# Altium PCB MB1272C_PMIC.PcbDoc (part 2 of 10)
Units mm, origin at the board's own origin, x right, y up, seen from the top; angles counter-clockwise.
Board outline 101 x 71 mm, 6 copper layers (Top Layer, Signal Layer 1, Signal Layer 2, Signal Layer 3, Signal Layer 4, Bottom Layer), stack 1.552 mm thick; 518 components, 478 nets, 2152 pads, 1871 vias.
Unrouted connection lines stored in the file: 3.

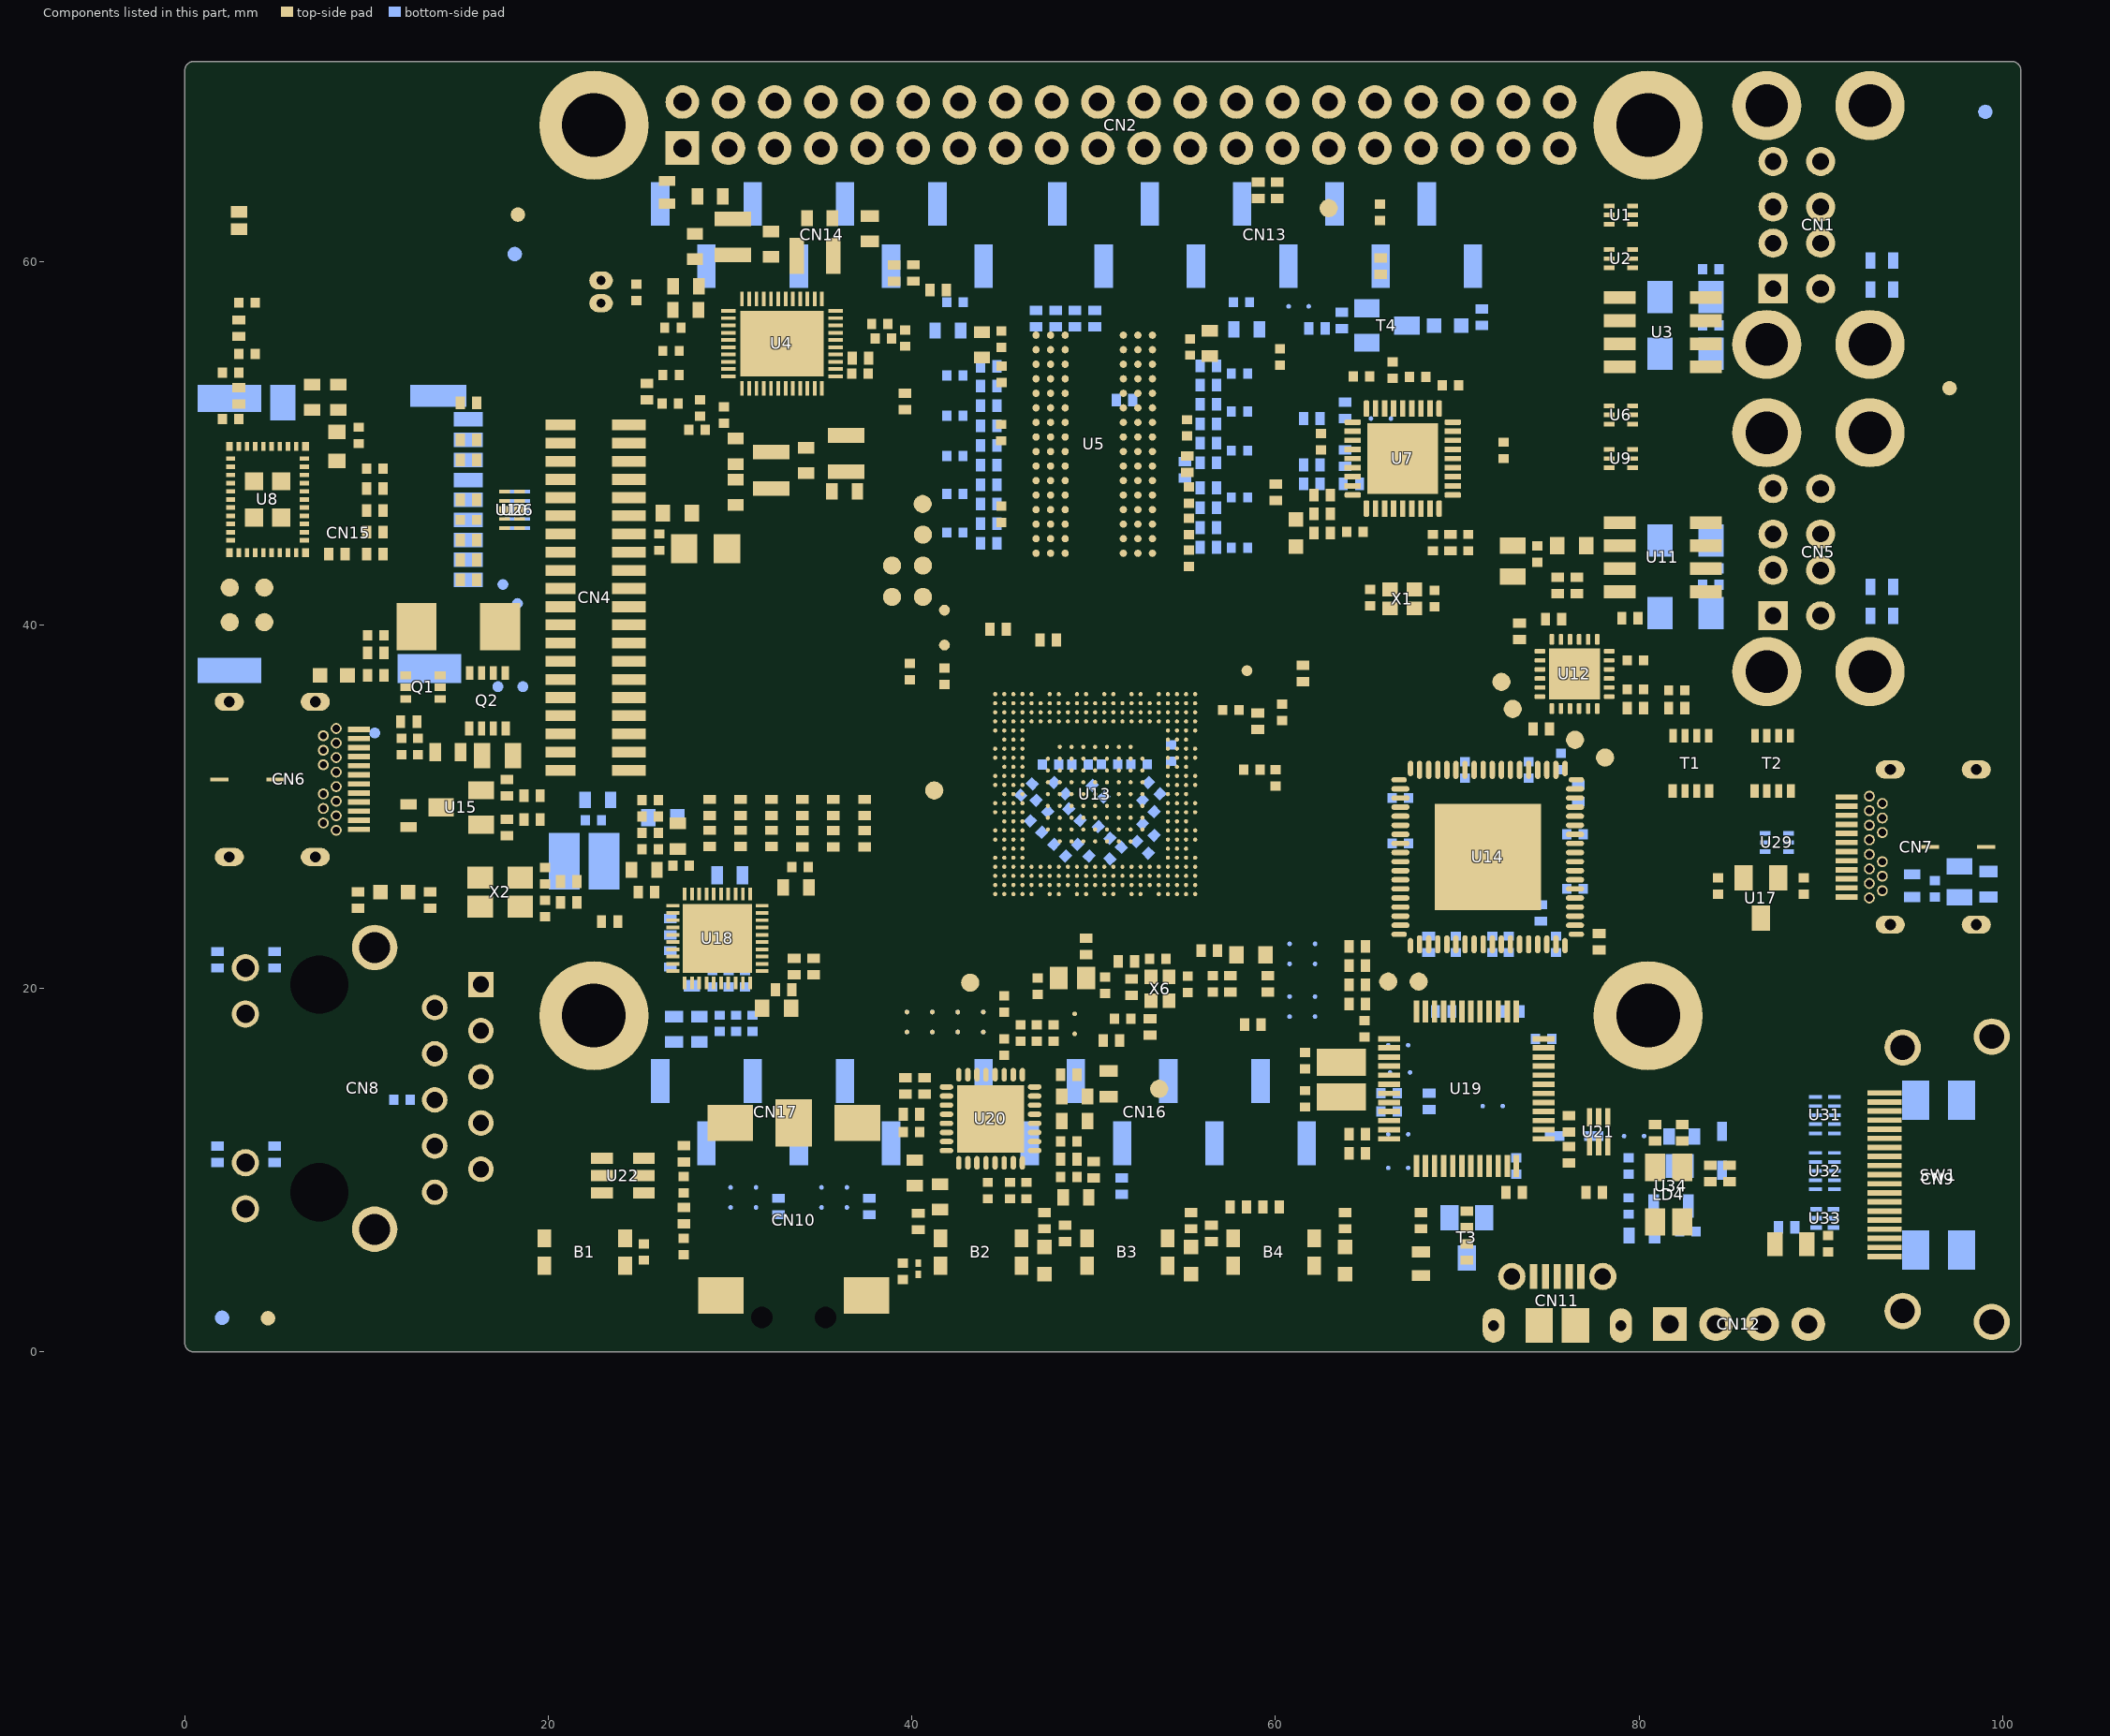
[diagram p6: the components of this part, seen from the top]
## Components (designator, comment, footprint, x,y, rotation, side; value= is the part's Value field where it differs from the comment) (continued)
U1 "​" ESD_QFN-6L_1P7X1P5_P050 79,62.55 r270 top value=ECMF02-2AMX6
U2 "​" ESD_QFN-6L_1P7X1P5_P050 79,60.15 r270 top value=ECMF02-2AMX6
U3 "STMPS2252MTR" ICC_SO8_5X4_P127 81.3,56.1 r270 top
U4 "STPMU1A" ICC_WFQFN44-EPAD_5X6_P040 32.85,55.475 r270 top
U5 "MT41K256M16TW-107:P - V00H" ICC_FBGA96_8X14_P080 50.03,49.94 r0 top locked value=MT41K256M16TW-107-P-V00H
U6 "​" ESD_QFN-6L_1P7X1P5_P050 79,51.55 r270 top value=ECMF02-2AMX6
U7 "USB2514B-AEZC" ICC_QFN36-EPAD_6X6_P050 67,49.15 r90 top
U8 "LBEE5KL1DX-883" MOD_WLAN-BT_MURATA_LBEE5KL1DX-883 4.55,46.9 r270 top locked
U9 "​" ESD_QFN-6L_1P7X1P5_P050 79,49.15 r270 top value=ECMF02-2AMX6
U10 "HSP051-4M10" ESD_UQFN-10L_2P5X1_P050 18,46.325 r90 top
U11 "STMPS2252MTR" ICC_SO8_5X4_P127 81.3,43.725 r270 top
U12 "​Symbol correction needed ?" ICC_QFN24-EPAD_4X4_P050 76.45,37.3 r270 top value=STUSB1600
U13 "STM32MP157CAC3" ICC_TFBGA361_12X12_STM32MP157CAC3_P050-065 50.08,30.69 r90 top locked
U14 "" ICC_QFN72-EPAD_10X10_P050 71.675,27.225 r270 top locked value=SiI9022ACNU
U15 "New schematic symbol : correction 2 diodes instead of one" ESD_SOT23 15.2,29.95 r90 top value=ESDA25L
U16 "​Footprint needed DFN105P160X60-2N" ESD_QFN1610_2N_1K_2A 12.3,29.5 r270 top value=ESDA7P120-1U1M
U17 "New schematic symbol : correction 2 diodes instead of one" ESD_SOT23 86.7,24.975 r180 top value=ESDA25L
U18 "RTL8211F-CG" ICC_QFN40-EPAD_5X5_P040 29.3,22.75 r90 top locked
U19 "" ICC_LQFP48_7X7_P050 70.5,14.475 r270 top locked value=STM32F103CBT6
U20 "" ICC_QFN32-EPAD_5X5_P050 44.325,12.825 r270 top value=CS42L51-CNZ
U21 "" ESD_SOT666 77.775,12.1 r0 top value=USBLC6-2P6
U22 "" ESD_SOT23-6L 24.1,9.7 r90 top value=ESDA6V1BC6
U23 "​Footprint needed DFN105P160X60-2N" ESD_QFN1610_2N_1K_2A 26.525,63.8 r270 top value=ESDA7P120-1U1M
U24 "​Footprint needed DFN105P160X60-2N" ESD_QFN1610_2N_1K_2A 93.35,60.05 r0 bottom value=ESDA7P120-1U1M
U25 "​Footprint needed DFN105P160X60-2N" ESD_QFN1610_2N_1K_2A 93.35,58.45 r0 bottom value=ESDA7P120-1U1M
U26 "HSP051-4M10" ESD_UQFN-10L_2P5X1_P050 18.3,46.325 r90 bottom
U27 "​Footprint needed DFN105P160X60-2N" ESD_QFN1610_2N_1K_2A 93.35,42.1 r0 bottom value=ESDA7P120-1U1M
U28 "​Footprint needed DFN105P160X60-2N" ESD_QFN1610_2N_1K_2A 93.35,40.5 r0 bottom value=ESDA7P120-1U1M
U29 "​" ESD_QFN-6L_1P7X1P5_P050 87.575,28.025 r90 bottom value=ECMF02-2AMX6
U30 "​Footprint needed DFN105P160X60-2N" ESD_QFN1610_2N_1K_2A 95.025,25.65 r90 bottom value=ESDA7P120-1U1M
U31 "" ESD_UQFN-10L_2P60X1P35_P050 90.225,13.025 r270 bottom value=ECMF04-4HSWM10
U32 "" ESD_UQFN-10L_2P60X1P35_P050 90.225,9.95 r270 bottom value=ECMF04-4HSWM10
U33 "ESDALC6V1-5M6" ESD_UQFN-6L_1P45X1_P050 90.225,7.35 r270 bottom
U34 "" REG_SOT23-5L 81.75,9.125 r0 bottom value=LD3985M33R
U35 "ESD-TRANSIL" ESD_ST0201 40.35,4.575 r270 top value=ESDALC6V1-1U2
X1 "XTAL_4_PINS" CRY_NX2016SA_4P 66.975,41.425 r180 top value="NX2016SA 24MHz"
X2 "XTAL_4_PINS" CRY_NX3225HA_4P 17.35,25.3 r180 top value="NX3225GA 25MHz"
X4 "XTAL_2_PINS" CRY_NX2012SA_2P 48.825,20.575 r0 top value="NX2012SA 32.768KHz"
X5 "" CRY_NX3225GD_2P 63.625,14.975 r90 top value="NX3225GD 8MHz"
X6 "OSCILLATOR_4_PINS" CRY_NZ2016SH_4P 53.65,19.975 r90 top value="NZ2016SH 24MHz"

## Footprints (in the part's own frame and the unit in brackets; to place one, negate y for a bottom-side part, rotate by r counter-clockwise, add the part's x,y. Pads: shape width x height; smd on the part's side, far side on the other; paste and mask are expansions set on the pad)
C0402 [mm]
  rect 0.51x0.56 smd mask+0.05: 1(-0.45,0) 2(0.45,0)
  silkscreen extent -0.72,-0.35 0.72,0.35, body extent -0.5,-0.3 0.5,0.3, height 0.4
C0603 [mm]
  rect 0.64x0.89 smd mask+0.05: 1(-0.7,0) 2(0.7,0)
  silkscreen extent -1.05,-0.55 1.02,0.55, body extent -0.9,-0.5 0.9,0.5, height 1.4
C0805 [mm]
  rect 0.9x1.4 smd mask+0.05: 1(-0.85,0) 2(0.85,0)
  silkscreen extent -1.3,-0.77 1.3,0.77, body extent -1.1,-0.7 1.1,0.7, height 1.35
C1206_H1P6 [mm]
  rect 1.4x1.78 smd mask+0.05: 1(-1.4,0) 2(1.4,0)
  silkscreen extent -2.12,-0.97 2.15,0.97, body extent -1.7,-0.9 1.7,0.9, height 1.8
CON_DUAL-USB-TYPE-A_CONEXCON_5600-3081 [mm]
  round 1.6 hole 0.92: B1(-3.5,13.01) B2(-1,13.01) B3(1,13.01) B4(3.5,13.01) T2(-1,15.63) T3(1,15.63) T4(3.5,15.63)
  round 3.8 hole 2.33: CH1(6.57,10.3) CH2(-6.57,10.3) CH3(-6.57,15.98) CH4(6.57,15.98)
  rect 1.6x1.6 hole 0.92: T1(-3.5,15.63)
  silkscreen extent -7.3,-0.4 7.3,17.85, body extent -7.83,-0.6 7.87,17.85, height 16.2
CON_HDMI_FCI-AMPHENOL_10029449-001RLF [mm]
  rect 0.3x1.9 smd mask+0.05: 1(4.75,8.5) 2(4.25,8.5) 3(3.75,8.5) 4(3.25,8.5) 5(2.75,8.5) 6(2.25,8.5) 7(1.75,8.5) 8(1.25,8.5) 9(0.75,8.5) 10(0.25,8.5) 11(-0.25,8.5) 12(-0.75,8.5) 13(-1.25,8.5) 14(-1.75,8.5) 15(-2.25,8.5) 16(-2.75,8.5) 17(-3.25,8.5) 18(-3.75,8.5) 19(-4.25,8.5)
  round 2 hole 1.35 mask+0.1: 20(7.25,7.5) 21(-7.25,7.5) 22(7.85,2.6) 23(-7.85,2.6)
  silkscreen extent -7.5,-1 7.5,8, body extent -8.1,-1 8.1,8.9, height 6.3
CON_JACK-3P5-SMT_LUMBERG_1503-13-VP3 [mm]
  rect 2.6x2 smd mask+0.05: 1(15.2,0)
  rect 2x2.5 smd mask+0.05: 2(15.2,3.5) 3(15.2,-3.5) 4(5.7,-4) 4(5.7,4)
  round 0.5 hole 1.2 unplated mask+0.1: NPTH1(4.5,-1.75) NPTH2(4.5,1.75)
  silkscreen extent 0,-3.55 14.6,3.55, body extent 0,-4.55 15.8,4.55, height 6.1
CON_MICROSD_YAMAICHI_PJS008-2003-0 [mm] "WITHOUT POSITIONNING PINS"
  rect 1.6x0.8 smd paste+0 mask+0.05: 1(-15.6,-2.525) 2(-15.6,-1.425) 3(-15.6,-0.325) 4(-15.6,0.775) 5(-15.6,1.875) 6(-15.6,2.975) 7(-15.6,4.075) 8(-15.6,5.175) 9(-15.6,6.325)
  rect 1.4x1.95 smd paste+0 mask+0.05: 10(-5.4,7.225)
  rect 3.5x1.5 smd paste+0 mask+0.05: 11(-2.45,7.45)
  rect 3.5x1.4 smd paste+0 mask+0.05: 12(-2.45,-7.5)
  rect 3.5x1.6 smd paste+0 mask+0.05: 13(-13.45,-7.4)
  rect 3.1x1.2 smd paste+0 mask+0.05: 14(-13.95,7.6)
  silkscreen extent -15.32,-7.25 5.65,7.25, body extent -15.25,-7.25 -0.45,7.42, height 2
CON_MOLEX_53047-0210 [mm]
  oval 1x1.3 hole 0.5 mask+0.05: 1(-0.625,0) 2(0.625,0)
  silkscreen extent -2.12,-1.15 2.13,2.05, body extent -2.13,-1.15 2.13,2.05, height 4.2
CON_RJ45_YD_48F-01GYDXNL_LED-P [mm]
  rect 1.4x1.4 hole 0.9 mask+0.05: 1(-5.715,16.29)
  round 1.4 hole 0.9 mask+0.05: 2(-4.445,13.75) 3(-3.175,16.29) 4(-1.905,13.75) 5(-0.635,16.29) 6(0.635,13.75) 7(1.905,16.29) 8(3.175,13.75) 9(4.445,16.29) 10(5.715,13.75)
  round 1.5 hole 1 mask+0.05: 11(-6.63,3.34) 12(-4.09,3.34) 13(4.09,3.34) 14(6.63,3.34)
  round 2.5 hole 1.7 mask+0.05: 15(7.75,10.45) 16(-7.75,10.45)
  round 1 hole 3.2 unplated mask+0.1: 17(-5.715,7.4) 18(5.715,7.4)
  Multi-Layer keep-out circle w0.01: c5.715,7.4 r1.9
  Multi-Layer keep-out circle w0.01: c-5.715,7.4 r1.9
  silkscreen extent -11.26,-3.5 11.26,18.34, body extent -11.4,-3.5 11.39,18.34, height 17
CON_SAMTEC_SSW-106-22-X-S-VS [mil]
  rect 40x95 smd mask+1.97: 1(250,67.5) 2(150,-67.5) 3(50,67.5) 4(-50,-67.5) 5(-150,67.5) 6(-250,-67.5)
  silkscreen extent -310,-48 310,48, body extent -310,-101 310,102, height 385
CON_SAMTEC_SSW-108-22-X-S-VS [mil]
  rect 40x95 smd mask+1.97: 1(350,67.5) 2(250,-67.5) 3(150,67.5) 4(50,-67.5) 5(-50,67.5) 6(-150,-67.5) 7(-250,67.48) 8(-350,-67.48)
  silkscreen extent -410,-48 410,48, body extent -410,-101 410,102, height 385
CON_SAMTEC_SSW-110-22-X-S-VS [mil]
  rect 40x95 smd mask+1.97: 1(450,67.5) 2(350,-67.5) 3(250,67.5) 4(150,-67.5) 5(50,67.5) 6(-50,-67.5) 7(-150,67.48) 8(-250,-67.48) 9(-350,67.48) 10(-450,-67.48)
  silkscreen extent -510,-48 510,48, body extent -510,-101 510,102, height 385
CON_SAMTEC_TSW-104-07-G-S [mm]
  rect 1.85x1.85 / inner round 1.85 / far side rect 1.85x1.85 hole 1 mask+0.05: 1(-3.81,0)
  round 1.85 hole 1 mask+0.05: 2(-1.27,0) 3(1.27,0) 4(3.81,0)
  silkscreen extent -5.12,-1.3 5.12,1.3, body extent -5.21,-1.37 5.18,1.37, height 8.38
CON_SAMTEC_TSW-120-07-G-D [mm]
  rect 1.85x1.85 / inner round 1.85 / far side rect 1.85x1.85 hole 1 mask+0.05: 1(-24.13,-1.27)
  round 1.85 hole 1 mask+0.05: 2(-24.13,1.27) 3(-21.59,-1.27) 4(-21.59,1.27) 5(-19.05,-1.27) 6(-19.05,1.27) 7(-16.51,-1.27) 8(-16.51,1.27) 9(-13.97,-1.27) 10(-13.97,1.27) 11(-11.43,-1.27) 12(-11.43,1.27) 13(-8.89,-1.27) 14(-8.89,1.27) 15(-6.35,-1.27) 16(-6.35,1.27) 17(-3.81,-1.27) 18(-3.81,1.27) 19(-1.27,-1.27) 20(-1.27,1.27) 21(1.27,-1.27) 22(1.27,1.27) 23(3.81,-1.27) 24(3.81,1.27) 25(6.35,-1.27) 26(6.35,1.27) 27(8.89,-1.27) 28(8.89,1.27) 29(11.43,-1.27) 30(11.43,1.27) 31(13.97,-1.27) 32(13.97,1.27) 33(16.51,-1.27) 34(16.51,1.27) 35(19.05,-1.27) 36(19.05,1.27) 37(21.59,-1.27) 38(21.59,1.27) 39(24.13,-1.27) 40(24.13,1.27)
  silkscreen extent -25.4,-2.54 25.4,2.54, body extent -25.4,-2.55 25.4,2.54, height 8.38
CON_TE-CONNECTIVITY_2-1734248-0 [mm]
  rect 0.6x1.65 smd mask+0.05: 1(9.5,-1.825) 2(8.5,-1.825) 3(7.5,-1.825) 4(6.5,-1.825) 5(5.5,-1.825) 6(4.5,-1.825) 7(3.5,-1.825) 8(2.5,-1.825) 9(1.5,-1.825) 10(0.5,-1.825) 11(-0.5,-1.825) 12(-1.5,-1.825) 13(-2.5,-1.825) 14(-3.5,-1.825) 15(-4.5,-1.825) 16(-5.5,-1.825) 17(-6.5,-1.825) 18(-7.5,-1.825) 19(-8.5,-1.825) 20(-9.5,-1.825)
  rect 0.6x1.85 smd mask+0.05: 1(9.5,1.925) 2(8.5,1.925) 3(7.5,1.925) 4(6.5,1.925) 5(5.5,1.925) 6(4.5,1.925) 7(3.5,1.925) 8(2.5,1.925) 9(1.5,1.925) 10(0.5,1.925) 11(-0.5,1.925) 12(-1.5,1.925) 13(-2.5,1.925) 14(-3.5,1.925) 15(-4.5,1.925) 16(-5.5,1.925) 17(-6.5,1.925) 18(-7.5,1.925) 19(-8.5,1.925) 20(-9.5,1.925)
  silkscreen extent -13.7,-2.8 13.7,1.9, body extent -13.7,-2.65 13.7,2.4, height 7.7
CON_USB-TYPEC_COXOC_317JD24BZTF3K3C3 [mm]
  rect 0.2x1 smd paste-10 mask+0: 0(0,6) 0(0,2.9)
  rect 0.3x1.2 smd mask+0.05: A1(-2.75,10.58) A2(-2.25,10.58) A3(-1.75,10.58) A4(-1.25,10.58) A5(-0.75,10.58) A6(-0.25,10.58) A7(0.25,10.58) A8(0.75,10.58) A9(1.25,10.58) A10(1.75,10.58) A11(2.25,10.58) A12(2.75,10.58)
  round 0.6 hole 0.4 mask+0.05: B1(2,9.33) B1(2.8,9.33) B2(2.4,8.62) B3(1.6,8.62) B4(1.2,9.33) B5(0.8,8.62) B6(0.4,9.33) B7(-0.4,9.33) B8(-0.8,8.62) B9(-1.2,9.33) B10(-1.6,8.62) B11(-2.4,8.62) B12(-2.8,9.33) B12(-2,9.33)
  oval 1x1.6 hole 0.6 slot 1.2 at 90 deg mask+0.05: SH1(-4.27,8.18) SH2(-4.27,3.45) SH3(4.27,8.18) SH4(4.27,3.45)
  silkscreen extent -4.38,-0.95 4.38,10.38, body extent -4.38,-0.95 4.38,10.84, height 3.03
CON_USBMICROB_MOLEX_105017-0001_H2P90 [mm]
  rect 0.4x1.35 smd mask+0.05: 1(-1.3,4.15) 2(-0.65,4.15) 3(0,4.15) 4(0.65,4.15) 5(1.3,4.15)
  round 1.5 hole 0.9 mask+0.05: 6(-2.5,4.15) 7(2.5,4.15)
  oval 1.2x1.9 hole 0.6 slot 1.3 at 90 deg mask+0.05: 8(3.5,1.45) 9(-3.5,1.45)
  rect 1.5x1.9 smd mask+0.05: 10(-1,1.45) 11(1,1.45)
  Top Layer region: 2.3,2.4 3.5,2.4 3.5,0.5 2.3,0.5 2.3,2.4
  Top Layer region: -3.5,2.4 -2.3,2.4 -2.3,0.5 -3.5,0.5 -3.5,2.4
  silkscreen extent -4,-0.7 4,4.6, body extent -4.1,-1.15 4.1,4.66, height 2.9
CPOL_TAJ-A_1206_H180 [mm]
  rect 1.45x1.6 smd mask+0.05: 1(-1.175,0) 2(1.175,0)
  silkscreen extent -2.15,-1.05 1.7,1.05, body extent -1.7,-0.9 1.7,0.9, height 1.8
CPOL_TAJ-C_2312_H2P6 [mm]
  rect 2.2x2.6 smd mask+0.05: 1(-2.3,0) 2(2.3,0)
  silkscreen extent -3.6,-1.85 3.1,1.85, body extent -3.1,-1.7 3.1,1.7, height 2.8
CRY_NX2012SA_2P [mm]
  rect 1x1.25 smd mask+0.05: 1(-0.75,0) 2(0.75,0)
  silkscreen extent -1.05,-0.75 1.05,0.75, body extent -1.05,-0.63 1.05,0.63, height 0.6
CRY_NX2016SA_4P [mm]
  rect 0.85x0.75 smd mask+0.05: 1(-0.675,-0.525) 2(0.675,-0.525) 3(0.675,0.525) 4(-0.675,0.525)
  silkscreen extent -1.22,-1.02 1.05,0.85, body extent -1.05,-0.85 1.05,0.85, height 0.7
CRY_NX3225GD_2P [mm]
  rect 1.5x2.7 smd mask+0.05: 1(-0.95,0) 2(0.95,0)
  silkscreen extent -0.1,-1.3 0.1,1.3, body extent -1.65,-1.3 1.65,1.3, height 1
CRY_NX3225HA_4P [mm]
  rect 1.4x1.2 smd mask+0.05: 1(-1.1,-0.8) 2(1.1,-0.8) 3(1.1,0.8) 4(-1.1,0.8)
  silkscreen extent -1.9,-1.5 1.65,1.3, body extent -1.66,-1.31 1.66,1.31, height 0.91
CRY_NZ2016SH_4P [mm] "MCD-01627"
  rect 0.8x0.7 smd mask+0.05: 1(-0.65,-0.5) 2(0.65,-0.5) 3(0.65,0.5) 4(-0.65,0.5)
  silkscreen extent -1.17,-0.97 1.05,0.85, body extent -1.05,-0.85 1.05,0.85, height 0.71
DIO_SOD323 [mm]
  rect 1.06x0.54 smd mask+0.05: 1(-1.07,0) 2(1.07,0)
  silkscreen extent -0.9,-0.72 0.9,0.72, body extent -1.3,-0.78 1.3,0.78, height 1.17
DIO_SOT363 [mm]
  rect 0.42x0.6 smd mask+0.05: 1(-0.65,-0.95) 2(0,-0.95) 3(0.65,-0.95) 4(0.65,0.95) 5(0,0.95) 6(-0.65,0.95)
  silkscreen extent -1.1,-0.67 1.1,0.67, body extent -1.1,-1.2 1.1,1.2, height 1.1
ESD_QFN1610_2N_1K_2A [mm] "DFN, 2-Leads, Body 1.60x1.00mm"
  rect 0.55x0.9 smd mask+0.05: 1(-0.625,0) 2(0.625,0)
  silkscreen extent -1.02,-0.58 0.85,0.58, body extent -0.85,-0.55 0.85,0.55, height 0.6
ESD_QFN-6L_1P7X1P5_P050 [mm]
  rect 0.25x0.6 smd mask+0.05: 1(-0.5,-0.65) 2(0,-0.65) 3(0.5,-0.65) 4(0.5,0.65) 5(0,0.65) 6(-0.5,0.65)
  silkscreen extent -0.9,-0.8 0.9,0.8, body extent -0.9,-0.8 0.9,0.8, height 0.56
ESD_SOT23 [mm]
  rect 1x1.4 smd mask+0.05: 1(-0.95,-1.1) 2(0.95,-1.1) 3(0,1.1)
  silkscreen extent -1.63,-0.82 1.63,0.82, body extent -1.56,-1.5 1.56,1.5, height 1.4
ESD_SOT23-6L [mm]
  rect 0.6x1.2 smd mask+0.05: 1(-0.95,-1.15) 2(0,-1.15) 3(0.95,-1.15) 4(0.95,1.15) 5(0,1.15) 6(-0.95,1.15)
  silkscreen extent -1.53,-0.87 1.53,0.87, body extent -1.52,-1.5 1.52,1.5, height 1.45
ESD_SOT666 [mm]
  rect 0.3x0.99 smd mask+0.05: 1(-0.5,-0.805) 2(0,-0.805) 3(0.5,-0.805) 4(0.5,0.805) 5(0,0.805) 6(-0.5,0.805)
  silkscreen extent -0.85,-0.65 0.85,0.65, body extent -0.85,-0.8 0.85,0.8, height 0.6
ESD_ST0201 [mm]
  rect 0.425x0.33 smd mask+0.05: 1(-0.312,0) 2(0.312,0)
  silkscreen extent -0.55,-0.3 0.33,0.3, body extent -0.34,-0.18 0.34,0.18, height 0.34
ESD_UQFN-6L_1P45X1_P050 [mm]
  rect 0.25x0.65 smd mask+0.05: 1(-0.5,-0.475) 2(0,-0.475) 3(0.5,-0.475) 4(0.5,0.475) 5(0,0.475) 6(-0.5,0.475)
  silkscreen extent -0.9,-0.87 0.77,0.55, body extent -0.77,-0.55 0.77,0.55, height 0.66
ESD_UQFN-10L_2P5X1_P050 [mm]
  rect 0.2x0.58 smd mask+0.05: 1(-1,-0.41) 2(-0.5,-0.41) 4(0.5,-0.41) 5(1,-0.41) 6(1,0.41) 7(0.5,0.41) 9(-0.5,0.41) 10(-1,0.41)
  rect 0.4x0.58 smd mask+0.05: 3(0,-0.41) 8(0,0.41)
  silkscreen extent -1.38,-0.63 1.38,0.63, body extent -1.3,-0.55 1.3,0.55, height 0.51
ESD_UQFN-10L_2P60X1P35_P050 [mm]
  rect 0.2x0.7 smd mask+0.05: 1(-1,-0.525) 2(-0.5,-0.525) 3(0,-0.525) 4(0.5,-0.525) 5(1,-0.525) 6(1,0.525) 7(0.5,0.525) 8(0,0.525) 9(-0.5,0.525) 10(-1,0.525)
  silkscreen extent -1.45,-0.95 1.33,0.7, body extent -1.33,-0.7 1.33,0.7, height 0.56
FIL_0603_H0P65 [mm]
  rect 0.8x0.95 smd mask+0.05: 1(-0.8,0) 2(0.8,0)
  silkscreen extent -1.33,-0.6 1.33,0.6, body extent -0.87,-0.47 0.87,0.47, height 0.65
ICC_FBGA96_8X14_P080 [mm]
  round 0.4 smd mask+0.05: A1(-3.2,6) A2(-2.4,6) A3(-1.6,6) A7(1.6,6) A8(2.4,6) A9(3.2,6) B1(-3.2,5.2) B2(-2.4,5.2) B3(-1.6,5.2) B7(1.6,5.2) B8(2.4,5.2) B9(3.2,5.2) C1(-3.2,4.4) C2(-2.4,4.4) C3(-1.6,4.4) C7(1.6,4.4) C8(2.4,4.4) C9(3.2,4.4) D1(-3.2,3.6) D2(-2.4,3.6) D3(-1.6,3.6) D7(1.6,3.6) D8(2.4,3.6) D9(3.2,3.6) E1(-3.2,2.8) E2(-2.4,2.8) E3(-1.6,2.8) E7(1.6,2.8) E8(2.4,2.8) E9(3.2,2.8) F1(-3.2,2) F2(-2.4,2) F3(-1.6,2) F7(1.6,2) F8(2.4,2) F9(3.2,2) G1(-3.2,1.2) G2(-2.4,1.2) G3(-1.6,1.2) G7(1.6,1.2) G8(2.4,1.2) G9(3.2,1.2) H1(-3.2,0.4) H2(-2.4,0.4) H3(-1.6,0.4) H7(1.6,0.4) H8(2.4,0.4) H9(3.2,0.4) J1(-3.2,-0.4) J2(-2.4,-0.4) J3(-1.6,-0.4) J7(1.6,-0.4) J8(2.4,-0.4) J9(3.2,-0.4) K1(-3.2,-1.2) K2(-2.4,-1.2) K3(-1.6,-1.2) K7(1.6,-1.2) K8(2.4,-1.2) K9(3.2,-1.2) L1(-3.2,-2) L2(-2.4,-2) L3(-1.6,-2) L7(1.6,-2) L8(2.4,-2) L9(3.2,-2) M1(-3.2,-2.8) M2(-2.4,-2.8) M3(-1.6,-2.8) M7(1.6,-2.8) M8(2.4,-2.8) M9(3.2,-2.8) N1(-3.2,-3.6) N2(-2.4,-3.6) N3(-1.6,-3.6) N7(1.6,-3.6) N8(2.4,-3.6) N9(3.2,-3.6) P1(-3.2,-4.4) P2(-2.4,-4.4) P3(-1.6,-4.4) P7(1.6,-4.4) P8(2.4,-4.4) P9(3.2,-4.4) R1(-3.2,-5.2) R2(-2.4,-5.2) R3(-1.6,-5.2) R7(1.6,-5.2) R8(2.4,-5.2) R9(3.2,-5.2) T1(-3.2,-6) T2(-2.4,-6) T3(-1.6,-6) T7(1.6,-6) T8(2.4,-6) T9(3.2,-6)
  silkscreen extent -4.2,-7.05 4.05,7.2, body extent -4.05,-7.05 4.05,7.05, height 1.2
ICC_LQFP48_7X7_P050 [mm]
  rect 0.3x1.2 smd mask+0.05: 1(-2.75,-4.25) 2(-2.25,-4.25) 3(-1.75,-4.25) 4(-1.25,-4.25) 5(-0.75,-4.25) 6(-0.25,-4.25) 7(0.25,-4.25) 8(0.75,-4.25) 9(1.25,-4.25) 10(1.75,-4.25) 11(2.25,-4.25) 12(2.75,-4.25) 25(2.75,4.25) 26(2.25,4.25) 27(1.75,4.25) 28(1.25,4.25) 29(0.75,4.25) 30(0.25,4.25) 31(-0.25,4.25) 32(-0.75,4.25) 33(-1.25,4.25) 34(-1.75,4.25) 35(-2.25,4.25) 36(-2.75,4.25)
  rect 1.2x0.3 smd mask+0.05: 13(4.25,-2.75) 14(4.25,-2.25) 15(4.25,-1.75) 16(4.25,-1.25) 17(4.25,-0.75) 18(4.25,-0.25) 19(4.25,0.25) 20(4.25,0.75) 21(4.25,1.25) 22(4.25,1.75) 23(4.25,2.25) 24(4.25,2.75) 37(-4.25,2.75) 38(-4.25,2.25) 39(-4.25,1.75) 40(-4.25,1.25) 41(-4.25,0.75) 42(-4.25,0.25) 43(-4.25,-0.25) 44(-4.25,-0.75) 45(-4.25,-1.25) 46(-4.25,-1.75) 47(-4.25,-2.25) 48(-4.25,-2.75)
  silkscreen extent -3.52,-3.52 3.52,3.52, body extent -4.5,-4.5 4.5,4.5, height 1.6
ICC_QFN24-EPAD_4X4_P050 [mm]
  rrect50% 0.6x0.25 smd mask+0.05: 1(-1.9,1.25) 2(-1.9,0.75) 3(-1.9,0.25) 4(-1.9,-0.25) 5(-1.9,-0.75) 6(-1.9,-1.25) 13(1.9,-1.25) 14(1.9,-0.75) 15(1.9,-0.25) 16(1.9,0.25) 17(1.9,0.75) 18(1.9,1.25)
  rrect50% 0.25x0.6 smd mask+0.05: 7(-1.25,-1.9) 8(-0.75,-1.9) 9(-0.25,-1.9) 10(0.25,-1.9) 11(0.75,-1.9) 12(1.25,-1.9) 19(1.25,1.9) 20(0.75,1.9) 21(0.25,1.9) 22(-0.25,1.9) 23(-0.75,1.9) 24(-1.25,1.9)
  rect 2.8x2.8 smd paste-10 mask+0.05: ep(0,0)
  silkscreen extent -2,-2 2,2, body extent -2.05,-2.05 2.05,2.05, height 1.1
ICC_QFN32-EPAD_5X5_P050 [mm]
  oval 0.3x0.75 smd mask+0.05: 1(-1.75,-2.425) 2(-1.25,-2.425) 3(-0.75,-2.425) 4(-0.25,-2.425) 5(0.25,-2.425) 6(0.75,-2.425) 7(1.25,-2.425) 8(1.75,-2.425) 17(1.75,2.425) 18(1.25,2.425) 19(0.75,2.425) 20(0.25,2.425) 21(-0.25,2.425) 22(-0.75,2.425) 23(-1.25,2.425) 24(-1.75,2.425)
  oval 0.75x0.3 smd mask+0.05: 9(2.425,-1.75) 10(2.425,-1.25) 11(2.425,-0.75) 12(2.425,-0.25) 13(2.425,0.25) 14(2.425,0.75) 15(2.425,1.25) 16(2.425,1.75) 25(-2.425,1.75) 26(-2.425,1.25) 27(-2.425,0.75) 28(-2.425,0.25) 29(-2.425,-0.25) 30(-2.425,-0.75) 31(-2.425,-1.25) 32(-2.425,-1.75)
  rect 3.7x3.7 smd mask+0.05: 33(0,0)
  silkscreen extent -2.63,-2.63 2.63,2.63, body extent -2.55,-2.55 2.55,2.55, height 1
ICC_QFN36-EPAD_6X6_P050 [mm]
  rrect50% 0.3x0.9 smd mask+0.05: 1(-2,-2.75) 9(2,-2.75) 19(2,2.75) 27(-2,2.75)
  rect 0.3x0.9 smd mask+0.05: 2(-1.5,-2.75) 3(-1,-2.75) 4(-0.5,-2.75) 5(0,-2.75) 6(0.5,-2.75) 7(1,-2.75) 8(1.5,-2.75) 20(1.5,2.75) 21(1,2.75) 22(0.5,2.75) 23(0,2.75) 24(-0.5,2.75) 25(-1,2.75) 26(-1.5,2.75)
  rrect50% 0.9x0.3 smd mask+0.05: 10(2.75,-2) 18(2.75,2) 28(-2.75,2) 36(-2.75,-2)
  rect 0.9x0.3 smd mask+0.05: 11(2.75,-1.5) 12(2.75,-1) 13(2.75,-0.5) 14(2.75,0) 15(2.75,0.5) 16(2.75,1) 17(2.75,1.5) 29(-2.75,1.5) 30(-2.75,1) 31(-2.75,0.5) 32(-2.75,0) 33(-2.75,-0.5) 34(-2.75,-1) 35(-2.75,-1.5)
  rect 3.9x3.9 smd mask+0.05: 37(0,0)
  silkscreen extent -3.15,-3.15 3.15,3.15, body extent -3.06,-3.06 3.06,3.06, height 1
ICC_QFN40-EPAD_5X5_P040 [mm]
  rect 0.7x0.2 smd mask+0.05: 1(-2.45,1.8) 2(-2.45,1.4) 3(-2.45,1) 4(-2.45,0.6) 5(-2.45,0.2) 6(-2.45,-0.2) 7(-2.45,-0.6) 8(-2.45,-1) 9(-2.45,-1.4) 10(-2.45,-1.8) 21(2.45,-1.8) 22(2.45,-1.4) 23(2.45,-1) 24(2.45,-0.6) 25(2.45,-0.2) 26(2.45,0.2) 27(2.45,0.6) 28(2.45,1) 29(2.45,1.4) 30(2.45,1.8)
  rect 0.2x0.7 smd mask+0.05: 11(-1.8,-2.45) 12(-1.4,-2.45) 13(-1,-2.45) 14(-0.6,-2.45) 15(-0.2,-2.45) 16(0.2,-2.45) 17(0.6,-2.45) 18(1,-2.45) 19(1.4,-2.45) 20(1.8,-2.45) 31(1.8,2.45) 32(1.4,2.45) 33(1,2.45) 34(0.6,2.45) 35(0.2,2.45) 36(-0.2,2.45) 37(-0.6,2.45) 38(-1,2.45) 39(-1.4,2.45) 40(-1.8,2.45)
  rect 3.8x3.8 smd mask+0.05: 41(0,0)
  silkscreen extent -2.5,-2.5 2.5,2.5, body extent -2.5,-2.5 2.5,2.5, height 0.91
ICC_QFN72-EPAD_10X10_P050 [mm]
  oval 0.85x0.3 smd mask+0.05: 1(-4.875,4.25) 18(-4.875,-4.25) 37(4.875,-4.25) 54(4.875,4.25)
  oval 1x0.3 smd mask+0.05: 2(-4.8,3.75) 3(-4.8,3.25) 4(-4.8,2.75) 5(-4.8,2.25) 6(-4.8,1.75) 7(-4.8,1.25) 8(-4.8,0.75) 9(-4.8,0.25) 10(-4.8,-0.25) 11(-4.8,-0.75) 12(-4.8,-1.25) 13(-4.8,-1.75) 14(-4.8,-2.25) 15(-4.8,-2.75) 16(-4.8,-3.25) 17(-4.8,-3.75) 38(4.8,-3.75) 39(4.8,-3.25) 40(4.8,-2.75) 41(4.8,-2.25) 42(4.8,-1.75) 43(4.8,-1.25) 44(4.8,-0.75) 45(4.8,-0.25) 46(4.8,0.25) 47(4.8,0.75) 48(4.8,1.25) 49(4.8,1.75) 50(4.8,2.25) 51(4.8,2.75) 52(4.8,3.25) 53(4.8,3.75)
  oval 0.3x0.85 smd mask+0.05: 19(-4.25,-4.875) 36(4.25,-4.875) 55(4.25,4.875) 72(-4.25,4.875)
  oval 0.3x1 smd mask+0.05: 20(-3.75,-4.8) 21(-3.25,-4.8) 22(-2.75,-4.8) 23(-2.25,-4.8) 24(-1.75,-4.8) 25(-1.25,-4.8) 26(-0.75,-4.8) 27(-0.25,-4.8) 28(0.25,-4.8) 29(0.75,-4.8) 30(1.25,-4.8) 31(1.75,-4.8) 32(2.25,-4.8) 33(2.75,-4.8) 34(3.25,-4.8) 35(3.75,-4.8) 56(3.75,4.8) 57(3.25,4.8) 58(2.75,4.8) 59(2.25,4.8) 60(1.75,4.8) 61(1.25,4.8) 62(0.75,4.8) 63(0.25,4.8) 64(-0.25,4.8) 65(-0.75,4.8) 66(-1.25,4.8) 67(-1.75,4.8) 68(-2.25,4.8) 69(-2.75,4.8) 70(-3.25,4.8) 71(-3.75,4.8)
  rect 5.85x5.85 smd mask+0.05: e-Pad(0,0)
  silkscreen extent -4.9,-4.9 4.9,4.9, body extent -5,-5 5,5, height 0.91
ICC_SO8_5X4_P127 [mm]
  rect 0.7x1.75 smd mask+0.05: 1(-1.905,-2.375) 2(-0.635,-2.375) 3(0.635,-2.375) 4(1.905,-2.375) 5(1.905,2.375) 6(0.635,2.375) 7(-0.635,2.375) 8(-1.905,2.375)
  silkscreen extent -2.58,-2 2.58,2, body extent -2.57,-3 2.57,3, height 1.75
ICC_TFBGA361_12X12_STM32MP157CAC3_P050-065 [mm] "IPC"
  round 0.23 smd mask+0.05: 1A2(-1.95,2.6) 1A3(-1.3,2.6) 1A4(-0.65,2.6) 1A5(0,2.6) 1A6(0.65,2.6) 1A7(1.3,2.6) 1A8(1.95,2.6) 1B1(-2.6,1.95) 1B2(-1.95,1.95) 1B3(-1.3,1.95) 1B4(-0.65,1.95) 1B5(0,1.95) 1B6(0.65,1.95) 1B7(1.3,1.95) 1B8(1.95,1.95) 1B9(2.6,1.95) 1C1(-2.6,1.3) 1C2(-1.95,1.3) 1C3(-1.3,1.3) 1C4(-0.65,1.3) 1C5(0,1.3) 1C6(0.65,1.3) 1C7(1.3,1.3) 1C8(1.95,1.3) 1C9(2.6,1.3) 1D1(-2.6,0.65) 1D2(-1.95,0.65) 1D3(-1.3,0.65) 1D4(-0.65,0.65) 1D5(0,0.65) 1D6(0.65,0.65) 1D7(1.3,0.65) 1D8(1.95,0.65) 1D9(2.6,0.65) 1E1(-2.6,0) 1E2(-1.95,0) 1E3(-1.3,0) 1E4(-0.65,0) 1E5(0,0) 1E6(0.65,0) 1E7(1.3,0) 1E8(1.95,0) 1E9(2.6,0) 1F1(-2.6,-0.65) 1F2(-1.95,-0.65) 1F3(-1.3,-0.65) 1F4(-0.65,-0.65) 1F5(0,-0.65) 1F6(0.65,-0.65) 1F7(1.3,-0.65) 1F8(1.95,-0.65) 1F9(2.6,-0.65) 1G1(-2.6,-1.3) 1G2(-1.95,-1.3) 1G3(-1.3,-1.3) 1G4(-0.65,-1.3) 1G5(0,-1.3) 1G6(0.65,-1.3) 1G7(1.3,-1.3) 1G8(1.95,-1.3) 1G9(2.6,-1.3) 1H1(-2.6,-1.95) 1H2(-1.95,-1.95) 1H3(-1.3,-1.95) 1H4(-0.65,-1.95) 1H5(0,-1.95) 1H6(0.65,-1.95) 1H7(1.3,-1.95) 1H8(1.95,-1.95) 1H9(2.6,-1.95) 1J2(-1.95,-2.6) 1J3(-1.3,-2.6) 1J4(-0.65,-2.6) 1J5(0,-2.6) 1J6(0.65,-2.6) 1J7(1.3,-2.6) 1J8(1.95,-2.6) A1(-5.5,5.5) A2(-5,5.5) A3(-4.5,5.5) A4(-4,5.5) A5(-3.5,5.5) A7(-2.5,5.5) A8(-2,5.5) A10(-1,5.5) A11(-0.5,5.5) A13(0.5,5.5) A14(1,5.5) A16(2,5.5) A17(2.5,5.5) A19(3.5,5.5) A20(4,5.5) A21(4.5,5.5) A22(5,5.5) A23(5.5,5.5) AA1(-5.5,-4.5) AA2(-5,-4.5) AA3(-4.5,-4.5) AA4(-4,-4.5) AA5(-3.5,-4.5) AA6(-3,-4.5) AA7(-2.5,-4.5) AA8(-2,-4.5) AA9(-1.5,-4.5) AA10(-1,-4.5) AA11(-0.5,-4.5) AA12(0,-4.5) AA13(0.5,-4.5) AA14(1,-4.5) AA15(1.5,-4.5) AA16(2,-4.5) AA17(2.5,-4.5) AA18(3,-4.5) AA19(3.5,-4.5) AA20(4,-4.5) AA21(4.5,-4.5) AA22(5,-4.5) AA23(5.5,-4.5) AB1(-5.5,-5) AB2(-5,-5) AB3(-4.5,-5) AB4(-4,-5) AB5(-3.5,-5) AB6(-3,-5) AB7(-2.5,-5) AB8(-2,-5) AB9(-1.5,-5) AB10(-1,-5) AB11(-0.5,-5) AB12(0,-5) AB13(0.5,-5) AB14(1,-5) AB15(1.5,-5) AB16(2,-5) AB17(2.5,-5) AB18(3,-5) AB19(3.5,-5) AB20(4,-5) AB21(4.5,-5) AB22(5,-5) AB23(5.5,-5) AC1(-5.5,-5.5) AC2(-5,-5.5) AC3(-4.5,-5.5) AC4(-4,-5.5) AC5(-3.5,-5.5) AC7(-2.5,-5.5) AC8(-2,-5.5) AC10(-1,-5.5) AC11(-0.5,-5.5) AC13(0.5,-5.5) AC14(1,-5.5) AC16(2,-5.5) AC17(2.5,-5.5) AC19(3.5,-5.5) AC20(4,-5.5) AC21(4.5,-5.5) AC22(5,-5.5) AC23(5.5,-5.5) B1(-5.5,5) B2(-5,5) B3(-4.5,5) B4(-4,5) B5(-3.5,5) B6(-3,5) B7(-2.5,5) B8(-2,5) B9(-1.5,5) B10(-1,5) B11(-0.5,5) B12(0,5) B13(0.5,5) B14(1,5) B15(1.5,5) B16(2,5) B17(2.5,5) B18(3,5) B19(3.5,5) B20(4,5) B21(4.5,5) B22(5,5) B23(5.5,5) C1(-5.5,4.5) C2(-5,4.5) C3(-4.5,4.5) C4(-4,4.5) C5(-3.5,4.5) C6(-3,4.5) C7(-2.5,4.5) C8(-2,4.5) C9(-1.5,4.5) C10(-1,4.5) C11(-0.5,4.5) C12(0,4.5) C13(0.5,4.5) C14(1,4.5) C15(1.5,4.5) C16(2,4.5) C17(2.5,4.5) C18(3,4.5) C19(3.5,4.5) C20(4,4.5) C21(4.5,4.5) C22(5,4.5) C23(5.5,4.5) D1(-5.5,4) D2(-5,4) D3(-4.5,4) D4(-4,4) D5(-3.5,4) D6(-3,4) D7(-2.5,4) D8(-2,4) D9(-1.5,4) D10(-1,4) D11(-0.5,4) D12(0,4) D13(0.5,4) D14(1,4) D15(1.5,4) D16(2,4) D17(2.5,4) D18(3,4) D19(3.5,4) D20(4,4) D21(4.5,4) D22(5,4) D23(5.5,4) E1(-5.5,3.5) E2(-5,3.5) E3(-4.5,3.5) E4(-4,3.5) E20(4,3.5) E21(4.5,3.5) E22(5,3.5) E23(5.5,3.5) F2(-5,3) F3(-4.5,3) F4(-4,3) F20(4,3) F21(4.5,3) F22(5,3) G1(-5.5,2.5) G2(-5,2.5) G3(-4.5,2.5) G4(-4,2.5) G20(4,2.5) G21(4.5,2.5) G22(5,2.5) G23(5.5,2.5) H1(-5.5,2) H2(-5,2) H3(-4.5,2) H4(-4,2) H20(4,2) H21(4.5,2) H22(5,2) H23(5.5,2) J2(-5,1.5) J3(-4.5,1.5) J4(-4,1.5) J20(4,1.5) J21(4.5,1.5) J22(5,1.5) K1(-5.5,1) K2(-5,1) K3(-4.5,1) K4(-4,1) K20(4,1) K21(4.5,1) K22(5,1) K23(5.5,1) L1(-5.5,0.5) L2(-5,0.5) L3(-4.5,0.5) L4(-4,0.5) L20(4,0.5) L21(4.5,0.5) L22(5,0.5) L23(5.5,0.5) M2(-5,0) M3(-4.5,0) M4(-4,0) M20(4,0) M21(4.5,0) M22(5,0) N1(-5.5,-0.5) N2(-5,-0.5) N3(-4.5,-0.5) N4(-4,-0.5) N20(4,-0.5) N21(4.5,-0.5) N22(5,-0.5) N23(5.5,-0.5) P1(-5.5,-1) P2(-5,-1) P3(-4.5,-1) P4(-4,-1) P20(4,-1) P21(4.5,-1) P22(5,-1) P23(5.5,-1) R2(-5,-1.5) R3(-4.5,-1.5) R4(-4,-1.5) R20(4,-1.5) R21(4.5,-1.5) R22(5,-1.5) T1(-5.5,-2) T2(-5,-2) T3(-4.5,-2) T4(-4,-2) T20(4,-2) T21(4.5,-2) T22(5,-2) T23(5.5,-2) U1(-5.5,-2.5) U2(-5,-2.5) U3(-4.5,-2.5) U4(-4,-2.5) U20(4,-2.5) U21(4.5,-2.5) U22(5,-2.5) U23(5.5,-2.5) V2(-5,-3) V3(-4.5,-3) V4(-4,-3) V20(4,-3) V21(4.5,-3) V22(5,-3) W1(-5.5,-3.5) W2(-5,-3.5) W3(-4.5,-3.5) W4(-4,-3.5) W20(4,-3.5) W21(4.5,-3.5) W22(5,-3.5) W23(5.5,-3.5) Y1(-5.5,-4) Y2(-5,-4) Y3(-4.5,-4) Y4(-4,-4) Y5(-3.5,-4) Y6(-3,-4) Y7(-2.5,-4) Y8(-2,-4) Y9(-1.5,-4) Y10(-1,-4) Y11(-0.5,-4) Y12(0,-4) Y13(0.5,-4) Y14(1,-4) Y15(1.5,-4) Y16(2,-4) Y17(2.5,-4) Y18(3,-4) Y19(3.5,-4) Y20(4,-4) Y21(4.5,-4) Y22(5,-4) Y23(5.5,-4)
  silkscreen extent -6.25,-6.07 6.07,6.25, body extent -6.07,-6.07 6.07,6.07, height 1.21
ICC_WFQFN44-EPAD_5X6_P040 [mm]
  rect 0.8x0.2 smd mask+0.05: 1(-2.45,2.2) 2(-2.45,1.8) 3(-2.45,1.4) 4(-2.45,1) 5(-2.45,0.6) 6(-2.45,0.2) 7(-2.45,-0.2) 8(-2.45,-0.6) 9(-2.45,-1) 10(-2.45,-1.4) 11(-2.45,-1.8) 12(-2.45,-2.2) 23(2.45,-2.2) 24(2.45,-1.8) 25(2.45,-1.4) 26(2.45,-1) 27(2.45,-0.6) 28(2.45,-0.2) 29(2.45,0.2) 30(2.45,0.6) 31(2.45,1) 32(2.45,1.4) 33(2.45,1.8) 34(2.45,2.2)
  rect 0.2x0.8 smd mask+0.05: 13(-1.8,-2.95) 14(-1.4,-2.95) 15(-1,-2.95) 16(-0.6,-2.95) 17(-0.2,-2.95) 18(0.2,-2.95) 19(0.6,-2.95) 20(1,-2.95) 21(1.4,-2.95) 22(1.8,-2.95) 35(1.8,2.95) 36(1.4,2.95) 37(1,2.95) 38(0.6,2.95) 39(0.2,2.95) 40(-0.2,2.95) 41(-0.6,2.95) 42(-1,2.95) 43(-1.4,2.95) 44(-1.8,2.95)
  rect 3.6x4.6 smd paste-1.8 mask+0.05: ep(0,0)
  silkscreen extent -2.5,-3 2.5,3, body extent -2.5,-3 2.5,3, height 0.81
IND_0402_MURATA_LQW15AN2N4C00X [mm]
  rect 0.65x0.9 smd mask+0.05: 1(-0.475,0) 2(0.475,0)
  silkscreen extent -0.05,-0.35 0.05,0.35, body extent -0.55,-0.35 0.55,0.35, height 0.6
IND_2520_TOKO_DFE252012P [mm]
  rect 0.8x2 smd mask+0.05: 1(-1,0) 2(1,0)
  silkscreen extent -1.35,-1.12 1.35,1.12, body extent -1.35,-1.1 1.35,1.1, height 2
L0603 [mm]
  rect 0.8x0.95 smd mask+0.05: 1(-0.8,0) 2(0.8,0)
  silkscreen extent -1.33,-0.6 1.33,0.6, body extent -0.87,-0.47 0.87,0.47, height 0.95
L1210_LQH [mm]
  rect 1.7x3.1 smd mask+0.05: 1(-1.1,0) 2(1.1,0)
  silkscreen extent -2.05,-1.65 2.05,1.65, body extent -1.75,-1.35 1.75,1.35, height 2
LED_0603_GREEN [mm]
  rect 0.8x0.8 smd mask+0.05: 1(-0.75,0) 2(0.75,0)
  silkscreen extent -0.25,-0.4 1.25,0.4, body extent -0.8,-0.4 0.8,0.4, height 0.6
LED_0603_ORANGE_H0P4 [mm]
  rect 0.8x0.8 smd mask+0.05: 1(-0.75,0) 2(0.75,0)
  silkscreen extent -0.25,-0.4 1.25,0.4, body extent -0.8,-0.4 0.79,0.4, height 0.4
LED_0603_RED [mm]
  rect 0.8x0.8 smd mask+0.05: 1(-0.75,0) 2(0.75,0)
  silkscreen extent -0.25,-0.4 1.25,0.4, body extent -0.8,-0.4 0.8,0.4, height 0.6
LED_0603_SMD-B_BLUE_H0P4 [mm]
  rect 0.6x1 smd mask+0.05: 1(-0.65,0) 2(0.65,0)
  silkscreen extent -0.23,-0.45 1.07,0.45, body extent -0.85,-0.45 0.85,0.45, height 0.5
LED_BI-GR_HSMF-A201-A00J1 [mm]
  rect 1.1x1.5 smd mask+0.05: 1(-0.75,-1.5) 2(-0.75,1.5) 3(0.75,1.5) 4(0.75,-1.5)
  silkscreen extent -1.65,-1.85 1.65,1.85, body extent -1.5,-1.85 1.5,1.85, height 2.1
LINK200#1 [mm]
  rect 0.2x0.35 on Mid4 paste-10 mask+0.05: 1(0,-0.225) 2(0,0.225)
LINK200#2 [mm]
  rect 0.2x0.35 on Mid3 paste-10 mask+0.05: 1(0,-0.225) 2(0,0.225)
MIRE_PLACE_SMD_0P8MM [mm]
  round 0.8 smd paste-10 mask+0.2: 1(0,0)
  Top Layer keep-out circle w0.01: c0,0 r0.804
MOD_WLAN-BT_MURATA_LBEE5KL1DX-883 [mm]
  rect 0.25x0.5 smd mask+0.05: 1(-2.25,-2.025) 2(-1.8,-2.025) 3(-1.35,-2.025) 4(-0.9,-2.025) 5(-0.45,-2.025) 6(0,-2.025) 7(0.45,-2.025) 8(0.9,-2.025) 9(1.35,-2.025) 10(1.8,-2.025) 11(2.25,-2.025) 22(2.25,2.025) 23(1.8,2.025) 24(1.35,2.025) 25(0.9,2.025) 26(0.45,2.025) 27(0,2.025) 28(-0.45,2.025) 29(-0.9,2.025) 30(-1.35,2.025) 31(-1.8,2.025) 32(-2.25,2.025)
  rect 0.5x0.375 smd mask+0.05: 12(2.925,-2.087) 21(2.925,2.087) 33(-2.925,2.087) 42(-2.925,-2.087)
  rect 0.5x0.25 smd mask+0.05: 13(2.925,-1.575) 14(2.925,-1.125) 15(2.925,-0.675) 16(2.925,-0.225) 17(2.925,0.225) 18(2.925,0.675) 19(2.925,1.125) 20(2.925,1.575) 34(-2.925,1.575) 35(-2.925,1.125) 36(-2.925,0.675) 37(-2.925,0.225) 38(-2.925,-0.225) 39(-2.925,-0.675) 40(-2.925,-1.125) 41(-2.925,-1.575)
  rect 1x1 smd mask+0.05: 43(-1,-0.75) 44(1,-0.75) 45(-1,0.75) 46(1,0.75)
  silkscreen extent -3.57,-2.68 3.57,2.68, body extent -3.57,-2.68 3.57,2.68, height 1.11
MOS_POWERFLAT_3P3X3P3_P065 [mm]
  rect 0.4x0.75 smd mask+0.05: 1(-0.975,-1.525) 2(-0.325,-1.525) 3(0.325,-1.525) 4(0.975,-1.525) 6(0.325,1.525) 7(-0.325,1.525)
  rect 0.45x0.75 smd mask+0.05: 5(1,1.525) 8(-1,1.525)
  Top Layer region: -1.755,0.2 -1.755,-0.2 -1.225,-0.2 -1.225,-0.5 1.225,-0.5 1.225,-0.2 1.755,-0.2 1.755,0.2 1.225,0.2 1.225,1.9 -1.225,1.9 -1.225,0.2
  silkscreen extent -1.63,-1.55 1.63,1.55, body extent -1.75,-1.75 1.75,1.75, height 0.91
NPN_SOT23 [mm]
  rect 1x1.4 smd mask+0.05: 1(-0.95,-1.1) 2(0.95,-1.1) 3(0,1.1)
  silkscreen extent -1.63,-0.82 1.63,0.82, body extent -1.56,-1.25 1.56,1.25, height 1.1
PTH_M1261-3005-N_3P5X6_M3_H14 [mm]
  round 6 hole 3.5 mask+0.05: 1(0,0)
  silkscreen extent -3.25,-3.25 3.25,3.25, body extent -2.5,-2.5 2.5,2.5, height 14
R0402 [mm]
  rect 0.51x0.7 smd mask+0.05: 1(-0.45,0) 2(0.45,0)
  silkscreen extent -0.72,-0.43 0.72,0.43, body extent -0.52,-0.3 0.52,0.3, height 0.4
R0603 [mm]
  rect 0.64x1 smd mask+0.05: 1(-0.7,0) 2(0.7,0)
  silkscreen extent -1.05,-0.58 1.05,0.58, body extent -0.9,-0.5 0.9,0.5, height 0.56
R0805 [mm]
  rect 0.85x1.3 smd mask+0.05: 1(-0.875,0) 2(0.875,0)
  silkscreen extent -0.33,-0.67 0.33,0.67, body extent -1.05,-0.68 1.05,0.68, height 0.65
REG_SOT23-5L [mm]
  rect 0.6x1.3 smd mask+0.05: 1(-0.95,-1.1) 2(0,-1.1) 3(0.95,-1.1) 4(0.95,1.1) 5(-0.95,1.1)
  silkscreen extent -1.6,-0.95 1.6,0.97, body extent -1.52,-1.25 1.52,1.25, height 1.1
SOLDER-BRIDGE_R0603-0R [mil]
  round 10 smd paste-393.7: 1(-19.68,0) 2(23.62,0)
  Top Layer region: -47.24,-19.68 -47.24,19.69 -15.75,19.69 3.94,0 -15.75,-19.68 -47.24,-19.68
  Top Layer region: -5.91,19.69 13.78,0 -5.91,-19.68 47.24,-19.68 47.24,19.69 -5.91,19.69
  silkscreen extent -50,-23 50,23, body extent -36,-20 36,20, height 22
SWI_C&K_SDA02H1SBD_2POS [mm]
  rect 1.5x2.15 smd mask+0.05: 1(-1.27,-4.125) 2(1.27,-4.125) 3(1.27,4.125) 4(-1.27,4.125)
  silkscreen extent -3.55,-3.75 3.55,3.75, body extent -3.53,-4.65 3.53,4.65, height 5.45
SWI_JIUBABA_C-TS-02H-2-5-B-V-T_R_BLUE [mm] "BLUE"
  rect 0.75x1 smd mask+0.05: 1(-2.225,0.75) 2(2.225,0.75) 3(-2.225,-0.75) 4(2.225,-0.75)
  silkscreen extent -1.85,-1.6 1.85,1.6, body extent -2.45,-1.6 2.45,1.6, height 2.6
SWI_JIUBABA_C-TS-02H-2-5-K-V-T_R_BLACK [mm] "BLACK"
  rect 0.75x1 smd mask+0.05: 1(-2.225,0.75) 2(2.225,0.75) 3(-2.225,-0.75) 4(2.225,-0.75)
  silkscreen extent -1.85,-1.6 1.85,1.6, body extent -2.45,-1.6 2.45,1.6, height 2.6
TP_SMD_0-6MM [mm]
  round 0.6 smd paste-10 mask+0.05: 1(0,0)
  silkscreen extent -0.5,-0.5 0.5,0.5
TP_SMD_1MM [mm]
  round 1 smd paste-10 mask+0.05: 1(0,0)
  silkscreen extent -0.7,-0.7 0.7,0.7

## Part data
B1 B3 B4: library part MCD-00172, "Switch HW SMD blue", Manufacturer=JIUBABA, Manufacturer_Part_Number="C-TS-02H-2.5-B-V-T/R BLUE"
B2: library part MCD-00171, "Switch HW SMD black", Manufacturer=JIUBABA, Manufacturer_Part_Number="C-TS-02H-2.5-K-V-T/R BLACK"
C1 C7 C14 C17 C22 C35 C36 C45 C46 C47 C48 C51 C57 C61 C68 C70 C74 C75 C77 C78 C79 C81 C93 C95 C96 C97 C103 C107 C119 C120 C125 C126 C127 C128 C129 C130 C131 C132 C134 C135 C139 C140 C141 C142 C149 C154 C157 C160 C164 C168 C169 C170 C171 C172 C174 C175 C176 C177 C178 C179 C181 C182 C183 C184 C186 C187 C188: library part MCD-00006, "Capacitor,100nF,16V,X7R,10%,0402", Alternate_Manufacturer=MURATA, Alternate_Manufacturer_Part_Number=GCM155R71C104KA55D, Manufacturer=YAGEO, Manufacturer_Part_Number=CC0402KRX7R7BB104, Package=C0402
C2 C3 C42 C44 C121 C122: library part MCD-00100, "Capacitor, MLCC, 22uF, 6V3, X5R, 20%, 0603, T=0,8mm", Manufacturer=MURATA, Manufacturer_Part_Number=GRM188R60J226MEA0J, Package=C0603
C4 C5 C6 C9 C11 C13 C29 C41 C43: library part MCD-00099, "Capacitor, MLCC, 10uF, 10V, X5R, 10%, 0603, T=0,8mm", Manufacturer=MURATA, Manufacturer_Part_Number=GRM188R61A106KE69D, Package=C0603
C8 C19 C24 C34: library part MCD-00200, "Capacitor, MLCC, 12pF, 50V, NPO, 5%, 0402, T=0,5mm", Manufacturer=YAGEO, Manufacturer_Part_Number=CC0402JRNPO9BN120, Package=C0402
C10 C16 C20 C23 C26 C31 C32 C33 C37 C49: library part MCD-01356, "Capacitor, MLCC, 4.7uF, 6V3, X5R, 20%, 0402, T=0,5mm", Manufacturer=MURATA, Manufacturer_Part_Number=GRM155R60J475ME47, Package=C0402
C12 C18 C63 C67: library part MCD-00006, "Capacitor, MLCC, 100nF, 16V, X7R, 10%, 0402, T=0.5mm", Alternate_Manufacturer=MURATA, Alternate_Manufacturer_Part_Number=GCM155R71C104KA55D, Manufacturer=YAGEO, Manufacturer_Part_Number=CC0402KRX7R7BB104, Package=C0402
C15 C27 C39 C62 C65: library part MCD-00095, "Capacitor, MLCC, 1uF, 6V3, X5R, 10%, 0402, T=0,5mm", Alternate_Manufacturer=MURATA, Alternate_Manufacturer_Part_Number=GRM155R60J105KE19, Manufacturer_Part_Number=GRM155R61E105KA12, Package=C0402
C21 C25 C30 C38 C40 C50 C53 C54 C56 C66 C117 C123 C136 C137: library part MCD-00102, "Capacitor, MLCC, 100nF, 16V, X7R, 10%, 0402, T=0,5mm", Alternate_Manufacturer=MURATA, Alternate_Manufacturer_Part_Number=GCM155R71C104KA55D, Manufacturer=YAGEO, Manufacturer_Part_Number=CC0402KRX7R7BB104, Package=C0402
C28: library part MCD-00012, "Capacitor, MLCC, 2.2uF, 10V, X5R, 10%, 0603, T=0,8mm", Alternate_Manufacturer=KEMET, Alternate_Manufacturer_Part_Number=C0603C225K8PACTU, Manufacturer=YAGEO, Manufacturer_Part_Number=CC0603KRX5R6BB225, Package=C0603
C52: library part MCD-00199, "Polarized Capacitor,10uF,16V,10%,typeA", Manufacturer=AVX, Manufacturer_Part_Number=TAJA106K016R, Package=C1206
C55: library part MCD-00204, "Capacitor, MLCC, 47uF, 10V, X5R, 20%, 0805, T=1,25mm", Manufacturer=MURATA, Manufacturer_Part_Number=GRM21BR61A476ME15K, Package=C0805
C58 C59 C87 C88 C90 C91: library part MCD-00674, "Capacitor, MLCC, 6.8pF, 50V, NPO, +-0.25pF, 0402, T=0.5mm", Manufacturer=YAGEO, Manufacturer_Part_Number=CC0402CRNPO9BN6R8, Package=C0402
C60: library part MCD-00559, "Capacitor, Tantalum, 47uF, 16V, 10%, TypeC", Manufacturer=AVX, Manufacturer_Part_Number=TAJC476K016RNJ, Package=C2312
C64 C72 C73 C89 C94 C102 C105 C108 C109 C112 C143 C146 C147 C148 C150 C152 C153 C155 C156 C158 C159 C161 C162 C163 C165: library part MCD-00095, "Capacitor,1uF,6V3,X5R,10%,0402", Alternate_Manufacturer=MURATA, Alternate_Manufacturer_Part_Number=GRM155R60J105KE19, Manufacturer_Part_Number=GRM155R61E105KA12, Package=C0402
C69 C167: library part MCD-00205, "Capacitor, MLCC, 100pF, 50V, NPO, 5%, 0402, T=0,5mm", Manufacturer=YAGEO, Manufacturer_Part_Number=CC0402JRNPO9BN101, Package=C0402
C71 C166: library part MCD-00014, "Capacitor, MLCC, 10uF, 25V, X5R, 10%, 0805, T=0,85mm", Manufacturer=YAGEO, Manufacturer_Part_Number=CC0805KRX5R8BB106, Package=C0805
C76 C80 C85 C151 C173 C180: library part MCD-00100, "Capacitor,22uF,6V3,X5R,20%,0603", Manufacturer=MURATA, Manufacturer_Part_Number=GRM188R60J226MEA0J, Package=C0603
C82 C86 C98 C99: library part MCD-00015, "Capacitor,10pF,50V,NPO,5%,0402", Manufacturer=YAGEO, Manufacturer_Part_Number=CC0402JRNPO9BN100, Package=C0402
C83 C84: library part MCD-00724, "Capacitor, MLCC, 470pF, 50V, NPO, 5%, 0402, T=0,5mm", Manufacturer=YAGEO, Manufacturer_Part_Number=CC0402JRNPO9BN471, Package=C0402
C92 C114 C115 C300: library part MCD-00011, "Capacitor, MLCC, 10nF, 16V, X7R, 10%, 0402, T=0.5mm", Manufacturer=YAGEO, Manufacturer_Part_Number=CC0402KRX7R7BB103, Package=C0402
C100 C101: library part MCD-00304, "Capacitor,150pF,50V,COG,5%,0603", Manufacturer=YAGEO, Manufacturer_Part_Number=CC0603JRNPO9BN151, Package=C0603
C104 C110: library part MCD-00010, "Capacitor,1uF,16V,X5R,10%,0603", Manufacturer=YAGEO, Manufacturer_Part_Number=CC0603KRX5R7BB105, Package=C0603
C106 C113: library part MCD-00202, "Capacitor,22nF,16V,X7R,10%,0402", Manufacturer=YAGEO, Manufacturer_Part_Number=CC0402KRX7R7BB223, Package=C0402
C111: library part MCD-00098, "Capacitor,10uF,6V3,X5R,10%,0603", Manufacturer=YAGEO, Manufacturer_Part_Number=CC0603KRX5R5BB106, Package=C0603
C118 C124 C133 C138: library part MCD-00104, "Capacitor, MLCC, 220uF, 6V3, X5R, 20%, 1206, T=1,6mm", Manufacturer=MURATA, Manufacturer_Part_Number=GRM31CR60J227ME11, Package=C1206
C144 C145: library part MCD-00198, "Capacitor,1nF,16V,X7R,10%,0402", Manufacturer=YAGEO, Manufacturer_Part_Number=CC0402KRX7R7BB102, Package=C0402
C185 C190: library part MCD-00238, "Capacitor,1uF,6V3,X5R,10%,0603", Manufacturer=YAGEO, Manufacturer_Part_Number=CC0603KRX5R5BB105, Package=C0603
C189: library part MCD-00011, "Capacitor,10nF,16V,X7R,10%,0402", Manufacturer=YAGEO, Manufacturer_Part_Number=CC0402KRX7R7BB103, Package=C0402
CN1 CN5: library part MCD-00109, "USB-Receptacle,Dual-Type-A, RA, TH, Height 15.5mm", Manufacturer=CONEXCON, Manufacturer_Part_Number=5600-3081
CN2: library part MCD-00302, "Header, 20x2, 2.54mm, VR, TH, Height 5.84mm/2.54mm", Manufacturer=SAMTEC, Manufacturer_Part_Number=TSW-120-07-G-D
CN3: library part MCD-00655, "Header 2 circuits, 1.25mm Pitch ,  Vertical, with Friction Lock", Manufacturer=MOLEX, Manufacturer_Part_Number=53047-0210
CN4: library part MCD-01013, "Socket ,TEConn,FCC/FPC, 20pins, 1.0mm,SMT, ZIF Receptacle", Manufacturer="TE CONNECTIVITY", Manufacturer_Part_Number=2-1734248-0
CN6 CN7: library part MCD-01108, "USB tyce C certified receptacle for 1.6mm pcb height", Manufacturer="CHANT SINCERE (COXOC)", Manufacturer_Part_Number=317JD24BZTF3K3C3
CN8: library part MCD-01129, "Connector RJ45 with Gigabit magnetics and LED , led pull down", Manufacturer="YUAN DEAN SCIENTIFIC", Manufacturer_Part_Number=48F-01GYDXNL
CN9: library part MCD-00307, "HDMI Receptacle Type A 19pins standard Connector", Manufacturer=FCI, Manufacturer_Part_Number=10029449-001RLF
CN10: library part MCD-00270, "Connector Jack socket Stereo 3.5mm, 4 pins, RA, SMT, Black", Alternate_Manufacturer=FARNELL, Alternate_Manufacturer_Part_Number=1368640, Manufacturer=LUMBERG, Manufacturer_Part_Number="1503 13 VP3"
CN11: library part MCD-00028, "USB-MICRO-B, 0.65mm, RA, SMT, Bottom Mount,", Manufacturer=MOLEX, Manufacturer_Part_Number=1050170001
CN12: library part MCD-00029, "Header, 4x1, 2,54mm, VR, TH, Height 5.84mm/2.54mm", Manufacturer=SAMTEC, Manufacturer_Part_Number=TSW-104-07-x-S
CN13: library part MCD-00301, "Socket, 10x1, 2.54mm, VR, SMT, Height 9.78mm", Manufacturer=SAMTEC, Manufacturer_Part_Number=SSW-110-22-L-S-VS
CN14 CN16: library part MCD-00300, "Socket, 8x1, 2.54mm, VR, SMT, Height 9.78mm", Manufacturer=SAMTEC, Manufacturer_Part_Number=SSW-108-22-L-S-VS
CN15: library part MCD-00023, "MicroSD Card Conn, Reversed-Type, Mnt Push-Push", Manufacturer=YAMAICHI, Manufacturer_Part_Number=PJS008-2003-1
CN17: library part MCD-00299, "Socket, 6x1, 2.54mm, VR, SMT, Height 9.78mm", Manufacturer=SAMTEC, Manufacturer_Part_Number=SSW-106-22-L-S-VS
D1 D2: library part MCD-00034, "BAT60JFILM", Manufacturer=STMICROELECTRONICS
F1: library part MCD-01133, "Surface mount resettable polyswitch fuse.I hold=0.35A and I trigger=0.75A", Manufacturer="TE CONNECTIVITY", Manufacturer_Part_Number=picoSMDC035S, Package=0805
H1 H2 H3 H4: library part MCD-00035, "POSITION HOLE C6D3R5", Manufacturer=n/a
L1: library part MCD-00657, "Inductor,2.4nH,+-0.2nH,0.05R,0.85A,0402", Manufacturer=MURATA, Manufacturer_Part_Number=LQW15AN2N4C00x, Package=L0402
L2 L3 L5 L6: library part MCD-01122, "Power Inductor ,1µH,4.3A max,+-20%,0.042ohm,2520", Manufacturer=MURATA, Manufacturer_Part_Number=DFE252012P-1ROM{}P2, Package=2520
L4: library part MCD-00659, "Inductor, 2.2µH, 20%, Isat 0.35A, DCR 0.2Ohm, 0603", Manufacturer=MURATA, Manufacturer_Part_Number=LQM18PN2R2MGH, Package=L0603
L7: library part MCD-00046, "SMD Chip ferrite bead, 30R@100MHz +/-30%, 5A, 10mohm DC, S (Standard) material, 0603, T=0.8mm", Manufacturer=TDK, Manufacturer_Part_Number=MPZ1608S300A
L8: library part MCD-00305, "Bead,26R at 100Mhz,6A,0603", Manufacturer=MURATA, Manufacturer_Part_Number=BLM18KG260TN1
L9: library part MCD-01134, "IND 4.7µH 20% 80mA 600mhom 0603", Manufacturer=MURATA, Package=0603
L10 L11: library part MCD-00094, "Ferrite bead 100R 2A 0603", Manufacturer=MURATA, Manufacturer_Part_Number=BLM18EG101TN1
LD1 LD6: library part MCD-00049, "LED, Red, 0603", Manufacturer=EVERLIGHT, Manufacturer_Part_Number=19-213-R6C-AP1Q2B/3T, Package="LED 0603"
LD2 LD3 LD5 LD9: library part MCD-00050, "LED, Green, 0603", Manufacturer=EVERLIGHT, Manufacturer_Part_Number=19-213SYGC/S530-E2/TR8, Package="LED 0603"
LD4: library part MCD-00051, "LED Bicolor", Alternate_Manufacturer=EVERLUCK, Alternate_Manufacturer_Part_Number=LE-RGW35280, Manufacturer="AVAGO TECHNOLOGIES", Manufacturer_Part_Number=HSMF-A201-A00J1
LD7: library part MCD-00321, "LED, Orange, 0603", Manufacturer=EVERLIGHT, Manufacturer_Part_Number=19-217/S2C-AM2N2VY/3T, Package="LED 0603"
LD8: library part MCD-01131, "LED Blue, 0603 SMD, Forward Voltage Min=2,8V, Max=3,1V", Manufacturer=EVERLIGHT, Manufacturer_Part_Number=19-217-BHC-ZL1M2RY-3T, Package=0603
LE1: library part MCD-00048, "FIXED IND 4.7UH 1A 180 MOHM 30% SMD", Manufacturer=MURATA, Manufacturer_Part_Number=LQH32PN4R7NN0L
LNK1 LNK2: "link 0.2mm"
Q1: library part MCD-01120, "Transistor 45V Matched Pair PNP small Signal transistor in SOT363", Alternate_Manufacturer=ONSEMI, Alternate_Manufacturer_Part_Number=NST45010MW6T1G, Manufacturer=DIODES_INC, Manufacturer_Part_Number=BCM857BS7F, Package=SOT363
Q2 T1 T2: library part MCD-01126, "Power Mosfet, P-channel,VDS -30V,RDS 12mohm typ,ID -9A", Manufacturer=STMICROELECTRONICS, Manufacturer_Part_Number=STL9P3LLH6, Package="PowerFLAT 3.3x3.3"
R1 R2 R5 R7 R65 R75 R76 R93 R166 R167: library part MCD-00068, "Resistor,1K5,0402,1%,1/16W", Manufacturer=YAGEO, Manufacturer_Part_Number=RC0402FR-071K5L, Package=R0402
R3 R47 R150: library part MCD-00181, "Resistor,0R,0603,ULO", Manufacturer=ROHM, Manufacturer_Part_Number=PMR03EZPJ000, Package=R0603
R4 R6 R8 R9 R10 R13 R31 R32 R34 R35 R36 R46 R58 R59 R64 R68 R71 R72 R73 R74 R77 R78 R79 R85 R86 R152 R154 R158 R165: library part MCD-00052, "Resistor,0R,0402,5%,1/16W", Manufacturer=YAGEO, Manufacturer_Part_Number=RC0402JR-070RL, Package=R0402
R11 R18 R19 R37 R40 R42 R80 R81 R84 R87 R96 R99 R109 R136 R164 R300 R302 R303 R600: library part MCD-00053, "Resistor,10K,0402,1%,1/16W", Manufacturer=YAGEO, Manufacturer_Part_Number=RC0402FR-0710KL, Package=R0402
R12 R14 R16 R17 R20 R22 R25 R26 R27 R28 R33 R39 R45 R49 R56 R120: library part MCD-00063, "Resistor,47K,0402,1%,1/16W", Manufacturer=YAGEO, Manufacturer_Part_Number=RC0402FR-0747KL, Package=R0402
R15 R38: library part MCD-00120, "Resistor,240R,0402,1%,1/16W", Manufacturer=YAGEO, Manufacturer_Part_Number=RC0402FR-07240RL, Package=R0402
R21 R43 R82 R101 R102 R106: library part MCD-00061, "Resistor,1K,0402,1%,1/16W", Manufacturer=YAGEO, Manufacturer_Part_Number=RC0402FR-071KL, Package=R0402
R23 R100 R119 R127 R129 R134 R137 R139 R140 R159 R161: library part MCD-00059, "Resistor,100K,0402,1%,1/16W", Alternate_Manufacturer=YAGEO, Alternate_Manufacturer_Part_Number=RT0402FRE07100KL, Manufacturer_Part_Number=RC0402FR-07100KL, Package=R0402
R24: library part MCD-00187, "Resistor,12K,0402,1%,1/16W", Manufacturer=YAGEO, Manufacturer_Part_Number=RC0402FR-0712KL, Package=R0402
R41 R89 R90 R105: library part MCD-00062, "Resistor,330R,0402,1%,1/16W", Manufacturer=YAGEO, Manufacturer_Part_Number=RC0402FR-07330RL, Package=R0402
R44: library part MCD-00185, "Resistor,3K,0402,1%,1/16W", Manufacturer=YAGEO, Manufacturer_Part_Number=RC0402FR-073KL, Package=R0402
R48 R57 R70: library part MCD-00333, "Resistor,5K1,0402,1%,1/16W", Manufacturer=YAGEO, Manufacturer_Part_Number=RC0402FR-075K1L, Package=R0402
R50 R51 R52 R53 R54 R55 R67 R91 R94 R149 R156 R163: library part MCD-00065, "Resistor,4K7,0402,1%,1/16W", Alternate_Manufacturer=YAGEO, Alternate_Manufacturer_Part_Number=RT0402FRE074K7L, Manufacturer_Part_Number=RC0402FR-074K7L, Package=R0402
R60 R61 R62 R63 R69 R153: library part MCD-00189, "Resistor,22R,0402,1%,1/16W", Manufacturer=YAGEO, Manufacturer_Part_Number=RC0402FR-0722RL, Package=R0402
R66 R114 R157 R162: library part MCD-00064, "Resistor,510R,0402,1%,1/16W", Manufacturer=YAGEO, Manufacturer_Part_Number=RC0402FR-07510RL, Package=R0402
R83 R151 R160: library part MCD-00056, "Resistor,0R,0603,5%,1/10W", Manufacturer=YAGEO, Manufacturer_Part_Number=RC0603JR-070RL, Package=R0603
R88 R104 R110 R111 R125: library part MCD-00067, "Resistor,100R,0402,1%,1/16W", Manufacturer=YAGEO, Manufacturer_Part_Number=RC0402FR-07100RL, Package=R0402
R92 R103: library part MCD-00485, "Resistor,51R,0402,1%,1/16W", Manufacturer=YAGEO, Manufacturer_Part_Number=RC0402FR-0751RL, Package=R0402
R95 R97 R98: library part MCD-00057, "Resistor,2K2,0402,1%,1/16W", Manufacturer=YAGEO, Manufacturer_Part_Number=RC0402FR-072K2L, Package=R0402
R107 R108: library part MCD-00507, "Resistor,680R,0402,1%,1/16W", Manufacturer=YAGEO, Manufacturer_Part_Number=RC0402FR-07680RL, Package=R0402
R112: library part MCD-00069, "Resistor,36K,0402,1%,1/16W", Manufacturer=YAGEO, Manufacturer_Part_Number=RC0402FR-0736KL, Package=R0402
R115 R116 R117 R118 R121 R122 R123 R124 R126 R128 R130 R131 R132 R133 R135 R138 R141 R142 R143 R144 R145 R146 R147 R148: library part MCD-00118, "Resistor,56R,0402,1%,1/16W", Manufacturer=YAGEO, Manufacturer_Part_Number=RC0402FR-0756RL, Package=R0402
R155: library part MCD-00183, "Resistor,2K49,0402,1%,1/16W", Manufacturer=YAGEO, Manufacturer_Part_Number=RC0402FR-072K49L, Package=R0402
R304: library part MCD-00358, "Resistor,10R,0402,1%,1/16W", Manufacturer=YAGEO, Manufacturer_Part_Number=RC0402FR-0710RL, Package=R0402
SB1 SB2 SB3 SB4 SB5 SB6 SB9 SB10 SB17 SB19 SB20 SB21 SB22 SB23 SB24 SB25 SB26: library part MCD-00071, "Solder Bridge ON", Manufacturer=YAGEO, Manufacturer_Part_Number=RC0603JR-070RL, Package=SB0603
SB7 SB8 SB11 SB12 SB13 SB14 SB15 SB16 SB18: library part MCD-00072, "Solder Bridge OFF", Manufacturer=YAGEO, Manufacturer_Part_Number=RC0603JR-070RL, Package=SB0603
SW1: library part MCD-00658, "Dip Switch ,2Position ,Surface Mount Slide (Standard) ,2.54 pitch,25mA 24VDC", Manufacturer=C&K, Manufacturer_Part_Number=SDA02H1SBD, Package=DIP
T3 T4: library part MCD-00073, "NPN Bipolar Transistor", Alternate_Manufacturer="ON SEMICONDUCTOR", Alternate_Manufacturer_Part_Number="MMBT2222ALT1G / MMBT2222ALT3G", Manufacturer_Part_Number=BSR14
TP1 TP2 TP3 TP4 TP5 TP6 TP7 TP8 TP9 TP11 TP12 TP15 TP16 TP17 TP18 TP19 TP20 TP21 TP22 TP23: library part MCD-00074, "Test Point 1mm", Manufacturer=n/a
TP10 TP13 TP14 TP24 TP25 TP26 TP27 TP28 TP29: library part MCD-00631, "Test Point 0.6mm"
U1 U2 U6 U9 U29: library part MCD-00649, "Common mode filter with ESD protection for USB 2.0 interface", Manufacturer=STMICROELECTRONICS, Manufacturer_Part_Number=ECMF02-2AMX6
U3 U11: library part MCD-00123, "IC,Dual-Channel-Power-Switch,500mA,100mR,SO8", Manufacturer=STMICROELECTRONICS
U4: library part MCD-00303, "STM PMIC WFQFN 5.0x6.0x0.80 44L 0.4 pitch", Manufacturer=STMICROELECTRONICS, Manufacturer_Part_Number=STPMU1APQR
U5: library part MCD-00207, "Memory,DDR3L,4Gb,256Mbx16,1866MT/s,1V35,FBGA96", Manufacturer=MICRON, Manufacturer_Part_Number=MT41K256M16TW-107-P-V00H
U7: library part MCD-00145, "USB HUB 2,0 Controller", Manufacturer=MICROCHIP
U8: library part MCD-00268, "IEEE802.11b/g/n W-LAN + Bluetooth 4.1+EDR module", Manufacturer=MURATA
U10 U26: library part MCD-00667, "4-line ESD protection for high speed lines", Manufacturer=STMICROELECTRONICS, Package=uQFN-10L
U12: library part MCD-00676, "USB Type-C controller with VCONN switch", Manufacturer=STMICROELECTRONICS, Manufacturer_Part_Number=STUSB1600AQTR
U13: library part MCD-00677, "MPU TFBGA12x12 secure boot+crypto", Manufacturer=STMICROELECTRONICS
U14: library part MCD-00267, "HDMI Transmitter, 72-pin 10 × 10 mm QFN", Manufacturer=LATTICE, Manufacturer_Part_Number=SiI9022ACNU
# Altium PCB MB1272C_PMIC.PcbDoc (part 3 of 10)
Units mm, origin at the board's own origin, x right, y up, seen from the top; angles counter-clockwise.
Board outline 101 x 71 mm, 6 copper layers (Top Layer, Signal Layer 1, Signal Layer 2, Signal Layer 3, Signal Layer 4, Bottom Layer), stack 1.552 mm thick; 518 components, 478 nets, 2152 pads, 1871 vias.
Unrouted connection lines stored in the file: 3.

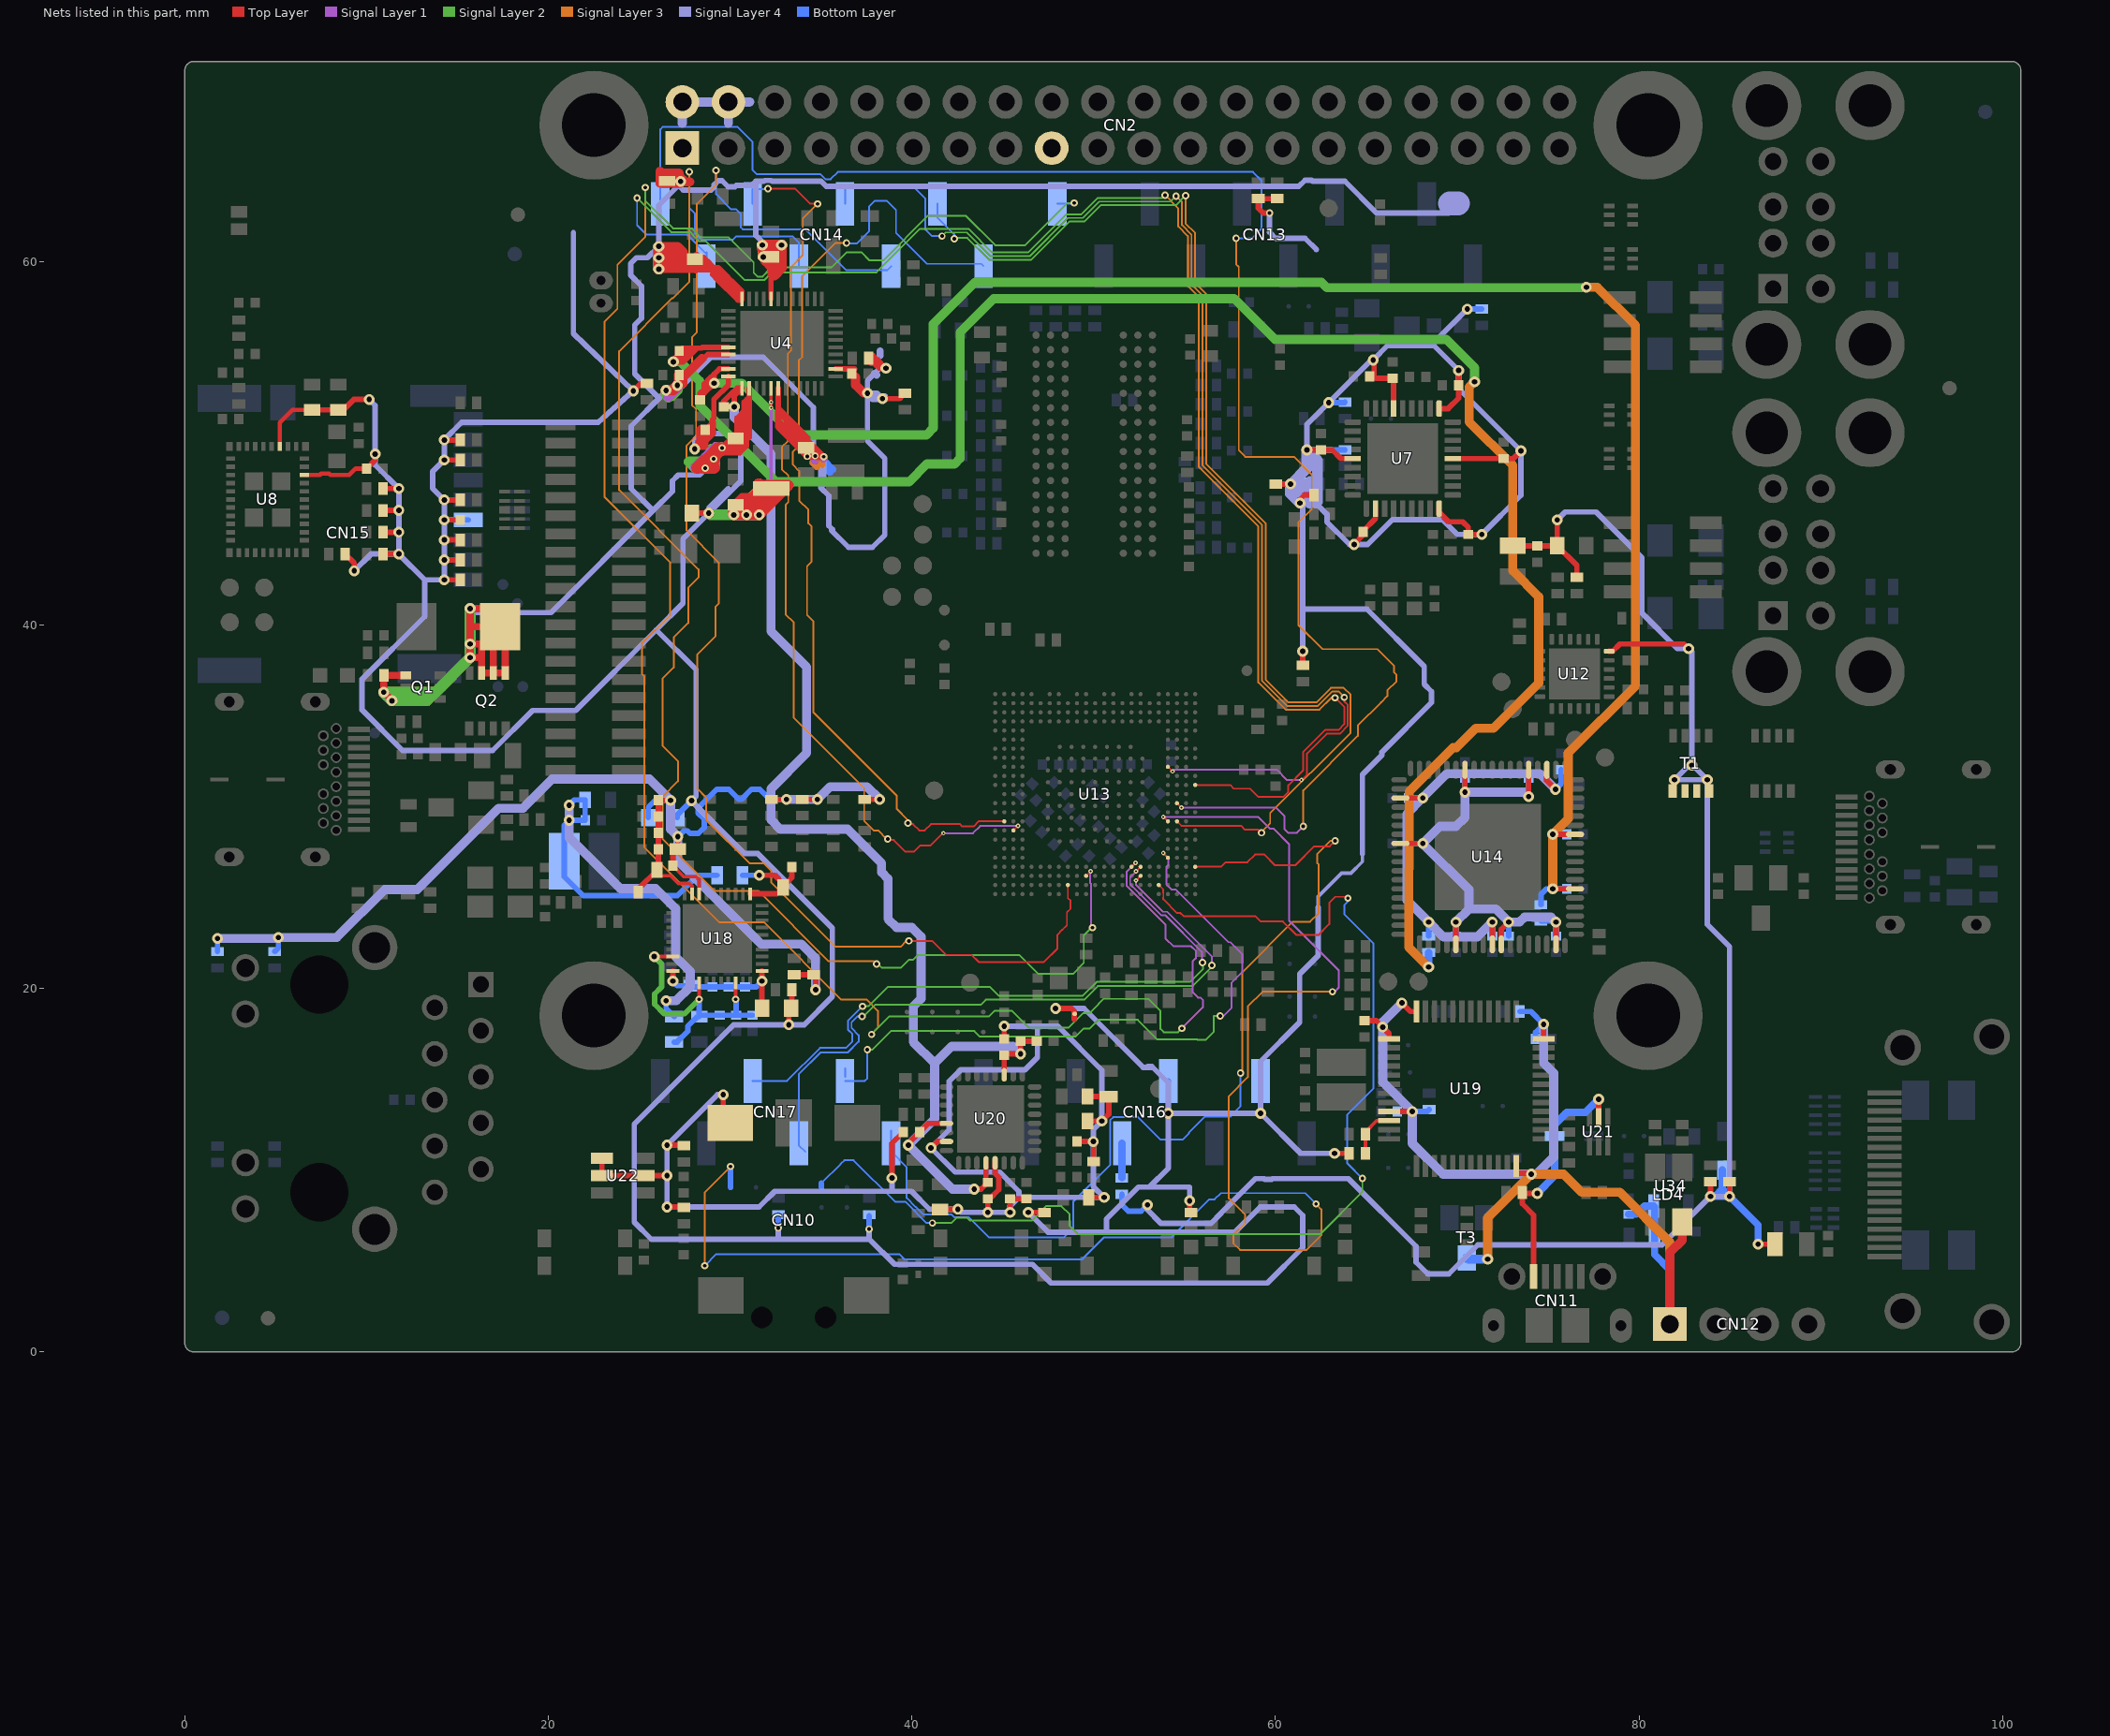
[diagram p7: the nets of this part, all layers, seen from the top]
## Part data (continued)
U15 U17: library part MCD-01125, "DUAL TRANSIL ARRAY FOR ESD PROTECTION", Manufacturer=STMICROELECTRONICS, Manufacturer_Part_Number=ESDA25L, Package=ESD_SOT23
U16 U23 U24 U25 U27 U28 U30: library part MCD-01026, "High power transient voltage suppressor", Manufacturer=STMICROELECTRONICS, Manufacturer_Part_Number=ESDA7P120-1U1M, Package=QFN1610
U18: library part MCD-01130, "10/100/1000M GIGABIT Ethernet Transceiver, QFN40 , SMPS version", Manufacturer=REALTEK
U19: library part MCD-00085, "Medium-density performance line ARM-based 32-bit MCU with 128KB Flash", Manufacturer=STMICROELECTRONICS, Manufacturer_Part_Number=STM32F103CBT6
U20: library part MCD-00265, "Low-Power, Stereo Codec with Headphone Amp", Manufacturer="CIRRUS LOGIC", Manufacturer_Part_Number=CS42L51-CNZ
U21: library part MCD-00169, "USB OTG FS ESD protection", Manufacturer=STMICROELECTRONICS, Manufacturer_Part_Number=USBLC6-2P6
U22: library part MCD-00247, "Quad Bidir ESD protection", Manufacturer=STMICROELECTRONICS, Manufacturer_Part_Number=ESDA6V1BC6
U31 U32: library part MCD-00297, "ESD protection & Common Filter High Speed serial Interfaces", Manufacturer=STMICROELECTRONICS, Manufacturer_Part_Number=ECMF04-4HSWM10
U33: library part MCD-01457, "ESD protection , 5 lines", Manufacturer=STMICROELECTRONICS, Package=QFN
U34: library part MCD-00086, "Ultra low drop-low noise BiCMOS voltage, regulators low ESR capacitors compatible", Manufacturer=STMICROELECTRONICS, Manufacturer_Part_Number=LD3985M33R
U35: library part MCD-00170, "ESD protection 6V1", Manufacturer=STMICROELECTRONICS, Manufacturer_Part_Number=ESDALC6V1-1U2
X1: library part MCD-01036, "Crystal 24MHz, 6pF, +-20ppm, 80ohms max, SMD", Manufacturer=NDK, Manufacturer_Part_Number="NX2016SA 24MHz EXS00A-CS10820", Package="(2016) 2.0 x 1.6 x 0.45 mm"
X2: library part MCD-01463, "Crystal 25Mhz, 10pF, -+50PPM, SMD", Manufacturer=NDK, Manufacturer_Part_Number="NX3225GA 25MHz EXS00A-CG06750", Package=3225
X4: library part MCD-01479, "Crystal 32.768kHz, 6pF, -+20PPM, R=80K, SMD", Manufacturer=NDK, Manufacturer_Part_Number="NX2012SA 32.768KHz EXS00A-MU00527", Package=NX2012SA
X5: library part MCD-00092, "Crystal 8Mhz, 8pF, -+50PPM, SMD", Manufacturer=NDK, Manufacturer_Part_Number="NX3225GD 8MHz EXS00A-CG04874"
X6: library part MCD-01627, "Oscillator 24Mhz, +-50ppm, Vcc:3.3V typ (1.62V min), square wave: [0.1Vcc;0.9Vcc], Enable pin", Manufacturer=NDK, Manufacturer_Part_Number="NZ2016SH 24MHz END4869F", Package=2.0x1.6x0.7mm

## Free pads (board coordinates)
  round 0.508 on Mech16: 1(25.738,-17.565) 1(74.585,-17.565)

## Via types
v1: diameter 0.4, hole 0.2, Top Layer to Bottom Layer, tented both sides, 884 vias
v2: diameter 0.25, hole 0.1, Top Layer to Signal Layer 1, tented top, 470 vias
v3: diameter 0.6, hole 0.3, Top Layer to Bottom Layer, tented both sides, 469 vias
v4: diameter 0.25, hole 0.1, Top Layer to Signal Layer 1, tented both sides, 46 vias
v5: diameter 0.25, hole 0.1, Top Layer to Bottom Layer, tented top, 2 vias

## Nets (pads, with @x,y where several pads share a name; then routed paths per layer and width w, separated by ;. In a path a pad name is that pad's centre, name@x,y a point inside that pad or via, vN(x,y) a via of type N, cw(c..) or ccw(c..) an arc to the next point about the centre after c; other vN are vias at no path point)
1V2_CVCC12: C141.2 C142.2 C164.2 C169.2 C170.2 C172.2 R152.1 U14.5 U14.12 U14.26 U14.42 U14.47 U14.53 | length 32.5
  Top Layer w0.3: U14.26@66.875,27.975 v3(68.1,27.975) ; U14.42@69.925,22.425 v3(69.925,23.65) ; v3(70.425,30.8) U14.12@70.425,32.025 ; U14.47@72.425,22.425 72.425,23.25 v3(72.825,23.65) ; U14.5@73.925,32.025 73.925,30.555 v3(73.929,30.551) v3@73.929,30.521 ; U14.53@75.425,22.425 v3(75.425,23.65)
  Signal Layer 4 w0.5: v3(69.925,23.65) 70.64,24.365 ; v3(73.929,30.551) 73.68,30.8 v3(70.425,30.8) 70.425,29.41 69.93,28.915 69.04,28.915 v3(68.1,27.975) 70.64,25.435 70.64,24.365 ; v3(75.425,23.65) 75.16,23.915 74.163,23.915 74.153,23.925 73.697,23.925 73.422,23.65 v3(72.825,23.65) 72.825,23.669 72.129,24.365 70.64,24.365
  Bottom Layer w0.3: C164.2@67.325,27.975 v3(68.1,27.975) ; C172.2@69.925,22.875 v3(69.925,23.65) ; v3(70.425,30.8) C142.2@70.425,31.575 ; C170.2@72.825,22.875 v3(72.825,23.65) ; C141.2@73.925,31.575 73.925,30.555 v3(73.929,30.551) ; R152.1@74.6,23.7 75.375,23.7 v3(75.425,23.65) C169.2@75.425,22.875
1V2_HDMI: C31.2 C160.2 C168.2 R152.2 U4.21 U14.60 U14.66 | length 106.1
  Top Layer w0.3: C31.2@28.35,52.375 28.35,52.75 28.575,52.975 ; U4.21@29.9,54.075 29.4,54.075 29.125,53.8 ; v3(75.25,25.475) U14.60@76.475,25.475 ; v3(75.25,28.475) U14.66@76.475,28.475 ; 28.575,52.975 28.575,53.25 28.875,53.55 ; 28.575,52.975 28.575,52.75 v3(29.125,53.3) ; 28.575,52.975 28.9,53.3 v3(29.125,53.3) ; 28.875,53.55 29.125,53.8 ; 28.875,53.55 v3(29.125,53.3) ; v3(29.125,53.3) 29.125,53.8
  Signal Layer 2 w0.5: v3(29.125,53.3) 29.281,53.3 30.65,53.3 33.5,50.45 35.651,50.45 40.8,50.45 41.175,50.825 41.175,56.55 43.475,58.85 62.525,58.85 62.825,58.55 77.075,58.55 v3(77.1,58.575)
  Signal Layer 3 w0.5: v3(75.25,25.475) v3(75.25,28.475) 76.1,29.325 76.1,32.95 79.8,36.65 79.8,56.475 77.7,58.575 v3(77.1,58.575)
  Signal Layer 4 w0.5: v3(75.25,25.475) v3(75.25,28.475)
  Bottom Layer w0.3: R152.2@74.6,24.6 74.6,25.175 74.9,25.475 v3(75.25,25.475) C168.2@76.025,25.475 ; v3(75.25,28.475) C160.2@76.025,28.475
1V05_AVDD_GMII: C177.2 C178.2 C179.2 C180.2 R160.1 U18.3 U18.8 U18.38 | length 15.7
  Top Layer w0.2: v3(25.825,21.75) U18.38@26.85,21.75 ; v1(28.3,19.4) U18.3@28.3,20.3 ; v1(30.3,19.4) U18.8@30.3,20.3
  Signal Layer 2 w0.3: v3(25.825,21.75) 26.225,21.35 26.225,20.075 25.85,19.7 25.85,19.125 26.375,18.6 27.5,18.6 v1(28.3,19.4)
  Bottom Layer w0.3: R160.1@26.925,17.05 27.075,17.05 27.675,17.65 27.675,17.925 28.2,18.45 C180.2@28.3,18.45 ; v1(28.3,19.4) C180.2@28.3,18.45 ; v1(30.3,19.4) 30.325,19.375 C178.2@30.325,18.525 ; C177.2@31.225,18.525 C178.2@30.325,18.525 ; C180.2@28.3,18.45 28.375,18.525 C179.2@29.425,18.525 C178.2@30.325,18.525
1V05_DVDD_GMII: C81.2 C85.2 R151.1 U18.21 | length 5.9
  Top Layer w0.3: U18.21@31.1,25.2 32.575,25.2 C85.2@32.925,25.55 C85.2@32.925,25.625 ; v3(31.6,26.225) 32.45,26.225 32.925,25.75 C85.2@32.925,25.625 ; C81.2@33.4,26.675 33.4,26.1 C85.2@32.925,25.625
  Bottom Layer w0.3: R151.1@30.675,26.225 v3(31.6,26.225)
1V05_GMII: C151.2 C157.2 LE1.2 R151.2 R160.2 | length 32.9
  Signal Layer 4 w0.5: v3(21.15,30.075) v3(21.15,29.25) 21.15,28.295 23.955,25.49 25.9,25.49 27.005,24.385 27.005,21.74 27.805,20.94 27.805,20.09 27.04,19.325 v3(26.475,19.325)
  Bottom Layer w0.3: v3(26.475,19.325) 26.475,18.9 R160.2@26.925,18.45 ; R151.2@29.275,26.225 28.225,26.225 27.1,25.1 21.925,25.1 20.875,26.15 LE1.2@20.875,27 20.875,28.975 v3(21.15,29.25) ; v3(21.15,29.25) v3(21.15,30.075) 21.15,30.1 21.425,30.375 C151.2@22.025,30.375 C157.2@22.025,29.25 v3(21.15,29.25)
1V8_AUDIO: C33.2 C94.2 C95.2 C97.2 C102.2 C107.2 U4.23 U20.5 U20.12 U20.27 | length 72.7
  Top Layer w0.3: C33.2@29.6,52.025 C33.2@29.625,52 ; C33.2@29.65,52 C33.2@29.7,52 ; v3(39.8,11.375) 39.9,11.375 39.9,11.575 C102.2@40.425,12.1 40.9,12.575 U20.5@41.9,12.575 ; v3(43.425,8.95) 43.8,8.95 C107.2@44.175,9.325 44.075,9.425 U20.12@44.075,10.4 ; U20.27@45.075,15.25 C97.2@45.075,16.325 45.15,16.4 v3(45.975,16.4) C94.2@45.975,17.1 C95.2@46.875,17.1 ; C33.2@29.625,52 C33.2@29.662,51.962 ; C33.2@29.625,52 29.625,52.275 30.125,52.775 ; C33.2@29.625,52 29.625,51.925 C33.2@29.662,51.962 ; C33.2@29.662,51.962 C33.2@29.7,52 ; C33.2@29.7,52 v3(30.225,52) 30.225,52.6 30.4,52.775 ; 30.125,52.775 30.3,52.95 ; 30.125,52.775 30.4,52.775 ; 30.3,52.95 30.375,53.025 ; 30.3,52.95 30.375,53.025 ; 30.375,53.025 U4.23@30.65,53.025 30.4,52.775
  Signal Layer 4 w0.5: v3(30.225,52) 30.225,51.424 32.255,49.394 32.255,39.64 34.205,37.69 34.205,32.94 32.255,30.99 32.255,29.265 32.755,28.765 36.455,28.765 38.33,26.89 38.33,26.39 38.68,26.04 38.68,23.825 39.155,23.35 40,23.35 40.505,22.845 40.505,19.43 40.078,19.003 40.078,17.05 41.25,15.878 ; v3(43.425,8.95) 42.225,8.95 v3(39.8,11.375) 41.25,12.825 41.25,15.878 ; v3(45.975,16.4) 45.56,16.815 42.187,16.815 41.25,15.878
3V3: C21.2 C23.2 C28.2 C29.2 C30.2 C38.2 C39.2 C40.2 C42.2 C45.2 C49.2 C50.2 C54.2 CN2.1 CN2.17 CN15.4 CN16.2 CN16.4 L5.2 L7.1 L10.2 L11.2 R1.1 R2.1 R11.1 R14.2 R16.2 R17.1 R18.2 R19.2 R20.1 R22.1 R25.2 R26.1 R27.1 R28.2 R33.2 R40.1 R94.1 R105.2 R106.2 R114.2 R127.2 R134.2 R140.2 R166.1 R167.1 R300.1 R600.1 SB5.1 U4.22 U4.27 U7.5 U7.10 U7.15 U7.23 U7.29 U7.36 U8.30 U8.36 | length 433.6
  Top Layer w0.2: C39.2@28.625,50.725 28.625,50.575 28.375,50.325 28.35,50.325 28.35,50.9 28.25,50.8 28.25,50.025 28.65,50.425 ; v2(32.25,51.95) v2(32.25,52.25) U4.27@32.25,53.025
  Top Layer w0.25: U8.36@5.225,49.825 5.225,51.125 5.925,51.825 C28.2@7,51.825 ; U8.30@6.575,48.25 7.433,48.25 7.508,48.325 7.942,48.325 8.017,48.25 9.05,48.25 9.4,48.6 C45.2@10,48.6
  Top Layer w0.28: C39.2@28.625,50.725 29.025,51.125 29.025,51.3 29.095,51.37 29.095,52.284 29.105,52.294
  Top Layer w0.3: C28.2@7,51.825 C29.2@8.45,51.825 8.725,51.825 9.3,52.4 v3(10.15,52.4) ; R26.1@8.825,43.9 9.325,43.4 v3(9.325,42.975) ; C45.2@10,48.6 10.475,49.075 v3(10.475,49.4) ; R27.1@10.9,43.9 v3(11.775,43.9) ; R22.1@10.9,45.1 v3(11.775,45.1) ; R20.1@10.9,46.3 v3(11.775,46.3) ; R17.1@10.9,47.5 v3(11.775,47.5) ; v3@14.25,45.775 C49.2@15.15,45.775 ; v3(14.275,42.475) R33.2@15.15,42.475 ; v3(14.275,43.575) R28.2@15.15,43.575 ; v3(14.275,44.675) R25.2@15.15,44.675 ; v3(14.275,46.875) R19.2@15.15,46.875 ; v3(14.275,49.075) R16.2@15.15,49.075 ; v3(14.275,50.175) R14.2@15.15,50.175 ; v3(24.675,52.875) 25.075,53.275 R11.1@25.425,53.275 ; L7.1@27.9,46.15 v3(28.825,46.15) ; v3(28.051,49.678) 28.051,49.701 28.25,49.9 28.65,50.3 28.65,50.375 ; 29.105,52.294 29.105,52.405 29.9,53.2 U4.22@29.9,53.675 ; v3(33.225,18) 33.225,18.775 L10.2@33.35,18.9 33.4,18.95 R300.1@33.4,19.925 ; v3(46.4,7.675) R105.2@47.3,7.675 ; v3(47.9,18.9) 48.775,18.9 48.925,18.75 48.925,18.3 ; v3(55.28,8.315) 55.28,7.745 R106.2@55.35,7.675 ; v1(59.675,62.655) 59.325,62.655 59.05,62.93 R1.1@59.05,63.45 R2.1@60.1,63.45 ; R600.1@60.006,47.75 v3(60.825,47.75) ; v3(61.35,46.7) 61.35,46.9 61.6,47.15 R18.2@62.125,47.15 ; R40.1@61.5,37.775 v3(61.5,38.55) ; v3(61.725,49.625) C38.2@62.5,49.625 63.125,49.625 63.6,49.15 U7.23@64.25,49.15 ; v3(63.25,10.925) R94.1@64.05,10.925 ; v3(64.325,44.425) 64.325,44.45 64.825,44.95 C50.2@64.825,45.125 64.825,45.175 65.5,45.85 U7.29@65.5,46.4 ; v3(65.375,54.575) 65.425,54.525 65.425,53.675 65.525,53.575 C21.2@66.45,53.575 66.5,53.525 U7.15@66.5,51.9 ; U7.36@69,46.4 69,46.2 69.525,45.675 70.3,45.675 70.6,45.375 C54.2@70.6,44.975 v3(71.35,44.975) ; U7.10@69,51.9 69.5,51.9 70.075,52.475 C30.2@70.075,53.175 v3(70.075,54) ; U7.5@69.75,49.15 C40.2@72.55,49.15 73.075,49.15 v3(73.5,49.575)
  Top Layer w0.4: 28.25,50.025 28.25,49.9 28.25,49.82 28.545,49.82 28.6,49.875 28.6,50.124 29.025,50.549 29.025,51.125
  Top Layer w0.6: C42.2@30.2,46.475 31.425,46.475 31.55,46.6 31.55,46.95 ; C42.2@30.2,46.475 30.675,46.95 31.175,46.95 ; C42.2@30.2,46.475 v3(30.2,46.05) v3(30.9,46.05) 31.595,46.05 v3(31.597,46.052) 31.597,46.072 32.475,46.95 ; 31.175,46.95 31.55,46.95 ; 31.175,46.95 L5.2@31.55,47.325 ; 31.55,46.95 32.475,46.95 ; 31.55,46.95 L5.2@31.55,47.325 ; L5.2@31.55,47.325 31.55,47.725 L5.2@31.575,47.75 ; L5.2@31.55,47.325 L5.2@31.575,47.35 ; L5.2@31.575,47.35 32.749,47.35 L5.2@32.812,47.287 ; L5.2@31.575,47.35 L5.2@31.575,47.75 ; L5.2@31.575,47.75 31.65,47.675 33.2,47.675 L5.2@32.812,47.287 ; 32.475,46.95 L5.2@32.812,47.287
  Signal Layer 1 w0.2: v3(31.597,46.052) 32.25,46.705 v2(32.25,51.95) v2(32.25,52.25)
  Signal Layer 1 w0.6: v3(30.2,46.05) 30.202,46.052 v3(31.597,46.052)
  Signal Layer 2 w0.3: v3(28.051,49.678) v3@28.051,49.724
  Signal Layer 2 w0.6: v3(28.825,46.15) 28.923,46.052 v3(31.597,46.052)
  Signal Layer 3 w0.6: 31.575,47.75 31.575,46.075 v3(31.597,46.052) 31.595,46.05 v3(30.9,46.05) ; v3(30.9,46.05) v3(30.2,46.05) 31.562,47.412 31.562,46.987 30.9,46.325 v3(30.9,46.05)
  Signal Layer 4 w0.2: 62.355,24.455 62.355,25.056 63.639,26.34 64.15,26.34 64.78,26.97 64.78,27.39
  Signal Layer 4 w0.3: v3(9.325,42.975) 10.25,43.9 v3(11.775,43.9) ; v3(10.15,52.4) 10.475,52.075 v3(10.475,49.4) 10.475,48.8 v3(11.775,47.5) v3(11.775,46.3) v3(11.775,45.1) v3(11.775,43.9) ; 21.38,61.58 21.38,56.02 v3(24.675,52.875) 22.74,51.14 15.24,51.14 v3(14.275,50.175) v3(14.275,49.075) 13.63,48.43 13.63,47.52 v3(14.275,46.875) v3(14.275,45.775) v3(14.275,44.675) v3(14.275,43.575) v3(14.275,42.475) 13.2,42.475 ; v3@28.112,49.738 v3(28.051,49.678) 28.051,50.176 28.4,50.525 29.975,50.525 30.59,49.91 30.59,47.915 v3(28.825,46.15) ; 29.9,47.5 28.825,46.425 v3(28.825,46.15) ; v3(31.597,46.052) 29.027,46.052 28.975,46 v3(28.825,46.15) ; v1(32.65,6.825) 32.65,6.2 ; v1(37.65,6.755) 37.65,6.21 ; v3(46.4,7.675) 47.485,6.59 49.98,6.59 50.68,6.59 ; v3(47.9,18.9) 49.47,18.9 52.72,15.65 53.15,15.65 53.2,15.7 ; 52.964,15.7 53.2,15.7 ; v3(55.28,8.315) 55.28,9.045 55.26,9.065 53.06,9.065 ; v1(59.675,62.655) 59.675,61.6 60,61.275 61.625,61.275 62.25,60.65 ; v3(61.5,38.55) 61.5,40.99 ; v3(61.725,49.625) 61.725,51.025 v3(62.925,52.225) 65.275,54.575 v3(65.375,54.575) 66.165,55.365 68.71,55.365 ; 62.355,24.455 62.355,21.815 61.33,20.79 61.33,18.14 59.18,15.99 v3(59.18,13.125) ; v3(63.25,10.925) 61.38,10.925 v3(59.18,13.125) ; 64.78,27.39 64.78,31.765 65.857,32.842 65.857,33.004 68.58,35.726 68.58,36.34 68.18,36.74 68.18,37.715 65.03,40.865 61.625,40.865 61.5,40.99 ; v3(70.55,57.375) 68.71,55.535 68.71,55.365 ; v3(11.775,43.9) 13.2,42.475 ; 13.2,42.475 13.2,40.46 9.755,37.015 9.755,35.315 11.98,33.09 16.93,33.09 19.13,35.29 21.505,35.29 25.93,39.715 ; 25.93,39.715 27.405,41.19 27.405,44.73 v3(28.825,46.15) ; 25.93,39.715 25.955,39.715 28.13,37.54 28.13,30.58 v3(27.875,30.325) 30.785,27.415 31.53,27.415 35.625,23.32 35.625,19.55 34.075,18 v3(33.225,18) 30.19,18 24.73,12.54 24.73,7.14 25.67,6.2 32.65,6.2 ; 32.65,6.2 37.65,6.2 37.65,6.21 ; 37.65,6.21 39.045,4.815 46.63,4.815 47.655,3.79 59.555,3.79 61.5,5.735 61.5,7.511 61.036,7.975 59.165,7.975 57.78,6.59 50.68,6.59 ; 50.68,6.59 50.697,6.607 50.697,7.307 52.455,9.065 53.06,9.065 ; 53.06,9.065 54.1,10.105 v3(54.1,13.125) ; 53.2,15.7 54.1,14.8 v3(54.1,13.125) ; v3(54.1,13.125) v3(59.18,13.125) ; 61.5,40.99 61.5,46.55 v3(61.35,46.7) 61.875,46.7 62.22,46.7 62.83,46.09 62.83,45.665 64.07,44.425 v3(64.325,44.425) 65.065,44.425 66.43,45.79 69.18,45.79 69.995,44.975 v3(71.35,44.975) 73.5,47.125 v3(73.5,49.575) 73.497,49.575 70.075,52.997 v3(70.075,54) 68.71,55.365
  Signal Layer 4 w0.6: v3@60.85,47.7 61.25,47.3 61.275,47.3 ; v3(61.35,46.7) 60.825,47.225 v3(60.825,47.75) v3@60.85,47.725 ; 61.875,46.7 61.275,47.3 ; 62.22,46.7 62.3,46.78 62.3,49.05 v3(61.725,49.625) 61.725,48.6 v3@60.85,47.725 ; v3@60.85,47.725 61.275,47.3 ; v3@60.85,47.725 61.75,47.725 61.9,47.875 61.9,47.3 61.275,47.3
  Bottom Layer w0.3: v3(14.275,45.775) CN15.4@15.6,45.775 ; L11.2@27.1,29.4 27.1,29.55 v3(27.875,30.325) ; v1(32.65,6.825) R167.1@32.65,7.55 ; v1(37.65,6.755) R166.1@37.65,7.48 ; v3(54.1,13.125) CN16.4@54.1,14.904 ; v3(59.18,13.125) CN16.2@59.18,14.904 ; v3(60.825,47.75) R140.2@61.55,47.75 ; v3(61.725,49.625) R134.2@63.825,49.625 ; v3(62.925,52.225) 63.8,52.225 R127.2@63.825,52.25 ; v3(70.55,57.375) R114.2@71.35,57.375
  Bottom Layer w0.6: v3(30.2,46.05) v3(30.9,46.05) 31.595,46.05 v3(31.597,46.052)
3V3_AVDD_GMII: C173.2 C174.2 C175.2 C176.2 L10.1 U18.11 U18.40 | length 7.8
  Top Layer w0.3: v3(26.85,20.4) U18.40@26.85,20.95 ; L10.1@31.75,18.9 v3(31.75,20.4) U18.11@31.75,20.95
  Bottom Layer w0.3: v3(26.85,20.4) 27.1,20.15 C173.2@27.9,20.15 27.975,20.075 C176.2@29.025,20.075 C175.2@29.925,20.075 C174.2@30.825,20.075 31.425,20.075 v3(31.75,20.4)
3V3_DVDD_GMII: C74.2 C75.2 C76.1 C77.2 C78.2 C79.2 C80.2 L11.1 R52.2 R53.2 R55.2 R65.2 R75.2 R76.2 R156.1 R157.2 U18.28 U18.29 | length 80.1
  Top Layer w0.2: C80.2@25.975,26.525 25.975,26.5 25.975,26.275 26.05,26.2 26.725,26.2 27.15,25.775 27.75,25.775 27.9,25.625 U18.29@27.9,25.2 ; C79.2@26.8,26.7 C79.2@26.85,26.75 27.45,26.15 28.125,26.15 28.3,25.975 U18.28@28.3,25.2
  Top Layer w0.3: R65.2@24.95,25.3 24.95,25.475 C80.2@25.975,26.5 ; C80.2@25.975,26.525 26.05,26.6 C78.2@26.05,27.65 C77.2@26.05,28.55 C75.2@26.05,29.45 C74.2@26.05,30.35 v3(26.725,30.35) ; C79.2@26.85,26.75 26.85,27.4 C76.1@27.125,27.675 27.125,28.35 v3(27.126,28.351) ; R52.2@32.275,30.4 v3(33.1,30.4) ; R75.2@33.525,20.75 R76.2@34.6,20.75 34.58,20.73 34.7,20.61 v3(34.7,19.925) ; R53.2@33.975,30.4 v3(34.8,30.4) ; R55.2@37.4,30.4 v3(38.225,30.4)
  Signal Layer 4 w0.5: v3(1.8,22.75) 5.1,22.75 v3(5.15,22.8) 8.365,22.8 11.005,25.44 12.79,25.44 17.265,29.915 18.605,29.915 20.205,31.515 25.56,31.515 v3(26.725,30.35) 26.725,28.753 v3(27.126,28.351) 27.126,27.019 31.705,22.44 33.91,22.44 34.7,21.65 v3(34.7,19.925) ; v3(33.1,30.4) v3(34.8,30.4) 35.5,31.1 37.525,31.1 v3(38.225,30.4)
  Bottom Layer w0.3: R157.2@1.8,22.025 v3(1.8,22.75) ; R156.1@4.95,22.025 5.15,22.225 v3(5.15,22.8) ; L11.1@25.5,29.4 25.5,29.975 25.875,30.35 v3(26.725,30.35) ; v3(27.126,28.351) 27.45,28.675 27.647,28.675 27.797,28.525 28.253,28.525 28.575,28.847 28.575,29.303 28.227,29.651 28.227,29.899 28.425,30.097 28.425,30.11 29.265,30.95 29.928,30.95 30.478,30.4 30.622,30.4 31.172,30.95 31.628,30.95 32.178,30.4 v3(33.1,30.4)
3V3_HDMI: C20.2 R154.2 U4.18 | length 103.6
  Top Layer w0.3: v3(26.875,54.475) 26.9,54.475 27.425,54.475 28.175,55.225 ; C20.2@27.2,55.075 27.35,55.225 27.65,55.225 ; U4.18@29.9,55.275 28.486,55.275 28.436,55.225 28.175,55.225 ; 27.65,55.225 27.2,54.775 27.35,54.775 27.8,55.225 ; 27.65,55.225 27.8,55.225 ; 27.8,55.225 28.175,55.225
  Top Layer w0.5: v3(26.875,54.475) 26.875,54.45 26.9,54.475 27.2,54.775 C20.2@27.2,55.075
  Signal Layer 2 w0.5: v3(26.875,54.475) 27.275,54.475 28.325,53.425 28.325,52.075 32.525,47.875 39.85,47.875 40.825,48.85 42.35,48.85 42.65,49.15 42.65,56.1 44.5,57.95 57.725,57.95 59.975,55.7 69.397,55.7 70.95,54.147 v3(70.95,53.375)
  Signal Layer 3 w0.5: v3(68.425,21.175) 67.325,22.275 67.325,26.561 67.35,26.586 67.35,30.825 69.765,33.24 69.944,33.24 71.019,34.315 72,34.315 74.475,36.79 74.475,41.55 73.05,42.975 73.05,48.775 70.65,51.175 70.65,53.075 v3(70.95,53.375)
  Bottom Layer w0.4: v3(68.425,21.175) R154.2@68.425,21.975
3V3_IOVCC: C140.2 C154.2 C171.2 R154.1 U14.3 U14.21 U14.46 | length 27.3
  Top Layer w0.3: U14.21@66.875,30.475 v3(68.1,30.475) ; U14.46@71.925,22.425 v3(71.925,23.65) ; U14.3@74.925,32.025 74.925,31.425 v3(75.4,30.95)
  Signal Layer 4 w0.5: v3(71.925,23.65) 71.115,22.84 69.235,22.84 v3(68.425,23.65) 67.23,24.845 67.23,29.605 v3(68.1,30.475) 69.44,31.815 74.535,31.815 v3(75.4,30.95)
  Bottom Layer w0.3: C154.2@67.325,30.475 v3(68.1,30.475) ; R154.1@68.425,22.875 v3(68.425,23.65) ; C171.2@71.925,22.875 v3(71.925,23.65) ; v3(75.4,30.95) 75.7,31.25 C140.2@75.7,32.025
3V3_ST_LINK: C93.2 C181.2 C184.2 C186.2 C188.2 C190.2 CN12.1 LD4.4 R158.2 R161.2 T3.3 U19.1 U19.9 U19.24 U19.36 U19.48 U34.5 | length 71.8
  Top Layer w0.3: C93.2@64.9,18.225 65.545,18.225 v3(65.898,17.872) 66.25,17.52 U19.1@66.25,17.225 ; U19.9@66.25,13.225 v3(67.525,13.225) ; v3(66.95,19.2) 67.425,18.725 U19.48@67.75,18.725 ; U19.24@73.25,10.225 73.25,9.825 74.025,9.825 v3(74.075,9.775) ; U19.36@74.75,17.225 v3(74.75,18.025)
  Top Layer w0.5: CN12.1@81.69,1.525 81.69,5.465 82.375,6.15 LD4.4@82.375,7.15
  Signal Layer 3 w0.5: v3(71.675,5.1) 71.675,7.375 v3(74.075,9.775) 75.845,9.775 76.83,8.79 78.93,8.79 81.69,6.03 CN12.1@81.69,1.525
  Signal Layer 4 w0.5: v3(65.898,17.872) 65.898,18.147 v3@65.905,18.155 ; v3(66.95,19.2) v3@65.905,18.155 ; v3(74.75,18.025) 74.75,15.895 75.305,15.34 75.305,10.74 74.34,9.775 v3(74.075,9.775) 69.215,9.775 67.525,11.465 v3(67.525,13.225) 65.905,14.845 v3@65.905,18.155
  Bottom Layer w0.3: C184.2@66.7,13.225 v3(67.525,13.225) 68.35,13.225 R161.2@68.45,13.325 ; C186.2@73.25,9.775 v3(74.075,9.775) ; R158.2@73.45,18.725 74.05,18.725 v3(74.75,18.025) 74.3,17.575 C181.2@74.3,17.225
  Bottom Layer w0.4: C188.2@79.425,7.575 79.85,7.575 80.3,8.025 U34.5@80.8,8.025 80.85,7.975 C190.2@80.85,6.4 80.85,5.365 81.69,4.525 CN12.1@81.69,1.525
  Bottom Layer w0.5: T3.3@70.525,5.175 70.6,5.1 v3(71.675,5.1)
5V: CN16.5 R165.2 | length 1.9
  Bottom Layer w0.3: R165.2@51.55,9.575 R165.2@51.56,9.585
  Bottom Layer w0.4: R165.2@51.56,9.585 CN16.5@51.56,11.475
5V_USB_ST_LINK: CN11.1 D2.1 R99.1 U21.5 | length 13.9
  Top Layer w0.3: CN11.1@74.2,4.15 74.2,7.525 73.575,8.15 R99.1@73.575,8.775 73.625,8.725 v3(74.4,8.725) ; U21.5@77.775,12.905 v3(77.775,13.9)
  Bottom Layer w0.4: v3(74.4,8.725) 75.355,9.68 D2.1@75.355,11.875 75.355,12.505 76.025,13.175 77.05,13.175 v3(77.775,13.9)
5V_VIN: C4.2 C5.2 C26.2 C27.2 C41.2 C43.2 C55.2 C56.2 C60.1 CN2.2 CN2.4 D1.1 F1.1 L8.1 Q1.4 Q2.1 Q2.2 Q2.3 R9.1 R12.2 R32.2 R41.2 R97.2 R98.2 R165.1 T1.5 T1.6 T1.7 T1.8 U4.8 U4.12 U4.19 U4.24 U4.28 U4.36 U12.24 U23.1 | length 428.4
  Top Layer w0.2: U4.12@30.65,57.875 U4.12@30.65,57.925 ; U4.8@32.25,57.925 32.25,59.76 32.25,59.775 C5.2@32.25,60.25 32.25,60.325 32.25,60.575
  Top Layer w0.3: 26.85,60.25 27.122,60.25 27.2,60.25 27.335,60.115 27.85,59.6 ; 28.55,54.65 28.775,54.875 U4.19@29.9,54.875 ; 29.325,59.414 29.325,59.478 29.203,59.6 29.334,59.6 29.405,59.6 30.65,58.355 U4.12@30.65,57.925 ; 29.895,49.63 30.04,49.775 ; C41.2@30.253,50.478 C41.2@30.253,50.442 ; 30.59,50.6 C41.2@30.646,50.544 ; 30.925,51.8 30.925,52 ; U4.24@31.05,53.025 31.05,52.4 ; U4.8@32.25,57.925 32.25,59.76 32.25,59.775 32.25,60.325 32.25,60.575 ; U4.28@32.65,53.025 32.65,51.925 ; v3@32.8,60.85 32.8,60.875 v3@32.8,60.9 ; 32.875,51.5 32.65,51.725 32.65,51.925 ; 33.713,50.662 33.713,50.863 ; C43.2@34.025,49.975 34.025,50.05 34.163,50.188 34.275,50.3 33.713,50.863 ; U4.36@35.8,54.075 C26.2@36.85,54.075 ; R9.1@37.625,54.675 R9.1@37.639,54.675 ; R9.1@37.846,54.821 37.993,54.675 ; v3(38.375,52.45) 39.325,52.45 R12.2@39.461,52.586 ; v3(38.575,54.125) v3@38.543,54.125 ; C55.2@73.05,44.35 C56.2@74.4,44.35 L8.1@75.5,44.35 ; v3(75.5,45.775) L8.1@75.5,44.35 ; R32.2@76.575,42.625 76.575,43.275 L8.1@75.5,44.35 ; U12.24@78.35,38.55 78.55,38.55 78.95,38.95 82.47,38.95 v3(82.725,38.695) ; v3(83.925,8.55) R97.2@83.925,9.375 ; v3(84.975,8.55) R98.2@84.975,9.375 ; v3(86.55,5.925) F1.1@87.425,5.925 ; F1.1@87.475,5.975 F1.1@87.425,5.925 ; F1.1@87.5,5.95 F1.1@87.475,5.925 F1.1@87.425,5.925 ; 29.55,49.475 29.578,49.475 ; 29.55,49.475 29.15,49.075 29.178,49.075 29.578,49.475 ; 29.55,49.475 29.55,49.612 v1(29.55,49.738) C41.2@30.253,50.442 ; 29.578,49.475 29.878,49.775 ; 29.578,49.475 30.533,49.475 30.895,49.837 30.895,50.05 ; 29.878,49.775 30.04,49.775 ; 29.878,49.775 C41.2@30.126,50.024 ; 30.04,49.775 30.5,49.775 30.749,50.024 ; C41.2@30.126,50.024 C41.2@30.646,50.544 ; C41.2@30.126,50.024 C41.2@30.676,50.024 ; C41.2@30.253,50.442 C41.2@30.287,50.475 ; C41.2@30.287,50.475 30.431,50.619 ; C41.2@30.287,50.475 30.575,50.475 30.52,50.53 30.431,50.619 ; 30.375,50.975 30.375,51.372 ; 30.375,50.975 30.375,50.675 30.431,50.619 ; 30.375,50.975 30.437,50.975 30.925,51.463 30.925,51.7 ; 30.375,51.372 30.775,51.772 ; 30.375,51.372 30.597,51.372 30.925,51.7 ; 30.431,50.619 30.85,51.038 ; C41.2@30.646,50.544 30.85,50.747 30.85,51.038 ; C41.2@30.646,50.544 30.676,50.514 C41.2@30.676,50.024 ; C41.2@30.676,50.024 30.749,50.024 ; 30.749,50.024 30.775,50.05 ; 30.775,50.05 30.895,50.17 ; 30.775,50.05 30.895,50.05 ; 30.775,51.772 30.775,52.15 ; 30.775,51.772 30.853,51.772 30.925,51.7 ; 30.775,52.15 30.775,52.25 30.925,52.4 ; 30.775,52.15 30.925,52 ; 30.85,51.038 31.05,51.238 ; 30.85,51.038 30.85,51.075 ; 30.85,51.075 30.868,51.057 30.895,51.03 30.895,50.17 ; 30.85,51.075 31.05,51.275 ; 30.895,50.05 30.895,50.17 ; 30.895,50.17 31.05,50.325 31.05,51.238 ; 30.925,52 30.925,52.4 ; 30.925,52.4 31.05,52.4 ; 31.05,51.238 31.05,51.275 ; 31.05,51.275 31.05,52.4 ; 32.65,51.925 33.713,50.863 ; R9.1@37.639,54.675 37.839,54.475 38.064,54.25 38.064,54.266 ; R9.1@37.639,54.675 R9.1@37.655,54.675 ; R9.1@37.655,54.675 37.993,54.675 ; R9.1@37.655,54.675 37.855,54.475 38.064,54.266 ; 37.993,54.675 38.064,54.604 ; 38.064,54.266 38.064,54.604 ; 38.064,54.266 38.205,54.125 v3@38.543,54.125 ; 38.064,54.604 v3@38.543,54.125
  Top Layer w0.36: 32.65,51.725 32.65,51.225 ; 32.875,51.5 33.337,51.038 ; 33.1,51.275 33.713,50.662 ; C43.2@33.786,49.814 33.737,49.814 32.65,50.901 32.65,51.225 ; C43.2@33.85,50.025 32.65,51.225 ; 33.85,50.525 33.713,50.662 ; v1(34.675,49.3) 34.725,49.25 v1@34.75,49.25 ; 33.713,50.662 33.713,50.638 34.163,50.188 34.2,50.15 ; 34.2,50.15 34.65,49.7 34.3,49.7 v1@34.75,49.25 ; 34.2,50.15 34.25,50.15 v1(35.15,49.25) v1@34.75,49.25
  Top Layer w0.4: v3(11.4,35.825) 11.4,35.85 v3(10.95,36.3) R41.2@10.95,37.225 Q1.4@12.15,37.225 ; 26.85,60.25 26.985,60.115 27.122,59.978 27.5,59.6 ; 27.925,59.575 v3(26.075,59.575) 26.1,59.6 27.5,59.6 ; 29.203,59.6 29.139,59.6 ; 29.325,59.478 29.293,59.446 ; 29.334,59.6 30.425,58.509 ; U4.12@30.6,57.925 30.45,57.925 29.345,59.03 ; U4.12@30.6,58.15 30.589,58.15 29.325,59.414 29.293,59.446 ; C5.2@32.25,60.325 32.525,60.6 32.8,60.875 v3(32.825,60.9) ; C43.2@33.737,49.814 33.737,49.788 v1(34.25,49.275) 34.65,49.275 v1(34.675,49.3) ; v3(15.7,38.95) v3(15.7,38.2) 16.325,38.2 ; v3(15.7,38.95) 15.7,39.9 ; v3(15.7,38.95) C60.1@16.4,38.95 ; 15.7,39.9 v3(15.7,40.9) ; 15.7,39.9 C60.1@17.35,39.9 ; v3(15.7,40.9) 17.35,40.9 C60.1@17.35,39.9 ; v3(15.7,40.9) 15.675,40.9 v3(15.7,40.9) ; 16.325,38.2 16.325,38.875 C60.1@16.4,38.95 ; 16.325,38.2 Q2.3@16.325,37.35 Q2.2@16.975,37.35 ; C60.1@16.4,38.95 C60.1@16.975,39.525 ; Q2.2@16.975,37.35 Q2.1@17.625,37.35 17.625,39.625 C60.1@17.35,39.9 ; Q2.2@16.975,37.35 C60.1@16.975,39.525 ; C60.1@16.975,39.525 C60.1@17.35,39.9 ; 27.5,59.6 27.85,59.6 28.1,59.6 29.139,59.6 ; 29.139,59.6 29.293,59.446 ; 29.147,59.299 29.076,59.299 29.345,59.03 ; 29.147,59.299 29.345,59.101 29.345,59.03 ; 29.147,59.299 29.293,59.446
  Top Layer w0.5: v3(26.075,60.825) 26.725,60.825 ; 26.15,64.964 26.15,64.855 ; 26.985,60.115 27.122,60.115 ; v3@27.1,53.1 v3(27.1,53.175) ; 27.122,59.69 27.122,59.778 27.122,59.978 27.122,60.115 ; 27.4,53.275 27.4,53.6 28.45,54.65 ; 27.797,64.375 27.522,64.375 27.497,64.4 v3(27.278,64.4) 27.278,64.3 26.15,64.3 26.15,64.855 ; 28.1,59.6 28.15,59.65 C4.2@28.15,60.115 ; C4.2@28.15,60.275 C4.2@28.15,60.115 ; 28.985,59.62 28.8,59.805 28.8,59.825 28.51,60.115 C4.2@28.15,60.115 ; C26.2@36.7,53.825 36.9,53.625 36.9,53.2 37.35,52.75 v3(37.55,52.75) ; R9.1@37.8,54.475 37.839,54.475 R9.1@37.855,54.475 ; 26.15,64.855 26.525,64.855 26.45,64.78 26.45,64.425 U23.1@26.65,64.425 ; U23.1@26.65,64.425 27.4,64.425 27.4,64.497 27.2,64.697 27.2,64.855 26.65,64.855 U23.1@26.65,64.425 ; 26.725,60.825 27.115,60.825 27.435,60.505 27.435,60.115 ; 26.725,60.825 27.122,60.428 ; 27.122,60.115 27.122,60.25 27.122,60.428 ; 27.122,60.115 27.335,60.115 27.435,60.115 ; 27.122,60.428 27.435,60.115 ; 27.435,60.115 C4.2@28.065,60.115 C4.2@28.15,60.115
  Top Layer w0.6: v3(26.075,59.575) v3(26.075,60.2) ; v3(26.475,52.904) 26.829,52.904 v3(27.1,53.175) 27.2,53.275 C27.2@27.2,53.75 ; 26.85,60.25 26.65,60.25 ; 27.122,59.69 26.585,59.69 v3(26.075,60.2) ; 27.122,59.778 26.65,60.25 ; v1(28.625,48.625) 29.1,48.625 29.125,48.65 29.15,48.65 ; v1@29.075,49 v1@29.15,49.075 ; v1(29.55,49.738) v1@29.423,49.738 ; v1@29.562,49.6 29.55,49.612 v1@29.423,49.738 ; C5.2@31.98,60.03 32.25,59.76 32.35,59.66 ; 32.25,59.775 32.35,59.675 ; v3@32.825,60.875 v3(32.825,60.9) 32.8,60.9 v3@31.8,60.9 ; v3(26.075,60.2) v3(26.075,60.825) 26.65,60.25 ; 28.15,48.65 28.575,49.075 28.675,49.075 ; 28.15,48.65 28.25,48.65 ; 28.15,48.65 28.2,48.6 28.25,48.65 ; 28.25,48.65 28.675,49.075 ; 28.25,48.65 28.762,48.65 28.762,49.075 ; 28.675,49.075 28.762,49.162 ; 28.675,49.075 28.762,49.075 ; 28.762,49.075 v1@29.15,49.075 ; 28.762,49.075 28.762,49.162 ; 28.762,49.162 28.762,49.188 29.312,49.738 v1@29.423,49.738 ; 28.762,49.162 28.797,49.197 v1(29.09,49.13) v1@29.15,49.075 ; v3(31.775,60.9) 31.825,60.85 v3@31.825,60.675 ; v3(31.775,60.9) 31.775,60.725 v3@31.825,60.675 ; v3(31.775,60.9) v3@31.8,60.9 ; v3@31.8,60.9 31.95,60.75 31.95,60.6 32.525,60.6 32.55,60.6 32.8,60.85 32.8,59.887 ; v3@31.825,60.675 C5.2@32,60.5 ; C5.2@32,60.5 31.825,60.325 v3(31.825,60.245) 32.245,60.245 C5.2@32.25,60.25 C5.2@32,60.5 ; 32.35,59.66 32.425,59.585 32.425,59.25 ; 32.35,59.66 32.35,59.675 ; 32.35,59.66 32.35,59.325 32.425,59.25 ; 32.35,59.675 32.588,59.675 32.8,59.887 ; 32.425,59.25 32.8,59.625 32.8,59.887
  Signal Layer 1 w0.4: v1(34.25,49.275) 34.6,49.275 v1@34.675,49.2 ; 34.7,49.05 34.675,49.075 v1@34.675,49.2 ; v1@35.15,49.138 v1(35.15,49.25) 34.725,49.25 v1(34.675,49.3) v1@34.675,49.2
  Signal Layer 1 w0.6: v3(26.075,59.575) v3(26.075,60.2) v3(26.075,60.825) ; 26.6,52.6 27.1,53.1 v3(27.1,53.175) ; v1(29.09,49.13) v1@29.15,49.025 ; v1(29.55,49.738) 29.219,49.738 29.2,49.758 28.092,48.65 28.117,48.625 v1(28.625,48.625) v1@28.7,48.625 ; v1@28.7,48.625 v1@28.75,48.625 ; v1@28.7,48.625 28.725,48.6 v1@28.75,48.625 ; v1@28.75,48.625 v1@29.15,49.025 ; v1@28.75,48.625 29.05,48.625 29.15,48.725 v1@29.15,49.025
  Signal Layer 2 w0.3: v3(26.475,52.904) 26.475,52.704 26.601,52.578 26.755,52.578 26.778,52.6 26.801,52.624
  Signal Layer 2 w0.4: v1(34.25,49.275) 34.6,49.275 v1@34.675,49.2 ; v1(34.675,49.3) 34.725,49.25 v1(35.15,49.25)
  Signal Layer 2 w0.6: v3(15.7,40.9) v3(15.7,38.95) v3(15.7,38.2) 13.8,36.3 ; v3(26.075,59.575) v3(26.075,60.2) v3(26.075,60.825) ; v3@26.475,52.704 26.475,52.678 26.603,52.55 26.602,52.569 26.601,52.578 26.601,52.579 26.6,52.6 26.778,52.6 ; 26.801,52.624 27.1,52.922 v3(27.1,53.175) ; v1(28.625,48.625) 28.625,48.978 27.753,48.978 28.13,48.6 28.625,49.095 ; v1@29.029,49.062 v1(29.09,49.13) ; v1@29.425,49.7 28.963,49.674 v1(29.09,49.13) ; v3(31.775,60.9) v3(32.825,60.9) ; 13.8,36.3 v3(10.95,36.3) 10.95,36.275 v3(11.4,35.825) 13.325,35.825 13.8,36.3 ; 28.727,49.197 28.672,49.142 28.672,49.197 28.727,49.197 ; 28.727,49.197 28.732,49.196 v1(29.09,49.13)
  Signal Layer 3 w0.4: v1(34.25,49.275) 34.6,49.275 v1@34.675,49.2 ; v1(34.675,49.3) v1@34.675,49.2 ; 35.05,48.825 34.962,48.913 ; v1(35.15,49.25) 35.15,49.15 35.025,49.025 34.925,49.125 34.875,49.125 ; 34.625,48.875 34.575,48.925 34.7,49.05 34.675,49.075 v1@34.675,49.2 ; 34.625,48.875 34.925,48.875 ; 34.625,48.875 34.775,48.725 34.925,48.875 ; v1@34.675,49.2 v1@34.75,49.125 ; v1@34.75,49.125 34.888,48.987 34.962,48.913 ; v1@34.75,49.125 34.875,49.125 ; 34.875,49.125 35.025,48.975 34.962,48.913 ; 34.925,48.875 34.962,48.913
  Signal Layer 3 w0.6: v3(15.7,40.9) v3(15.7,38.95) v3(15.7,38.2) 13.8,36.3 ; v3(26.075,59.575) v3(26.075,60.2) v3(26.075,60.825) ; v3(26.475,52.904) 26.475,52.678 26.603,52.55 26.602,52.569 26.601,52.579 26.6,52.6 27.1,53.1 v3(27.1,53.175) ; v1(28.625,48.625) 28.625,48.813 v1(29.55,49.738) ; v3(31.825,60.245) 31.825,60.85 v3(31.775,60.9) v3(32.825,60.9) ; 13.8,36.3 v3(10.95,36.3) 10.95,36.275 v3(11.4,35.825) 13.325,35.825 13.8,36.3
  Signal Layer 4 w0.3: v3(10.95,36.3) 13.85,36.3 15.7,38.15 v3(15.7,38.2) v3(15.7,38.95) v3(15.7,40.9) 15.925,40.675 20.15,40.675 25.76,46.285 ; v1(29.55,49.738) 29.55,49.475 28.325,48.25 27.147,48.25 26.825,47.928 26.825,47.35 25.76,46.285 ; v3@32.75,60.825 v3(32.825,60.9) 31.945,60.9 31.405,61.44 31.405,64.415 ; v1(34.25,49.275) 34.58,49.605 ; v1(34.675,49.3) 35.1,49.3 v1(35.15,49.25) 35.15,49.026 ; 34.85,49.125 34.887,49.088 34.887,48.763 ; v3@38.525,52.6 v3(38.375,52.45) 38.075,52.75 v3(37.55,52.75) ; v3(38.575,54.125) 38.24,54.125 37.958,53.843 37.55,53.435 v3(37.55,52.75) ; v3(52.955,8.09) 52.955,7.865 52.93,7.84 53.705,7.065 56.443,7.065 57.025,7.647 57.025,7.66 58.9,9.535 59.374,9.535 59.414,9.495 59.786,9.495 59.826,9.535 64.01,9.535 67.73,5.815 67.73,4.94 68.38,4.29 69.53,4.29 71.13,5.89 81.265,5.89 v3(83.925,8.55) v3(84.975,8.55) 84.975,22.295 83.75,23.52 v3(83.75,31.475) ; 70.05,63.19 69.525,62.665 65.56,62.665 63.81,64.415 62.044,64.415 61.992,64.467 61.619,64.467 61.278,64.125 35.289,64.125 34.999,64.415 32.306,64.415 32.266,64.454 31.894,64.454 31.854,64.415 31.405,64.415 ; v3(75.5,45.775) 75.938,46.213 77.632,46.213 80.155,43.69 80.155,40.645 82.105,38.695 v3(82.725,38.695) 82.9,38.52 v3(82.9,32.275) ; 25.76,46.285 24.555,47.49 24.555,50.94 26.193,52.578 ; 26.193,52.578 26.475,52.86 v3(26.475,52.904) 26.801,52.578 28.949,54.725 31.825,54.725 34.58,51.97 34.58,49.605 ; 26.193,52.578 25.992,52.578 24.755,53.815 24.755,56.502 25.125,56.872 25.125,58.647 24.525,59.247 24.525,59.878 24.847,60.2 25.45,60.2 v3(26.075,60.825) 26.075,63.085 27.165,64.175 27.415,63.925 28.95,63.925 29.126,64.101 29.126,64.214 29.351,64.44 29.554,64.44 29.894,64.1 30.266,64.1 30.341,64.175 31.165,64.175 31.405,64.415 ; 34.58,49.605 34.58,49.07 34.887,48.763 ; 34.887,48.763 34.975,48.675 34.975,47.553 ; 34.887,48.763 35.15,49.026 ; 34.975,47.553 35.15,47.728 35.15,49.026 ; 34.975,47.553 35.425,47.103 35.425,45.455 35.63,45.25 35.575,45.195 36.505,44.265 37.83,44.265 38.505,44.94 38.505,49.165 37.55,50.12 v3(37.55,52.75) ; v3(82.9,32.275) 82.75,32.275 v3(81.95,31.475) v3(83.75,31.475) ; v3(82.9,32.275) 82.95,32.275 v3(83.75,31.475)
  Signal Layer 4 w0.4: v3(37.55,52.75) 37.85,52.45 v3(38.375,52.45) ; 37.958,53.843 38.05,53.75 ; 38.25,54.826 38.25,55.075
  Signal Layer 4 w0.5: 27.375,67.605 27.37,67.61 CN2.2@27.37,68.77 CN2.4@29.91,68.77 ; 29.9,67.605 29.91,67.615 CN2.4@29.91,68.77 ; 31.075,68.775 31.07,68.77 CN2.4@29.91,68.77
  Signal Layer 4 w1.3: 69.58,63.19 70.05,63.19
  Bottom Layer w0.3: R165.1@51.55,8.675 51.55,8.095 51.905,7.74 52.605,7.74 v3(52.955,8.09)
  Bottom Layer w0.4: v1(34.25,49.275) 34.6,49.275 v1@34.675,49.2 ; 34.875,49.125 35.025,48.975 34.962,48.913 ; 35.475,48.4 34.962,48.913 ; 35.63,48.555 35.15,49.035 v1(35.15,49.25) 34.725,49.25 v1(34.675,49.3) v1@34.675,49.2 ; v3(83.925,8.55) v3@84.175,8.55 ; D1.1@84.575,10.005 84.575,8.95 ; v3(86.55,5.925) 86.55,6.975 v3(84.975,8.55) ; v1@34.675,49.2 34.888,48.987 34.962,48.913 ; v1@34.675,49.2 34.675,49.075 34.7,49.05 34.575,48.925 34.775,48.725 34.962,48.913 ; v3@84.175,8.55 v3(84.975,8.55) ; v3@84.175,8.55 84.575,8.95 ; 84.575,8.95 v3(84.975,8.55)
  Bottom Layer w0.6: v3(10.95,36.3) 10.95,36.275 v3(11.4,35.825) ; v3(15.7,38.2) v3(15.7,38.95) ; v3(26.075,59.575) v3(26.075,60.2) v3(26.075,60.825) ; v3(26.475,52.904) 26.475,52.678 26.603,52.55 26.602,52.569 26.601,52.579 26.6,52.6 27.1,53.1 v3(27.1,53.175) ; v1(28.625,48.625) 28.625,48.813 v1(29.55,49.738) ; v3(31.825,60.245) 31.825,60.85 v3(31.775,60.9) v3(32.825,60.9)
AGND: C97.1 C100.1 C101.1 C102.1 C103.1 C107.1 C108.1 C109.1 C110.1 C111.1 CN10.2 R83.1 R92.1 R96.1 R103.1 U20.7 U20.13 U22.2 U22.4 U22.5 | length 89.7
  Top Layer w0.3: U22.4@22.95,10.65 U22.5@22.95,9.7 U22.2@25.25,9.7 v3(26.525,9.7) ; v3(26.525,7.975) 27.425,7.975 R103.1@27.45,7.95 ; v3(26.525,11.375) 27.425,11.375 R92.1@27.45,11.35 ; v3(29.625,14.15) 29.625,12.975 CN10.2@30,12.6 ; v3(38.9,9.565) 38.9,11.475 C102.1@39.525,12.1 ; v3(41.05,11.225) 41.4,11.575 U20.7@41.9,11.575 ; C110.1@41.55,7.825 41.575,7.85 v3(42.525,7.85) ; v3(44.175,7.675) C107.1@44.175,8.425 44.275,8.425 44.775,8.925 44.775,9.614 44.575,9.814 U20.13@44.575,10.4 ; C97.1@45.075,17.225 v3(45.075,17.925) ; v3(45.4,7.675) C108.1@45.4,8.425 C109.1@46.3,8.425 ; C103.1@49.075,11.575 v3(49.975,11.575) 50,11.55 R96.1@50,10.475 ; C101.1@49.65,12.7 50.475,12.7 v3(50.45,12.7) 50.825,13.075 R83.1@50.825,14.05 C100.1@49.65,14.05 ; C111.1@49.725,8.5 v3(50.575,8.5)
  Signal Layer 4 w0.3: v3(29.625,14.15) 29.3,14.15 v3(26.525,11.375) v3(26.525,9.7) v3(26.525,7.975) 31.59,7.975 32.455,8.84 38.905,8.84 ; v3(38.9,9.565) 38.905,9.56 38.905,8.84 ; v3(45.075,17.925) 46.93,17.925 ; 38.905,8.84 39.98,8.84 40.97,7.85 v3(42.525,7.85) 42.7,7.675 v3(44.175,7.675) v3(45.4,7.675) 45.4,8.01 45.89,8.5 ; 45.89,8.5 45.89,8.83 44.83,9.89 42.385,9.89 v3(41.05,11.225) 42.055,12.23 42.055,14.89 42.68,15.515 46.215,15.515 46.905,16.205 46.905,17.9 46.93,17.925 ; 45.89,8.5 v3(50.575,8.5) 49.975,9.1 v3(49.975,11.575) 49.975,12.225 v3(50.45,12.7) 50.45,15.495 48.02,17.925 46.93,17.925
AIN_1: R91.2 R94.2 U19.10 | length 2.7
  Top Layer w0.2: R94.2@64.95,10.925 R91.2@64.95,11.975 64.95,12.1 65.575,12.725 U19.10@66.25,12.725
ARD_A0: CN17.1 U13.AC4 | length 56
  Top Layer w0.1: U13.AC4@55.58,26.69 57.003,26.69 57.253,26.94 58.447,26.94 58.872,27.365 59.388,27.365 59.974,26.779 61.103,26.779 62.139,27.815 62.981,27.815 v1(63.281,28.115) v1@63.305,28.139 ; v1@63.281,28.14 v1@63.305,28.14
  Signal Layer 3 w0.1: v1(58.08,15.34) 58.175,15.435 58.175,20.896 60.944,23.665 61.908,23.665 62.38,24.137 62.38,26.81 62.305,26.885 62.305,27.41 63.01,28.115 v1(63.281,28.115)
  Bottom Layer w0.1: CN17.1@38.86,12.165 CN17.1@38.86,11.475 38.86,11.015 39.713,10.162 39.713,8.465 40.209,7.969 40.226,7.969 40.63,7.565 42.174,7.565 42.339,7.4 43.145,7.4 44.255,6.29 48.355,6.29 48.875,6.81 48.875,8.261 50.902,10.288 50.902,12.752 51.065,12.915 52.435,12.915 53.675,11.675 54.89,11.675 55.23,12.015 55.23,12.06 56.11,12.94 57.505,12.94 58.08,13.515 v1(58.08,15.34)
ARD_A1: CN17.2 U13.Y5 | length 37.3
  Top Layer w0.1: v2(53.83,27.44) U13.Y5@54.08,27.19
  Signal Layer 1 w0.1: v2(53.83,27.44) 54.105,27.165 54.105,26.79 54.005,26.69 54.005,25.715 54.28,25.44 54.504,25.44 57.404,22.54 57.506,22.54 58.18,21.866 58.18,20.914 57.575,20.309 57.575,18.91 57.055,18.39 v1(56.955,18.49)
  Signal Layer 2 w0.1: v1(37.55,16.625) 37.823,16.625 38.848,17.65 43.433,17.65 43.733,17.35 49,17.35 49.43,17.78 49.765,17.78 50.26,18.275 52.42,18.275 53.505,17.19 55.69,17.19 55.705,17.175 56.175,17.175 56.6,17.6 56.6,18.49 v1(56.955,18.49)
  Bottom Layer w0.1: CN17.2@36.32,14.904 37.404,14.904 37.55,15.05 v1(37.55,16.625) ; CN17.2@36.33,15.14 CN17.2@36.33,15.59
ARD_A2: CN17.3 U13.U3 | length 37.7
  Top Layer w0.1: v2(52.33,25.94) U13.U3@52.58,26.19
  Signal Layer 1 w0.1: v2(52.33,25.94) 52.33,25.693 53.808,24.215 54.032,24.215 56.508,21.739 v1(56.506,21.265) v1(56.506,21.265)
  Signal Layer 2 w0.1: v1(37.255,18.465) 37.338,18.465 37.973,19.1 43.792,19.1 44.067,19.375 49.475,19.375 50.225,20.125 55.44,20.125 56.506,21.191 v1(56.506,21.265)
  Bottom Layer w0.1: CN17.3@34.15,11 33.78,11.37 CN17.3@33.78,11.475 33.78,15.272 34.983,16.475 36.475,16.475 37.074,17.074 37.074,17.425 36.68,17.82 36.68,18.132 37.013,18.465 v1(37.255,18.465)
ARD_A3: CN17.4 U13.U4 | length 36.4
  Top Layer w0.1: v2(52.33,26.44) U13.U4@52.58,26.69
  Signal Layer 1 w0.1: v2(52.33,26.44) 52.005,26.115 52.005,25.735 53.725,24.015 53.949,24.015 55.955,22.009 55.955,21.415 55.98,21.415 v1(55.988,21.423)
  Signal Layer 2 w0.1: v1(37.28,19.015) 37.606,19.015 38.681,20.09 44.285,20.09 44.775,19.6 49.4,19.6 50.163,20.363 55.312,20.363 56,21.05 56,21.411 v1(55.988,21.423)
  Bottom Layer w0.1: CN17.4@31.24,14.904 33.129,14.904 34.95,16.725 36.375,16.725 36.725,17.075 36.725,17.491 36.48,17.737 36.48,18.215 v1(37.28,19.015)
ARD_A4: SB24.1 U13.W2 | length 65.7
  Top Layer w0.09: U13.W2@53.58,25.69 53.823,25.447 53.83,24.99
  Top Layer w0.1: 53.83,24.99 53.83,24.903 54.583,24.15 54.773,24.15 54.948,23.975 58.892,23.975 59.188,23.679 60.406,23.679 61.144,22.94 62.366,22.94 62.96,23.535 62.96,24.715 63.285,25.04 63.905,25.04 v1(63.98,24.965)
  Signal Layer 2 w0.1: v1(41.13,7.09) 42.175,7.09 42.475,7.39 43.025,7.39 43.19,7.225 46.586,7.225 47.376,8.015 48.225,8.015 48.675,7.565 48.675,6.933 49.133,6.475 62.449,6.475 64.78,8.806 v1(64.78,9.54)
  Bottom Layer w0.1: 35.025,9.29 36.075,10.34 36.075,10.345 36.28,10.55 36.79,10.55 39.075,8.265 39.63,8.265 40.805,7.09 v1(41.13,7.09) ; v1(63.98,24.965) 63.98,24.785 63.78,24.585 63.78,24.09 65.38,22.49 65.38,14.49 63.95,13.06 63.95,10.37 v1(64.78,9.54)
  Bottom Layer w0.3: SB24.1@35.025,9.05 35.025,9.29
ARD_A5: SB26.1 U13.Y9 | length 86.6
  Top Layer w0.1: v2(53.83,29.44) U13.Y9@54.08,29.19
  Signal Layer 1 w0.1: v2(53.83,29.44) 59.042,29.44 59.705,28.777 59.908,28.777 60.75,27.935 60.75,23.715 63.48,20.985 63.48,20.04 63.255,19.815 v1(63.131,19.815)
  Signal Layer 3 w0.1: v1(28.605,4.74) 28.605,8.78 v1(30.025,10.2) ; v1(62.23,8.14) 62.525,7.845 62.525,6.426 61.714,5.615 58.055,5.615 57.68,5.99 57.68,6.436 58.331,7.086 58.331,7.542 57.43,8.443 57.43,14.065 58.48,15.115 58.48,19.005 59.29,19.815 v1(63.131,19.815)
  Bottom Layer w0.1: v1(28.605,4.74) 29.24,5.375 39.295,5.375 39.58,5.09 49.354,5.09 50.564,6.3 54.264,6.3 56.354,8.39 56.646,8.39 56.991,8.735 61.635,8.735 v1(62.23,8.14)
  Bottom Layer w0.3: SB26.1@30.025,9.05 v1(30.025,10.2)
ARD_D0: CN14.1 U13.AA11 | length 94.2
  Top Layer w0.1: U13.AA11@54.58,30.19 v2(54.83,29.94)
  Signal Layer 1 w0.1: v2(54.83,29.94) 60.031,29.94 60.481,29.49 60.481,28.77 60.686,28.565 61.181,28.565 v1@61.48,28.864 ; v1@61.48,28.865 v1(61.53,28.915)
  Signal Layer 3 w0.1: v1(57.83,61.265) 57.83,59.848 57.98,59.698 57.98,49.609 58.339,49.25 61.011,49.25 62,48.261 62,46.377 61.26,45.637 61.26,39.992 62.587,38.665 65.595,38.665 66.525,37.735 66.525,37.389 66.655,37.259 66.655,36.895 66.155,36.395 66.155,36.087 65.809,35.741 65.806,35.741 64.53,34.465 64.53,33.89 61.53,30.89 v1(61.53,28.915)
  Bottom Layer w0.1: CN14.1@26.16,63.164 26.16,67.26 26.305,67.405 30.397,67.405 31.236,66.566 31.236,65.019 31.465,64.79 34.97,64.79 35.235,64.525 35.525,64.525 35.925,64.925 58.755,64.925 59.23,64.45 59.23,61.79 58.705,61.265 v1(57.83,61.265)
ARD_D1: CN14.2 U13.AC13 | length 88
  Top Layer w0.1: U13.AC13@55.58,31.19 57.509,31.19 57.709,30.99 58.602,30.99 59.057,30.535 60.438,30.535 60.705,30.802 60.705,31.182 61.53,32.007 61.53,33.015 62.73,34.215 63.455,34.215 63.78,34.54 63.78,35.49 v1(63.28,35.99)
  Signal Layer 2 w0.1: v1(24.88,63.49) 26.755,61.615 27.807,61.615 27.95,61.472 27.95,61.447 28.272,61.125 28.65,61.125 30.809,58.966 31.874,58.966 32.303,59.395 38.05,59.395 40.447,61.792 43.108,61.792 44.409,60.49 46.401,60.49 48.501,62.59 49.314,62.59 50.216,63.492 53.78,63.492 v1(53.93,63.642)
  Signal Layer 3 w0.1: v1(53.93,63.642) v1(53.93,63.642) 54.655,62.915 54.655,61.915 55.18,61.39 55.18,58.648 55.78,58.048 55.78,48.698 59.06,45.418 59.06,36.835 60.555,35.34 62.418,35.34 63.068,35.99 v1(63.28,35.99)
  Bottom Layer w0.1: v1(24.88,63.49) 24.88,61.99 25.395,61.475 27.625,61.475 28.7,60.4 CN14.2@28.7,59.735 CN14.2@28.7,60.51
ARD_D2: CN14.3 U13.C8 | length 51.7
  Top Layer w0.1: v1(32.08,64.004) 33.566,64.004 34.405,63.165 v1(34.805,63.165) ; v1(38.668,28.215) 38.668,28.203 38.63,28.165 39.002,28.165 39.652,27.515 40.108,27.515 40.458,27.865 41.03,27.865 41.73,28.565 v4(41.73,28.54) ; U13.C8@45.58,28.69 v2(45.83,28.94)
  Signal Layer 1 w0.1: v4(41.73,28.54) 43.354,28.54 43.754,28.94 v2(45.83,28.94)
  Signal Layer 3 w0.1: v1(34.805,63.165) 34,62.36 34,60.342 33.35,59.692 33.35,55.1 33.175,54.925 33.175,50.109 32.85,49.784 32.85,48.566 33.2,48.216 33.2,46.75 33.05,46.6 33.05,40.584 33.505,40.129 33.505,34.881 37.375,31.011 37.375,29.214 37.899,28.69 38.135,28.69 38.61,28.215 v1(38.668,28.215)
  Bottom Layer w0.1: CN14.3@31.24,63.164 31.24,63.975 32.051,63.975 v1(32.08,64.004)
ARD_D3: CN14.4 U13.L3 | length 85.5
  Top Layer w0.1: U13.L3@49.54,26.19 U13.L3@49.58,26.19 v2(49.829,26.44) v2@49.829,26.48
  Signal Layer 1 w0.1: v2@49.829,26.48 49.796,26.447 49.796,25.809 49.855,25.75 49.855,23.415 v1(49.93,23.34)
  Signal Layer 2 w0.1: v1(38.055,21.34) 38.08,21.34 38.105,21.365 38.33,21.14 39.11,21.14 39.4,21.14 39.605,21.345 39.61,21.345 39.83,21.565 40.063,21.565 40.338,21.84 45.91,21.84 46.949,20.801 48.851,20.801 49.455,21.405 49.455,22.915 49.88,23.34 v1(49.93,23.34)
  Signal Layer 3 w0.1: v1(27.75,64.925) 27.75,58.873 26.852,57.975 26.814,57.975 23.9,55.061 23.9,47.415 28.262,43.053 28.262,42.612 27.7,42.05 27.7,40.101 26.9,39.301 26.9,37.659 26.275,37.034 26.275,33.353 27.13,32.498 27.13,31.391 26.275,30.536 26.275,28.228 29.138,25.365 31.541,25.365 35.416,21.49 37.905,21.49 v1(38.055,21.34)
  Bottom Layer w0.1: v1(27.75,64.925) 27.75,62.945 28.058,62.637 28.058,61.532 28.392,61.198 30.158,61.198 30.325,61.364 33.456,61.364 33.78,61.04 CN14.4@33.78,59.735
ARD_D4: CN14.5 U13.Y15 | length 71.3
  Top Layer w0.1: U13.Y15@54.08,32.19 v2(54.33,31.94) ; v4(61.43,31.465) 61.73,31.765 61.73,32.932 62.813,34.015 63.538,34.015 63.98,34.457 63.98,35.59 63.776,35.794 63.776,36.011 v1(63.781,36.016)
  Signal Layer 1 w0.1: v2(54.33,31.94) 54.43,32.04 60.055,32.04 60.63,31.465 v4(61.43,31.465)
  Signal Layer 2 w0.1: v1(41.655,61.39) 41.857,61.592 43.025,61.592 44.327,60.29 46.483,60.29 48.583,62.39 49.397,62.39 50.299,63.292 54.232,63.292 v1(54.53,63.59)
  Signal Layer 3 w0.1: v1(54.53,63.59) 54.855,63.265 54.855,61.998 55.38,61.473 55.38,58.731 55.98,58.131 55.98,48.781 59.26,45.501 59.26,36.918 60.638,35.54 62.335,35.54 63.135,36.34 63.455,36.34 v1(63.781,36.016)
  Bottom Layer w0.1: CN14.5@36.32,63.164 36.32,64.125 40.075,64.125 40.742,63.458 40.742,61.753 41.105,61.39 v1(41.655,61.39)
ARD_D5: CN14.6 U13.J2 | length 78.6
  Top Layer w0.09: 48.28,23.227 48.525,23.472 48.525,24.184 48.725,24.384 48.725,24.827 48.58,24.972 U13.J2@48.58,25.69
  Top Layer w0.1: v1(39.83,22.615) 41.113,22.615 41.883,21.845 43.276,21.845 43.671,21.45 47.262,21.45 48.005,22.193 48.005,22.952 48.28,23.227
  Signal Layer 3 w0.1: v1(29.225,65) 29.225,64.215 28.175,63.165 28.175,56.095 27.9,55.82 27.9,52.094 28.125,51.869 28.125,50.388 27.601,49.864 27.601,45.199 29.375,43.425 29.375,41.171 29.205,41.001 29.205,39.38 28.18,38.355 28.18,31.007 28.68,30.507 28.68,29.273 31.078,26.875 31.87,26.875 32.255,26.49 32.255,25.834 35.799,22.29 39.375,22.29 39.7,22.615 v1(39.83,22.615)
  Bottom Layer w0.1: v1(29.225,65) 29.225,63.7 30.06,62.865 30.335,62.865 30.582,62.618 30.582,61.882 30.7,61.764 34.131,61.764 36.37,59.525 38.65,59.525 CN14.6@38.86,59.735
ARD_D6: CN14.7 U13.AA9 | length 65.7
  Top Layer w0.09: U13.AA9@54.58,29.19 54.83,28.94 55.331,28.94
  Top Layer w0.1: 55.331,28.941 55.47,28.941 55.474,28.945 58.102,28.945 58.312,28.735 59.061,28.735 v1(59.231,28.565)
  Signal Layer 2 w0.1: v1(42.33,61.242) 42.33,61.29 43.044,61.29 44.244,60.09 46.566,60.09 48.666,62.19 49.48,62.19 50.382,63.092 54.532,63.092 v1(55.055,63.615)
  Signal Layer 3 w0.1: v1(55.055,63.615) 55.055,62.081 55.58,61.556 55.58,58.814 56.18,58.214 56.18,48.864 59.46,45.584 59.46,37.001 60.721,35.74 62.252,35.74 63.052,36.54 63.751,36.54 64.131,36.161 64.131,35.871 64.13,35.87 64.13,34.065 59.705,29.64 59.705,29.09 59.231,28.616 v1(59.231,28.565)
  Bottom Layer w0.1: CN14.7@41.4,63.164 41.4,62.42 42.33,61.49 v1(42.33,61.242)
ARD_D7: CN14.8 U13.B9 | length 53.6
  Top Layer w0.1: v1(39.78,29.09) 39.83,29.04 40.06,29.04 40.41,28.69 40.7,28.69 41.05,29.04 42.644,29.04 42.769,28.915 43.391,28.915 43.666,29.19 U13.B9@45.08,29.19
  Signal Layer 3 w0.1: v1(36.4,61.005) 35.78,61.005 33.95,59.175 33.95,54.725 33.775,54.55 33.775,49.861 33.45,49.536 33.45,48.814 33.8,48.464 33.8,46.84 34.305,46.335 34.305,45.587 34.48,45.412 34.48,43.483 34.23,43.233 34.23,40.54 34.58,40.19 34.58,35.176 39.164,30.592 39.164,29.879 39.78,29.262 v1(39.78,29.09)
  Bottom Layer w0.1: v1(36.4,61.005) 36.411,60.994 36.978,60.994 37.65,61.666 37.65,63.026 37.949,63.325 38.636,63.325 39.125,62.836 39.125,61.57 40.83,59.865 43.811,59.865 CN14.8@43.94,59.736
ARD_D8: CN13.1 U13.T4 | length 121
  Top Layer w0.1: U13.T4@52.055,26.665 v2(52.305,26.915)
  Signal Layer 1 w0.1: v2(52.305,26.915) 51.805,26.415 51.805,25.652 53.947,23.51 53.947,22.756 54.388,22.315 55.366,22.315 55.63,22.051 55.63,21.679 55.45,21.499 55.45,19.78 55.73,19.5 55.875,19.5 56.005,19.37 56.005,18.955 v1(54.85,17.8)
  Signal Layer 2 w0.1: v1(25.33,64.065) 25.33,63.34 26.855,61.815 27.89,61.815 28.15,61.555 28.15,61.53 28.355,61.325 29.915,61.325 31.296,59.944 31.296,59.371 31.501,59.166 31.791,59.166 31.996,59.371 31.996,59.407 32.264,59.675 35.595,59.675 36.405,60.485 37.235,60.485 37.67,60.05 38.422,60.05 40.887,62.515 42.95,62.515 44.575,60.89 46.235,60.89 48.56,63.215 v1(48.93,63.215) ; v1(37.78,17.465) 37.755,17.465 38.745,18.455 44.23,18.455 44.55,18.775 45.5,18.775 46.425,17.85 48.625,17.85 49.412,18.637 49.762,18.637 50.275,19.15 50.275,19.161 50.539,19.425 53,19.425 53.675,18.75 53.675,17.765 53.85,17.59 54.64,17.59 v1(54.85,17.8)
  Signal Layer 3 w0.1: v1(25.33,64.065) 25.33,61.335 23.8,59.805 23.8,57.389 23.1,56.689 23.1,47.025 26.7,43.425 26.7,40.533 25.15,38.983 25.15,37.304 25.275,37.179 25.275,27.762 29.397,23.64 31.852,23.64 36.117,19.375 37.52,19.375 38.13,18.765 38.13,17.845 37.78,17.495 v1(37.78,17.465)
  Bottom Layer w0.1: CN13.1@48.004,63.164 48.879,63.164 v1(48.93,63.215)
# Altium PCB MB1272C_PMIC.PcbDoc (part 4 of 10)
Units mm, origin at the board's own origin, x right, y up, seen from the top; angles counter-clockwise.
Board outline 101 x 71 mm, 6 copper layers (Top Layer, Signal Layer 1, Signal Layer 2, Signal Layer 3, Signal Layer 4, Bottom Layer), stack 1.552 mm thick; 518 components, 478 nets, 2152 pads, 1871 vias.
Unrouted connection lines stored in the file: 3.

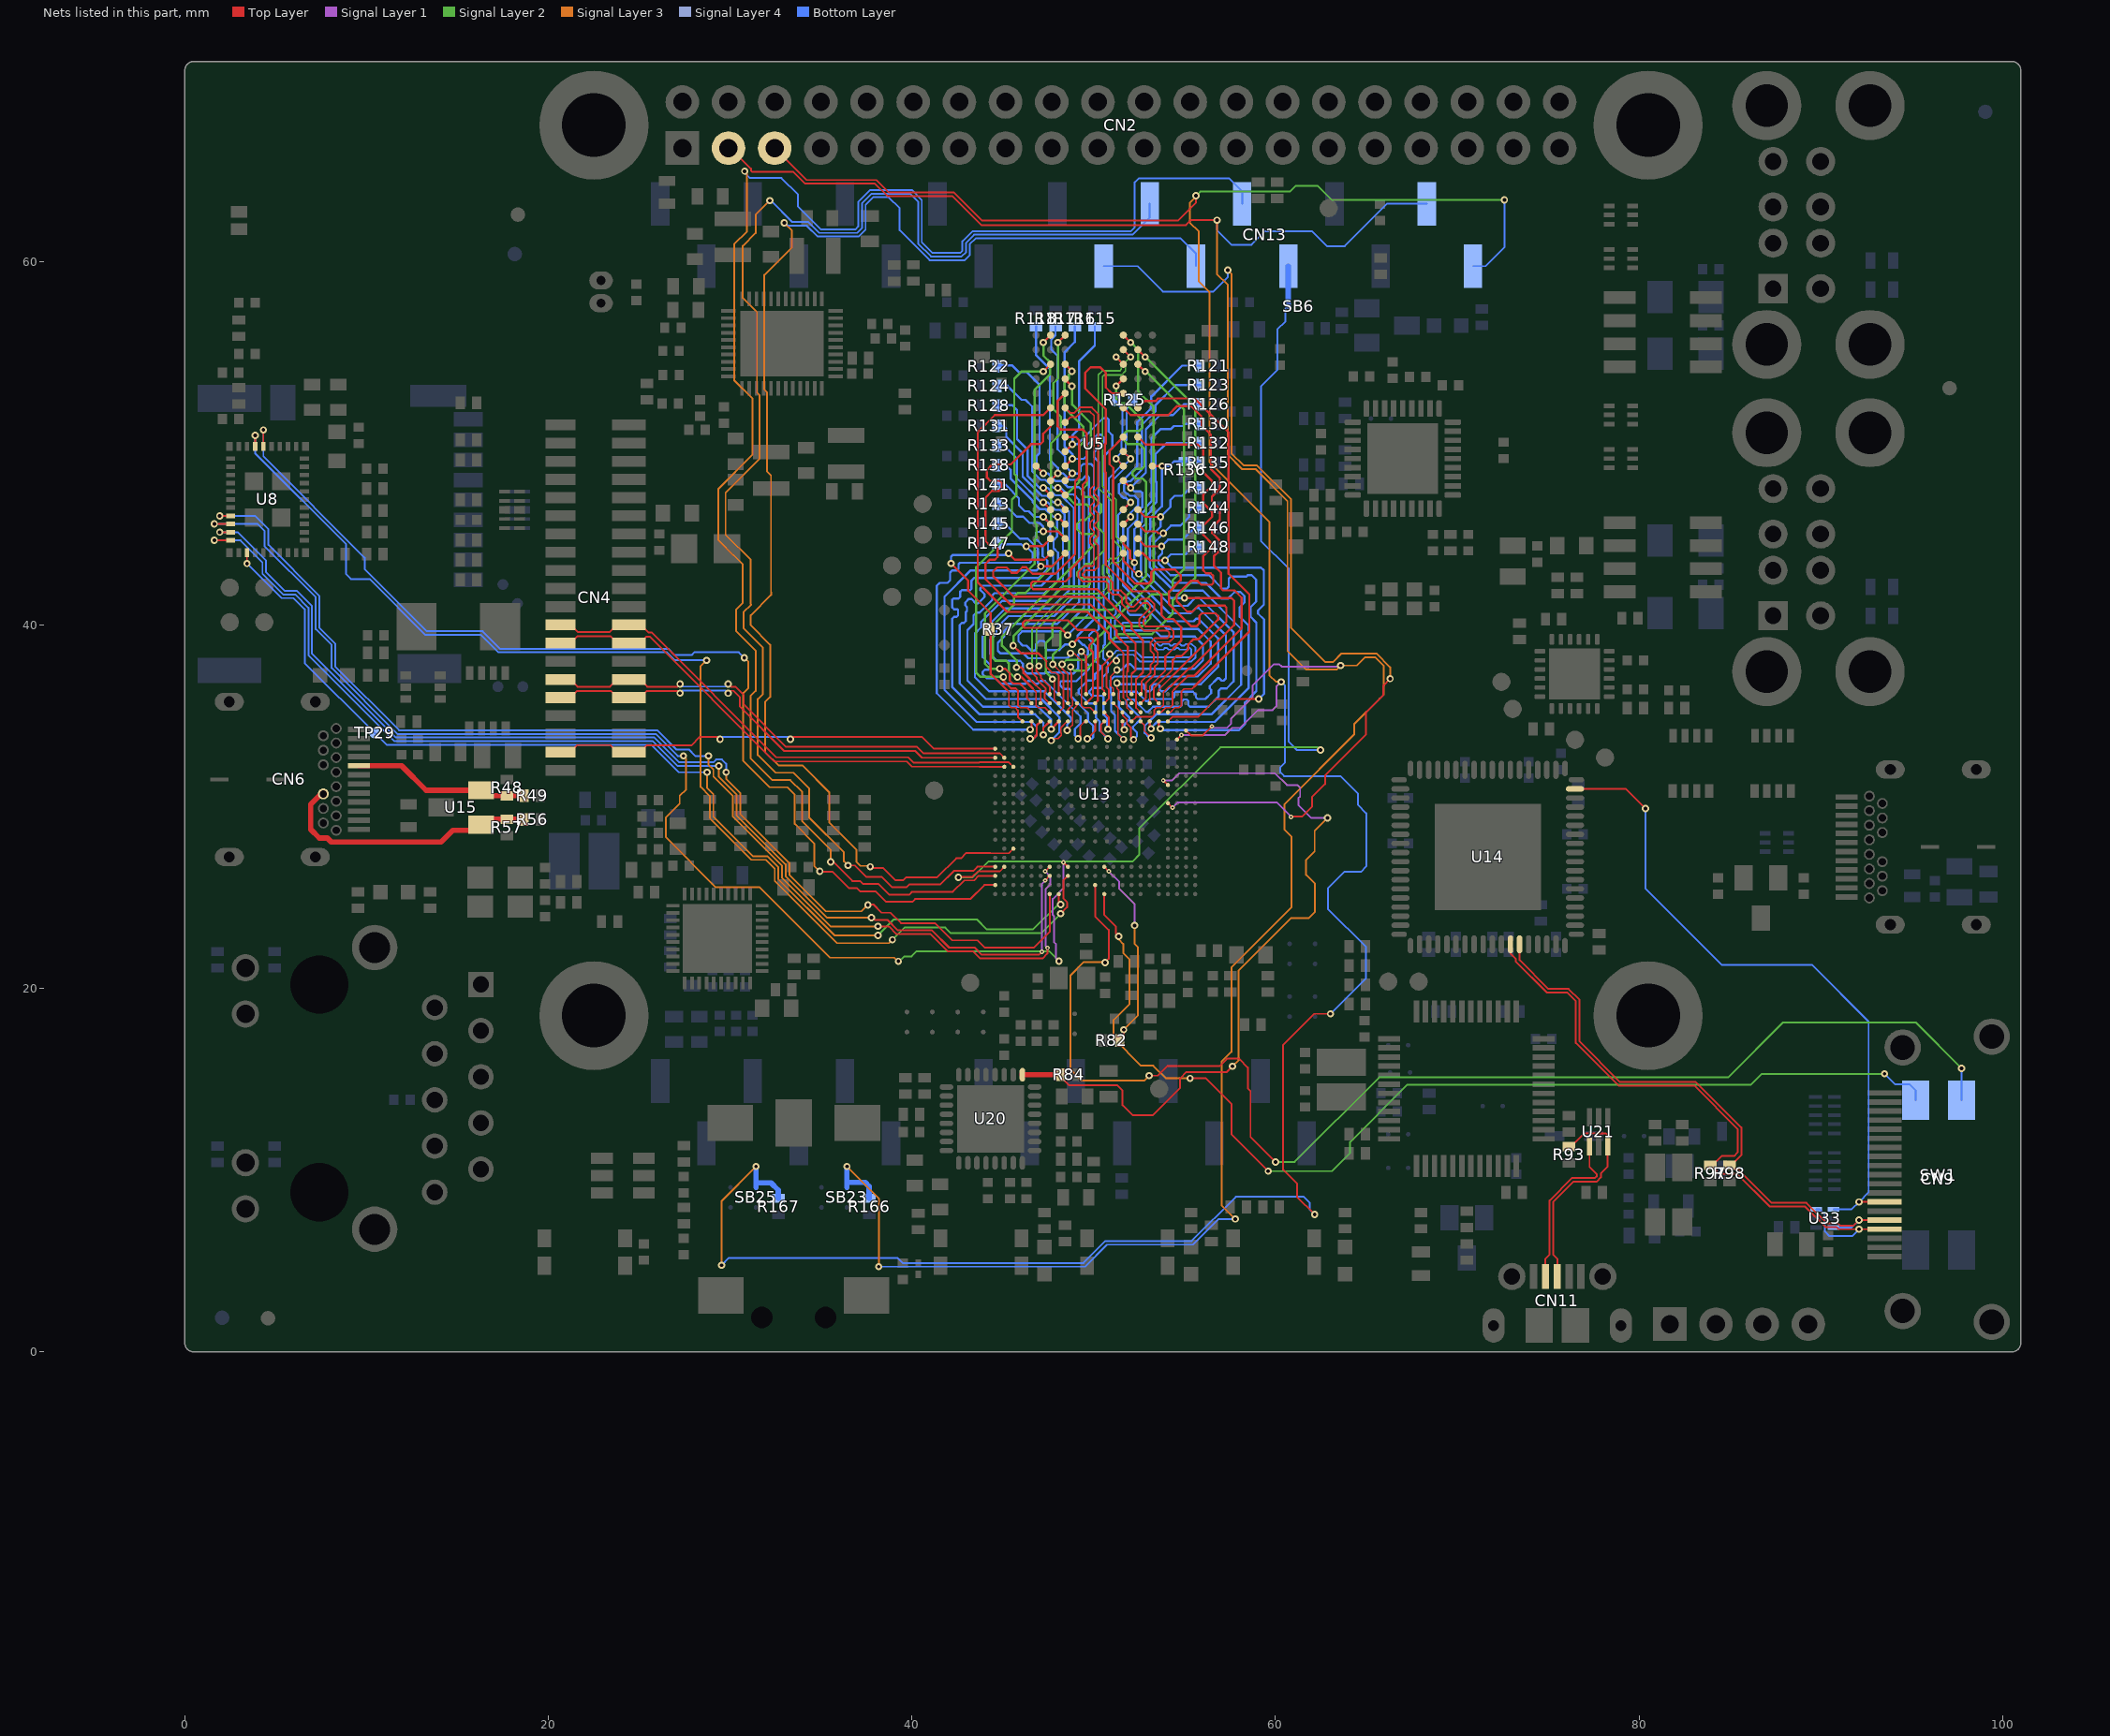
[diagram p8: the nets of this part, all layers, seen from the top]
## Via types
v1: diameter 0.4, hole 0.2, Top Layer to Bottom Layer, tented both sides, 884 vias
v2: diameter 0.25, hole 0.1, Top Layer to Signal Layer 1, tented top, 470 vias
v3: diameter 0.6, hole 0.3, Top Layer to Bottom Layer, tented both sides, 469 vias
v4: diameter 0.25, hole 0.1, Top Layer to Signal Layer 1, tented both sides, 46 vias
v5: diameter 0.25, hole 0.1, Top Layer to Bottom Layer, tented top, 2 vias

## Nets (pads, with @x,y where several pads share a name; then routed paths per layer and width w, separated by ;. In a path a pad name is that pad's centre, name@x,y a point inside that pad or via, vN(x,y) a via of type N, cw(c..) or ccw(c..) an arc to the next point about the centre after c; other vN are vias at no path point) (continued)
ARD_D9: CN13.2 U13.Y11 | length 54.7
  Top Layer w0.1: U13.Y11@54.08,30.19 v2(54.33,29.94) ; v4(60.856,29.44) 60.856,29.514 60.905,29.465 61.477,29.465 62.006,29.993 62.006,30.521 62.73,31.245 62.73,31.723 64.98,33.973 64.98,35.195 65.931,36.146 65.931,36.666 v1(66.305,37.04)
  Signal Layer 1 w0.1: v2(54.33,29.94) 54.63,30.24 60.056,30.24 v4(60.856,29.44)
  Signal Layer 3 w0.1: v1(57.38,59.515) 57.58,59.315 57.58,49.443 58.253,48.77 58.986,48.77 60.86,46.896 60.86,39.826 62.721,37.965 63.175,37.965 63.635,38.425 65.552,38.425 66.305,37.672 v1(66.305,37.04)
  Bottom Layer w0.1: CN13.2@50.544,59.735 52.409,59.735 53.805,58.34 56.58,58.34 57.38,59.14 v1(57.38,59.515)
ARD_D10: CN13.3 U13.A4 | length 79.4
  Top Layer w0.1: v1(36.48,26.765) 36.852,26.765 37.476,26.141 38.335,26.141 38.911,25.565 39.698,25.565 39.849,25.715 41.556,25.715 42.306,26.465 43.375,26.465 43.6,26.69 U13.A4@44.58,26.69
  Signal Layer 3 w0.1: v1@32.172,63.347 v1@32.175,63.35 ; v1(32.18,63.34) 31.405,62.565 31.405,61.554 30.7,60.849 30.7,57.975 31.475,57.2 31.475,52.78 31.622,52.633 31.622,49.147 29.75,47.275 29.75,44.956 31.131,43.575 31.131,41.144 31.158,41.117 30.73,40.689 30.73,39.816 31.804,38.742 31.804,36.2 31.525,35.921 31.525,32.84 32.499,31.866 33.479,31.866 34.35,30.995 34.35,29.38 36.255,27.475 36.255,26.99 v1(36.48,26.765)
  Bottom Layer w0.1: v1(32.18,63.34) 32.244,63.34 33.42,62.164 34.296,62.164 34.896,61.565 36.983,61.565 37.25,61.832 37.25,63.192 37.783,63.725 39.75,63.725 39.909,63.725 40.342,63.292 40.342,60.977 41.054,60.265 42.73,60.265 42.98,60.515 42.98,61.023 43.422,61.465 52.13,61.465 53.084,62.419 CN13.3@53.084,63.164
ARD_D11: CN13.4 U13.C6 | length 78.5
  Top Layer w0.09: 44.305,27.44 45.33,27.44 U13.C6@45.58,27.69
  Top Layer w0.1: v1(37.706,26.691) 37.706,26.614 38.429,26.614 39.077,25.965 39.533,25.965 39.683,26.115 41.391,26.115 42.439,27.163 42.698,27.163 42.975,27.44 44.305,27.44
  Signal Layer 3 w0.1: v1(32.975,62.114) 33.4,61.689 33.4,60.774 31.875,59.249 31.875,52.945 32.022,52.799 32.022,48.453 32.247,48.228 32.247,41.811 32.25,41.809 32.25,41.643 31.13,40.523 31.13,39.982 32.204,38.908 32.204,36.034 31.925,35.755 31.925,33.006 32.665,32.266 33.981,32.266 35.45,30.796 35.45,29.131 36.955,27.627 36.955,26.945 37.16,26.74 37.658,26.74 v1(37.706,26.691)
  Bottom Layer w0.1: v1(32.975,62.114) 33.031,62.114 33.181,61.964 34.214,61.964 34.813,61.365 37.066,61.365 37.45,61.749 37.45,63.109 37.866,63.525 38.719,63.525 39.325,62.919 39.325,61.711 40.971,60.065 42.905,60.065 43.18,60.34 43.18,60.94 43.505,61.265 54.78,61.265 55.624,60.421 CN13.4@55.624,59.735
ARD_D12: CN13.5 U13.A3 | length 91.5
  Top Layer w0.1: v1(35.53,26.965) 35.53,26.99 35.58,27.04 35.585,27.04 36.719,25.906 37.146,25.906 37.31,25.741 38.169,25.741 38.746,25.165 39.864,25.165 40.014,25.315 42.25,25.315 42.875,25.94 43.416,25.94 43.666,26.19 U13.A3@44.58,26.19
  Signal Layer 3 w0.1: v1(30.8,64.96) 30.925,64.835 30.925,61.639 30.225,60.939 30.225,53.464 31.222,52.467 31.222,49.356 29.35,47.484 29.35,44.674 30.199,43.825 30.202,43.825 30.7,43.327 30.7,41.224 30.33,40.854 30.33,39.651 31.404,38.576 31.404,36.366 31.125,36.086 31.125,32.674 32.334,31.466 33.314,31.466 33.95,30.829 33.95,29.214 35.53,27.635 v1(35.53,26.965)
  Bottom Layer w0.1: v1(30.8,64.96) 30.8,64.875 31.085,64.59 32.825,64.59 33.73,63.685 33.73,63.014 34.979,61.765 36.9,61.765 37.05,61.915 37.05,63.275 37.7,63.925 37.925,63.925 39.992,63.925 40.542,63.375 40.542,61.06 41.137,60.465 42.647,60.465 42.78,60.598 42.78,61.106 43.339,61.665 52.047,61.665 52.255,61.873 52.255,64.35 52.47,64.565 57.455,64.565 58.164,63.856 CN13.5@58.164,63.164
ARD_D13: CN13.6 SB6.1 U13.B4 | length 55.8
  Top Layer w0.09: 44.28,26.44 44.83,26.44 U13.B4@45.08,26.69
  Top Layer w0.1: v1(42.555,26.115) 42.555,26.14 43.333,26.14 43.633,26.44 44.28,26.44
  Signal Layer 2 w0.1: v1(42.555,26.115) 43.347,26.115 44.222,26.99 47.563,26.99 51.86,26.99 52.15,26.99 52.505,27.345 52.505,28.801 56.969,33.265 62.33,33.265 v1(62.48,33.115)
  Bottom Layer w0.1: 60.55,57.4 60.55,56.7 60.1,56.25 60.1,54.025 59.2,53.125 59.2,44.625 60.725,43.1 60.725,33.57 61.18,33.115 v1(62.48,33.115)
  Bottom Layer w0.3: CN13.6@60.704,59.735 60.704,57.546 SB6.1@60.725,57.525
ARD_D14: CN2.3 CN13.9 R166.2 SB23.1 U13.AB19 | length 150.6
  Top Layer w0.1: CN2.3@29.91,66.23 30.025,66.23 31.15,65.105 31.15,64.99 31.215,64.925 33.472,64.925 34.122,64.275 37.967,64.275 38.65,63.592 42.222,63.592 43.814,62 55.074,62 55.339,62.265 v1(56.78,62.265) ; U13.AB19@55.08,34.19 55.355,33.915 56.005,33.915 v4(56.505,34.415)
  Signal Layer 1 w0.1: v4(56.505,34.415) 56.58,34.34 57.345,34.34 57.55,34.545 57.55,34.835 58.73,36.015 58.73,36.655 59.915,37.84 60.205,37.84 60.345,37.7 63.515,37.7 v1(63.58,37.765)
  Signal Layer 3 w0.1: v1(36.425,10.2) 38.175,8.45 v1(38.175,4.69) ; v1(56.78,62.265) 56.78,59.311 57.38,58.711 57.38,49.361 58.171,48.57 58.903,48.57 60.66,46.814 60.66,38.566 61.686,37.54 63.355,37.54 v1(63.58,37.765) 64.471,37.765 64.931,38.225 65.469,38.225 65.955,37.739 65.955,36.17 65.726,35.941 65.723,35.941 64.33,34.548 64.33,33.973 60.481,30.124 60.481,28.739 60.88,28.34 60.88,24.464 57.575,21.159 57.575,16.506 57.03,15.961 57.03,8.065 v1(57.781,7.314) v1@57.666,7.314
  Bottom Layer w0.1: v1(38.175,4.69) 49.52,4.69 50.73,5.9 55.468,5.9 56.883,7.315 v1@57.78,7.315 ; v1(56.78,62.265) 56.78,61.715 57.58,60.915 58.68,60.915 59.43,61.665 62.005,61.665 62.83,60.84 63.805,60.84 66.129,63.164 CN13.9@68.324,63.164
  Bottom Layer w0.3: SB23.1@36.425,9.05 36.425,9.325 ; v1(36.425,10.2) 36.425,9.325 ; R166.2@37.65,8.45 37.65,9.1 37.425,9.325 36.425,9.325
ARD_D15: CN2.5 CN13.10 R167.2 SB25.1 U13.AA18 | length 167.7
  Top Layer w0.1: CN2.5@32.45,66.23 34.205,64.475 38.05,64.475 38.733,63.792 42.308,63.792 43.85,62.25 54.65,62.25 55.63,63.23 v1(55.63,63.615) ; U13.AA18@54.58,33.69 v2(54.83,33.94) ; v1(62.156,7.564) 61.18,8.54 61.18,9.265 60.425,10.02 60.425,16.895 62.13,18.6 v1(63.025,18.6)
  Signal Layer 1 w0.1: v2(54.83,33.94) 57.228,33.94 57.628,34.34 58.055,34.34 59.025,35.31 59.845,35.31 60.05,35.515 60.05,36.61 v1(60.305,36.865)
  Signal Layer 2 w0.1: v1(55.63,63.615) 55.857,63.842 60.792,63.842 61.1,64.15 62.325,64.15 63.1,63.375 v1(72.589,63.375)
  Signal Layer 3 w0.1: v1(29.53,4.765) 29.53,8.305 v1(31.425,10.2) ; v1(55.63,63.615) 55.68,63.615 55.28,63.215 55.28,62.139 55.78,61.639 55.78,58.896 56.38,58.296 56.38,48.946 59.66,45.666 59.66,37.235 60.03,36.865 v1(60.305,36.865)
  Bottom Layer w0.1: v1(29.53,4.765) 29.94,5.175 39.212,5.175 39.497,4.89 49.437,4.89 50.647,6.1 55.385,6.1 57.82,8.535 61.552,8.535 61.88,8.207 61.88,7.84 v1(62.156,7.564) ; v1(60.305,36.865) 60.525,36.645 60.525,32.428 60.268,32.172 60.268,31.882 60.473,31.677 63.573,31.677 64.525,30.725 64.525,30.104 64.999,29.63 64.999,26.721 64.693,26.415 63.785,26.415 62.88,25.51 62.88,24.382 64.98,22.282 64.98,20.555 v1(63.025,18.6) ; CN13.10@70.864,59.736 71.551,59.736 72.589,60.774 v1(72.589,63.375)
  Bottom Layer w0.3: SB25.1@31.425,9.05 31.425,9.3 ; v1(31.425,10.2) 31.425,9.3 ; R167.2@32.65,8.45 32.65,8.9 32.25,9.3 31.425,9.3
AUDIO_RST: R84.2 U13.Y13 U20.25 | length 42.5
  Top Layer w0.1: R84.2@48.175,15.25 48.175,15.145 48.655,14.665 51.3,14.665 51.59,14.375 51.59,13.575 52.135,13.03 53.255,13.03 54.75,14.525 54.75,15.05 55.1,15.4 55.445,15.4 55.452,15.393 57.309,15.393 v1(57.631,15.715) ; v2(53.83,31.44) U13.Y13@54.08,31.19
  Top Layer w0.3: U20.25@46.075,15.25 R84.2@48.175,15.25
  Signal Layer 1 w0.1: v2(53.83,31.44) 54.305,31.44 54.705,31.84 59.972,31.84 60.622,31.19 61.205,31.19 61.355,31.04 61.355,30.564 61.256,30.465 61.256,30.076 61.95,29.382 v1(62.865,29.382)
  Signal Layer 3 w0.1: v1(57.631,15.715) 57.975,16.059 57.975,20.993 60.847,23.865 61.825,23.865 62.175,24.215 62.175,25.75 61.68,26.245 61.68,27.068 62.155,27.543 62.155,28.672 v1(62.865,29.382)
BOOT0: SW1.1 U13.N1 | length 60.5
  Top Layer w0.1: U13.N1@50.58,25.19 50.58,24.034 51.23,23.384 51.23,23.015 v1(51.38,22.865) ; v1(55.3,15.05) 56.175,15.05 57.575,13.65 57.575,11.97 v1(59.6,9.945)
  Signal Layer 2 w0.1: v1(59.6,9.945) 63.095,9.945 64.1,10.95 64.1,11.55 67.25,14.7 86.15,14.7 86.75,15.3 v1(93.5,15.3)
  Signal Layer 3 w0.1: v1(51.38,22.865) 51.38,22.694 51.625,22.449 51.625,21.95 51.975,21.6 51.975,19.15 51.1,18.275 51.1,17.25 52.6,15.75 53.278,15.75 53.978,15.05 v1(55.3,15.05)
  Bottom Layer w0.1: v1(93.5,15.3) 94.075,14.725 94.875,14.725 95.205,14.395 SW1.1@95.205,13.85
BOOT1: R82.2 U13.N4 | length 10.7
  Top Layer w0.1: U13.N4@50.58,26.69 v2(50.83,26.44) ; R82.2@51.425,17.125 51.65,17.35 v1(51.65,17.725)
  Signal Layer 1 w0.1: v2(50.83,26.44) 51.405,25.865 51.405,25.487 52.255,24.636 v1(52.255,23.465)
  Signal Layer 3 w0.1: v1(51.65,17.725) 52.425,18.5 52.425,22.275 52.255,22.445 v1(52.255,23.465)
BOOT2: SW1.2 U13.M2 | length 72.3
  Top Layer w0.1: U13.M2@50.08,25.69 50.08,23.968 50.83,23.218 50.83,21.63 v1(50.625,21.425) ; v1(53.05,15.2) 53.525,15.2 54.05,15.725 56.926,15.725 57.331,16.129 57.996,16.129 58.475,15.65 58.475,14.495 58.625,14.345 58.625,11.825 v1(60,10.45)
  Signal Layer 2 w0.1: v1(60,10.45) 61.05,10.45 65.7,15.1 84.9,15.1 87.925,18.125 95.215,18.125 v1(97.745,15.595)
  Signal Layer 3 w0.1: v1(50.625,21.425) 50.625,21.45 49.45,21.45 48.725,20.725 48.725,15.525 49.325,14.925 52.775,14.925 v1(53.05,15.2)
  Bottom Layer w0.1: SW1.2@97.745,13.85 v1(97.745,15.595)
BT_DEV_WAKE: U8.39 U13.J3 | length 67
  Top Layer w0.09: 48.53,24.715 48.53,24.753 48.33,24.953 48.33,25.94 U13.J3@48.58,26.19
  Top Layer w0.1: U8.39@3.875,49.825 v1(3.875,50.425) ; v1(48.18,24.115) 48.53,24.465 48.53,24.715
  Signal Layer 2 w0.1: v1(38.925,22.675) 39.6,23.35 41.84,23.35 42.15,23.04 47.105,23.04 v1(48.18,24.115)
  Signal Layer 3 w0.1: v1(28.7,38.05) 28.38,37.73 28.38,31.09 28.88,30.59 28.88,29.356 31.161,27.075 31.953,27.075 32.455,26.573 32.455,25.917 35.882,22.49 38.74,22.49 v1(38.925,22.675)
  Bottom Layer w0.1: v1(3.875,50.425) 3.875,49.44 8.875,44.44 8.875,42.789 9.139,42.525 10.167,42.525 13.242,39.45 16.3,39.45 17.26,38.49 26.519,38.49 26.959,38.05 v1(28.7,38.05)
BT_HOST_WAKE: U8.38 U13.A2 | length 58.9
  Top Layer w0.1: U8.38@4.325,49.825 v1(4.325,50.726) ; v1(34.93,26.44) 34.955,26.415 35.644,26.415 36.554,25.506 36.98,25.506 37.144,25.341 38.004,25.341 38.58,24.765 40.03,24.765 40.18,24.915 43.208,24.915 43.983,25.69 U13.A2@44.58,25.69
  Signal Layer 3 w0.1: v1(30.78,38.19) 31.004,37.966 31.004,36.531 30.725,36.252 30.725,32.509 32.168,31.066 33.148,31.066 33.55,30.664 33.55,29.049 34.63,27.969 34.63,26.74 v1(34.93,26.44)
  Bottom Layer w0.1: v1(4.325,50.726) 4.325,49.272 9.901,43.697 9.901,43.074 13.325,39.65 16.383,39.65 17.343,38.69 26.601,38.69 26.951,38.34 27.882,38.34 28.032,38.49 30.48,38.49 v1(30.78,38.19)
BT_PCM_CLK: U8.11 U13.G3 | length 63.7
  Top Layer w0.1: v1(1.624,44.65) U8.11@2.525,44.65 ; v1(37.78,23.89) v1@37.78,23.94 ; v1@37.78,23.94 37.955,23.765 38.661,23.765 39.237,23.19 41.104,23.19 42.049,22.245 43.442,22.245 43.837,21.85 46.99,21.85 v4(47.15,22.01) ; v2(47.33,25.94) U13.G3@47.58,26.19
  Signal Layer 1 w0.1: v4(47.15,22.01) 47.15,25.76 v2(47.33,25.94)
  Signal Layer 3 w0.1: v1(29.38,32.24) 29.38,31.639 30.35,30.669 30.35,29.526 33.055,26.821 33.055,26.165 35.33,23.89 v1(37.78,23.89)
  Bottom Layer w0.1: v1(1.624,44.65) 3.067,44.65 4.275,43.442 4.275,42.806 5.406,41.675 6.069,41.675 6.8,40.944 6.8,38.336 11.536,33.6 25.745,33.6 27.105,32.24 28.805,32.24 v1(29.38,32.24)
BT_PCM_SDI: U8.10 U13.G1 | length 62
  Top Layer w0.1: v1(1.925,45.1) U8.10@2.525,45.1 ; v1(37.58,24.59) 37.605,24.615 37.882,24.615 38.332,24.165 38.827,24.165 39.402,23.59 41.269,23.59 42.214,22.645 43.608,22.645 44.003,22.25 46.713,22.25 47.58,23.117 U13.G1@47.58,25.19
  Signal Layer 3 w0.1: v1(29.78,31.89) 29.78,31.522 30.55,30.752 30.55,29.609 33.255,26.904 33.255,26.248 35.263,24.24 37.225,24.24 37.575,24.59 v1(37.58,24.59)
  Bottom Layer w0.1: v1(1.925,45.1) 2.9,45.1 4.475,43.525 4.475,42.889 5.489,41.875 6.152,41.875 7,41.027 7,38.419 11.619,33.8 25.828,33.8 27.188,32.44 29.08,32.44 29.23,32.59 29.555,32.59 29.78,32.365 v1(29.78,31.89)
BT_PCM_SDO: U8.9 U13.J4 | length 70.5
  Top Layer w0.1: v1(1.624,45.55) U8.9@2.525,45.55 ; v2(48.33,26.94) U13.J4@48.58,26.69
  Signal Layer 1 w0.1: v1(48.09,21.5) 47.92,21.67 47.92,21.867 47.925,21.872 47.925,22.427 47.816,22.536 47.816,23.984 47.75,24.05 47.75,24.92 48.33,25.5 v2(48.33,26.94)
  Signal Layer 2 w0.1: v1(39.255,21.49) 39.255,21.44 39.579,21.765 39.98,21.765 40.255,22.04 47.55,22.04 v1(48.09,21.5)
  Signal Layer 3 w0.1: v1(27.429,32.79) 27.58,32.64 27.58,30.949 27.225,30.594 27.225,30.16 26.475,29.41 26.475,28.311 29.221,25.565 31.624,25.565 35.499,21.69 39.03,21.69 39.23,21.49 v1(39.255,21.49)
  Signal Layer 4 w0.1: v1(27.429,32.79) v1@27.48,32.74
  Bottom Layer w0.1: v1(1.624,45.55) 4.017,45.55 4.4,45.167 4.4,44.317 7.2,41.517 7.2,39.761 8.075,38.886 8.075,38.513 ; 8.074,38.512 8.074,37.628 11.702,34 25.911,34 27.12,32.79 v1(27.429,32.79)
BT_PCM_WS: U8.8 U13.G4 | length 65.3
  Top Layer w0.1: v1(1.925,46) U8.8@2.525,46 ; v1(38.13,23.415) 38.729,23.414 39.154,22.99 41.021,22.99 41.966,22.045 43.359,22.045 43.754,21.65 47.179,21.65 47.45,21.921 v4(47.45,22.23) ; v2(47.33,26.44) U13.G4@47.58,26.69
  Signal Layer 1 w0.1: v2(47.33,26.44) 47.605,26.165 47.605,25.715 47.35,25.46 47.35,22.33 v4(47.45,22.23)
  Signal Layer 3 w0.1: v1(28.805,32.79) 28.805,32.315 29.08,32.04 29.08,31.656 30.15,30.586 30.15,29.444 32.855,26.739 32.855,26.082 35.522,23.415 v1(38.13,23.415)
  Bottom Layer w0.1: v1(1.925,46) 3.85,46 4.6,45.25 4.6,44.4 7.4,41.6 7.4,39.844 8.275,38.969 8.275,37.886 8.274,37.711 11.785,34.2 25.994,34.2 27.053,33.14 27.73,33.14 28.08,32.79 v1(28.805,32.79)
BT_REG_ON: TP29.1 U8.14 U13.H1 | length 59.1
  Top Layer w0.1: v1(3.425,43.375) U8.14@3.425,43.975 ; U13.H1@48.08,25.19 48.08,24.64 48.105,24.615 v1(48.18,24.615)
  Signal Layer 2 w0.1: v1(38.13,22.915) 39.005,23.79 43.58,23.79 44.13,23.24 44.81,23.24 46.655,23.24 48.105,24.69 v1(48.18,24.615)
  Signal Layer 3 w0.1: v1(28.73,31.89) 28.73,31.04 29.08,30.69 29.08,29.439 31.244,27.275 32.036,27.275 32.655,26.656 32.655,25.999 35.74,22.915 v1(38.13,22.915)
  Bottom Layer w0.1: v1(3.425,43.375) 3.425,43.373 5.323,41.475 5.986,41.475 6.6,40.861 6.6,37.9 TP29.1@10.45,34.05 11.1,33.4 25.662,33.4 27.172,31.89 v1(28.73,31.89)
CC1: CN6.A5 R48.2 R49.1 U15.2 | length 9.8
  Top Layer w0.3: CN6.A5@9.58,32.25 11.925,32.25 13.275,30.9 U15.2@16.3,30.9 16.6,30.6 R48.2@17.725,30.6 R49.1@18.65,30.6
CC2: CN6.B5 R56.1 R57.2 U15.1 | length 14.8
  Top Layer w0.3: CN6.B5@7.62,30.7 7.501,30.7 6.925,30.124 6.925,28.75 7.4,28.275 7.5,28.275 7.505,28.28 7.83,28.28 8.061,28.05 14.1,28.05 14.75,28.7 16,28.7 U15.1@16.3,29 16.6,29.3 R57.2@17.725,29.3 R56.1@18.65,29.3
CEC_A: CN9.13 U14.71 U33.1 | length 37.1
  Top Layer w0.1: U14.71@76.475,30.975 79.275,30.975 v1(80.35,29.9) ; v1(92.1,8.25) CN9.13@93.5,8.25
  Bottom Layer w0.1: v1(80.35,29.9) 80.35,25.5 84.55,21.3 89.5,21.3 92.625,18.175 92.625,8.775 v1(92.1,8.25) 91.7,7.85 U33.1@90.7,7.85
CON_USB_STLK_N: CN11.2 U21.1 | length 9.2
  Top Layer w0.1: CN11.2@74.85,4.15 74.85,5.125 75.075,5.35 75.075,8.325 76.325,9.575 77.575,9.575 77.675,9.675 77.675,9.775 77.275,10.175 U21.1@77.275,11.295
CON_USB_STLK_P: CN11.3 R93.1 U21.3 | length 12.3
  Top Layer w0.1: CN11.3@75.5,4.15 75.5,5.125 75.275,5.35 75.275,8.242 76.408,9.375 77.675,9.375 77.9,9.6 77.9,9.825 78.275,10.2 U21.3@78.275,11.295 78.275,11.925 78.175,12.025 77,12.025 76.275,11.3 R93.1@76.15,11.3
DDR_A0: R131.1 U5.N3 U13.L20 | length 29.5
  Top Layer w0.09: v1(48.03,46.74) U5.N3@48.43,46.34 ; v1(49.14,33.74) 49.26,33.86 49.26,34.43 49.52,34.69 U13.L20@49.58,34.69
  Bottom Layer w0.12: R131.1@44.68,50.96 45.03,50.96 45.19,50.8 45.19,50.34 46.09,49.44 46.09,48.16 47.15,47.1 47.42,47.1 47.78,46.74 v1(48.03,46.74) 48.121,46.74 48.64,46.221 48.64,41.895 47.645,40.9 45.132,40.9 44.23,39.998 44.23,39.698 43.89,39.358 43.89,38.226 44.323,37.793 44.323,37.647 44.206,37.53 44.01,37.53 43.89,37.41 43.89,37.292 44.106,37.076 44.563,37.076 44.879,36.76 46.24,36.76 46.39,36.91 46.635,36.91 46.785,36.76 46.92,36.76 47.07,36.91 47.319,36.91 49.27,34.959 49.27,34.58 48.96,34.27 48.96,33.92 v1(49.14,33.74)
DDR_A1: R123.1 U5.P7 U13.P22 | length 34
  Top Layer w0.09: U13.P22@51.08,35.69 51.335,35.435 ; 51.33,34.005 51.33,35.435 ; 51.335,34.005 v1(51.64,33.7)
  Top Layer w0.12: U5.P7@51.63,45.54 v1(52.03,45.94)
  Bottom Layer w0.12: v1(51.64,33.7) 51.17,34.17 51.17,35.032 50.96,35.242 50.96,36.26 50.92,36.3 50.92,36.949 51.131,37.16 55.719,37.16 56.43,37.871 56.43,39.079 55.729,39.78 54.01,39.78 51.61,42.18 51.61,45.52 v1(52.03,45.94) 52.03,46.162 52.447,46.579 52.447,46.903 52.25,47.1 51.981,47.1 51.861,47.22 51.81,47.22 51.665,47.365 51.665,47.684 51.881,47.9 52.01,47.9 52.65,48.54 52.65,51 53.39,51.74 53.39,52.079 54.501,53.19 R123.1@55.86,53.19
DDR_A2: R138.1 U5.P3 U13.J20 | length 27.4
  Top Layer w0.09: v1@47.76,33.74 48.04,33.74 48.22,33.92 48.22,34.032 48.195,34.057 48.195,34.343 48.542,34.69 U13.J20@48.58,34.69
  Top Layer w0.12: v1(47.66,33.64) v1@47.76,33.74 ; v1(48.03,45.94) U5.P3@48.43,45.54
  Bottom Layer w0.12: R138.1@44.68,48.79 45.17,48.79 45.43,48.53 45.43,48.049 46.64,46.839 46.64,46.76 47.04,46.36 47.36,46.36 47.78,45.94 v1(48.03,45.94) ; v1(47.66,33.64) 48.12,34.1 48.12,34.921 47.121,35.92 44.074,35.92 43.05,36.944 43.05,39.706 43.39,40.046 43.39,40.522 43.548,40.68 43.72,40.68 43.722,40.678 44.42,41.376 44.42,41.62 44.54,41.74 47.297,41.74 48.037,42.48 48.037,43.973 47.79,44.22 47.79,44.66 47.987,44.857 v1@47.987,45.92
DDR_A3: R133.1 U5.N2 U13.K22 | length 27.8
  Top Layer w0.09: v1(48.54,34.2) 48.825,34.485 ; 48.83,34.485 48.83,35.3 49.08,35.575 U13.K22@49.08,35.69 U13.K22@49.08,35.58
  Top Layer w0.12: v1(47.23,46.74) U5.N2@47.63,46.34
  Bottom Layer w0.12: R133.1@44.68,49.88 45.05,49.88 45.77,49.16 45.77,48.07 47.1,46.74 v1(47.23,46.74) 47.469,46.74 47.879,46.33 48.149,46.33 48.39,46.089 48.39,45.791 48.307,45.708 48.307,42.156 47.471,41.32 44.958,41.32 43.81,40.172 43.81,39.872 43.47,39.532 43.47,37.118 44.248,36.34 47.295,36.34 48.75,34.885 48.75,34.73 48.54,34.52 v1(48.54,34.2)
DDR_A4: R144.1 U5.P8 U13.V20 | length 24.5
  Top Layer w0.12: U5.P8@52.43,45.54 52.83,45.14 53.45,45.14 53.55,45.04 v1(53.83,45.04) ; U13.V20@53.08,34.69 53.08,34.37 v1(53.16,34.29)
  Bottom Layer w0.12: v1(53.16,34.29) 53.16,34.334 53.486,34.66 56.654,34.66 58.53,36.536 58.53,39.949 58.03,40.449 58.03,40.968 58.291,41.229 58.291,41.589 58.075,41.805 57.745,41.805 57.38,41.44 57.039,41.44 56.166,42.313 54.3,42.313 53.32,43.292 53.32,44.51 53.85,45.04 v1(53.83,45.04) 54.25,45.46 54.76,45.46 55.25,45.95 55.25,46.24 55.45,46.44 R144.1@55.86,46.44
DDR_A5: R141.1 U5.P2 U13.H20 | length 25.6
  Top Layer w0.12: v1(47.23,45.94) U5.P2@47.63,45.54 ; v1(47.66,34.26) 48.08,34.68 U13.H20@48.08,34.69
  Bottom Layer w0.12: R141.1@44.68,47.71 45.17,47.71 45.555,47.325 45.555,47.295 45.89,46.96 45.89,46.57 46.205,46.255 46.425,46.255 46.74,45.94 v1(47.23,45.94) 47.612,45.558 47.612,44.942 47.487,44.817 47.487,44.11 47.767,43.829 47.767,42.804 47.123,42.16 43.91,42.16 43.77,42.02 43.77,41.91 44,41.68 44,41.55 43.63,41.18 43.52,41.18 43.27,41.43 43.138,41.43 42.94,41.232 42.94,41.07 43.032,40.978 43.032,40.758 42.97,40.696 42.97,40.22 42.86,40.11 42.75,40.11 42.63,39.99 42.63,36.77 43.9,35.5 46.947,35.5 47.66,34.787 v1(47.66,34.26) v1@47.67,34.25
DDR_A6: R146.1 U5.R8 U13.W20 | length 25.3
  Top Layer w0.12: U5.R8@52.38,44.727 U5.R8@52.38,44.74 ; U5.R8@52.43,44.74 52.85,44.32 v1(53.73,44.32) ; v1@53.58,34.37 U13.W20@53.58,34.69
  Bottom Layer w0.12: v1@53.66,34.24 53.69,34.21 57.99,34.21 58.314,34.534 58.314,35.726 58.95,36.362 58.95,40.123 58.62,40.453 58.62,40.964 58.935,41.279 58.935,42.485 58.687,42.733 58.47,42.733 58.402,42.665 57.545,42.665 57.43,42.55 57.43,42.1 57.32,41.99 57.083,41.99 56.34,42.733 54.219,42.733 53.56,43.392 53.56,43.734 53.766,43.94 v1@53.766,44.315 ; v1(53.73,44.32) 54.095,44.685 54.88,44.685 55.545,45.35 R146.1@55.86,45.35
  other v1: 53.66,34.29
DDR_A7: R147.1 U5.R2 U13.E20 | length 22.7
  Top Layer w0.12: v1(46.29,44.32) 46.311,44.34 47.23,44.34 U5.R2@47.63,44.74 ; v1(46.51,34.24) 46.58,34.31 U13.E20@46.58,34.69
  Bottom Layer w0.12: R147.1@44.68,44.49 44.73,44.44 46.02,44.44 46.14,44.32 v1(46.29,44.32) 46.65,43.96 46.65,43.59 46.48,43.42 42.64,43.42 42.56,43.34 42.56,43.08 42.47,42.99 42.21,42.99 42.1,42.88 42.1,42.454 41.956,42.31 41.53,42.31 41.37,42.15 41.37,36.248 43.378,34.24 v1(46.51,34.24)
DDR_A8: R148.1 U5.T8 U13.Y20 | length 22.5
  Top Layer w0.09: U13.Y20@54.08,34.69 54.33,34.94 55.746,34.94 56.726,35.92 v1(59.08,35.92)
  Top Layer w0.12: U5.T8@52.43,43.94 52.706,43.94 53.096,43.55 v1(53.92,43.55)
  Bottom Layer w0.09: 59.35,41.1 59.355,41.1
  Bottom Layer w0.12: R148.1@55.86,44.27 55.45,44.27 55.06,43.88 54.25,43.88 v1(53.92,43.55) 54.317,43.153 59.207,43.153 59.355,43.005 59.355,41.1 ; v1(59.08,35.92) 59.37,36.21 59.37,40.297 59.04,40.627 59.04,40.79 59.35,41.1
DDR_A9: R143.1 U5.R3 U13.G20 | length 26.4
  Top Layer w0.12: v1(47.23,33.95) 47.23,34.34 U13.G20@47.58,34.69 ; v1(47.23,45.14) 48.03,45.14 U5.R3@48.43,44.74
  Bottom Layer w0.12: R143.1@44.68,46.65 45.07,46.65 45.76,45.96 46.12,45.96 46.469,45.61 47.02,45.61 47.23,45.4 v1(47.23,45.14) ; v1@47.187,45.12 46.88,45.12 46.81,45.05 46.81,44.74 47.187,44.363 47.187,43.795 47.45,43.532 47.45,43.071 46.959,42.58 43.42,42.58 43.28,42.44 43.28,41.99 43.21,41.92 42.754,41.92 42.662,41.828 42.662,41.548 42.564,41.45 42.284,41.45 42.21,41.376 42.21,40.97 42.32,40.86 42.5,40.86 42.54,40.82 42.54,40.52 42.46,40.44 42.32,40.44 42.21,40.33 42.21,36.596 43.726,35.08 46.773,35.08 47.23,34.623 ; v1(47.23,33.95) 47.23,34.623 ; 47.24,34.613 47.23,34.623
DDR_A10: R126.1 U5.L7 U13.R22 | length 29.7
  Top Layer w0.09: v1(51.28,36.8) 51.28,36.5 51.37,36.41 51.37,35.9 U13.R22@51.58,35.69
  Top Layer w0.12: U5.L7@51.63,47.94 v1(52.03,47.54)
  Bottom Layer w0.12: v1@51.34,36.74 52.71,36.74 52.77,36.68 52.77,36.51 52.94,36.34 53.08,36.34 53.21,36.47 53.21,36.65 53.3,36.74 53.54,36.74 53.63,36.65 53.63,36.44 53.73,36.34 53.93,36.34 54.33,36.74 55.893,36.74 56.85,37.697 56.85,39.253 55.769,40.334 55.626,40.334 55.492,40.2 54.04,40.2 51.88,42.36 51.88,45.281 52.4,45.801 52.4,46.22 52.647,46.468 ; 52.667,46.468 52.667,47.263 52.58,47.35 52.22,47.35 v1(52.03,47.54) 52.87,48.38 52.87,50.759 53.651,51.54 54.361,51.54 54.961,52.14 55.85,52.14 R126.1@55.86,52.13
DDR_A11: R130.1 U5.R7 U13.R20 | length 32.2
  Top Layer w0.09: U13.R20@51.58,34.69 51.58,34.33 v1(51.68,34.23)
  Top Layer w0.12: U5.R7@51.63,44.74 51.63,44.449 52.01,44.069 52.01,43.66 v1(52.24,43.43)
  Bottom Layer w0.12: v1(51.68,34.23) 51.68,34.507 51.97,34.797 51.97,34.897 51.74,35.127 51.733,35.127 51.381,35.479 51.381,36.241 51.46,36.32 52.366,36.32 52.878,35.808 52.981,35.808 53.093,35.92 54.32,35.92 54.43,36.03 54.43,36.24 54.51,36.32 55.46,36.32 55.628,36.152 55.628,36.01 55.718,35.92 56.132,35.92 56.461,36.249 56.461,36.429 56.38,36.51 56.38,36.633 56.808,37.062 56.908,37.062 57.046,36.924 57.136,36.924 57.27,37.058 57.27,39.427 55.768,40.929 55.626,40.929 55.331,40.633 54.148,40.633 52.12,42.661 52.12,42.959 52.24,43.079 v1(52.24,43.43) 52.24,45.261 52.66,45.68 52.66,46.149 52.887,46.377 52.887,46.496 53.18,46.789 53.18,50.269 53.691,50.78 54.26,50.78 54.42,50.94 54.899,50.94 55.019,51.06 R130.1@55.86,51.06
DDR_A12: R121.1 U5.N7 U13.P23 | length 33
  Top Layer w0.09: U13.P23@51.08,36.19 51.08,36.5 50.935,36.645 50.935,37.175 v1(51.28,37.52)
  Top Layer w0.12: U5.N7@51.63,46.34 v1(52.03,46.74)
  Bottom Layer w0.12: v1(51.28,37.52) 51.53,37.52 51.86,37.85 52,37.85 52.27,37.58 55.545,37.58 56.01,38.045 56.01,38.905 55.555,39.36 53.692,39.36 53.352,39.7 51.65,39.7 51.57,39.78 51.57,40.06 51.63,40.12 52.726,40.12 52.838,40.232 52.838,40.358 52.656,40.54 52.002,40.54 51.862,40.68 51.862,40.912 52.07,41.12 52.07,41.32 51.9,41.49 51.562,41.49 51.34,41.712 51.34,46.05 v1(52.03,46.74) 51.79,46.98 51.65,46.98 51.39,47.24 51.39,47.725 52.397,48.732 52.397,51.157 53.17,51.93 53.17,52.57 54.86,54.26 R121.1@55.86,54.26
DDR_A13: R145.1 U5.T3 U13.F20 | length 24.7
  Top Layer w0.12: v1(46.51,33.74) 46.67,33.74 46.87,33.94 46.87,34.48 U13.F20@47.08,34.69 ; v1@47.12,43.23 47.72,43.23 U5.T3@48.43,43.94
  Bottom Layer w0.12: R145.1@44.68,45.57 45.12,45.57 45.945,44.745 46.374,44.745 46.93,44.189 46.93,43.39 47.09,43.23 46.86,43 43.24,43 41.79,41.55 41.79,36.422 43.552,34.66 46.39,34.66 46.599,34.66 46.87,34.389 46.87,33.94 46.67,33.74 v1(46.51,33.74) ; v1@47.12,43.18 v1@47.12,43.23
  other v1: 47.09,43.22
DDR_A14: R132.1 U5.T7 U13.R21 | length 33.2
  Top Layer w0.09: U13.R21@51.557,35.167 U13.R21@51.58,35.19 ; U13.R21@51.583,35.21 51.587,35.206 51.587,35.036 51.684,34.94 51.83,34.794 51.83,34.586 51.83,34.568 52.04,34.358 52.04,33.84 v1(52.19,33.69)
  Top Layer w0.12: U5.T7@51.63,43.94 51.63,43.52 52.34,42.81 v1(52.48,42.81)
  Bottom Layer w0.12: v1@52.17,33.66 52.38,33.87 52.38,34.08 52.158,34.302 52.158,34.392 52.558,34.792 52.558,34.903 51.801,35.66 51.801,35.83 51.871,35.9 52.192,35.9 52.881,35.211 ; 52.88,35.21 52.977,35.21 53.267,35.5 54.77,35.5 54.85,35.58 54.85,35.79 54.96,35.9 55.11,35.9 55.208,35.802 55.208,35.58 55.288,35.5 56.306,35.5 56.881,36.075 56.881,36.39 56.995,36.504 57.31,36.504 57.69,36.884 57.69,39.601 55.818,41.473 55.577,41.473 55.157,41.053 54.242,41.053 52.825,42.47 52.82,42.47 v1(52.48,42.81) 52.6,42.93 52.6,45.309 52.88,45.589 52.88,46 53.19,46.311 53.19,46.488 53.44,46.738 53.44,47.869 53.4,47.909 53.4,49.389 54.02,50.009 55.841,50.009 R132.1@55.86,49.99
DDR_BA0: R128.1 U5.M2 U13.L23 | length 29.4
  Top Layer w0.12: v1(47.23,47.54) U5.M2@47.63,47.14 ; v1(49.32,38.54) 49.58,38.28 U13.L23@49.58,36.19
  Bottom Layer w0.12: R128.1@44.68,52.06 44.71,52.09 45.51,52.09 45.78,51.82 45.78,50.22 46.37,49.63 46.37,48.191 47.021,47.54 v1(47.23,47.54) 47.469,47.54 47.879,47.13 48.2,47.13 48.91,46.42 48.91,41.571 47.819,40.48 45.306,40.48 44.65,39.824 44.65,39.524 44.31,39.184 44.31,38.4 44.69,38.02 45.949,38.02 46.11,37.859 46.11,37.56 46.34,37.33 47.3,37.33 47.35,37.38 48.531,37.38 48.59,37.32 48.87,37.32 49.14,37.591 49.14,38.36 v1(49.32,38.54)
DDR_BA1: R142.1 U5.N8 U13.U20 | length 25.3
  Top Layer w0.09: U13.U20@52.58,34.69 52.78,34.49 52.78,34.17 v1(53.16,33.79)
  Top Layer w0.12: U5.N8@52.43,46.34 52.83,45.94 v1(53.68,45.94)
  Bottom Layer w0.12: v1(53.16,33.79) 53.066,33.79 52.8,34.056 52.8,34.439 53.441,35.08 56.48,35.08 58.11,36.71 58.11,39.775 55.992,41.893 54.38,41.893 53.08,43.193 53.08,44.799 53.68,45.399 v1(53.68,45.94) 54.22,46.48 54.22,46.869 54.451,47.1 54.88,47.1 55.34,47.56 55.84,47.56 R142.1@55.86,47.54
DDR_BA2: R124.1 U5.M3 U13.M21 | length 29.9
  Top Layer w0.09: v1(48.72,38.44) 48.929,38.44 49.335,38.034 ; 49.33,38.034 49.33,35.559 49.449,35.44 49.82,35.44 50.07,35.19 U13.M21@50.08,35.19
  Top Layer w0.12: v1@48.05,47.52 U5.M3@48.43,47.14
  Bottom Layer w0.12: R124.1@44.68,53.15 44.71,53.18 45.25,53.18 45.25,53.161 46.031,52.38 46.249,52.38 46.62,52.009 46.62,48.441 47.081,47.98 47.34,47.98 47.78,47.54 v1(48.03,47.54) 48.19,47.54 48.554,47.176 48.894,47.176 49.2,46.87 49.2,41.267 47.993,40.06 45.48,40.06 45.07,39.65 45.07,39.35 44.73,39.01 44.73,38.574 44.864,38.44 46.123,38.44 46.401,38.162 47.432,38.162 47.46,38.19 48.57,38.19 v1@48.72,38.34 ; v1@48.64,38.32 v1@48.72,38.4
DDR_CASN: R116.1 U5.K3 U13.N20 | length 31.1
  Top Layer w0.09: U13.N20@50.58,34.69 50.39,34.5 50.39,34.13 v1(50.78,33.74)
  Top Layer w0.12: U5.K3@48.43,48.74 v1(48.83,49.14)
  Bottom Layer w0.12: R116.1@48.97,56.41 48.97,55.57 48.39,54.99 48.39,49.83 48.83,49.39 v1(48.83,49.14) 49.45,49.14 49.61,49.3 49.61,49.866 50.202,50.458 50.409,50.458 50.58,50.287 50.58,50.07 50.03,49.52 50.03,49.212 50.28,48.962 50.28,39.77 50.17,39.66 ; 50.169,39.661 49.969,39.661 49.75,39.441 49.75,39.203 50.1,38.853 50.1,37.996 50.36,37.736 50.36,37.577 50.08,37.297 50.08,37.05 49.97,36.94 49.677,36.94 49.168,36.431 49.168,36.248 49.736,35.681 50,35.681 50.12,35.561 50.12,34.894 50.33,34.684 50.33,34.19 v1(50.78,33.74)
DDR_CKE: R135.1 R136.2 U5.K9 U13.T20 | length 24.3
  Top Layer w0.09: U13.T20@52.08,34.69 52.33,34.94 53.205,34.94 53.33,35.065 53.33,35.324 53.446,35.44 53.694,35.44 53.83,35.576 53.83,36.303 54.147,36.62 54.25,36.62
  Top Layer w0.12: U5.K9@53.23,48.74 v1(53.76,48.74) ; 54.25,36.62 55.24,37.61 55.344,37.61 57.72,39.986 57.72,41.33 57.57,41.48 v1(54.99,41.48)
  Bottom Layer w0.12: 53.12,45.23 53.12,45.24 ; v1(54.99,41.48) 54.25,41.48 52.84,42.89 52.84,44.96 53.12,45.24 ; R135.1@55.86,48.91 55.78,48.99 R136.2@55.01,48.99 55,49 54.41,49 54.15,48.74 v1(53.76,48.74) 53.76,46.53 53.12,45.89 53.12,45.24
DDR_CLK_N: R125.2 U5.K7 U13.N23 | length 27
  Top Layer w0.1: U13.N23@50.58,36.19 50.58,36.371 50.49,36.461 50.49,36.465 50.48,36.475 50.48,37.77 50.88,38.17 v1(50.88,38.39) ; v1(51.23,49.14) U5.K7@51.63,48.74
  Bottom Layer w0.1: v1(50.88,38.39) 50.91,38.42 51.1,38.42 51.267,38.587 52.268,38.587 52.635,38.22 55.28,38.22 55.37,38.31 55.37,38.64 55.29,38.72 55.165,38.72 55.085,38.64 54.73,38.64 54.65,38.72 54.525,38.72 54.445,38.64 54.12,38.64 54.04,38.72 53.905,38.72 53.825,38.64 53.507,38.64 53.087,39.06 51.185,39.06 50.93,39.315 50.93,40.325 51.222,40.617 51.222,40.919 50.835,41.306 50.835,48.075 51.513,48.753 51.513,48.867 v1@51.24,49.14 ; v1(51.23,49.14) 51.23,49.19 51.52,49.48 51.52,50.21 51.58,50.27 51.58,51.89 51.24,52.23 R125.2@51.24,52.36
DDR_CLK_P: R125.1 U5.J7 U13.N22 | length 27.5
  Top Layer w0.09: 50.83,35.94 50.83,36.446
  Top Layer w0.1: U13.N22@50.58,35.69 50.83,35.94 ; 50.83,36.446 50.72,36.556 50.72,36.56 50.71,36.57 50.71,37.675 51.075,38.04 v1(51.25,38.04) ; U5.J7@51.63,49.54 v1(52.03,49.14)
  Bottom Layer w0.1: 51.065,41.401 51.069,41.401 51.069,47.984 51.743,48.657 51.743,48.85 52.03,49.137 v1(52.03,49.14) 51.75,49.42 51.75,50.114 51.81,50.174 51.81,51.89 52.14,52.22 R125.1@52.14,52.36 ; 51.11,41.36 51.452,41.018 51.452,40.522 51.16,40.23 51.16,39.41 51.28,39.29 53.182,39.29 53.602,38.87 53.73,38.87 53.81,38.95 54.135,38.95 54.215,38.87 54.35,38.87 54.43,38.95 54.745,38.95 54.825,38.87 54.99,38.87 55.07,38.95 55.385,38.95 55.6,38.735 55.6,38.215 55.375,37.99 52.54,37.99 52.173,38.357 51.363,38.357 51.26,38.255 51.26,38.05 v1(51.25,38.04)
DDR_CSN: R118.1 U5.L2 U13.M22 | length 31.5
  Top Layer w0.12: U5.L2@47.63,47.94 v1(48.03,48.34) ; v1(48.56,39.44) 48.16,39.84 46.19,39.84 46.11,39.92 46.11,40.12 46.24,40.25 48.58,40.25 49.11,39.72 50.04,39.72 50.23,39.53 50.23,35.84 U13.M22@50.08,35.69
  Bottom Layer w0.12: R118.1@46.82,56.41 46.82,54.859 47.59,54.089 47.59,49.071 47.817,48.844 48.03,48.631 v1(48.03,48.34) 48.321,48.34 48.681,47.98 49.35,47.98 49.55,48.18 49.67,48.18 49.74,48.11 49.74,40.619 v1@48.56,39.44
DDR_DQ0: U5.A2 U13.E22 | length 24
  Top Layer w0.09: 46.21,36.5 46.331,36.379 46.331,36.294 ; 46.33,36.086 46.33,36.294 ; 46.331,36.086 46.331,35.959 U13.E22@46.58,35.71
  Top Layer w0.12: v1(44.83,37.59) 45.129,37.59 45.39,37.329 45.39,36.94 45.56,36.77 45.94,36.77 46.21,36.5 ; U13.E22@46.58,35.69 U13.E22@46.58,35.71 ; v1(47.23,55.54) U5.A2@47.63,55.94
  Signal Layer 2 w0.12: v1@44.84,37.595 v1@44.89,37.595
  Signal Layer 2 w0.127: v1@44.84,37.595 44.28,37.595 44.02,37.855 44.02,40.635 46.74,43.355 46.74,44.685 46.85,44.795 46.85,45.515 46.74,45.625 46.74,52.931 47.604,53.795 47.604,54.442 47.24,54.806 v1@47.24,55.545
DDR_DQ1: U5.C3 U13.F22 | length 25.1
  Top Layer w0.09: 46.83,36.67 47.08,36.42 U13.F22@47.08,35.69
  Top Layer w0.12: v1@45.8,37.66 46.01,37.66 46.14,37.53 46.14,37.36 46.83,36.67 ; U5.C3@48.43,54.34 48.8,53.97 v1(48.8,53.95)
  Signal Layer 2 w0.127: v1@45.76,37.665 45.76,38.045 44.95,38.855 44.95,39.345 50.16,44.555 50.16,44.825 49.99,44.995 49.35,44.995 49.07,45.275 49.07,45.545 49.3,45.775 49.55,45.775 49.82,46.045 49.82,46.425 49.63,46.615 48.99,46.615 48.59,47.015 48.59,47.265 49.206,47.881 49.206,49.821 49.42,50.035 49.42,50.905 48.386,51.938 48.386,53.31 48.635,53.558 48.635,53.78 v1@48.81,53.955
  other v1: 45.75,37.66
DDR_DQ2: U5.A7 U13.H21 | length 25.4
  Top Layer w0.09: v1(47.75,37.83) 48.335,37.245 ; U13.H21@48.08,35.19 48.08,35.2 48.335,35.455 ; 48.33,35.455 48.33,37.245
  Top Layer w0.12: U5.A7@51.63,55.94 v1(52.03,55.54)
  Signal Layer 2 w0.127: v1@47.76,37.835 47.76,38.365 48.164,38.769 48.164,39.615 48.947,40.398 51.253,40.398 53.297,42.442 53.297,51.998 52.44,52.855 52.44,55.145 v1@52.04,55.545
DDR_DQ3: U5.C2 U13.E21 | length 24.1
  Top Layer w0.09: 45.71,36.5 45.83,36.38 45.83,35.58 45.97,35.44 46.33,35.44 U13.E21@46.58,35.19
  Top Layer w0.12: v1(45.03,37.13) 45.03,36.93 45.46,36.5 45.71,36.5 ; v1(47.23,53.94) U5.C2@47.63,54.34
  Signal Layer 2 w0.12: v1@45.04,37.135 v1@45.09,37.135
  Signal Layer 2 w0.127: v1@45.04,37.135 43.78,37.135 43.54,37.375 43.54,43.175 45.5,45.135 45.5,46.895 45.74,47.135 45.74,48.195 45.63,48.305 45.63,53.535 46.04,53.945 v1@47.24,53.945
DDR_DQ4: U5.B8 U13.J21 | length 26.2
  Top Layer w0.09: U13.J21@48.583,35.185 48.583,35.339 48.83,35.586 48.83,35.915 48.773,35.972 ; v1(48.73,37.69) 48.73,37.399 48.77,37.359 48.77,35.972
  Top Layer w0.12: U5.B8@52.43,55.245 U5.B8@52.43,55.14 v1(52.83,54.74)
  Signal Layer 2 w0.127: v1@48.735,37.69 48.95,37.475 49.524,37.475 50.307,38.258 50.307,38.435 51.37,39.498 53.213,39.498 54.36,40.645 54.36,41.364 55.59,42.594 55.59,42.75 ; v1@52.84,54.745 55.593,51.992 55.593,42.75
DDR_DQ5: U5.C8 U13.J22 | length 25
  Top Layer w0.09: v1(48.25,37.83) 48.25,37.61 48.58,37.28 U13.J22@48.58,35.69
  Top Layer w0.12: U5.C8@52.43,54.34 52.43,54.32 v1@52.81,53.94
  Signal Layer 2 w0.127: v1@48.26,37.835 48.501,38.076 49.521,38.076 49.88,38.435 49.88,38.955 50.85,39.925 52.67,39.925 53.11,40.365 53.11,40.635 52.83,40.915 52.83,41.327 53.188,41.685 54.05,41.685 54.35,41.985 54.35,42.465 54.97,43.085 54.97,51.842 v1@52.867,53.945
  other v1: 52.83,53.94
DDR_DQ6: U5.D7 U13.H22 | length 25.4
  Top Layer w0.09: v1(47.73,37.02) v1@47.835,36.915 ; 47.83,35.895 v1@47.83,36.915 ; 47.835,35.895 48.08,35.65 U13.H22@48.08,35.69
  Top Layer w0.12: v1@51.25,53.16 U5.D7@51.63,53.54
  Signal Layer 2 w0.127: v1@47.74,37.025 47.38,37.385 47.38,39.005 47.72,39.345 47.72,40.03 48.515,40.825 51.014,40.825 52.87,42.681 52.87,47.865 52.68,48.055 52.33,48.055 52.13,48.255 52.13,48.395 52.31,48.575 52.64,48.575 52.79,48.725 52.79,49.685 52.53,49.945 51.87,49.945 51.7,50.115 51.7,50.545 51.82,50.665 52.49,50.665 52.67,50.845 52.67,51.265 51.75,52.185 51.5,52.185 51.24,52.445 v1@51.24,53.145
  other v1: 51.23,53.14
DDR_DQ7: U5.A3 U13.G21 | length 25.9
  Top Layer w0.09: 46.66,36.49 46.83,36.32 46.83,36.086 46.828,36.084 46.828,35.796 46.83,35.794 46.83,35.586 ; 46.83,35.586 46.83,35.554 46.943,35.44 46.976,35.44 ; 46.979,35.44 47.181,35.44 ; 47.186,35.44 47.323,35.44 47.573,35.19 U13.G21@47.58,35.19
  Top Layer w0.12: v1(45.8,37.14) 46.01,37.14 46.66,36.49 ; v1(48.03,55.54) U5.A3@48.43,55.94
  Signal Layer 2 w0.127: v1@45.81,37.145 45.61,37.145 45.33,37.425 45.33,37.89 45.19,38.03 44.595,38.03 44.45,38.175 44.45,39.953 45.621,41.124 45.621,41.556 45.83,41.765 46.262,41.765 48.655,44.158 48.655,44.58 47.65,45.585 47.65,49.995 48.2,50.545 48.2,51.445 47.78,51.865 47.78,53.298 47.96,53.477 47.96,53.487 48.04,53.568 v1@48.04,55.545
DDR_DQ8: U5.F2 U13.T21 | length 26
  Top Layer w0.09: 51.48,38.61 51.63,38.46 51.63,36 51.83,35.795 51.83,35.435 ; 51.835,35.435 U13.T21@52.08,35.19
  Top Layer w0.12: U5.F2@47.63,51.94 47.23,51.54 44.56,51.54 43.62,50.6 43.62,42.34 45.25,40.71 49.644,40.71 50.83,39.524 50.83,39.25 51.45,38.63
DDR_DQ9: U5.E3 U13.U21 | length 26.2
  Top Layer w0.09: 52.33,35.435 52.33,37.02 ; 52.335,35.435 U13.U21@52.58,35.19
  Top Layer w0.12: U5.E3@48.43,52.74 48.02,52.33 48.02,50.93 48.21,50.74 49.41,50.74 49.61,50.54 49.61,47.932 49.4,47.722 49.4,43.722 48.74,43.062 48.74,42.68 48.45,42.39 46.66,42.39 46.56,42.29 46.56,42.08 46.67,41.97 50.166,41.97 52.09,40.046 52.09,39.772 52.717,39.145 52.717,37.397 52.34,37.02
DDR_DQ10: U5.G2 U13.T22 | length 25.9
  Top Layer w0.09: 51.83,37.43 51.83,36.077 52.08,35.827 U13.T22@52.08,35.69
  Top Layer w0.12: U5.G2@47.63,51.14 47.63,50.92 47.22,50.51 47.22,50.1 47.06,49.94 46.55,49.94 45.435,48.825 44.425,48.825 44.13,48.53 44.13,48.1 44.3,47.93 44.83,47.93 44.95,47.81 44.95,47.52 44.8,47.37 44.41,47.37 44.04,47 44.04,44.62 44.29,44.37 44.55,44.37 44.72,44.2 44.72,43.74 44.56,43.58 44.27,43.58 44.04,43.35 44.04,42.514 45.424,41.13 49.818,41.13 51.25,39.698 51.25,39.424 51.877,38.797 51.877,37.452 51.855,37.43
DDR_DQ11: U5.F7 U13.W21 | length 25.8
  Top Layer w0.09: U13.W21@53.58,35.19 53.713,35.19 53.963,35.44 54.193,35.44 54.33,35.577 54.33,36.351 ; 54.335,36.351 54.457,36.473
  Top Layer w0.12: U5.F7@51.63,51.94 52.03,51.54 54.1,51.54 54.6,52.04 55.356,52.04 55.933,51.463 55.933,50.977 56.45,50.46 56.45,48.57 56.94,48.08 56.94,47.496 56.497,47.053 56.497,46.823 56.94,46.38 56.94,45.786 56.51,45.356 56.51,45.06 56.94,44.63 56.94,44.106 56.61,43.776 56.61,43.26 57,42.87 57,42.01 57.11,41.9 57.744,41.9 58.14,41.504 58.14,39.81 55.52,37.19 55.174,37.19 54.457,36.473
DDR_DQ12: U5.H8 U13.W23 | length 25.1
  Top Layer w0.09: U13.W23@53.58,36.19 53.58,36.44 54.245,37.105
  Top Layer w0.12: U5.H8@52.43,50.34 52.85,49.92 55.73,49.92 56.03,49.62 56.03,48.396 56.52,47.906 56.52,47.67 56.03,47.18 56.03,46.696 56.52,46.206 56.52,45.96 56.03,45.47 56.03,44.946 56.52,44.456 56.52,44.28 56.03,43.79 56.03,42.99 56.182,42.838 56.438,42.838 56.58,42.696 56.58,42.3 56.487,42.207 55.92,42.207 55.707,42.42 55.336,42.42 54.57,41.654 54.57,41.306 55.148,40.728 55.426,40.728 55.758,41.06 57.2,41.06 57.3,40.96 57.3,40.16 54.245,37.105
DDR_DQ13: U5.H3 U13.T23 | length 25.3
  Top Layer w0.09: U13.T23@52.08,36.19 52.08,37.31
  Top Layer w0.12: U5.H3@48.43,50.34 49.02,50.34 49.19,50.17 49.19,48.106 48.98,47.896 48.98,43.896 47.894,42.81 46.64,42.81 46.28,43.17 46.08,43.17 45.78,42.87 45.49,42.87 45.2,43.16 44.69,43.16 44.469,42.939 44.469,42.679 45.598,41.55 49.992,41.55 51.67,39.872 51.67,39.598 52.297,38.971 52.297,37.507 52.1,37.31
DDR_DQ14: U5.H7 U13.W22 | length 24.5
  Top Layer w0.09: U13.W22@53.58,35.69 53.31,35.96 53.31,36.53 54.34,37.56 54.34,37.794 54.355,37.809
  Top Layer w0.12: U5.H7@51.63,50.34 50.87,49.58 50.87,48.84 51.08,48.63 51.08,44.18 51.08,43.476 52.291,42.265 52.99,42.265 53.17,42.445 53.17,42.9 53.32,43.05 54.47,43.05 54.78,42.74 54.78,42.458 54.15,41.828 54.15,41.132 55.362,39.92 55.65,39.92 55.81,40.08 55.81,40.5 55.95,40.64 56.69,40.64 56.84,40.49 56.84,40.294 55.746,39.2 55.477,39.2 55.198,38.921 55.198,38.652 54.826,38.28 54.557,38.28 54.355,38.078 54.355,37.809
DDR_DQ15: U5.F8 U13.Y21 | length 24.2
  Top Layer w0.09: U13.Y21@54.079,35.192 54.216,35.192 54.464,35.44 54.692,35.44 54.83,35.578 54.83,36.345 ; 54.835,36.345 54.97,36.48 55.404,36.48 55.517,36.593
  Top Layer w0.12: U5.F8@52.43,51.94 52.81,52.32 53.43,52.32 53.457,52.347 ; 53.444,52.36 53.544,52.46 55.55,52.46 57.42,50.59 57.42,42.818 58.56,41.678 58.56,39.636 55.517,36.593
DDR_DQM0: U5.D3 U13.H23 | length 24.7
  Top Layer w0.09: 47.39,37.997 47.39,37.68 47.697,37.373 47.897,37.373 48.08,37.19 U13.H23@48.08,36.19
  Top Layer w0.12: v1(45.57,38.86) 45.99,38.44 46.947,38.44 47.39,37.997 ; U5.D3@48.41,53.543 48.387,53.52 48.41,53.52 v1(48.8,53.13)
  Signal Layer 2 w0.127: v1@45.58,38.865 45.58,39.371 48.334,42.125 49.65,42.125 49.78,42.255 49.78,42.475 49.67,42.585 49.22,42.585 49.087,42.718 49.087,42.878 49.564,43.355 49.82,43.355 50.587,44.122 50.587,45.002 50.247,45.342 50.247,46.045 50.41,46.208 50.41,46.625 49.993,47.042 49.493,47.042 49.347,47.188 49.347,47.418 49.633,47.705 49.633,49.645 49.847,49.858 49.847,51.082 48.813,52.115 v1@48.813,53.134
DDR_DQM1: U5.E7 U13.V22 | length 26.8
  Top Layer w0.09: 50.675,43.308 50.675,44.61 ; U13.V22@53.08,35.69 53.08,36.62 53.935,37.475 53.935,37.728
  Top Layer w0.12: U5.E7@51.63,52.74 50.98,52.74 50.66,53.06 50.66,53.87 50.35,54.18 49.84,54.18 49.53,53.87 49.53,53 50.66,51.87 50.66,49.98 50.62,49.94 50.62,48.43 50.66,48.39 50.66,43.302 52.117,41.845 53.539,41.845 53.73,41.654 53.73,40.53 53.933,40.327 54.362,40.327 54.807,39.882 54.807,39.124 53.935,38.252 53.935,37.728
DDR_DQS0_N: U5.B7 U13.G23 | length 24.7
  Top Layer w0.1: v1(46.98,37.74) 46.85,37.61 46.85,37.45 47.09,37.21 47.09,37.103 47.58,36.613 U13.G23@47.58,36.19 ; U5.B7@51.63,55.14 v1(52.03,54.74)
  Signal Layer 2 w0.09: v1@46.99,37.76 46.85,37.9 46.85,39.738 48.598,41.486 50.467,41.486 50.965,41.985 50.965,42.635 50.733,42.868 50.733,43.162 50.988,43.417 51.348,43.417 51.72,43.79 51.72,44.345 51.225,44.839 51.225,46.895 50.485,47.635 50.485,53.665 50.565,53.745 51.525,53.745 51.75,53.97 51.75,54.47 v1@52.025,54.745
DDR_DQS0_P: U5.C7 U13.G22 | length 25.4
  Top Layer w0.1: v1(46.48,37.74) 46.62,37.6 46.62,37.355 46.86,37.115 46.86,37.007 47.35,36.517 47.35,36.314 47.3,36.264 47.3,35.97 U13.G22@47.58,35.69 ; v1(51.23,54.74) U5.C7@51.63,54.34
  Signal Layer 2 w0.09: v1@46.49,37.765 46.61,37.885 46.61,39.823 48.503,41.716 50.371,41.716 50.735,42.08 50.735,42.54 50.503,42.772 50.503,43.258 50.892,43.647 51.252,43.647 51.49,43.885 51.49,44.25 50.995,44.744 50.995,46.799 50.255,47.539 50.255,53.76 50.47,53.975 51.43,53.975 51.52,54.065 51.52,54.465 v1@51.24,54.745
  Signal Layer 2 w0.1: v1@51.24,54.745 v1@51.28,54.745
DDR_DQS1_N: U5.G3 U13.U23 | length 25.2
  Top Layer w0.1: U5.G3@48.43,51.14 48.71,51.42 49.005,51.42 49.315,51.73 49.8,51.73 50.02,51.51 50.02,47.69 49.81,47.48 49.81,47.13 50.02,46.92 50.02,46.755 49.81,46.545 49.81,46.22 50.02,46.01 50.02,45.855 49.81,45.645 49.81,45.33 50.02,45.12 50.02,45.005 49.81,44.795 49.81,44.48 50.02,44.27 50.02,43.305 49.955,43.24 49.498,43.24 49.167,42.909 49.167,42.615 49.401,42.38 50.677,42.38 50.8,42.257 50.8,41.916 51.056,41.66 51.397,41.66 51.548,41.508 51.548,41.167 51.955,40.76 52.285,40.76 52.73,41.205 52.945,41.205 53.09,41.06 53.09,40.915 52.5,40.325 52.5,39.942 52.755,39.687 54.04,39.687 54.167,39.56 54.167,39.389 54.06,39.282 53.372,39.282 53.127,39.037 53.127,38.568 53.295,38.4 53.295,37.972 53.127,37.804 53.127,37.382 52.63,36.885 52.63,36.24 U13.U23@52.58,36.19
DDR_DQS1_P: U5.F3 U13.U22 | length 26.2
  Top Layer w0.1: U5.F3@48.43,51.94 48.72,51.65 48.91,51.65 49.22,51.96 49.895,51.96 50.25,51.605 50.25,47.595 50.04,47.385 50.04,47.225 50.25,47.015 50.25,46.66 50.04,46.45 50.04,46.315 50.25,46.105 50.25,45.76 50.04,45.55 50.04,45.425 50.25,45.215 50.25,44.91 50.04,44.7 50.04,44.575 50.25,44.365 50.25,43.21 50.05,43.01 49.593,43.01 49.397,42.813 49.397,42.71 49.497,42.61 50.772,42.61 51.03,42.352 51.03,42.011 51.151,41.89 51.492,41.89 51.786,41.596 51.786,41.255 52.05,40.99 52.19,40.99 52.635,41.435 53.04,41.435 53.32,41.155 53.32,40.82 52.73,40.23 52.73,40.037 52.85,39.917 54.135,39.917 54.397,39.655 54.397,39.294 54.155,39.052 53.468,39.052 53.357,38.942 53.357,38.663 53.525,38.495 53.525,37.876 53.357,37.708 53.357,37.287 52.86,36.79 52.86,35.97 U13.U22@52.58,35.69
DDR_ODT: R122.1 U5.K1 U13.L22 | length 31.3
  Top Layer w0.12: U5.K1@46.83,48.74 v1(47.23,48.34) ; v1(48.82,38.93) 49.19,39.3 49.85,39.3 49.96,39.19 49.96,39.08 49.75,38.87 49.75,38.704 49.957,38.497 49.957,36.067 U13.L22@49.58,35.69
  Bottom Layer w0.12: R122.1@44.68,54.22 44.73,54.27 45.52,54.27 45.89,53.9 46.329,53.9 47.02,53.209 47.02,49.439 46.87,49.289 46.87,48.7 v1(47.23,48.34) 47.479,48.34 47.904,47.915 48.235,47.915 48.565,47.585 49.175,47.585 49.47,47.29 49.47,40.943 48.167,39.64 46.06,39.64 45.86,39.44 45.86,39.099 46.099,38.86 46.297,38.86 46.575,38.582 46.73,38.582 46.83,38.682 46.83,38.94 47.01,39.12 47.23,39.12 47.34,39.01 47.34,38.74 47.47,38.61 48.11,38.61 48.43,38.93 v1(48.82,38.93)
DDR_RASN: R115.1 U5.J3 U13.N21 | length 30.1
  Top Layer w0.09: U13.N21@50.58,35.19 50.83,34.93 v1@50.83,34.32 ; v1(50.78,34.26) v1@50.84,34.32
  Top Layer w0.1: U5.J3@48.416,49.52 U5.J3@48.418,49.521
  Top Layer w0.12: U5.J3@48.43,49.54 v1(48.83,49.94)
  Bottom Layer w0.12: R115.1@50.06,56.41 50.06,55.37 49.19,54.5 49.19,50.78 48.83,50.42 v1(48.83,49.94) 49.09,49.94 50.51,51.36 50.75,51.36 50.82,51.29 50.82,50.641 51.02,50.441 51.02,49.74 50.55,49.27 50.55,40.94 50.62,40.87 50.62,38.93 50.52,38.83 50.52,38.17 50.78,37.91 50.78,37.403 50.5,37.123 50.5,36.6 50.42,36.52 49.92,36.52 49.76,36.36 49.76,36.251 49.91,36.101 50.459,36.101 50.54,36.02 50.54,35.068 50.75,34.858 v1@50.75,34.26
DDR_RESETN: R37.2 U5.T2 U13.D20 | length 16.7
  Top Layer w0.09: 45.226,36.413 45.33,36.309 45.33,35.57 45.46,35.44 45.688,35.44 45.83,35.3 45.83,34.94 U13.D20@46.08,34.69
  Top Layer w0.12: v1(42.15,43.38) 43.09,42.44 43.09,41.89 44.33,40.65 44.33,37.3 44.339,37.3 45.226,36.413 ; v1(45.32,43.93) 45.66,43.59 ; 45.66,43.58 47.28,43.58 ; 47.28,43.59 U5.T2@47.63,43.94
  Bottom Layer w0.12: v1(42.15,43.38) 42.15,43.75 42.25,43.85 45.12,43.85 45.2,43.93 v1(45.32,43.93)
DDR_WEN: R117.1 U5.L3 U13.M20 | length 30.2
  Top Layer w0.09: v1(49.65,33.73) 50.08,34.16 U13.M20@50.08,34.69
  Top Layer w0.12: U5.L3@48.43,47.94 v1(48.83,48.34)
  Bottom Layer w0.12: R117.1@47.9,56.41 47.9,55.93 47.66,55.69 47.66,55.15 48.01,54.8 48.01,49.669 48.43,49.249 48.43,48.74 v1(48.83,48.34) ; 48.4,36.9 49.044,36.9 49.746,37.603 49.746,37.756 49.56,37.942 49.56,38.26 49.68,38.38 49.68,38.689 49.474,38.895 ; 48.44,36.9 48.4,36.9 48.21,36.9 48.151,36.841 48.151,36.671 48.341,36.481 48.669,36.481 48.748,36.402 48.748,36.074 49.69,35.133 49.69,34.73 49.97,34.45 49.97,34.33 49.97,33.81 49.89,33.73 v1(49.65,33.73) v1@49.65,33.791 ; v1@48.797,48.33 49.17,48.33 49.29,48.45 49.29,48.71 49.43,48.85 49.86,48.85 50.01,48.7 50.01,40.295 49.11,39.395 49.11,39.2 49.42,38.89 49.469,38.89
DSCL: CN9.15 R98.1 U14.49 U33.3 | length 32.3
  Top Layer w0.1: U14.49@73.425,22.425 73.425,21.55 75,19.975 76.125,19.975 76.725,19.375 76.725,17.083 78.958,14.85 83.121,14.85 85.625,12.346 85.625,10.825 85.075,10.275 R98.1@84.975,10.275 84.975,10.075 85.408,10.075 87.283,8.2 89.208,8.2 90.333,7.075 90.933,7.075 91.058,6.95 91.8,6.95 v1(92.1,7.25) CN9.15@93.5,7.25
  Bottom Layer w0.1: U33.3@90.7,6.85 91.7,6.85 v1(92.1,7.25)
DSDA: CN9.16 R97.1 U14.48 U33.6 | length 36.2
  Top Layer w0.1: U14.48@72.925,22.425 72.925,21.925 73.225,21.625 73.225,21.467 74.917,19.775 76.042,19.775 76.525,19.292 76.525,17 78.875,14.65 83.039,14.65 85.425,12.264 85.425,10.975 85.225,10.775 84.55,10.775 84.05,10.275 R97.1@83.925,10.275 84.4,9.8 85.4,9.8 87.2,8 89.125,8 90.25,6.875 90.85,6.875 90.975,6.75 v1(92.1,6.75) CN9.16@93.5,6.75
  Bottom Layer w0.1: U33.6@89.75,7.85 89.912,7.85 90.225,7.537 90.225,6.625 90.475,6.375 91.725,6.375 v1(92.1,6.75)
DSI_CK_N: CN4.5 U13.A16 | length 26.4
  Top Layer w0.09: 30.337,36.226 30.337,36.233
  Top Layer w0.1: CN4.5@20.675,36 21.215,36 21.584,36.369 23.436,36.369 23.805,36 CN4.5@24.425,36 25.053,36 25.424,36.371 27.117,36.371 v1(27.245,36.243) ; v1(29.897,36.24) 30.029,36.373 30.191,36.373 30.337,36.226 30.525,36.039 30.525,35.52 32.981,33.064 40.181,33.064 40.555,32.69 U13.A16@44.58,32.69
  Bottom Layer w0.1: v1(27.245,36.243) 27.378,36.375 29.762,36.375 v1(29.897,36.24)
DSI_CK_P: CN4.6 U13.B16 | length 27.1
  Top Layer w0.09: 43.697,32.93 43.707,32.94 44.83,32.94 U13.B16@45.08,32.69
  Top Layer w0.1: CN4.6@20.675,37 21.202,37 21.604,36.599 23.394,36.599 23.795,37 CN4.6@24.425,37 25.044,37 25.443,36.601 27.103,36.601 v1(27.245,36.743) ; v1(29.897,36.74) 30.034,36.603 30.286,36.603 30.755,36.134 30.755,35.615 33.076,33.294 40.276,33.294 40.64,32.93 43.697,32.93
  Bottom Layer w0.1: v1(27.245,36.743) 27.383,36.605 29.762,36.605 v1(29.897,36.74)
DSI_D0_N: CN4.8 U13.B15 | length 27.8
  Top Layer w0.09: 43.698,32.2 43.708,32.19 U13.B15@45.08,32.19
  Top Layer w0.1: CN4.8@20.675,39 21.223,39 21.608,39.385 23.423,39.385 23.808,39 CN4.8@24.425,39 25.053,39 25.405,39.352 25.573,39.352 32.44,32.485 39.71,32.485 39.995,32.2 43.698,32.2
DSI_D0_P: CN4.9 U13.C15 | length 28.5
  Top Layer w0.09: 43.699,32.43 43.709,32.44 45.33,32.44 U13.C15@45.58,32.19
  Top Layer w0.1: CN4.9@20.675,40 21.232,40 21.617,39.615 23.378,39.615 23.763,40 CN4.9@24.425,40 25.082,40 25.5,39.582 25.668,39.582 32.535,32.715 39.805,32.715 40.09,32.43 43.699,32.43
DSI_D1_N: CN4.2 U13.A17 | length 25.1
  Top Layer w0.09: 43.7,33.2 43.71,33.19 U13.A17@44.58,33.19
  Top Layer w0.1: CN4.2@20.675,33 21.208,33 21.593,33.385 23.418,33.385 23.803,33 CN4.2@24.425,33 25.034,33 25.405,33.371 27.861,33.371 28.332,33.842 29.311,33.842 v1(29.446,33.707) ; v1(33.313,33.707) 33.448,33.842 40.544,33.842 41.186,33.2 43.7,33.2
  Bottom Layer w0.1: v1(29.446,33.707) 29.581,33.842 33.178,33.842 v1(33.313,33.707)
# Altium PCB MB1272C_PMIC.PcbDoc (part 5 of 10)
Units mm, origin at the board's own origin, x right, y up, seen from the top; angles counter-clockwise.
Board outline 101 x 71 mm, 6 copper layers (Top Layer, Signal Layer 1, Signal Layer 2, Signal Layer 3, Signal Layer 4, Bottom Layer), stack 1.552 mm thick; 518 components, 478 nets, 2152 pads, 1871 vias.
Unrouted connection lines stored in the file: 3.

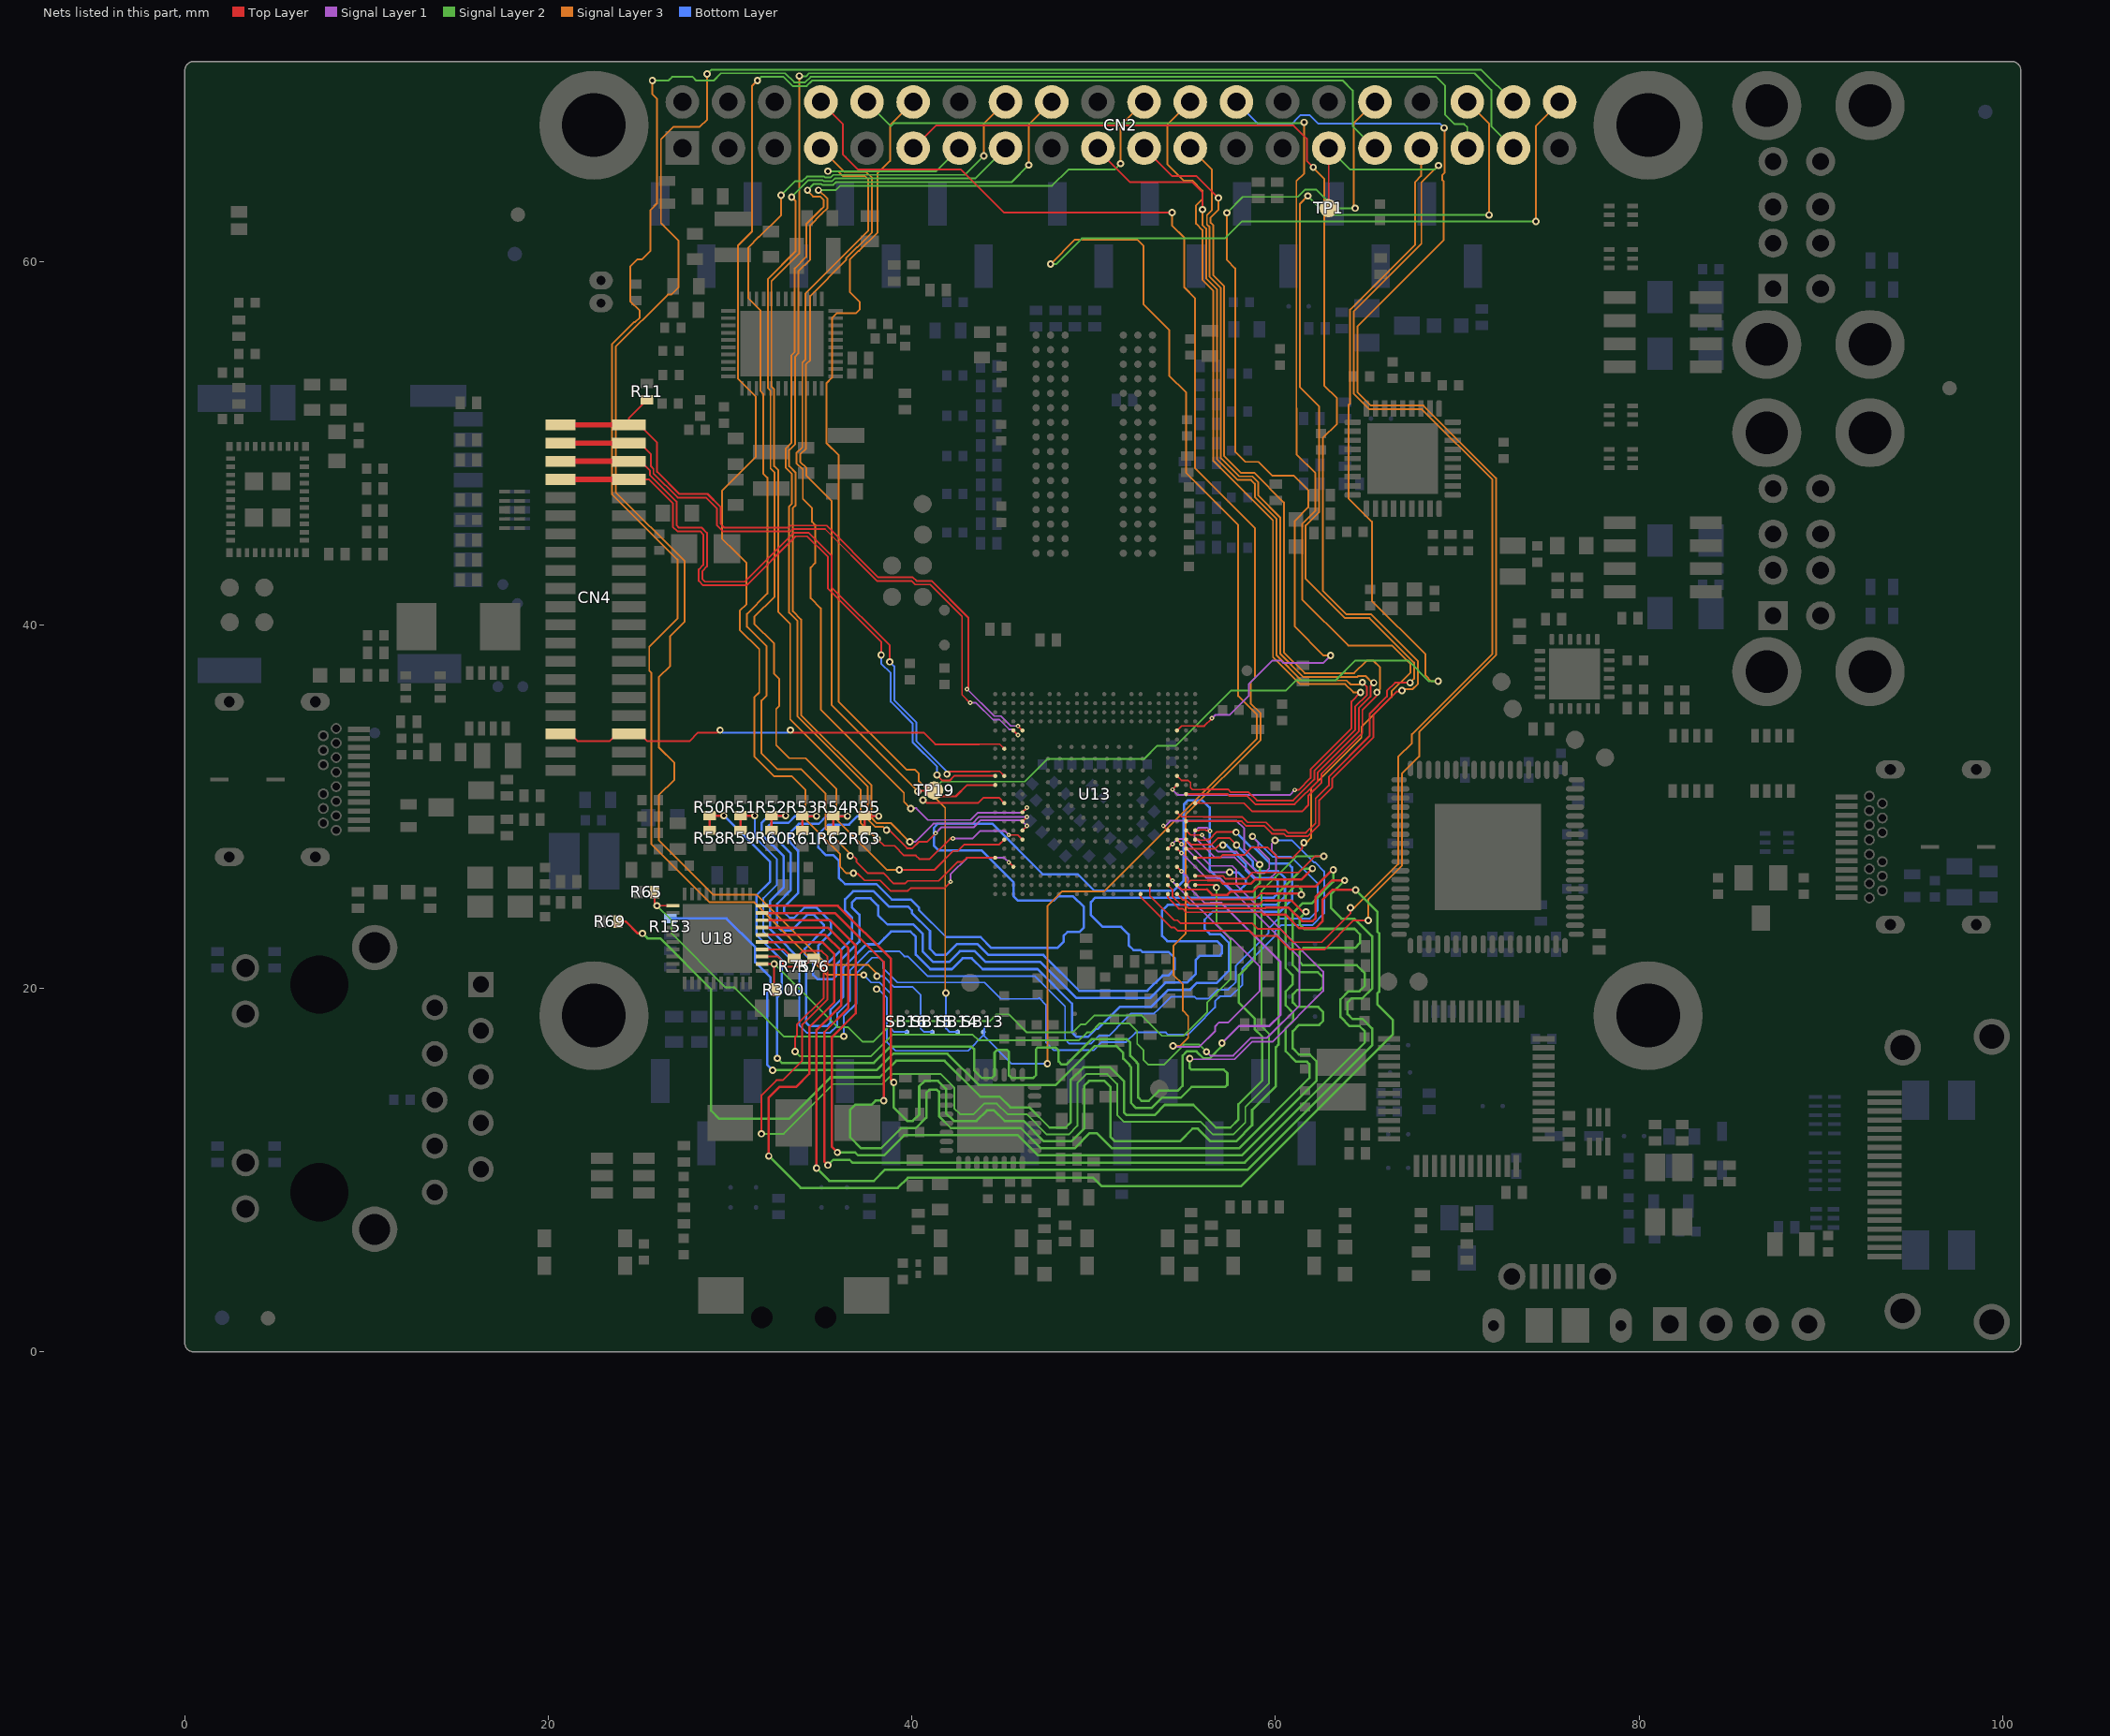
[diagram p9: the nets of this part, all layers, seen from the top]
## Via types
v1: diameter 0.4, hole 0.2, Top Layer to Bottom Layer, tented both sides, 884 vias
v2: diameter 0.25, hole 0.1, Top Layer to Signal Layer 1, tented top, 470 vias
v3: diameter 0.6, hole 0.3, Top Layer to Bottom Layer, tented both sides, 469 vias
v4: diameter 0.25, hole 0.1, Top Layer to Signal Layer 1, tented both sides, 46 vias
v5: diameter 0.25, hole 0.1, Top Layer to Bottom Layer, tented top, 2 vias

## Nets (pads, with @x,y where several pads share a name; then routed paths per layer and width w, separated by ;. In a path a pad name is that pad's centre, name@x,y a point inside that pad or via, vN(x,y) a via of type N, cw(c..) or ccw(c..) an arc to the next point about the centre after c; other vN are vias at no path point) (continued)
DSI_D1_P: CN4.3 U13.B17 | length 25.7
  Top Layer w0.09: 43.697,33.43 43.707,33.44 44.83,33.44 U13.B17@45.08,33.19
  Top Layer w0.1: CN4.3@20.675,34 21.221,34 21.606,33.615 23.38,33.615 23.765,34 CN4.3@24.425,34 25.047,34 25.447,33.601 27.766,33.601 28.237,34.072 29.311,34.072 v1(29.446,34.207) ; v1(33.313,34.207) 33.448,34.072 40.639,34.072 41.281,33.43 43.697,33.43
  Bottom Layer w0.1: v1(29.446,34.207) 29.581,34.072 33.178,34.072 v1(33.313,34.207)
DSI_LCD_BL_CTRL: CN4.19 U13.C19 | length 35.9
  Top Layer w0.09: 33.424,45.27 34.759,45.27 35.224,45.27 38.074,42.42 38.301,42.42 38.302,42.419 39.973,42.419 40.172,42.22 41.011,42.22 42.76,40.471 42.76,36.155 v4(43.202,35.712)
  Top Layer w0.1: CN4.19@24.425,50 25.025,50 25.65,49.375 25.65,48.725 25.783,48.592 25.783,48.335 27.112,47.005 28.675,47.005 29.275,46.405 29.275,45.475 29.6,45.15 33.309,45.15 33.424,45.265 ; U13.C19@45.58,34.19 v2(45.83,33.94)
  Top Layer w0.3: CN4.19@20.675,50 CN4.19@24.425,50
  Signal Layer 1 w0.09: v4(43.202,35.712) 43.532,35.712 44.454,34.79 44.81,34.79 45.35,34.25 45.52,34.25 v2(45.83,33.94)
DSI_LCD_INT: CN4.17 U13.A14 | length 39.2
  Top Layer w0.1: CN4.17@24.425,48 25.551,48 26.85,46.701 26.85,45.4 27.1,45.15 28.35,45.15 28.525,44.975 28.525,43.3 28.275,43.05 28.275,42.425 28.525,42.175 30.9,42.175 33.6,44.875 34.237,44.875 35.38,43.732 35.38,41.994 38.305,39.069 v1(38.305,38.34) ; v1(41.38,31.74) 41.68,31.44 42.075,31.44 42.325,31.69 U13.A14@44.58,31.69
  Top Layer w0.3: CN4.17@20.675,48 CN4.17@24.425,48
  Bottom Layer w0.1: v1(38.305,38.34) 38.305,37.865 38.83,37.34 38.83,35.776 40.04,34.566 40.04,33.533 41.38,32.193 v1(41.38,31.74)
DSI_RESET: CN4.20 R11.2 U13.D19 | length 38.3
  Top Layer w0.1: R11.2@25.425,52.375 24.425,51.375 CN4.20@24.425,51 24.425,50.825 25.195,50.825 25.983,50.037 25.983,48.417 27.195,47.205 28.758,47.205 29.475,46.488 29.475,45.558 29.683,45.35 33.226,45.35 33.341,45.465 33.507,45.465 33.517,45.465 34.84,45.465 35.305,45.465 38.155,42.615 38.82,42.615 ; v4(43.03,36.466) 43.105,36.54 43.105,40.402 41.092,42.415 40.253,42.415 40.054,42.614 38.821,42.614 ; v2(45.83,34.44) U13.D19@46.08,34.19 ; 38.82,42.615 38.821,42.614
  Top Layer w0.3: CN4.20@20.675,51 CN4.20@24.425,51
  Signal Layer 1 w0.09: v4(43.03,36.466) 43.048,36.466 44.533,34.98 44.889,34.98 45.429,34.44 v2(45.83,34.44)
DSI_TE: CN4.18 U13.B14 | length 40
  Top Layer w0.09: 44.28,31.94 44.83,31.94 U13.B14@45.08,31.69
  Top Layer w0.1: CN4.18@24.425,49 25.085,49 25.583,48.503 25.583,48.252 27.05,46.784 27.05,45.483 27.183,45.35 28.433,45.35 28.725,45.058 28.725,43.217 28.475,42.967 28.475,42.508 28.608,42.375 30.817,42.375 33.517,45.075 34.32,45.075 35.58,43.815 35.58,42.077 38.78,38.877 v1(38.78,37.967) ; v1(41.93,31.79) 42.08,31.94 44.28,31.94
  Top Layer w0.3: CN4.18@20.675,49 CN4.18@24.425,49
  Bottom Layer w0.1: v1(38.78,37.967) 39.03,37.717 39.03,35.859 40.24,34.649 40.24,33.616 41.93,31.926 v1(41.93,31.79)
ETH_CLK: R69.2 U13.Y8 | length 74.2
  Top Layer w0.1: v2(53.83,28.94) U13.Y8@54.08,28.69
  Top Layer w0.13: R69.2@23.825,23.675 24.275,23.675 24.925,23.025 v1(25.175,23.025)
  Signal Layer 1 w0.1: v2(53.83,28.94) 53.941,28.94 54.216,29.215 57.855,29.215 58.28,28.79 58.28,27.665 v1(59.13,26.815)
  Signal Layer 2 w0.13: v1(25.175,23.025) 25.45,22.75 26.15,22.75 28.95,19.95 28.95,13.27 29.395,12.825 33.245,12.825 35.53,15.11 38.224,15.11 39.129,16.015 41.793,16.015 43.768,14.04 44.828,14.04 45.413,13.455 46.459,13.455 47.573,12.341 48.45,12.341 48.725,12.616 48.725,14.946 49.439,15.66 50.901,15.66 51.665,14.896 51.665,13.18 51.815,13.03 53.347,13.03 53.907,13.59 55.482,13.59 56.731,12.341 57.518,12.341 57.965,12.788 57.965,13.628 59.27,14.933 59.27,17.347 58.85,17.767 58.85,18.345 57.985,19.21 57.985,20.728 58.85,21.593 58.85,25.505 59.13,25.785 v1(59.13,26.815)
ETH_CLK125: R153.1 U13.Y6 | length 68.5
  Top Layer w0.1: U13.Y6@54.08,27.69 v2(54.33,27.94)
  Signal Layer 1 w0.1: v2(54.33,27.94) 54.605,28.215 54.955,28.215 56.43,26.74 57.626,26.74 57.831,26.535 57.831,25.719 62.625,20.925 62.625,19.85 59.85,17.075 58.733,17.075 57.758,16.1 55.32,16.1 v1(55.28,16.14)
  Signal Layer 2 w0.13: v1(32.338,15.5) 38.063,15.5 38.968,16.405 41.954,16.405 43.67,14.69 47.917,14.69 50.043,16.815 51.268,16.815 51.625,16.458 51.625,16.133 51.985,15.773 51.985,15.738 52.055,15.668 52.055,13.695 52.33,13.42 53.186,13.42 53.746,13.98 54.785,13.98 55.38,14.575 57.23,14.575 57.35,14.695 57.35,15.331 57.156,15.525 55.376,15.525 55.28,15.621 v1(55.28,16.14)
  Bottom Layer w0.13: R153.1@26.7,23.85 29.799,23.85 31.375,22.274 31.375,21.447 32.225,20.597 32.225,19.933 32.05,19.758 32.05,15.788 v1(32.338,15.5)
ETH_GTX_CLK: U13.AB2 U18.20 | length 71
  Top Layer w0.09: U13.AB2@55.08,25.69 55.33,25.94 56.28,25.94
  Top Layer w0.1: 38.83,16.965 38.834,16.961
  Top Layer w0.13: U18.20@31.75,24.55 31.76,24.54 35.923,24.54 38.845,21.618 38.845,14.98 v1(39,14.825) ; 56.28,25.94 56.925,25.94 57.115,25.75 58.633,25.75 58.887,26.004 61.444,26.004 v1(62.03,26.59)
  Signal Layer 2 w0.13: v1(39,14.825) 39,13.441 39.736,12.705 40.05,12.705 40.4,13.055 40.4,14.61 40.7,14.91 41.44,14.91 41.875,14.475 41.875,13.13 42.3,12.705 43.547,12.705 44.132,13.29 44.518,13.29 45.103,12.705 46.148,12.705 47.262,11.591 48.782,11.591 49.475,12.284 49.475,14.635 49.75,14.91 50.59,14.91 50.915,14.585 50.915,11.844 51.168,11.591 54.74,11.591 55.429,12.28 55.731,12.28 56.42,11.591 57.828,11.591 58.715,12.478 58.715,13.318 60.02,14.623 60.02,16.764 60.165,16.909 60.165,25.267 61.488,26.59 v1(62.03,26.59)
ETH_MDC: R76.1 U13.AA6 U18.13 | length 53.7
  Top Layer w0.1: U18.13@31.75,21.75 32.625,21.75 32.9,21.475 32.9,21.275 32.975,21.2 34.05,21.2 34.5,21.65 R76.1@34.675,21.65 ; v1(33.575,16.525) 33.575,17.325 33.675,17.425 33.675,18.003 35.155,19.483 35.155,21.095 R76.1@34.6,21.65 ; U13.AA6@54.58,27.69 v2(54.83,27.44)
  Signal Layer 1 w0.1: v2(54.83,27.44) 56.195,26.075 56.95,26.075 61.325,21.7 61.325,19.061 59.539,17.275 58.65,17.275 57.675,16.3 56.42,16.3 v1(56.205,16.515)
  Signal Layer 2 w0.1: v1(33.575,16.525) 33.825,16.275 37.756,16.275 38.931,17.45 43.35,17.45 43.65,17.15 49.195,17.15 49.625,17.58 49.848,17.58 ; 49.87,17.602 50.343,18.075 51.95,18.075 52.39,17.635 52.39,16.95 52.75,16.59 52.75,16.055 53.005,15.8 53.858,15.8 54.963,16.905 54.97,16.912 55.808,16.912 v1(56.205,16.515)
ETH_MDINT: R65.1 U13.AC8 U18.31 | length 68.3
  Top Layer w0.09: U13.AC8@55.58,28.69 55.78,28.69 55.81,28.72 56.15,28.72 56.18,28.69 v4@56.38,28.69
  Top Layer w0.1: R65.1@25.85,25.3 25.85,24.675 v1(25.975,24.55) U18.31@26.85,24.55 ; v4@56.38,28.69 v4(56.405,28.665)
  Signal Layer 1 w0.1: v4(56.405,28.665) 56.23,28.84 55.755,28.84 55.555,28.64 55.555,28.315 56.655,27.215 57.755,27.215 58.955,26.015 59.655,26.015 60.03,26.39 60.03,27.34 59.805,27.565 59.805,27.965 v1(59.98,28.14)
  Signal Layer 2 w0.1: v1(25.975,24.55) 26.775,23.75 26.775,23.025 29.75,20.05 30.25,20.05 32.96,17.34 36.28,17.34 v1(36.255,17.365)
  Bottom Layer w0.1: v1(36.255,17.365) 36.255,18.485 36.95,19.18 36.95,20.835 37.805,21.69 38.2,21.69 38.405,21.485 38.405,21.12 39.2,20.325 44.005,20.325 44.905,19.425 46.952,19.425 47,19.473 47.375,19.098 47.375,17.025 47.8,16.6 49.992,16.6 50.442,17.05 51.785,17.05 52.31,17.575 53.971,17.575 54.096,17.45 55.175,17.45 55.615,17.89 56.675,18.95 56.675,19.286 56.964,19.575 57.541,19.575 58.175,20.209 58.175,21.1 59.98,22.905 59.98,23.15 60.305,23.475 62.025,23.475 62.68,24.13 62.68,26.435 62.175,26.94 62.11,26.94 60.91,28.14 v1(59.98,28.14)
ETH_MDIO: R75.1 U13.AC3 U18.14 | length 76.8
  Top Layer w0.1: v1(31.725,12) 31.725,14.13 32.545,14.95 32.9,14.95 33.965,16.015 33.965,18.01 35.355,19.4 35.355,21.74 35.04,22.055 34.005,22.055 33.6,21.65 R75.1@33.525,21.65 33.45,21.65 32.95,22.15 U18.14@31.75,22.15 ; U13.AC3@55.58,26.19 56.639,26.19 ; 56.634,26.194 56.639,26.19 ; v1(62.655,27.265) 62.155,27.265 61.269,26.379 58.731,26.379 58.383,26.03 57.27,26.03 57.11,26.19 56.639,26.19
  Signal Layer 2 w0.1: v1(31.725,12) 32.95,12 35.685,14.735 38.38,14.735 38.93,15.285 41.595,15.285 42.325,14.555 42.325,13.4 42.645,13.08 43.392,13.08 43.977,13.665 44.673,13.665 45.258,13.08 46.303,13.08 47.417,11.966 48.626,11.966 49.1,12.439 49.1,14.79 49.595,15.285 50.745,15.285 51.29,14.74 51.29,13.025 51.66,12.655 55.887,12.655 56.576,11.966 57.673,11.966 58.34,12.633 58.34,13.473 59.645,14.778 59.645,17.503 59.225,17.923 59.225,25.35 61.14,27.265 v1(62.655,27.265)
ETH_NRST: R300.2 U13.AC2 U18.12 | length 39.1
  Top Layer w0.1: U18.12@31.75,21.35 v1(32.425,21.35) 32.425,20 R300.2@32.5,19.925 ; U13.AC2@55.58,25.69 56.61,25.69 v1(56.75,25.55)
  Signal Layer 2 w0.1: v1(32.425,21.35) 35.9,17.875 36.48,17.875 37.28,17.075 37.885,17.075 39.01,18.2 44.275,18.2 44.65,18.575 45.325,18.575 46.325,17.575 48.835,17.575 49.275,18.015 49.54,18.015 50.025,18.5 52.657,18.5 53.767,17.39 54.935,17.39 56.252,18.707 56.252,19.233 57.525,20.506 57.525,22.775 56.75,23.55 v1(56.75,25.55)
ETH_RX_CLK: R50.2 R58.1 U13.AA4 | length 69.5
  Top Layer w0.1: U13.AA4@54.58,26.69 v2(54.83,26.44)
  Top Layer w0.13: R58.1@28.875,28.7 R50.2@28.875,29.5 v1(29.65,29.5)
  Signal Layer 1 w0.1: v2(54.83,26.44) 55.188,26.082 55.188,25.605 56.096,24.696 56.43,24.696
  Signal Layer 1 w0.13: 56.43,24.696 57.029,24.696 60.275,21.45 60.275,18.55 59.665,17.94 58.005,17.94 v1(57.055,16.99)
  Signal Layer 2 w0.13: v1(32.59,16.15) 32.84,15.9 37.911,15.9 38.806,16.795 43.28,16.795 43.415,16.66 43.415,15.496 43.831,15.08 44.405,15.08 44.548,15.223 44.548,16.473 44.7,16.625 45.225,16.625 45.34,16.51 45.34,15.21 45.47,15.08 46.68,15.08 46.825,15.225 46.825,15.95 46.825,16.638 46.82,16.643 46.927,16.75 47.9,16.75 48.075,16.575 48.075,15.975 48.239,15.811 48.487,15.811 49.881,17.205 51.82,17.205 52.015,17.01 52.015,16.295 52.375,15.934 52.375,15.9 52.445,15.83 52.445,14 52.635,13.81 53.024,13.81 53.584,14.37 54.623,14.37 54.89,14.637 54.89,16.302 55.118,16.53 55.125,16.537 55.653,16.537 56.05,16.14 56.36,16.14 57.055,16.835 v1(57.055,16.99)
  Bottom Layer w0.13: v1(29.65,29.5) 32.2,26.95 32.2,25.875 31.45,25.125 31.45,22.941 32.85,21.541 32.85,19.775 32.59,19.515 v1(32.59,16.15)
ETH_RX_DV: R51.2 R59.1 U13.AB8 | length 67.7
  Top Layer w0.09: 55.33,28.44 v2(55.955,28.44)
  Top Layer w0.1: U13.AB8@55.08,28.69 55.33,28.44
  Top Layer w0.13: R59.1@30.575,28.7 R51.2@30.575,29.5 v1(31.35,29.5) ; v1(58.731,28.365) v1@58.731,28.439
  Signal Layer 1 w0.1: v2@55.955,28.415 56.855,27.515 57.855,27.515 59.03,26.34 59.38,26.34 59.655,26.615 59.655,27.098 59.055,27.698 59.055,27.99 v1@58.68,28.365
  Bottom Layer w0.1: v1(31.35,29.5) 31.35,28.33 32.575,27.105 32.575,26.87 32.575,25.72 31.825,24.97 31.825,23.097 33.8,21.122 33.8,17.97 34.22,17.55 35.48,17.55 35.895,17.965 35.895,18.634 36.59,19.329 36.59,20.984 37.656,22.05 39.3,22.05 39.585,21.765 39.775,21.765 40.855,20.685 46.751,20.685 48.425,19.011 48.425,17.2 48.665,16.96 49.843,16.96 50.293,17.41 50.865,17.41 51.3,17.845 51.3,17.87 52.047,18.617 53.33,18.617 53.55,18.836 54.264,19.55 55.536,19.55 55.651,19.436 56.315,19.436 56.814,19.935 57.392,19.935 57.815,20.358 57.815,21.249 59.62,23.054 59.62,23.299 60.156,23.835 61.876,23.835 62.32,24.279 62.32,25.775 60.845,27.25 59.846,27.25 v1(58.731,28.365)
ETH_RXD0: R52.1 R60.1 U13.AC7 | length 65.6
  Top Layer w0.09: U13.AC7@55.58,28.19 55.774,28.19 55.804,28.16 56.131,28.16 56.161,28.19 56.355,28.19
  Top Layer w0.1: 56.355,28.19 56.78,28.615 v1@57.83,28.615 ; v1(57.831,28.59) v1@57.831,28.639
  Top Layer w0.13: R60.1@32.275,28.7 R52.1@32.275,29.5 v1(33.05,29.5)
  Bottom Layer w0.13: v1(33.05,29.5) 32.125,29.5 31.725,29.1 31.725,28.486 32.95,27.261 32.95,26.55 32.95,25.564 32.2,24.814 32.2,23.252 34.175,21.277 34.175,18.125 34.375,17.925 35.325,17.925 35.52,18.12 35.52,18.83 36.215,19.525 36.215,21.139 37.501,22.425 38.156,22.425 38.495,22.764 38.495,22.77 38.85,23.125 39.925,23.125 40.213,22.837 40.213,21.858 41.01,21.06 42.2,21.06 42.795,21.655 43.295,21.655 43.89,21.06 46.907,21.06 48.8,19.167 48.8,17.58 49.045,17.335 49.688,17.335 50.138,17.785 50.235,17.785 51.442,18.992 53.175,18.992 54.108,19.925 55.29,19.925 55.675,20.31 56.775,20.31 57.44,20.975 57.44,22.504 56.954,22.99 56.388,22.99 56.1,23.278 56.1,23.777 56.533,24.21 60.225,24.21 60.907,24.893 60.907,26.657 60.69,26.875 59.691,26.875 58.791,27.775 58.645,27.775 v1@57.805,28.615
ETH_RXD1: R53.1 R61.1 U13.AB7 | length 69.3
  Top Layer w0.1: U13.AB7@55.08,28.19 55.355,27.915 56.48,27.915 56.83,28.265 57.49,28.265 v1@57.855,27.9
  Top Layer w0.13: R61.1@33.975,28.675 33.975,29.475 v1(34.75,29.475) ; v1@57.831,27.865 v1(57.856,27.89)
  Bottom Layer w0.13: v1(34.75,29.475) 33.577,29.475 33.212,29.11 32.287,29.11 32.115,28.938 32.115,28.647 33.34,27.422 33.34,25.403 32.59,24.653 32.59,23.413 32.828,23.175 33.364,23.175 34.239,24.05 34.604,24.05 35.15,23.504 35.15,23.215 34.114,22.179 34.114,21.889 34.565,21.438 34.565,20.75 34.798,20.517 35.667,20.517 35.825,20.675 35.825,21.301 37.105,22.58 37.105,24.049 36.715,24.439 36.715,24.741 36.928,24.955 37.731,24.955 38.145,24.542 38.145,24.03 38.66,23.515 40.087,23.515 40.602,22.999 40.602,22.019 41.172,21.45 42.038,21.45 42.633,22.045 43.457,22.045 44.052,21.45 47.068,21.45 49.034,19.484 53.116,19.484 53.947,20.315 55.128,20.315 55.623,20.809 55.623,21.574 55.837,21.788 56.912,21.788 57.05,21.926 57.05,22.343 56.793,22.6 54.05,22.6 53.762,22.888 53.762,24.287 54.075,24.6 60.063,24.6 60.517,25.054 60.517,26.075 60.142,26.45 58.979,26.45 58.765,26.664 58.765,26.98 58.255,27.49 v1(57.856,27.89)
ETH_RXD2: R54.2 R62.1 U13.AB6 | length 66.8
  Top Layer w0.1: U13.AB6@55.08,27.69 56.705,27.69 56.905,27.89
  Top Layer w0.13: R62.1@35.675,28.675 35.675,29.475 v1(36.45,29.475)
  Bottom Layer w0.13: v1(36.45,29.475) 35.302,29.475 34.875,29.048 33.773,29.048 33.282,28.557 33.282,28.032 33.73,27.584 33.73,25.241 32.98,24.491 32.98,24.181 33.279,23.881 33.519,23.881 34.077,24.44 34.766,24.44 35.54,23.666 35.54,23.053 34.856,22.369 34.856,21.767 35.173,21.45 35.423,21.45 36.715,22.742 36.715,23.887 36.325,24.277 36.325,24.903 36.767,25.345 37.893,25.345 38.733,24.505 39.781,24.505 39.995,24.291 39.995,24.158 40.992,23.161 40.992,22.181 41.333,21.84 41.877,21.84 42.472,22.435 43.618,22.435 44.213,21.84 47.23,21.84 49.196,19.874 52.954,19.874 53.785,20.705 54.1,20.705 54.45,21.055 54.45,21.67 54.12,22 52.679,22 52.574,22.105 52.195,22.105 51.925,22.375 51.925,22.972 51.513,23.384 50.491,23.384 49.85,24.025 49.85,24.75 50.09,24.99 59.902,24.99 60.127,25.216 60.127,25.913 59.981,26.06 58.817,26.06 58.375,26.502 58.375,26.818 57.303,27.89 v1(57.106,27.89)
ETH_RXD3: R55.1 R63.1 U13.AA7 | length 69.2
  Top Layer w0.1: U13.AA7@54.58,28.19 v2(54.83,27.94)
  Top Layer w0.13: R63.1@37.4,28.675 37.4,29.475 v1(38.175,29.475)
  Signal Layer 1 w0.1: v2(54.83,27.94) 56.38,26.39 v1(57.481,26.39)
  Bottom Layer w0.13: v1(38.175,29.475) 37.002,29.475 36.538,29.011 35.389,29.011 34.85,28.472 34.85,27.75 35.27,27.33 35.681,27.33 35.975,27.036 35.975,26.084 36.324,25.735 38.054,25.735 38.894,24.895 39.943,24.895 40.385,24.453 40.385,24.32 41.88,22.825 43.78,22.825 44.375,22.23 48.005,22.23 48.34,22.565 48.34,22.891 48.554,23.105 49.205,23.105 49.46,23.36 49.46,24.475 48.86,25.075 48.05,25.075 47.805,24.83 45.825,24.83 45.58,25.075 45.58,25.845 43.825,27.6 41.45,27.6 41.2,27.85 41.2,28.825 41.44,29.065 44.41,29.065 47.2,26.275 49.125,26.275 50.02,25.38 54.405,25.38 54.951,25.926 54.951,29.55 54.961,29.559 54.961,30.125 55.192,30.357 55.968,30.357 56.375,29.95 56.375,26.525 57.52,25.38 58.005,25.38 58.375,25.75 58.375,25.95 57.936,26.39 v1(57.481,26.39) ; v1@57.475,26.29 v1@57.475,26.39
ETH_TX_EN: U13.AB1 U18.19 | length 70.8
  Top Layer w0.1: U13.AB1@55.08,25.19 55.38,24.89 58.855,24.89 59.189,25.224 59.48,25.224
  Top Layer w0.13: U18.19@31.75,24.15 35.761,24.15 38.455,21.456 38.455,20.815 38.455,14.305 38.45,14.3 v1(38.45,13.825) ; 59.48,25.224 61.371,25.224 61.425,25.17 v1(61.425,25.15)
  Signal Layer 2 w0.13: v1(38.45,13.825) 38,13.825 37.775,13.6 36.875,13.6 36.605,13.33 36.605,11.798 37.202,11.201 38.299,11.201 39.413,12.315 40.212,12.315 40.79,12.893 40.79,14.257 40.957,14.424 41.374,14.424 41.485,14.313 41.485,12.968 42.138,12.315 45.987,12.315 47.101,11.201 48.943,11.201 49.782,12.04 50.168,12.04 51.007,11.201 57.99,11.201 61.86,15.071 61.86,15.838 61.728,15.97 61.128,15.97 60.555,16.543 60.555,17.807 60.974,18.226 60.974,18.649 60.555,19.068 60.555,19.832 60.936,20.212 60.936,20.736 60.555,21.117 60.555,25.105 61.062,25.612 61.263,25.612 61.425,25.45 v1(61.425,25.15)
ETH_TXD0: U13.AA2 U18.18 | length 75.4
  Top Layer w0.09: U13.AA2@54.58,25.69 U13.AA2@54.58,25.69 54.83,25.442 56.233,25.442
  Top Layer w0.13: U18.18@31.75,23.75 35.53,23.75 36.9,22.38 36.9,18.626 35.575,17.301 35.585,17.291 35.585,11.29 v1(35.9,10.975) ; 56.233,25.442 56.525,25.15 57.35,25.15 57.525,25.325 58.76,25.325 59.048,25.614 62.225,25.614 63.127,26.515 v1(63.18,26.515)
  Signal Layer 2 w0.13: v1(35.9,10.975) 36.877,10.975 37.041,10.811 38.461,10.811 39.575,11.925 45.825,11.925 46.939,10.811 58.151,10.811 62.25,14.91 62.25,16 61.89,16.36 61.29,16.36 60.945,16.705 60.945,17.645 61.287,17.987 62.4,17.987 62.625,18.212 62.625,18.7 62.35,18.975 61.2,18.975 60.945,19.23 60.945,19.67 61.2,19.925 62.45,19.925 62.625,20.1 62.625,20.6 62.335,20.89 61.333,20.89 60.945,21.278 60.945,24.141 61.494,24.69 62.003,24.69 63.18,25.867 v1(63.18,26.515)
ETH_TXD1: U13.AA1 U18.17 | length 76.3
  Top Layer w0.1: U13.AA1@54.58,25.19 54.905,24.865 55.08,24.865 55.305,24.64 59.13,24.64 59.324,24.834 59.455,24.834
  Top Layer w0.13: U18.17@31.75,23.35 35.378,23.35 36.51,22.218 36.51,18.922 35.185,17.597 35.185,10.465 v1(35.375,10.275) ; 59.455,24.834 60.884,24.834 61.503,24.215 v1(61.68,24.215)
  Signal Layer 2 w0.13: v1(35.375,10.275) 35.665,10.565 36.576,10.565 36.72,10.421 58.313,10.421 64.92,17.028 64.92,17.63 64.625,17.925 64.075,17.925 63.575,18.425 63.575,19.4 64.015,19.84 64.613,19.84 64.92,20.147 64.92,20.83 64.47,21.28 61.495,21.28 61.335,21.44 61.335,22.01 61.548,22.223 64.373,22.223 64.65,22.5 64.65,22.977 64.352,23.275 61.575,23.275 61.335,23.515 61.335,23.87 v1(61.68,24.215)
  Signal Layer 2 w0.25: v1@61.68,24.24 v1@61.705,24.215
ETH_TXD2: U13.Y2 U18.16 | length 76.1
  Top Layer w0.09: U13.Y2@54.08,25.69 54.33,25.44 54.33,25.065 54.78,24.615 54.88,24.615
  Top Layer w0.1: 54.88,24.615 55.005,24.615 55.205,24.415 59.455,24.415 59.484,24.444
  Top Layer w0.13: U18.16@31.75,22.95 35.227,22.95 36.12,22.057 36.12,19.083 34.75,17.713 v1(34.75,10.115) ; 59.484,24.444 60.722,24.444 61.461,23.705 62.049,23.705 62.195,23.851 62.195,25.032 63.103,25.94 v1(63.805,25.94)
  Signal Layer 2 w0.13: v1(34.75,10.115) 35.45,9.415 37.915,9.415 38.531,10.031 58.474,10.031 65.31,16.867 65.31,17.792 64.787,18.315 64.237,18.315 63.965,18.587 63.965,19.238 64.177,19.45 64.775,19.45 65.31,19.985 65.31,22.869 64.339,23.84 63.635,23.84 63.05,24.425 63.05,25.185 v1(63.805,25.94)
ETH_TXD3: U13.Y1 U18.15 | length 78
  Top Layer w0.1: U13.Y1@54.08,25.19 54.08,24.99 54.68,24.39 54.88,24.39 55.08,24.19 59.207,24.19 59.344,24.054
  Top Layer w0.13: U18.15@31.75,22.55 35.075,22.55 35.73,21.895 35.73,19.245 34.36,17.875 34.36,15.31 33.625,14.575 32.7,14.575 32.125,14 v1(32.125,10.775) ; 59.344,24.054 60.561,24.054 61.3,23.315 62.21,23.315 62.585,23.69 62.585,24.871 63.13,25.415 v1(64.405,25.415)
  Signal Layer 2 w0.13: v1(32.125,10.775) 33.875,9.025 39.225,9.025 39.775,9.575 49.975,9.575 50.425,9.125 58.12,9.125 66.45,17.455 66.45,18.275 65.6,19.125 65.6,19.723 65.7,19.823 65.7,23.03 65.6,23.13 65.6,24.22 v1(64.405,25.415)
EXP_GPIO4: CN2.7 TP19.1 U13.A13 | length 46.2
  Top Layer w0.1: v1(40.33,30.84) 40.355,30.865 41.205,30.865 TP19.1@41.23,30.89 41.555,30.565 42.41,30.565 43.035,31.19 U13.A13@44.58,31.19
  Signal Layer 3 w0.1: CN2.7@34.99,66.23 36.295,64.925 37.485,64.925 37.8,64.61 37.8,61.592 36.983,60.775 36.972,60.775 36.379,60.182 36.379,60.075 34.4,58.096 34.4,54.567 34.175,54.342 34.175,49.695 33.85,49.37 33.85,48.98 34.2,48.63 34.2,48.2 35.58,46.82 35.58,35.59 v1(40.33,30.84)
EXP_GPIO5: CN2.29 TP1.1 U13.V2 | length 74.6
  Top Layer w0.09: U13.V2@53.08,25.69 53.08,25.094 54.424,23.75 54.608,23.75
  Top Layer w0.1: 54.608,23.75 54.783,23.575 58.726,23.575 59.023,23.279 60.24,23.279 60.979,22.54 62.531,22.54 64.13,24.139 v1(64.13,24.44) ; TP1.1@62.925,62.925 62.925,66.225 CN2.29@62.93,66.23
  Signal Layer 2 w0.1: CN2.29@62.93,66.23 64.105,65.055 68.74,65.055 v1(68.963,65.277)
  Signal Layer 3 w0.1: v1(64.13,24.44) 64.355,24.44 66.75,26.835 66.75,32.729 67.505,33.484 67.505,33.99 71.93,38.415 71.93,47.991 68.056,51.865 65.167,51.865 64.3,52.732 64.3,57.25 68.025,60.975 68.025,64.34 v1(68.963,65.277)
EXP_GPIO6: CN2.31 U13.C4 | length 97.1
  Top Layer w0.1: v1(36.78,26.34) 36.805,26.315 37.019,26.315 37.393,25.941 38.252,25.941 38.829,25.365 39.781,25.365 39.931,25.515 41.78,25.515 v4(42.13,25.865) ; v2(45.33,26.94) U13.C4@45.58,26.69
  Signal Layer 1 w0.1: v4(42.13,25.865) 42.13,26.29 43.03,27.19 45.08,27.19 v2(45.33,26.94)
  Signal Layer 2 w0.1: v1(31.5,69.95) 31.7,70.15 32.942,70.15 33.442,69.65 34.208,69.65 34.508,69.95 63.7,69.95 64.25,69.4 64.25,67.45 CN2.31@65.47,66.23
  Signal Layer 3 w0.1: v1(31.5,69.95) 31.205,69.655 31.205,61.637 30.425,60.857 30.425,53.547 31.422,52.55 31.422,49.247 29.55,47.375 29.55,44.756 30.281,44.025 30.285,44.025 30.9,43.41 30.9,41.141 30.53,40.771 30.53,39.734 31.604,38.659 31.604,36.283 31.325,36.003 31.325,32.757 32.417,31.666 33.396,31.666 34.15,30.912 34.15,29.297 36.055,27.392 36.055,26.69 36.405,26.34 v1(36.78,26.34)
EXP_GPIO7: CN2.26 U13.U1 | length 80.5
  Top Layer w0.1: U13.U1@52.58,25.19 52.58,25.049 54.279,23.35 54.442,23.35 54.617,23.175 58.561,23.175 58.857,22.879 60.074,22.879 60.813,22.14 62.697,22.14 64.297,23.74 v1(65.105,23.74) ; v1@69.215,67.405 v1(69.28,67.34)
  Signal Layer 3 w0.1: v1(65.105,23.74) 65.105,24.907 66.95,26.752 66.95,31.81 67.905,32.765 67.905,34.107 72.13,38.332 72.13,48.074 68.139,52.065 65.249,52.065 64.5,52.814 64.5,56.425 69.255,61.18 69.255,64.395 69.18,64.47 69.18,64.76 69.313,64.892 69.313,67.307 v1(69.28,67.34)
  Bottom Layer w0.1: CN2.26@57.85,68.77 59.095,67.525 60.875,67.525 61.07,67.72 61.07,67.74 61.38,68.05 61.878,68.05 62.353,67.575 69.045,67.575 v1(69.28,67.34)
EXP_GPIO8: CN2.24 U13.AA13 | length 54
  Top Layer w0.1: v2(54.33,30.94) U13.AA13@54.58,31.19 ; v4(61.055,30.915) 61.269,30.915 61.93,31.576 61.93,32.054 64.18,34.304 64.18,35.79 v1(64.68,36.29)
  Signal Layer 1 w0.1: v2(54.33,30.94) 54.63,30.64 60.78,30.64 v4(61.055,30.915)
  Signal Layer 3 w0.1: CN2.24@55.31,68.77 54.05,67.51 54.05,65.35 54.95,64.45 55.425,64.45 55.98,63.895 55.98,63.43 55.63,63.08 55.63,62.072 55.98,61.722 55.98,58.979 56.58,58.379 56.58,49.029 59.86,45.749 59.86,38.235 61.355,36.74 63.834,36.74 64.284,36.29 v1(64.68,36.29)
EXP_GPIO9: CN2.21 U13.AC11 | length 54.7
  Top Layer w0.1: CN2.21@52.77,66.23 54.3,64.7 55.647,64.7 v1(56.856,63.492) v1@56.829,63.465 ; U13.AC11@55.58,30.19 58.271,30.19 58.726,29.735 61.464,29.735 61.806,30.076 61.806,30.603 62.53,31.328 62.53,31.806 64.78,34.056 64.78,35.329 65.63,36.179 65.63,36.34 v1(65.581,36.291)
  Signal Layer 3 w0.1: v1(56.856,63.492) 56.855,62.835 56.43,62.41 56.43,62.12 56.58,61.97 56.58,59.228 57.18,58.628 57.18,49.278 58.088,48.37 58.821,48.37 60.46,46.731 60.46,38.484 61.604,37.34 64.329,37.34 65.014,38.025 65.386,38.025 65.755,37.656 65.755,36.465 v1(65.581,36.291)
EXP_GPIO10: CN2.19 U13.AA14 | length 55.3
  Top Layer w0.09: U13.AA14@54.58,31.69 54.83,31.44 55.205,31.44 55.33,31.315 55.33,31.04 55.43,30.94 55.98,30.94
  Top Layer w0.1: CN2.19@50.23,66.23 50.23,66.125 52.005,64.35 55.43,64.35 55.981,63.799 v1(55.981,62.856) ; 55.98,30.94 57.405,30.94 57.555,30.79 58.519,30.79 58.974,30.335 60.972,30.335 62.13,31.493 62.13,31.971 64.38,34.221 64.38,35.495 65.03,36.145 65.03,36.59 v1(64.78,36.84)
  Signal Layer 3 w0.1: v1(55.981,62.856) 55.98,62.004 56.18,61.804 56.18,59.062 56.78,58.462 56.78,49.112 57.922,47.97 58.655,47.97 58.86,47.765 58.86,47.032 60.06,45.832 60.06,38.318 61.438,36.94 63.917,36.94 64.136,36.721 64.661,36.721 v1(64.78,36.84)
EXP_GPIO11: CN2.23 U13.AB12 | length 51.1
  Top Layer w0.1: U13.AB12@55.08,30.69 57.372,30.69 57.472,30.59 58.437,30.59 58.892,30.135 61.055,30.135 62.33,31.41 62.33,31.889 64.58,34.139 64.58,35.412 65.23,36.062 65.23,36.64 v1(65.405,36.815)
  Signal Layer 3 w0.1: CN2.23@55.31,66.23 56.505,65.035 56.505,62.83 56.23,62.555 56.23,62.037 56.38,61.887 56.38,59.145 56.98,58.545 56.98,49.195 58.005,48.17 58.738,48.17 59.06,47.848 59.06,47.115 60.26,45.915 60.26,38.401 61.521,37.14 64.505,37.14 64.555,37.19 64.949,37.19 65.324,36.815 v1(65.405,36.815)
EXP_GPIO12: CN2.32 U13.AA19 | length 53.7
  Top Layer w0.09: U13.AA19@54.58,34.19 54.83,34.44 55.705,34.44
  Top Layer w0.1: 55.705,34.44 56.08,34.44 v4(56.505,34.865)
  Signal Layer 1 w0.1: v4(56.505,34.865) 56.68,35.04 57.345,35.04 57.348,35.037 57.469,35.037 58.53,36.098 58.53,36.738 59.832,38.04 60.288,38.04 60.428,37.9 62.615,37.9 v1(63.03,38.315)
  Signal Layer 2 w0.1: v1(57.325,62.675) 58.2,63.55 61.23,63.55 61.63,63.95 62.242,63.95 63.267,62.925 v1(64.375,62.925)
  Signal Layer 3 w0.1: v1(57.325,62.675) 57.325,60.07 57.78,59.615 57.78,49.526 58.336,48.97 59.069,48.97 59.839,48.2 61.02,48.2 61.8,47.42 61.8,46.46 61.06,45.72 61.06,39.909 62.654,38.315 v1(63.03,38.315) ; v1(64.375,62.925) 64.295,63.005 64.295,67.595 CN2.32@65.47,68.77
EXP_GPIO13: CN2.33 U13.B11 | length 70
  Top Layer w0.1: v1(40.605,30.365) 40.655,30.365 40.805,30.215 43.655,30.215 43.93,30.49 44.78,30.49 U13.B11@45.08,30.19
  Signal Layer 2 w0.1: v1(40.605,30.365) 41.615,31.375 46.215,31.375 47.455,32.615 52.765,32.615 53.5,33.35 54.525,33.35 57.55,36.375 60.55,36.375 61.125,36.95 63.3,36.95 64.375,38.025 67.325,38.025 68.45,36.9 v1(68.95,36.9)
  Signal Layer 3 w0.1: CN2.33@68.01,66.23 68.01,64.7 67.68,64.37 67.68,60.932 64.1,57.352 64.1,52.195 64.03,52.125 64.03,46.945 65.3,45.675 65.3,41.325 68.25,38.375 68.25,37.225 68.575,36.9 v1(68.95,36.9)
EXP_GPIO14: CN2.8 U13.Y3 | length 88.6
  Top Layer w0.1: CN2.8@34.99,68.77 36.2,67.56 36.2,65.9 36.355,65.745 36.355,65.743 37.048,65.05 42.7,65.05 45.06,62.69 v1(54.305,62.69) ; U13.Y3@54.08,26.19 v2(54.33,25.94)
  Signal Layer 1 w0.1: v2(54.33,25.94) 54.33,25.897 57.487,22.74 57.589,22.74 59.13,21.199 59.13,19.86 57.385,18.115 56.885,18.115 56.68,17.91 56.68,17.655 55.815,16.79 54.305,16.79 v1(54.355,16.84)
  Signal Layer 2 w0.1: v1(54.355,16.84) v1@54.405,16.84
  Signal Layer 3 w0.1: v1(54.305,62.69) 54.305,61.982 54.98,61.307 54.98,58.565 55.58,57.965 55.58,48.615 58.86,45.335 58.86,37.068 58.63,36.838 58.63,35.69 59.18,35.14 59.18,33.666 55.055,29.541 55.055,23.015 54.38,22.34 54.38,20.75 54.905,20.225 54.905,18.77 55.2,18.475 55.2,17.275 54.765,16.84 v1(54.355,16.84)
EXP_GPIO15: CN2.10 U13.AC5 | length 78.6
  Top Layer w0.1: U13.AC5@55.58,27.19 56.937,27.19 57.087,27.34 58.282,27.34 58.706,27.765 59.554,27.765 60.14,27.179 60.937,27.179 61.48,27.721 61.48,28.015 v1(61.562,28.015)
  Signal Layer 2 w0.1: CN2.10@37.53,68.77 38.85,67.45 38.995,67.595 61.52,67.595 v1(61.575,67.65)
  Signal Layer 3 w0.1: v1(61.562,28.015) 61.691,28.015 61.955,28.279 61.955,31.023 64.73,33.798 64.73,34.379 66.38,36.029 66.38,36.337 67.425,37.382 67.425,37.845 66.405,38.865 64,38.865 61.46,41.405 61.46,45.554 62.2,46.294 62.2,48.344 61.155,49.389 61.155,51.909 61.15,51.914 61.15,64.415 61.575,64.84 v1(61.575,67.65)
EXP_GPIO16: CN2.36 U13.AA10 | length 66.9
  Top Layer w0.09: U13.AA10@54.58,29.69 54.83,29.44 56.03,29.44
  Top Layer w0.1: 56.03,29.44 58.172,29.44 58.477,29.135 59.469,29.135 59.889,28.715 60.536,28.715 60.686,28.565 61.675,28.565 62.206,29.096 62.206,30.438 62.93,31.162 62.93,31.64 65.18,33.89 65.18,35.112 66.131,36.063 66.131,36.371 66.575,36.815 v1(67.405,36.815)
  Signal Layer 2 w0.1: v1(61.775,63.6) 62.825,62.55 v1(71.75,62.55)
  Signal Layer 3 w0.1: v1(61.775,63.6) 61.35,63.175 61.35,53.07 62.4,52.02 62.4,46.211 61.66,45.471 61.66,42.535 63.82,40.375 65.178,40.375 67.625,37.928 67.625,37.035 v1(67.405,36.815) ; CN2.36@70.55,68.77 71.75,67.57 v1(71.75,62.55)
EXP_GPIO17: CN2.11 U13.AB9 | length 74.7
  Top Layer w0.1: CN2.11@40.07,66.23 41.315,67.475 61,67.475 61.725,66.75 61.725,65.525 v1(62.075,65.175) ; U13.AB9@55.08,29.19 58.139,29.19 58.394,28.935 59.386,28.935 59.806,28.515 60.453,28.515 60.603,28.365 61.758,28.365 62.406,29.013 62.406,30.355 63.13,31.079 63.13,31.557 65.38,33.807 65.38,35.029 66.691,36.34 66.906,36.34 v1(66.956,36.391)
  Signal Layer 3 w0.1: v1@62.125,65.1 62.68,64.545 62.68,53.17 63.38,52.47 63.38,51.065 62.6,50.285 62.6,41.878 63.903,40.575 65.261,40.575 67.825,38.011 67.825,36.74 67.55,36.465 67.028,36.465 v1(66.956,36.391) v1(66.956,36.391)
EXP_GPIO18: CN2.12 SB14.1 | length 57.8
  Signal Layer 3 w0.1: CN2.12@40.07,68.77 38.8,67.5 38.8,65.525 38.1,64.825 38.1,61.575 37.1,60.575 37.055,60.575 36.579,60.099 36.579,58.316 37.125,57.77 37.125,57.35 36.925,57.15 35.883,57.15 35.6,56.867 35.6,53.598 35.3,53.298 35.3,50 35.98,49.32 35.98,35.756 39.696,32.04 40.15,32.04 40.38,31.81 40.38,31.39 41.83,29.94 41.83,19.785 v1(41.875,19.74)
  Bottom Layer w0.1: v1@41.875,19.8 v1(41.875,19.74) 41.875,17.8 42.075,17.6 SB14.1@42.525,17.6
EXP_GPIO19: CN2.35 SB16.1 | length 114.1
  Signal Layer 2 w0.1: v1(25.725,69.95) 26.605,69.95 26.8,70.145 27.94,70.145 28.135,69.95 29.1,69.95 29.5,70.35 33.025,70.35 33.525,69.85 34.125,69.85 34.425,70.15 68.85,70.15 69.325,69.675 69.325,68.09 69.865,67.55 70.375,67.55 70.55,67.375 CN2.35@70.55,66.23
  Signal Layer 3 w0.1: v1(25.725,69.95) 25.725,69.2 25.975,68.95 25.975,63.175 25.625,62.825 25.625,60.575 25.15,60.1 24.889,60.1 24.5,59.711 24.5,57.811 25.025,57.286 25.025,56.914 24.761,56.65 24.711,56.65 23.5,55.439 23.5,47.191 27.1,43.591 27.1,40.35 25.55,38.8 25.55,37.47 25.675,37.345 25.675,27.928 28.853,24.75 31.307,24.75 35.317,20.74 v1(37.35,20.74)
  Bottom Layer w0.1: v1(37.35,20.74) 37.765,20.325 38.212,20.325 38.83,19.707 38.83,17.802 39.032,17.6 SB16.1@39.725,17.6
EXP_GPIO20: CN2.38 SB15.1 | length 114.7
  Signal Layer 2 w0.1: v1(28.735,70.31) 28.975,70.55 71.31,70.55 CN2.38@73.09,68.77
  Signal Layer 3 w0.1: v1(28.735,70.31) 28.735,67.81 28.33,67.405 26.883,67.405 26.195,66.717 26.195,62.105 27.15,61.15 27.15,58.556 26.769,58.175 26.569,58.175 23.7,55.306 23.7,47.3 27.5,43.5 27.5,40.184 26.7,39.384 26.7,37.742 26.075,37.117 26.075,33.27 26.93,32.415 26.93,31.474 26.075,30.619 26.075,28.145 29.055,25.165 31.458,25.165 35.333,21.29 37.61,21.29 38.08,20.82 38.075,20.815 v1(38.075,20.675)
  Bottom Layer w0.1: v1(38.075,20.675) 38.425,20.675 39.025,20.075 40.05,20.075 40.475,19.65 40.475,17.8 40.675,17.6 SB15.1@41.125,17.6
EXP_GPIO21: CN2.40 SB13.1 | length 108
  Signal Layer 2 w0.1: v1(47.625,59.85) 47.925,59.85 49.34,61.265 57.217,61.265 58.152,62.2 v1(74.325,62.2)
  Signal Layer 3 w0.1: v1(47.45,15.85) 47.45,24.525 48.25,25.325 50.556,25.325 58.98,33.749 58.98,35.057 57.95,36.087 57.95,45.5 55.075,48.375 55.075,52.8 54.155,53.72 54.155,56.231 52.75,57.636 52.75,60.85 52.4,61.2 48.975,61.2 v1(47.625,59.85) ; v1(74.325,62.2) 74.325,67.465 CN2.40@75.63,68.77
  Bottom Layer w0.1: v1(38.055,19.959) 38.136,19.959 38.63,19.465 38.63,17.04 39.105,16.565 43.08,16.565 43.945,17.43 ; 43.98,17.89 43.98,17.465 43.945,17.43 ; v1(47.45,15.85) 45.5,15.85 43.945,17.405 43.945,17.43
EXP_GPIO22: CN2.15 U13.B7 | length 62.1
  Top Layer w0.1: v1(39.305,26.515) 39.38,26.515 41.225,26.515 42.273,27.563 42.532,27.563 42.885,27.915 44.805,27.915 U13.B7@45.08,28.19
  Signal Layer 2 w0.1: v1(33.38,63.54) 34.305,64.465 35.092,64.465 35.147,64.41 35.603,64.41 35.753,64.56 43.48,64.56 CN2.15@45.15,66.23
  Signal Layer 3 w0.1: v1(33.38,63.54) 33.6,63.32 33.6,60.55 32.075,59.025 32.075,53.028 32.222,52.881 32.222,48.603 32.45,48.375 32.45,46.566 32.447,46.563 32.447,41.894 32.45,41.891 32.45,41.56 31.33,40.44 31.33,40.065 32.404,38.991 32.404,37.321 32.705,37.02 32.705,35.539 32.53,35.364 32.53,33.398 33.262,32.666 34.146,32.666 35.85,30.962 35.85,29.297 38.632,26.515 v1(39.305,26.515)
EXP_GPIO23: CN2.16 U13.A5 | length 66.3
  Top Layer w0.1: v1(36.605,27.29) 36.68,27.365 36.955,27.09 36.955,26.945 37.559,26.341 38.418,26.341 38.994,25.765 39.616,25.765 39.766,25.915 41.474,25.915 42.521,26.963 42.781,26.963 43.008,27.19 U13.A5@44.58,27.19
  Signal Layer 2 w0.1: v1@32.805,63.62 v1(32.805,63.64) 33.58,64.415 33.972,64.415 34.222,64.665 35.175,64.665 35.23,64.61 35.52,64.61 35.67,64.76 42.91,64.76 v1(43.95,65.8)
  Signal Layer 3 w0.1: v1(32.805,63.64) 32.805,62.554 31.601,61.35 31.589,61.35 31,60.761 31,57.958 31.675,57.283 31.675,52.862 31.822,52.716 31.822,48.322 32.047,48.096 32.047,41.728 32.05,41.726 30.93,40.606 30.93,39.899 32.004,38.825 32.004,36.117 31.725,35.838 31.725,32.923 32.582,32.066 33.898,32.066 35.25,30.714 35.25,28.763 36.605,27.408 v1(36.605,27.29) ; v1(43.95,65.8) 43.95,67.57 CN2.16@45.15,68.77
EXP_GPIO24: CN2.18 U13.D8 | length 65.5
  Top Layer w0.1: v1(38.605,28.715) 38.735,28.715 39.735,27.715 40.025,27.715 40.375,28.065 40.83,28.065 v4(41.305,28.54) ; U13.D8@46.08,28.69 v2(46.33,28.94)
  Signal Layer 1 w0.1: v4(41.305,28.54) 41.63,28.865 43.396,28.865 43.771,29.24 46.03,29.24 v2(46.33,28.94)
  Signal Layer 2 w0.1: v1(34.255,63.915) 34.605,64.265 35,64.265 35.055,64.21 35.686,64.21 35.836,64.36 45.485,64.36 v1(46.425,65.3)
  Signal Layer 3 w0.1: v1(34.255,63.915) 34.205,63.915 34.555,63.565 34.947,63.565 35.155,63.357 35.155,63.02 34.95,62.815 34.947,62.815 34.2,62.068 34.2,60.245 34.186,60.245 33.55,59.609 33.55,55.017 33.375,54.842 33.375,50.026 33.05,49.701 33.05,48.649 33.4,48.299 33.4,46.667 33.25,46.517 33.25,40.667 33.705,40.212 33.705,34.964 37.575,31.094 37.575,29.297 37.982,28.89 38.43,28.89 v1(38.605,28.715) ; v1(46.425,65.3) 46.425,67.505 CN2.18@47.69,68.77
EXP_GPIO25: CN2.22 U13.D9 | length 68.8
  Top Layer w0.1: U13.D9@46.08,29.19 v2(46.33,29.44)
  Signal Layer 1 w0.1: v1(39.88,28.065) 40.18,28.065 41.18,29.065 43.313,29.065 43.688,29.44 v2(46.33,29.44)
  Signal Layer 2 w0.1: v1(34.855,63.915) 35.808,63.915 36.053,64.16 47.71,64.16 48.605,65.055 51.155,65.055 v1(51.475,65.375)
  Signal Layer 3 w0.1: v1(34.855,63.915) 34.855,63.94 35.355,63.44 35.355,62.937 35.033,62.615 35.03,62.615 34.4,61.985 34.4,60.1 33.75,59.45 33.75,54.934 33.575,54.759 33.575,49.943 33.25,49.618 33.25,48.732 33.6,48.382 33.6,46.584 33.45,46.434 33.45,40.75 33.905,40.295 33.905,35.046 37.775,31.176 37.775,29.38 38.065,29.09 38.855,29.09 v1(39.88,28.065) ; v1(51.475,65.375) 51.475,67.475 CN2.22@52.77,68.77
EXP_GPIO26: CN2.37 U13.D7 | length 96.6
  Top Layer w0.09: v2(45.33,28.44) 45.83,28.44 U13.D7@46.08,28.19
  Top Layer w0.1: v1(38.08,28.215) 38.105,28.215 38.473,27.847 39.037,27.847 39.569,27.315 40.21,27.315 40.41,27.115 40.977,27.115 42.101,28.24 v4(42.255,28.24)
  Signal Layer 1 w0.1: v4(42.255,28.24) 43.336,28.24 43.761,28.665 45.105,28.665 v2(45.33,28.44)
  Signal Layer 2 w0.1: v1(33.8,70.2) 33.821,70.179 34.171,70.179 34.343,70.35 70.95,70.35 71.875,69.425 71.875,67.445 CN2.37@73.09,66.23
  Signal Layer 3 w0.1: v1(33.8,70.2) 33.8,60.425 32.275,58.9 32.275,53.111 32.422,52.964 32.422,48.728 32.65,48.5 32.65,40.701 33.305,40.046 33.305,34.798 37.175,30.928 37.175,29.12 v1(38.08,28.215)
EXP_GPIO27: CN2.13 U13.D10 | length 56.6
  Top Layer w0.1: U13.D10@46.08,29.69 v2(46.33,29.94)
  Signal Layer 1 w0.1: v1(39.93,29.89) 39.905,29.915 40.235,29.915 40.885,29.265 43.23,29.265 43.63,29.665 46.055,29.665 v2(46.33,29.94)
  Signal Layer 2 w0.1: v1(35.375,64.96) 41.34,64.96 CN2.13@42.61,66.23
  Signal Layer 3 w0.1: v1(35.375,64.96) 35.94,64.96 36.2,64.7 37.41,64.7 37.6,64.51 37.6,61.675 37.589,61.675 34.15,58.236 34.15,54.6 33.975,54.425 33.975,49.778 33.65,49.453 33.65,48.897 34,48.547 34,46.923 34.505,46.418 34.505,45.67 34.68,45.495 34.68,43.4 34.43,43.15 34.43,41.465 34.98,40.915 34.98,35.342 39.564,30.758 39.564,30.256 v1(39.93,29.89)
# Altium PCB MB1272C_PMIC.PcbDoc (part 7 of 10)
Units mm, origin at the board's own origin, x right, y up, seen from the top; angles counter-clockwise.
Board outline 101 x 71 mm, 6 copper layers (Top Layer, Signal Layer 1, Signal Layer 2, Signal Layer 3, Signal Layer 4, Bottom Layer), stack 1.552 mm thick; 518 components, 478 nets, 2152 pads, 1871 vias.
Unrouted connection lines stored in the file: 3.

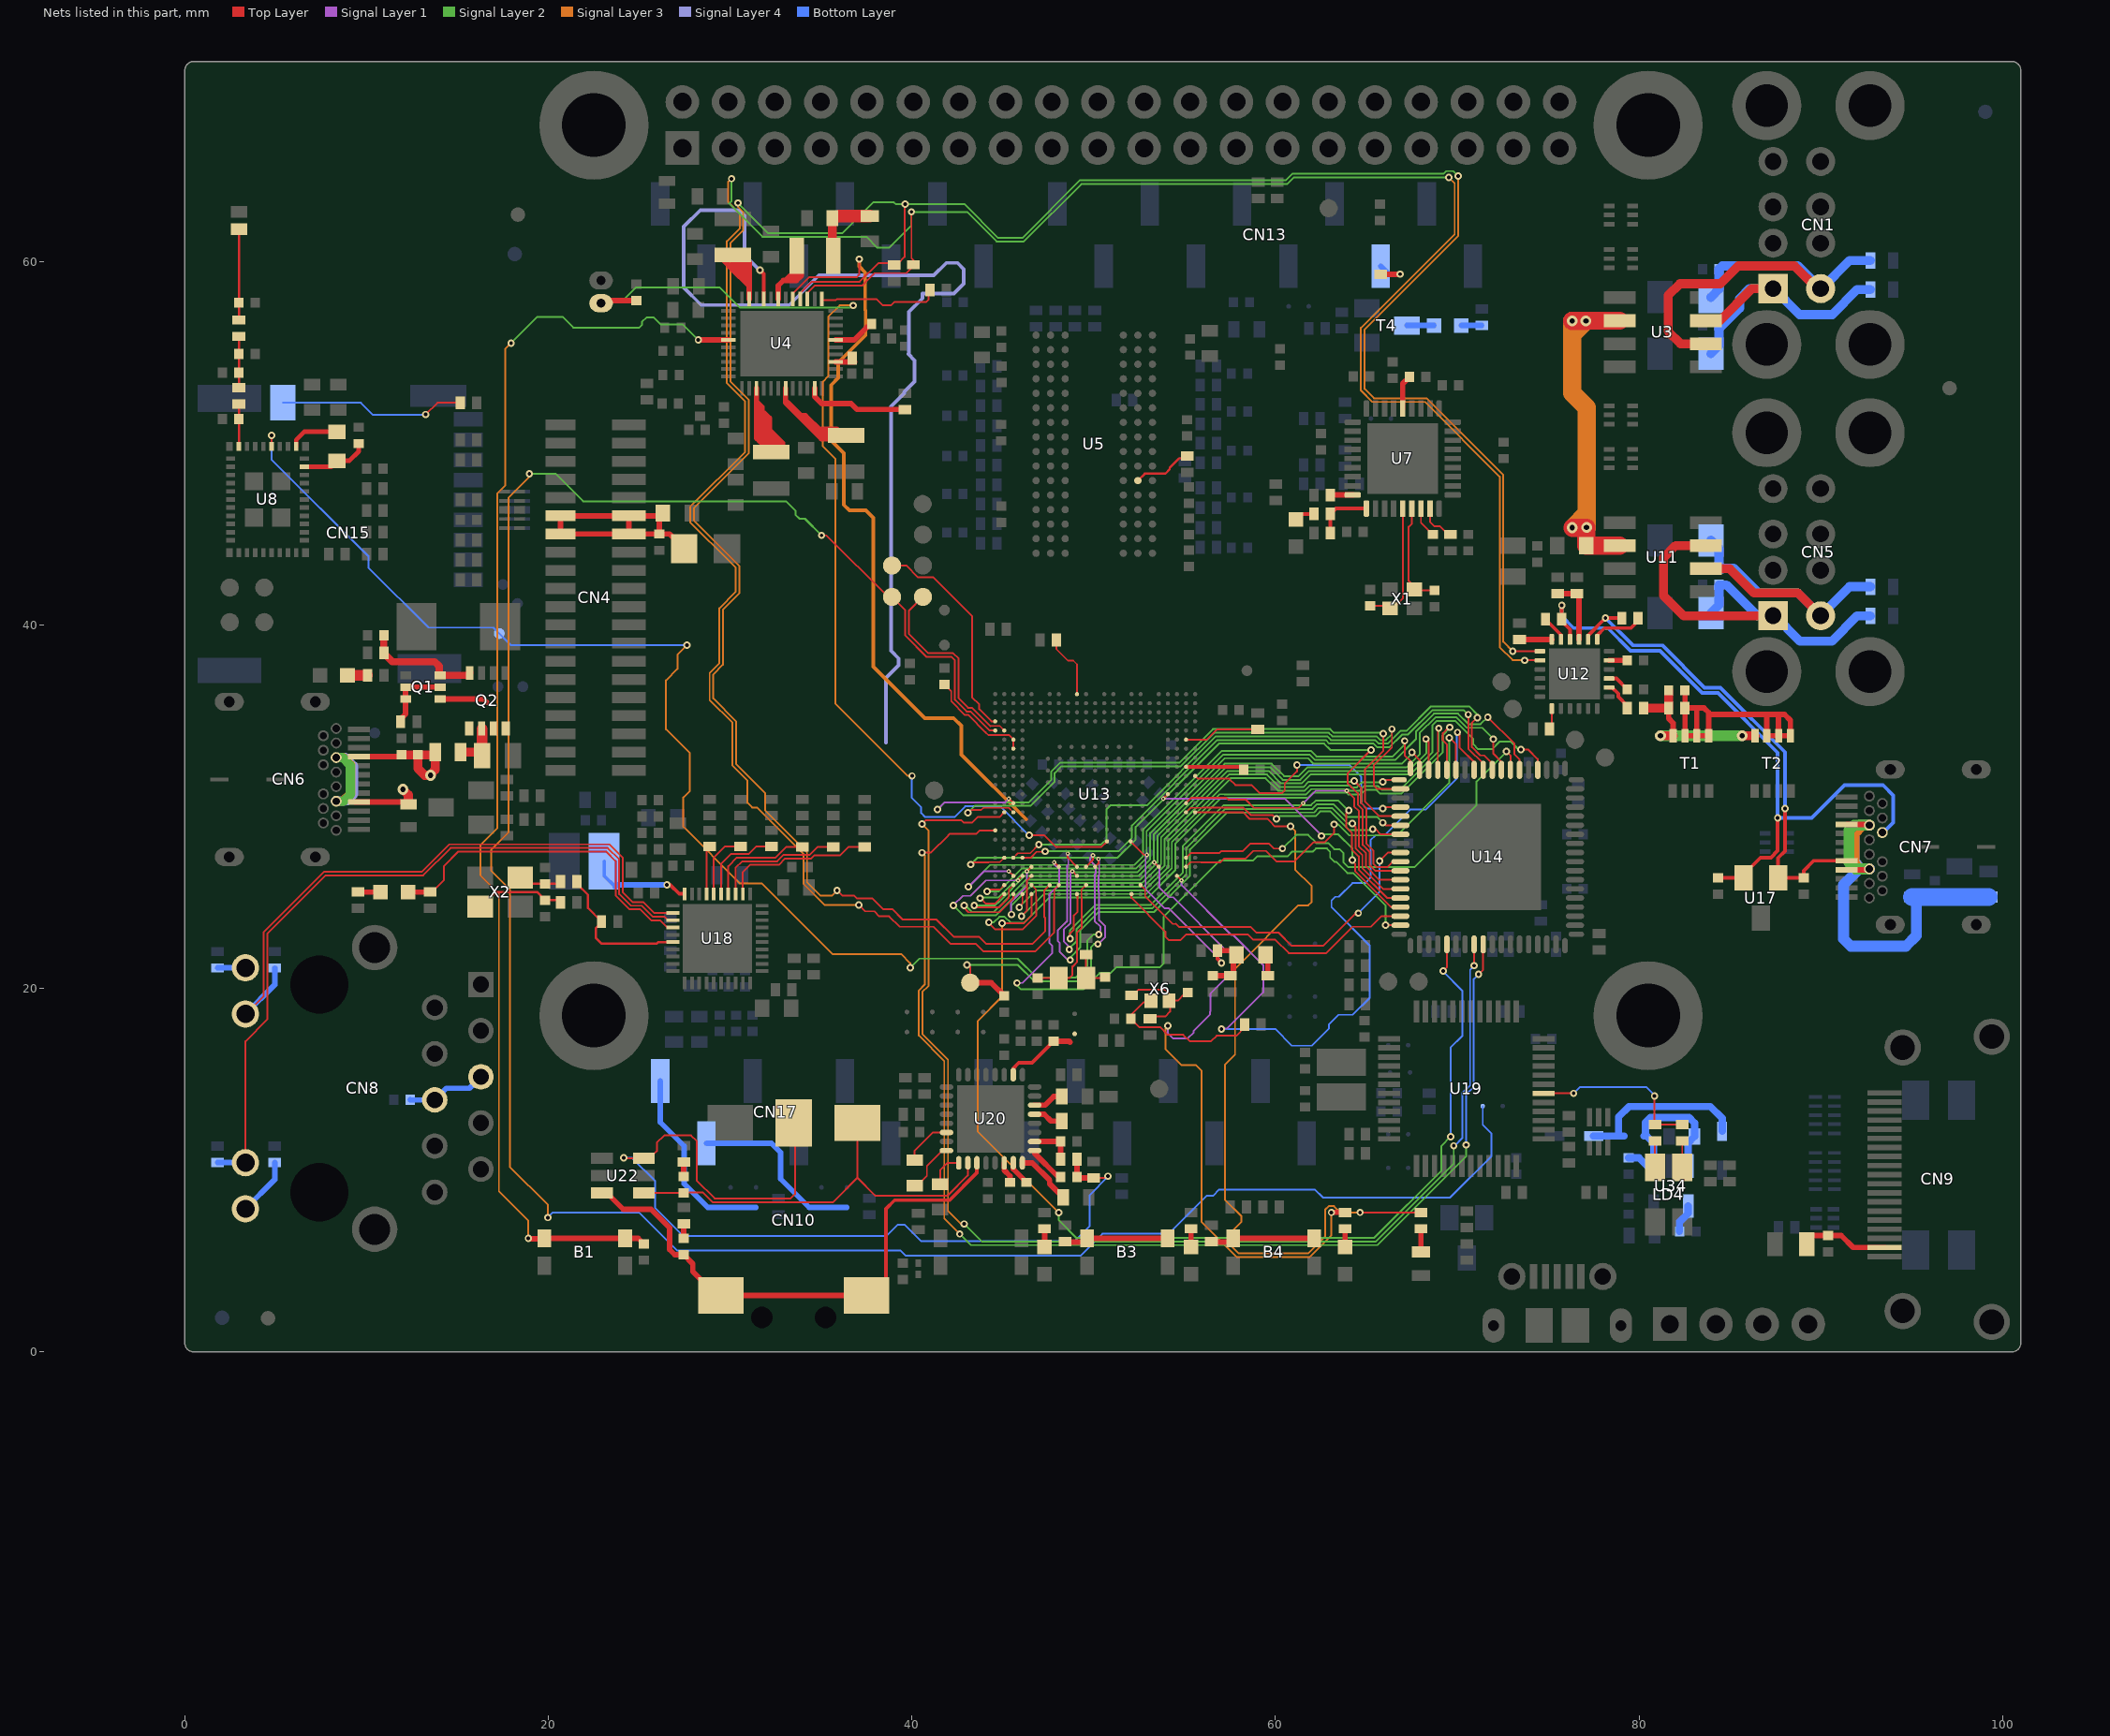
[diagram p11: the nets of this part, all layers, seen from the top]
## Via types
v1: diameter 0.4, hole 0.2, Top Layer to Bottom Layer, tented both sides, 884 vias
v2: diameter 0.25, hole 0.1, Top Layer to Signal Layer 1, tented top, 470 vias
v3: diameter 0.6, hole 0.3, Top Layer to Bottom Layer, tented both sides, 469 vias
v4: diameter 0.25, hole 0.1, Top Layer to Signal Layer 1, tented both sides, 46 vias
v5: diameter 0.25, hole 0.1, Top Layer to Bottom Layer, tented top, 2 vias

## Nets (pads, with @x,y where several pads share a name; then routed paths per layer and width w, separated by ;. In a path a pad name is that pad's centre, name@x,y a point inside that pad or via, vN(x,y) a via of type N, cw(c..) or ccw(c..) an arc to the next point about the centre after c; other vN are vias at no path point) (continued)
I2C4_SCL: R5.2 U4.4 U12.7 U13.G2 | length 149.1
  Top Layer w0.1: U4.4@33.85,57.925 33.85,58.237 34.488,58.875 37.125,58.875 38.15,59.9 39.26,59.9 39.6,60.24 39.6,63.125 v1(39.625,63.15) ; v1(35.88,25.39) 36.164,25.106 36.814,25.106 36.979,24.941 37.838,24.941 38.414,24.365 38.91,24.365 39.485,23.79 41.352,23.79 42.297,22.845 43.691,22.845 44.086,22.45 46.63,22.45 47.33,23.15 47.33,23.873 47.28,23.923 47.28,25.39 U13.G2@47.58,25.69 ; v1(73.05,38.55) U12.7@74.55,38.55
  Signal Layer 2 w0.1: v1(30.43,63.215) 32.095,61.55 36.167,61.55 37.867,63.25 39,63.25 39.1,63.15 v1(39.625,63.15) 42.881,63.15 44.741,61.29 46.069,61.29 49.234,64.455 60.556,64.455 60.916,64.815 69.235,64.815 69.385,64.965 69.78,64.965 v1(70.055,64.69)
  Signal Layer 3 w0.1: v1(30.43,63.215) 30.43,63.003 30.725,62.708 30.725,61.722 30.025,61.022 30.025,53.381 30.992,52.414 31.022,52.384 31.022,49.439 28.001,46.418 28.001,45.739 30.116,43.625 30.119,43.625 30.5,43.244 30.5,41.73 29.605,40.835 29.605,37.805 29.075,37.275 29.075,35.95 30.325,34.7 30.325,32.343 31.93,30.738 31.93,29.782 34.23,27.482 34.23,25.839 34.969,25.1 35.59,25.1 v1(35.88,25.39) ; v1(70.055,64.69) 70.055,61.414 64.9,56.259 64.9,52.98 65.415,52.465 68.305,52.465 72.53,48.24 72.53,39.07 v1(73.05,38.55)
I2C4_SDA: R7.2 U4.3 U12.8 U13.H2 | length 154.3
  Top Layer w0.09: 47.83,24.89 47.83,25.44 U13.H2@48.08,25.69
  Top Layer w0.1: U4.3@34.25,57.925 34.25,58.267 34.658,58.675 37.275,58.675 37.95,59.35 39.7,59.35 40.25,59.9 39.975,60.175 v1(39.975,62.725) ; v1(37.08,24.59) 37.08,24.595 37.435,24.24 37.93,24.24 38.205,23.965 38.744,23.965 39.319,23.39 41.187,23.39 42.132,22.445 43.525,22.445 43.92,22.05 46.796,22.05 47.83,23.084 47.83,24.89 ; v1(73.7,38.05) U12.8@74.55,38.05
  Signal Layer 2 w0.1: v1(30.08,64.55) 30.08,63.307 29.95,63.177 31.777,61.35 36.25,61.35 36.255,61.355 37.495,61.355 38.1,60.75 38.736,60.75 39.975,61.989 v1(39.975,62.725) 39.985,62.715 43.033,62.715 44.658,61.09 46.152,61.09 49.317,64.255 60.639,64.255 60.999,64.615 v1(69.53,64.615)
  Signal Layer 3 w0.1: v1(30.08,64.55) 29.891,64.361 29.891,63.259 30.525,62.625 30.525,61.805 29.825,61.105 29.825,53.298 30.822,52.302 30.822,49.522 27.801,46.501 27.801,45.657 30.033,43.425 30.036,43.425 30.3,43.161 30.3,41.813 29.405,40.918 29.405,37.888 28.875,37.358 28.875,35.867 30.125,34.617 30.125,32.26 30.95,31.435 30.95,30.214 31.214,29.95 31.479,29.95 34.03,27.399 34.03,25.756 35.196,24.59 v1(37.08,24.59) ; v1(69.53,64.615) 69.855,64.29 69.855,61.497 64.7,56.342 64.7,52.897 65.332,52.265 68.222,52.265 72.33,48.157 72.33,38.775 73.04,38.065 73.685,38.065 v1(73.7,38.05)
I2S2_CK: U13.A8 U14.45 | length 68.8
  Top Layer w0.1: v1(40.555,27.465) 41.044,27.465 42.005,28.426 42.005,28.44 42.08,28.515 43.556,28.515 43.731,28.69 U13.A8@44.58,28.69 ; v1(71.168,20.773) 71.425,21.03 U14.45@71.425,22.425
  Signal Layer 2 w0.1: v1(42.63,6.49) 43.245,5.875 65.6,5.875 70.48,10.755 v1(70.48,11.39)
  Signal Layer 3 w0.1: v1(40.555,27.465) 40.705,27.315 40.705,20.21 40.38,19.885 40.38,17.407 41.78,16.007 41.78,7.34 v1(42.63,6.49)
  Bottom Layer w0.1: v1(70.48,11.39) 70.48,14.157 70.905,14.582 70.905,20.51 v1(71.168,20.773)
I2S2_SDO: U13.E1 U14.41 | length 58.1
  Top Layer w0.1: v1(44.955,23.59) 46.15,23.59 46.58,24.02 U13.E1@46.58,25.19 ; v1(69.225,20.96) 69.425,21.16 U14.41@69.425,22.425
  Signal Layer 2 w0.1: v1(48.08,7.665) 48.08,7.245 49.05,6.275 65.434,6.275 69.125,9.966 69.125,11.335 v1(69.63,11.84)
  Signal Layer 3 w0.1: v1(44.955,23.59) 44.955,19.54 43.63,18.215 43.63,12.115 v1(48.08,7.665)
  Bottom Layer w0.1: v1(69.225,20.96) 69.225,20.915 70.28,19.86 70.28,17.39 69.63,16.74 v1(69.63,11.84)
I2S2_WS: U13.B10 U14.44 | length 69.9
  Top Layer w0.1: v1(40.555,29.04) 40.755,29.24 42.727,29.24 42.852,29.115 43.308,29.115 43.618,29.425 44.815,29.425 U13.B10@45.08,29.69 ; v1(70.925,21.251) U14.44@70.925,22.425
  Signal Layer 2 w0.1: v1(42.88,7.04) 43.845,6.075 65.517,6.075 69.805,10.363 v1(69.805,11.34)
  Signal Layer 3 w0.1: v1(40.555,29.04) 40.905,28.69 40.905,20.127 40.58,19.802 40.58,17.49 41.985,16.085 41.985,7.754 42.699,7.04 v1(42.88,7.04)
  Bottom Layer w0.1: v1(69.805,11.34) 69.855,11.34 70.28,11.765 70.28,14.24 70.705,14.665 70.705,21.031 v1(70.925,21.251)
JTDI: TP4.1 U13.A20 | length 12
  Top Layer w0.1: TP4.1@38.905,43.265 39.686,43.265 40.336,42.615 41.175,42.615 43.305,40.485 43.305,36.024 43.701,35.628 43.701,35.361 44.372,34.69 U13.A20@44.58,34.69
JTDO_TRACESWO: SB19.2 TP8.1 U13.A19 | length 135.4
  Top Layer w0.1: v1(35.03,44.925) 35.293,44.925 38.678,41.54 TP8.1@38.905,41.54 39.63,40.815 39.63,39.422 40.812,38.24 42.182,38.24 42.365,38.057 42.365,35.878 43.005,35.237 43.225,35.237 44.272,34.19 U13.A19@44.58,34.19
  Signal Layer 2 w0.1: v1(18.955,48.315) 20.397,48.315 21.912,46.8 33.062,46.8 33.605,46.257 33.605,46.045 33.81,45.84 34.115,45.84 v1(35.03,44.925)
  Signal Layer 3 w0.1: v1(18.955,48.315) 18.955,48.137 17.802,46.984 17.802,28.569 16.855,27.622 16.855,26.473 17.884,25.444 17.884,10.181 19.98,8.085 v1(19.98,7.39)
  Bottom Layer w0.1: v1(19.98,7.39) 19.955,7.39 20.226,7.661 23.88,7.661 ; 23.88,7.665 24.999,7.665 27.089,5.575 39.378,5.575 39.663,5.29 49.271,5.29 50.481,6.5 54.115,6.5 56.205,8.59 56.564,8.59 56.909,8.935 62.16,8.935 62.605,8.49 69.605,8.49 71.88,10.765 71.88,12.015 71.4,12.495 SB19.2@71.4,13.525
JTRST: TP9.1 U13.B19 | length 11.1
  Top Layer w0.09: 44.305,34.44 44.83,34.44 U13.B19@45.08,34.19
  Top Layer w0.1: TP9.1@40.605,41.54 39.83,40.765 39.83,39.505 40.895,38.44 42.265,38.44 42.565,38.14 42.565,35.961 43.088,35.437 43.308,35.437 44.305,34.44
LED_B: R108.1 U13.AC10 | length 44.8
  Top Layer w0.1: U13.AC10@55.58,29.69 58.205,29.69 58.56,29.335 59.56,29.335 59.705,29.19 59.705,29.182 59.972,28.915 v1@60.88,28.915 ; v1(64.65,7.675) R108.1@68,7.675
  Signal Layer 3 w0.1: v1(60.831,28.915) 61.08,28.666 61.08,26.545 61.975,25.65 61.975,24.735 61.805,24.565 61.264,24.565 57.775,21.076 57.775,16.354 57.23,15.809 57.23,8.36 58.131,7.459 58.131,7.169 57.48,6.519 57.48,5.907 57.972,5.415 61.797,5.415 62.725,6.343 62.725,7.82 62.93,8.025 63.22,8.025 63.57,7.675 v1(64.65,7.675)
LED_STLINK: R89.2 R90.2 U19.30 | length 9.6
  Top Layer w0.1: U19.30@74.75,14.225 v1(76.4,14.225) ; v1(80.85,14.075) 80.85,12.575 80.9,12.525 R89.2@80.875,12.5 R90.2@82.375,12.5
  Bottom Layer w0.1: v1(76.4,14.225) 76.75,14.575 80.4,14.575 80.85,14.125 v1(80.85,14.075)
LED_Y: R107.1 U13.W4 | length 37.4
  Top Layer w0.1: v2(53.33,26.94) U13.W4@53.58,26.69
  Top Layer w0.3: v1(63.075,7.675) R107.1@63.825,7.675
  Signal Layer 1 w0.1: v2(53.33,26.94) 53.605,26.665 53.605,25.549 54.139,25.015 54.363,25.015 57.238,22.14 57.341,22.14 57.78,21.701 57.78,21.079 56.431,19.73 56.431,19.222 56.432,19.22 56.432,18.93 56.431,18.928 56.431,18.743 56.405,18.718 56.405,18.575 55.5,17.67 55.5,17.575 55.175,17.25 54.35,17.25 54.079,17.521 v1(54.079,17.94)
  Signal Layer 3 w0.1: v1(54.079,17.94) 53.955,17.816 53.955,16.65 54.83,15.775 55.625,15.775 55.925,15.475 55.925,12.35 ; 55.93,12.35 55.93,7.174 57.889,5.215 61.88,5.215 63.075,6.41 v1(63.075,7.675)
LPO_32: TP26.1 U8.37 U13.L4 | length 74.7
  Top Layer w0.1: U8.37@4.775,49.825 v1(4.775,50.425) ; U13.L4@49.58,26.69 49.951,27.061 v2(49.951,27.325)
  Signal Layer 1 w0.1: v2(49.951,27.325) 49.8,27.174 49.8,27.05 50.104,26.746 50.104,26.326 50.055,26.277 50.055,23.71 50.375,23.39 50.375,23.06 v1(50.28,22.965)
  Signal Layer 2 w0.1: v1(39.905,21.14) 39.921,21.14 40.42,21.64 45.81,21.64 46.849,20.601 49.026,20.601 49.655,21.23 49.655,22.64 49.98,22.965 v1(50.28,22.965)
  Signal Layer 3 w0.1: v1(27.625,38.89) 27.1,38.365 27.1,37.576 26.475,36.951 26.475,34.25 27.78,32.945 27.78,30.866 27.425,30.511 27.425,28.897 30.557,25.765 31.758,25.765 35.633,21.89 39.405,21.89 39.905,21.39 v1(39.905,21.14)
  Bottom Layer w0.1: v1(4.775,50.425) 4.775,49.105 10.101,43.779 10.101,43.157 13.408,39.85 16.975,39.85 TP26.1@17.3,39.525 17.935,38.89 v1(27.625,38.89)
LTDC_B0: U13.K1 U14.32 | length 29
  Top Layer w0.1: v1(48.705,22.74) 48.705,23.04 48.91,23.244 48.91,24.02 49.11,24.22 49.11,25.16 U13.K1@49.08,25.19 ; v1(64.031,29.79) 63.881,29.64 63.881,28.88 64.199,28.562 64.199,27.64 64.58,27.259 64.58,26.539 66.144,24.975 U14.32@66.875,24.975
  Signal Layer 2 w0.1: v1(48.705,22.74) 48.705,23.206 50.099,24.6 53.14,24.6 54.895,26.355 54.895,27.811 57.161,30.077 61.95,30.077 62.205,30.332 63.463,30.332 64.005,29.79 v1(64.031,29.79)
LTDC_B1: U13.K4 U14.31 | length 33.5
  Top Layer w0.1: v2(48.575,27.411) 48.575,27.195 U13.K4@49.08,26.69 ; v1@64.227,29.062 64.399,28.89 64.399,27.723 64.78,27.341 64.78,26.622 65.927,25.475 U14.31@66.875,25.475 ; v1@64.228,29.062 v1(64.231,29.065)
  Signal Layer 1 w0.1: v2(48.575,27.411) 48.605,27.381 48.605,26.826 48.53,26.751 48.53,24.76 48.53,24.47 48.53,24.26 48.53,23.97 48.53,23.687 48.408,23.565 48.398,23.565 48.016,23.183 48.016,22.618 48.125,22.51 48.125,22.02 48.53,21.615 48.68,21.615 48.705,21.59 v1(48.705,21.565)
  Signal Layer 2 w0.1: v1(48.705,21.565) 48.705,21.695 49.255,22.245 49.255,23.19 50.265,24.2 53.306,24.2 55.295,26.189 55.295,27.645 57.327,29.677 62.115,29.677 62.371,29.932 63.111,29.932 63.978,29.065 v1(64.231,29.065)
LTDC_B2: U13.AB11 U14.30 | length 16.5
  Top Layer w0.1: U13.AB11@55.08,30.19 55.38,30.49 57.289,30.49 57.389,30.39 58.354,30.39 58.809,29.935 61.276,29.935 v4(61.531,30.19) ; v4(63.925,30.865) 64.325,30.465 64.325,30.021 64.599,29.748 64.599,27.805 64.98,27.424 64.98,26.704 65.709,25.975 U14.30@66.875,25.975
  Signal Layer 1 w0.1: v4@61.518,30.177 61.48,30.215 61.506,30.215 v4(61.531,30.19) 62.206,30.865 v4(63.925,30.865)
LTDC_B3: U13.B5 U14.29 | length 36.4
  Top Layer w0.09: 44.205,26.94 44.83,26.94 U13.B5@45.08,27.19
  Top Layer w0.1: v1@43.305,26.94 44.205,26.94 ; v1(65.255,33.115) 63.98,31.84 63.98,31.27 64.185,31.065 64.2,31.065 64.525,30.74 64.525,30.104 64.799,29.83 64.799,27.888 65.18,27.507 65.18,26.787 65.502,26.465 66.865,26.465 U14.29@66.875,26.475
  Signal Layer 2 w0.1: v1(43.23,26.815) 43.605,27.19 51.305,27.19 52.305,28.19 52.305,28.884 56.886,33.465 62.68,33.465 63.03,33.115 v1(65.255,33.115)
LTDC_B4: U13.E4 U14.28 | length 33.5
  Top Layer w0.1: v2(46.33,26.44) U13.E4@46.58,26.69 ; v1(64.33,31.415) 64.725,31.02 64.725,30.187 64.999,29.913 64.999,27.971 65.38,27.59 65.38,26.87 65.585,26.665 66.155,26.665 66.465,26.975 U14.28@66.875,26.975
  Signal Layer 1 w0.1: v1(45.48,24.065) 45.455,24.09 45.455,24.765 46.33,25.64 v2(46.33,26.44)
  Signal Layer 2 w0.1: v1(45.48,24.065) 45.48,24.574 46.301,25.394 ; 46.305,25.39 46.505,25.59 51.28,25.59 52.73,25.59 53.905,26.765 53.905,28.221 57.449,31.765 59.537,31.765 60.225,31.077 61.525,31.077 61.813,31.365 64.355,31.365 64.355,31.39 v1(64.33,31.415)
LTDC_B5: U13.U2 U14.27 | length 19
  Top Layer w0.09: U13.U2@52.58,25.69 52.83,25.44 52.83,25.075 54.355,23.55 54.525,23.55
  Top Layer w0.1: 54.525,23.55 54.7,23.375 58.644,23.375 58.94,23.079 60.157,23.079 60.896,22.34 62.614,22.34 64.414,24.14 v1(64.555,24.14) ; v1(65.73,27.015) 66.19,27.475 U14.27@66.875,27.475
  Bottom Layer w0.1: v1(64.555,24.14) 65.73,25.315 v1(65.73,27.015)
LTDC_B6: U13.AB10 U14.25 | length 12.9
  Top Layer w0.09: U13.AB10@55.08,29.69 55.33,29.94 56.005,29.94
  Top Layer w0.1: 56.005,29.94 58.238,29.94 58.643,29.535 59.847,29.535 v1(60.055,29.327) ; v1(65.349,28.765) 65.505,28.765 65.795,28.475 U14.25@66.875,28.475
  Signal Layer 2 w0.1: v1(60.055,29.327) 60.067,29.315 60.229,29.477 62.198,29.477 62.453,29.732 63.028,29.732 64.045,28.715 65.299,28.715 v1(65.349,28.765) v1@65.374,28.79
LTDC_B7: U13.K3 U14.24 | length 28.3
  Top Layer w0.1: v2(48.825,26.445) U13.K3@49.08,26.19 ; v1@65.905,29.115 66.045,28.975 U14.24@66.875,28.975
  Signal Layer 1 w0.1: v1(48.655,22.14) 48.655,22.295 48.355,22.595 48.355,23.229 48.733,23.607 48.73,23.61 48.73,25.25 48.73,26.35 v2(48.825,26.445)
  Signal Layer 2 w0.1: v1(48.655,22.14) 48.655,22.195 49.055,22.595 49.055,23.273 50.182,24.4 53.223,24.4 55.095,26.272 55.095,27.728 57.244,29.877 62.033,29.877 62.288,30.132 63.194,30.132 63.886,29.44 65.581,29.44 v1(65.906,29.115)
LTDC_CLK: U13.AC14 U14.22 | length 14.6
  Top Layer w0.1: U13.AC14@55.58,31.69 55.73,31.54 57.442,31.54 57.792,31.19 58.685,31.19 59.14,30.735 60.355,30.735 60.505,30.885 60.505,31.265 61.18,31.94 v1(61.18,32.29) ; v1(65.905,29.89) 65.99,29.975 U14.22@66.875,29.975
  Bottom Layer w0.1: v1(61.18,32.29) 64.08,32.29 64.725,31.645 64.725,30.187 65.022,29.89 v1(65.905,29.89)
LTDC_DE: U13.Y12 U14.33 | length 16.6
  Top Layer w0.1: v2(53.83,30.44) U13.Y12@54.08,30.69 ; v1(64.23,27.065) 64.205,27.04 64.38,26.865 64.38,26.456 66.361,24.475 U14.33@66.875,24.475
  Signal Layer 1 w0.1: v2(53.83,30.44) 60.5,30.44 62.53,28.41 v1(62.53,28.39)
  Signal Layer 2 w0.1: v1(62.53,28.39) 62.619,28.479 63.433,28.479 64.23,27.682 v1(64.23,27.065)
LTDC_G0: U13.C11 U14.23 | length 37.8
  Top Layer w0.1: v2(45.33,30.44) U13.C11@45.58,30.19 ; v1(65.93,34.015) 65.93,33.073 64.925,32.068 64.925,30.27 65.72,29.475 U14.23@66.875,29.475
  Signal Layer 1 w0.1: v1(41.405,29.84) 41.805,30.24 45.13,30.24 v2(45.33,30.44)
  Signal Layer 2 w0.1: v1(41.405,29.84) 41.805,30.24 46.43,30.24 47.655,31.465 47.655,31.929 48.141,32.415 54.705,32.415 56.555,34.265 63.013,34.265 63.213,34.065 65.88,34.065 v1(65.93,34.015) v1@66.005,33.94
LTDC_G1: U13.C10 U14.20 | length 33.8
  Top Layer w0.09: v1(43.08,29.665) 43.13,29.665 43.285,29.82 43.819,29.82 43.939,29.94 45.33,29.94 U13.C10@45.58,29.69
  Top Layer w0.1: v1(66.405,34.265) 66.405,33.265 65.408,32.268 65.408,31.168 65.6,30.975 U14.20@66.875,30.975
  Signal Layer 2 w0.1: v1(43.08,29.665) 43.455,30.04 46.513,30.04 47.855,31.382 47.855,31.843 48.227,32.215 54.788,32.215 56.638,34.065 62.93,34.065 63.13,33.865 65.566,33.865 65.766,33.665 66.08,33.665 66.405,33.99 v1(66.405,34.265)
LTDC_G2: U13.D1 U14.19 | length 26.1
  Top Layer w0.1: v1(45.905,24.465) 45.905,24.515 46.08,24.69 U13.D1@46.08,25.19 ; v1(65.905,31.365) 66.015,31.475 U14.19@66.8,31.475
  Signal Layer 2 w0.1: v1(45.905,24.465) 45.93,24.49 46.83,25.39 51.197,25.39 52.813,25.39 54.105,26.682 54.105,28.138 57.532,31.565 59.454,31.565 60.142,30.877 61.608,30.877 61.896,31.165 64.085,31.165 64.185,31.065 64.475,31.065 64.75,31.34 65.88,31.34 v1(65.905,31.365)
LTDC_G3: U13.C3 U14.18 | length 33.1
  Top Layer w0.1: v2(45.33,26.44) U13.C3@45.58,26.19 ; v1(67.105,33.615) 67.105,32.827 67.425,32.507 U14.18@67.425,32.1
  Signal Layer 1 w0.1: v1(43.105,25.59) 43.955,26.44 v2(45.33,26.44)
  Signal Layer 2 w0.1: v1(43.105,25.59) 44.305,26.79 47.48,26.79 51.777,26.79 52.233,26.79 52.705,27.262 52.705,28.718 57.052,33.065 61.955,33.065 62.255,32.765 64.355,32.765 66.455,32.765 67.105,33.415 v1(67.105,33.615)
LTDC_G4: U13.B1 U14.17 | length 31.1
  Top Layer w0.1: v1(43.755,24.965) 43.78,24.965 44.08,24.665 44.555,24.665 U13.B1@45.08,25.19 ; v1(67.506,32.99) 67.506,32.989 67.925,32.57 U14.17@67.925,32.025
  Signal Layer 2 w0.1: v1(43.755,24.965) 43.78,24.99 44.73,24.99 46.13,26.39 47.314,26.39 51.611,26.39 52.398,26.39 53.105,27.096 53.105,28.552 57.218,32.665 61.789,32.665 62.089,32.365 66.955,32.365 67.543,32.953 v1(67.506,32.99)
LTDC_G5: U13.C1 U14.16 | length 37.2
  Top Layer w0.1: v1(42.88,24.565) 42.88,24.415 43.105,24.19 44.813,24.19 45.58,24.957 U13.C1@45.58,25.19 ; v1(68.28,33.722) 68.173,33.615 68.173,33.83 68.425,33.578 U14.16@68.425,32.025
  Signal Layer 2 w0.1: v1(42.88,24.565) 42.88,24.615 42.885,24.615 43.285,24.215 44.519,24.215 44.894,24.59 ; 44.896,24.59 46.296,25.99 47.149,25.99 51.446,25.99 52.564,25.99 53.505,26.931 53.505,28.387 57.283,32.165 59.702,32.165 60.391,31.477 61.359,31.477 61.847,31.965 67.305,31.965 68.298,32.958 68.298,33.722 v1(68.28,33.722)
LTDC_G6: U13.E3 U14.15 | length 33.9
  Top Layer w0.09: v1(46.03,23.965) 46.03,23.99 46.33,24.29 46.33,25.94 U13.E3@46.58,26.19 ; U14.15@68.925,32.025 68.925,34.26 v1(68.98,34.315)
  Signal Layer 2 w0.09: v1(46.03,23.965) 47.26,25.195 51.116,25.195 52.893,25.195 54.3,26.602 54.3,28.057 56.92,30.677 57.205,30.677
  Signal Layer 2 w0.1: 57.205,30.677 61.69,30.677 61.979,30.965 64.002,30.965 64.102,30.865 64.597,30.865 64.857,31.125 65.644,31.125 65.854,30.915 66.847,30.915 68.98,33.048 v1(68.98,34.315)
LTDC_G7: U13.E2 U14.14 | length 39.3
  Top Layer w0.09: U13.E2@46.58,25.69 46.83,25.44 46.83,25.04
  Top Layer w0.1: v1(44.23,23.64) 44.23,23.59 44.58,23.24 46.083,23.24 46.83,23.987 46.83,25.04 ; U14.14@69.425,32.025 69.425,33.425 69.205,33.645 69.205,34.04 69.53,34.365 v1(69.581,34.365)
  Signal Layer 2 w0.1: v1(44.23,23.64) 44.51,23.64 44.81,23.94 45.1,23.94 45.425,23.615 46.175,23.615 47.56,25 52.974,25 54.495,26.521 54.495,27.977 56.995,30.477 61.773,30.477 62.061,30.765 63.919,30.765 64.019,30.665 64.68,30.665 64.94,30.925 65.561,30.925 65.771,30.715 66.93,30.715 69.205,32.99 69.205,33.935 69.581,34.311 v1(69.581,34.365)
LTDC_HSYNC: U13.T1 U14.34 | length 17.5
  Top Layer w0.1: U13.T1@52.08,25.19 52.08,24.984 53.947,23.117 53.947,22.853 54.15,22.65 54.763,22.65 55.088,22.975 58.478,22.975 58.774,22.679 59.991,22.679 60.73,21.94 62.79,21.94 64.24,23.39 65.25,23.39 65.835,23.975 U14.34@66.875,23.975
LTDC_R0: U13.AB4 U14.13 | length 22.1
  Top Layer w0.09: U13.AB4@55.08,26.69 55.33,26.94 55.905,26.94 ; v1(69.555,33.79) 69.555,33.815 69.925,33.445 U14.13@69.925,32.025
  Top Layer w0.1: 55.905,26.94 56.97,26.94 57.17,27.14 58.364,27.14 58.789,27.565 59.471,27.565 60.057,26.979 61.02,26.979 62.076,28.034 62.705,28.034 63.219,28.548 v1(63.219,29.029)
  Signal Layer 2 w0.1: v1(63.219,29.029) 63.205,29.015 63.463,29.015 64.063,28.415 66.676,28.415 69.555,31.294 v1(69.555,33.79)
LTDC_R1: U13.AA3 U14.11 | length 43.4
  Top Layer w0.1: U13.AA3@54.58,26.19 v2(54.83,25.94) ; v1(70.011,34.084) 70.13,33.965 70.13,33.24 70.925,32.445 U14.11@70.925,32.025
  Signal Layer 1 w0.1: v2(54.83,25.94) 54.83,25.68 57.57,22.94 57.672,22.94 59.33,21.282 59.33,19.777 57.343,17.79 57.03,17.79 v1(57.03,17.765)
  Bottom Layer w0.1: v1(57.03,17.765) 59.985,17.765 60.9,16.85 61.987,16.85 62.95,17.813 62.95,18.03 63.47,18.55 64.25,18.55 65.18,19.48 65.18,22.365 63.08,24.465 63.08,24.835 63.285,25.04 63.48,25.04 64.23,25.79 64.93,25.79 65.23,26.09 65.23,28.151 65.494,28.415 65.98,28.415 67.405,29.84 68.255,29.84 69.975,31.56 69.975,34.049 v1(70.011,34.084)
LTDC_R2: U13.D5 U14.10 | length 32.1
  Top Layer w0.1: U13.D5@46.08,27.19 46.531,27.19 46.853,27.512 47.302,27.512 v1(47.33,27.54) ; v1(70.605,35.065) 70.605,33.19 71.425,32.37 U14.10@71.425,32.025
  Signal Layer 2 w0.1: v1(47.33,27.54) 51.355,27.54 52.105,28.29 52.105,28.966 56.804,33.665 62.764,33.665 62.964,33.465 65.4,33.465 65.6,33.265 66.26,33.265 66.96,33.965 67.286,33.965 68.637,35.315 70.355,35.315 v1(70.605,35.065)
LTDC_R3: U13.C5 U14.9 | length 34.3
  Top Layer w0.09: U13.C5@45.58,27.19 45.83,27.44 46.505,27.44 46.955,27.89 46.98,27.865 v1(46.98,27.915)
  Top Layer w0.1: v1(71.105,34.89) 71.08,34.89 70.805,34.615 70.805,33.273 71.259,32.819 71.49,32.819 71.925,32.384 U14.9@71.925,32.025
  Signal Layer 2 w0.1: v1(46.98,27.915) 50.405,27.915 50.705,28.215 50.705,29.86 50.91,30.065 52.921,30.065 56.721,33.865 62.847,33.865 63.047,33.665 65.483,33.665 65.683,33.465 66.177,33.465 66.877,34.165 67.204,34.165 68.554,35.515 70.65,35.515 71.105,35.06 v1(71.105,34.89)
LTDC_R4: U13.C2 U14.8 | length 40.2
  Top Layer w0.09: 45.33,24.99 45.33,25.44 U13.C2@45.58,25.69
  Top Layer w0.1: v1@43.48,24.465 44.805,24.465 45.33,24.99 ; v1(71.98,33.715) 71.98,32.915 72.425,32.47 U14.8@72.425,32.025
  Signal Layer 2 w0.1: v1(43.43,24.565) 44.58,24.565 44.805,24.79 44.813,24.79 46.213,26.19 47.232,26.19 51.529,26.19 52.481,26.19 53.305,27.014 53.305,28.469 57.201,32.365 59.785,32.365 60.473,31.677 61.276,31.677 61.764,32.165 67.222,32.165 67.93,32.873 67.93,34.043 68.803,34.915 69.957,34.915 70.533,34.34 71.38,34.34 72.005,33.715 v1(71.98,33.715)
LTDC_R5: U13.AB5 U14.7 | length 23.9
  Top Layer w0.1: U13.AB5@55.08,27.19 55.335,27.445 56.909,27.445 57.004,27.54 58.199,27.54 58.624,27.965 59.636,27.965 59.908,27.693 60.377,27.693 v1(60.38,27.69) ; v1(72.702,33.031) 72.925,32.808 U14.7@72.925,32.025
  Signal Layer 2 w0.1: v1(60.38,27.69) 61.14,28.45 61.8,28.45 62.25,28 62.895,28 63.23,27.665 63.525,27.665 63.73,27.46 63.73,26.94 64.005,26.665 67.63,26.665 71.055,30.09 71.055,31.383 v1(72.702,33.031)
LTDC_R6: U13.B2 U14.6 | length 37.9
  Top Layer w0.09: 44.43,25.44 44.83,25.44 U13.B2@45.08,25.69
  Top Layer w0.1: v1@44.23,25.44 44.43,25.44 ; v1(71.68,34.915) 73.14,33.455 73.14,32.875 73.425,32.59 U14.6@73.425,32.025
  Signal Layer 2 w0.1: v1(44.129,25.34) 44.78,25.34 46.03,26.59 47.397,26.59 51.694,26.59 52.316,26.59 52.905,27.179 52.905,28.635 57.135,32.865 61.872,32.865 62.172,32.565 64.005,32.565 66.58,32.565 67.73,33.715 67.73,34.126 68.72,35.115 70.04,35.115 70.616,34.54 71.28,34.54 71.68,34.94 v1(71.68,34.915)
LTDC_R7: U13.D3 U14.4 | length 45.5
  Top Layer w0.1: v2(45.83,25.94) U13.D3@46.08,26.19 ; v1(73.506,33.14) 73.905,33.14 74.425,32.62 U14.4@74.425,32.025
  Signal Layer 1 w0.1: v1(42.28,24.565) 42.805,25.09 43.23,25.09 44.08,25.94 v2(45.83,25.94)
  Signal Layer 2 w0.1: v1(42.28,24.565) 42.83,24.015 44.602,24.015 44.977,24.39 ; 44.979,24.39 46.379,25.79 47.066,25.79 51.363,25.79 52.647,25.79 53.705,26.848 53.705,28.304 57.366,31.965 59.62,31.965 60.308,31.277 61.442,31.277 61.93,31.765 67.414,31.765 68.63,32.981 68.63,34.46 68.885,34.715 69.875,34.715 70.88,33.71 70.88,33.429 71.144,33.165 71.925,33.165 72.341,33.581 72.93,33.581 73.371,33.14 v1(73.506,33.14)
LTDC_VSYNC: U13.H4 U14.35 | length 36.9
  Top Layer w0.1: v2(47.83,26.94) U13.H4@48.08,26.69 ; v1(66.05,23.475) U14.35@66.875,23.475
  Signal Layer 1 w0.1: v1(45.775,20.3) 46.07,20.3 47.725,21.955 47.725,22.344 47.55,22.519 47.55,25.16 48.105,25.715 48.105,26.554 47.83,26.829 v2(47.83,26.94)
  Signal Layer 2 w0.1: v1@45.8,20.15 46,19.95 49.425,19.95 50.325,20.85 50.935,20.85 51.255,21.17 53.645,21.17 53.85,21.375 53.85,23.95 56.925,27.025 58.75,27.025 59,27.275 60.675,27.275 60.925,27.525 62.05,27.525 62.225,27.7 62.825,27.7 63.005,27.52 63.005,27.195 63.235,26.965 63.335,26.965 63.95,26.35 64.275,26.35 66.05,24.575 v1(66.05,23.475)
NetB1_3: B1.3 B1.4 C114.2 U4.17 | length 71.2
  Top Layer w0.3: v1(18.9,6.25) 18.9,6.225 19.75,6.225 B1.4@19.775,6.25 B1.3@24.225,6.25 24.95,6.25 C114.2@25.25,5.95 ; v1(28.25,55.675) U4.17@29.9,55.675
  Signal Layer 2 w0.1: v1(17.95,55.5) 19.4,56.95 20.775,56.95 21.375,56.35 25,56.35 25.15,56.5 25.15,56.661 25.414,56.925 25.786,56.925 26.186,56.525 27.4,56.525 v1(28.25,55.675)
  Signal Layer 3 w0.1: v1(17.95,55.5) 17.625,55.175 17.625,47.656 17.202,47.233 17.202,28.818 16.255,27.871 16.255,26.224 17.284,25.196 17.284,8.836 18.9,7.22 v1(18.9,6.25)
NetB3_3: B3.3 B3.4 R110.1 | length 5.7
  Top Layer w0.3: R110.1@48.425,6.075 48.45,6.05 49.425,6.05 B3.4@49.625,6.25 B3.3@54.075,6.25
NetB4_3: B4.3 B4.4 R111.1 | length 5.7
  Top Layer w0.3: R111.1@56.475,6.075 56.5,6.05 57.475,6.05 B4.4@57.675,6.25 B4.3@62.125,6.25
NetC3_2: C3.2 L3.2 R3.1 | length 4.1
  Top Layer w0.5: C3.2@35.625,62.375 35.625,60.75 L3.2@35.7,60.675 ; C3.2@35.743,62.25 35.993,62.5 36.298,62.525 36.3,62.525
  Top Layer w0.7: 35.993,62.5 R3.1@37.675,62.5
NetC7_2: C7.2 CN3.1 U13.1F1 | length 59.9
  Top Layer w0.1: v1(46.452,28.426) v1(46.452,28.426) 47.279,28.425 47.914,27.79 50.43,27.79 U13.1F1@50.73,28.09
  Top Layer w0.3: CN3.1@22.9,57.7 23.05,57.85 C7.2@24.85,57.85
  Signal Layer 2 w0.1: CN3.1@22.9,57.7 23.025,57.825 24.091,57.825 24.841,58.575 29.425,58.575 30.55,57.45 36.565,57.45 v1@36.765,57.65 ; v1@46.426,28.4 v1(46.452,28.426)
  Signal Layer 3 w0.1: v1(36.775,57.575) 36.025,57.575 35.4,56.95 35.4,53.681 35.1,53.381 35.1,49.825 35.78,49.145 35.78,35.673 39.763,31.69 v1(40.005,31.69)
  Bottom Layer w0.1: v1(40.005,31.69) 39.98,31.665 39.98,30.495 40.505,29.97 40.505,29.645 40.71,29.44 42.36,29.44 42.935,30.015 44.864,30.015 v1(46.452,28.426)
NetC8_2: C8.2 L1.1 R8.1 | length 5
  Top Layer w0.13: R8.1@2.975,56.775 C8.2@2.975,57.725 L1.1@2.975,61.775
NetC10_1: C10.1 U4.40 | length 2
  Top Layer w0.3: U4.40@35.8,55.675 36.684,55.675 36.828,55.675 37.525,56.372
NetC19_2: C19.2 C24.2 R8.2 R10.1 | length 2.8
  Top Layer w0.13: R10.1@2.975,53.05 C24.2@2.975,53.875 C19.2@2.975,54.9 R8.2@2.975,55.875
NetC25_2: C25.2 U7.14 | length 1.9
  Top Layer w0.3: U7.14@67,51.9 67,53.275 C25.2@67.375,53.65
NetC34_2: C34.2 R10.2 U8.41 | length 2.3
  Top Layer w0.13: U8.41@2.975,49.825 C34.2@2.975,51.325 R10.2@2.975,52.15
NetC37_2: C37.2 L4.2 U8.31 | length 3.8
  Top Layer w0.25: U8.31@6.575,48.7 8.05,48.7 L4.2@8.375,49.025 9.05,49.025 9.575,49.55 C37.2@9.575,49.975
NetC51_2: C51.2 C52.1 CN4.14 CN4.15 L7.2 | length 15.8
  Top Layer w0.3: L7.2@26.3,46.15 L7.2@26.15,46 ; C52.1@27.475,44.2 26.675,45 C51.2@26.1,45 ; CN4.14@24.425,45 CN4.15@24.425,46 ; CN4.14@24.425,45 C51.2@26.1,45 ; CN4.14@24.425,45 CN4.14@20.675,45 CN4.15@20.675,46 CN4.15@24.425,46 ; CN4.15@24.425,46 L7.2@26.15,46 ; C51.2@26.1,45 26.1,45.95 L7.2@26.15,46
NetC53_2: C53.2 U7.34 | length 1.7
  Top Layer w0.1: U7.34@68,46.4 68,45.625 C53.2@68.65,44.975
NetC58_2: C58.2 U7.32 X1.3 | length 6.7
  Top Layer w0.1: C58.2@65.2,41.05 66.6,41.05 67,41.45 67,44.686 U7.32@67,46.15
NetC59_2: C59.2 U7.33 X1.1 | length 5.8
  Top Layer w0.1: U7.33@67.5,46.4 67.5,45.575 67.325,45.4 67.325,42.425 67.65,42.1 X1.1@67.65,41.95 67.7,41.9 C59.2@68.75,41.9
NetC61_1: C61.1 Q1.3 Q2.4 R39.2 | length 6.5
  Top Layer w0.4: C61.1@10.95,39.425 R39.2@10.95,38.45 11.425,37.975 13.75,37.975 14,37.725 14,37.275 Q1.3@14.05,37.225 15.55,37.225 Q2.4@15.675,37.35
NetC62_2: C62.2 U12.23 | length 1
  Top Layer w0.3: U12.23@78.35,38.05 C62.2@79.35,38.05
NetC64_2: C64.2 U13.C17 U13.C18 | length 5.9
  Top Layer w0.09: 44.055,34.09 44.205,33.94 45.33,33.94
  Top Layer w0.1: C64.2@41.79,36.715 42.165,36.34 42.165,35.795 42.923,35.037 43.108,35.037 44.055,34.09 ; 45.33,33.94 U13.C18@45.58,33.69 U13.C17@45.58,33.19
NetC65_2: C65.2 U12.21 | length 1.2
  Top Layer w0.2: U12.21@78.35,37.05 78.75,37.05 C65.2@79.35,36.45
NetC66_1: C66.1 R42.1 R43.1 T1.4 T2.4 | length 9.9
  Top Layer w0.3: R42.1@81.625,35.425 81.625,34.85 81.875,34.6 T1.4@81.875,33.9
  Top Layer w0.5: R43.1@80.25,35.425 R42.1@81.625,35.425 C66.1@81.625,36.4 ; v3(81.175,33.9) T1.4@81.875,33.9 ; v3(85.675,33.9) T2.4@86.375,33.9
  Signal Layer 2 w0.6: v3(81.175,33.9) v3(85.675,33.9)
NetC66_2: C66.2 R42.2 T1.1 T1.2 T1.3 T2.1 T2.2 T2.3 | length 17.2
  Top Layer w0.3: C66.2@82.525,36.4 R42.2@82.525,35.425 ; R42.2@82.525,35.425 83.2,35.425 ; R42.2@82.525,35.425 T1.3@82.525,33.9 T1.2@83.175,33.9 ; T1.2@83.175,33.9 T1.1@83.825,33.9 83.825,35.175 ; T1.2@83.175,33.9 83.175,35.4 83.2,35.425 ; 83.2,35.425 83.575,35.425 83.825,35.175 ; 83.825,35.175 83.925,35.075 87.075,35.075 ; 87.075,35.075 87.625,35.075 ; 87.075,35.075 87.025,35.025 T2.3@87.025,33.9 T2.2@87.675,33.9 ; 87.625,35.075 88,35.075 88.325,34.75 T2.1@88.325,33.9 T2.2@87.675,33.9 ; 87.625,35.075 87.675,35.025 T2.2@87.675,33.9
NetC69_2: C69.2 C70.1 CN6.A4 CN6.A9 CN6.B4 CN6.B9 R47.1 U16.1 | length 25.9
  Top Layer w0.3: CN6.A9@9.38,30.25 CN6.A9@9.58,30.25 12.175,30.25 U16.1@12.3,30.125 ; CN6.A4@9.38,32.75 CN6.A4@9.58,32.75 11.825,32.75 C69.2@11.925,32.85 ; R47.1@13.625,32.85 R47.1@13.775,33
  Top Layer w0.5: C69.2@11.925,32.85 C70.1@12.825,32.85 ; v3(12,30.95) 12.3,30.65 U16.1@12.3,30.125 ; R47.1@13.625,32.85 C70.1@12.825,32.85 ; R47.1@13.775,33 13.775,32.025 13.525,31.775 v3(13.525,31.725) 13.2,31.725 12.825,32.1 C70.1@12.825,32.85
  Signal Layer 2 w0.5: CN6.B9@8.31,32.7 CN6.B9@8.33,32.7 8.68,32.7 9.105,32.275 9.105,30.65 8.755,30.3 CN6.B4@8.33,30.3
  Signal Layer 3 w0.5: CN6.B4@8.33,30.3 8.7,30.3 9.125,30.725 9.125,32.3 8.725,32.7 CN6.B9@8.33,32.7
  Signal Layer 4 w0.5: CN6.B4@8.305,30.3 8.33,30.325 8.93,30.325 9.28,30.675 9.28,32.25 8.83,32.7 CN6.B9@8.33,32.7 CN6.B9@8.31,32.7
  Bottom Layer w0.5: CN6.B4@8.33,30.3 8.8,30.3 9.15,30.65 9.15,32.3 8.75,32.7 CN6.B9@8.33,32.7
NetC71_2: C71.2 Q1.1 Q2.5 Q2.6 Q2.7 Q2.8 R47.2 | length 5.4
  Top Layer w0.3: Q1.1@14.05,35.925 16.425,35.925 16.6,35.75
  Top Layer w0.5: R47.2@15.175,33 16.15,33 C71.2@16.35,32.8 ; Q2.6@16.325,34.3 Q2.6@16.35,34.275
  Top Layer w0.6: C71.2@16.35,32.8 Q2.6@16.35,34.275
NetC72_2: C72.2 U13.AB15 | length 3.2
  Top Layer w0.2: U13.AB15@55.08,32.19 58.105,32.19 C72.2@58.255,32.04
NetC82_2: C82.2 R64.1 X2.1 | length 2.4
  Top Layer w0.13: X2.1@18.45,26.1 18.8,25.75 C82.2@19.825,25.75 20.55,25.75 R64.1@20.675,25.875
NetC83_2: C83.2 CN7.B5 R35.2 U12.4 U17.2 | length 36.7
  Top Layer w0.2: v1(75.75,41.075) R35.2@75.75,40.325 75.75,40.2 76.2,39.75 U12.4@76.2,39.2 ; C83.2@84.35,26.075 U17.2@85.75,26.075 85.75,26.275 86.675,27.2 87.25,27.2 87.625,27.575 v1(87.625,29.375)
  Bottom Layer w0.2: v1(75.75,41.075) 75.75,40.475 76.4,39.825 78.276,39.825 79.526,38.575 81.15,38.575 83.475,36.25 84.351,36.25 87.625,32.976 v1(87.625,29.375) 89.5,29.375 91.3,31.175 93.425,31.175 93.98,30.62 93.98,29.126 93.429,28.575 CN7.B5@93.38,28.575
NetC84_2: C84.2 CN7.A5 R34.2 U12.2 U17.1 | length 26.9
  Top Layer w0.2: U12.2@77.2,39.2 77.2,39.425 v1(78.15,40.375) R34.2@79.05,40.375 ; v1(88.025,29.9) 88.025,27.551 87.65,27.176 U17.1@87.65,26.075 C84.2@89.05,26.075 89.05,26.475 89.6,27.025 CN7.A5@91.42,27.025
  Bottom Layer w0.2: v1(78.15,40.375) 79.65,38.875 81.274,38.875 83.599,36.55 84.475,36.55 88.025,33 v1(88.025,29.9)
NetC86_2: C86.2 R68.1 X2.3 | length 5
  Top Layer w0.13: X2.3@16.25,24.5 16.35,24.5 17.15,25.3 19.375,25.3 C86.2@19.825,24.85 20.55,24.85 R68.1@20.675,24.725
NetC87_1: C87.1 R73.1 R302.1 X6.1 | length 5.1
  Top Layer w0.1: R73.1@52.25,19.6 52.25,19.725 52.45,19.925 53.925,19.925 54.2,19.65 X6.1@54.2,19.325 ; R302.1@53.3,18.45 53.925,18.45 54.2,18.725 X6.1@54.2,19.325 ; C87.1@54.975,19.675 54.625,19.325 X6.1@54.2,19.325
NetC89_2: C89.2 L9.2 R74.1 R78.2 U13.1H1 | length 13.2
  Top Layer w0.1: U13.1H1@52.03,28.09 52.78,27.34 v4(52.93,27.34)
  Top Layer w0.2: R74.1@56.8,22.075 56.8,21.62 v1(57.03,21.39)
  Top Layer w0.3: C89.2@56.55,20.7 R78.2@57.525,20.7 57.68,20.855 57.68,21.68 L9.2@57.85,21.85 57.625,22.075 R74.1@56.8,22.075
  Signal Layer 1 w0.1: v4(52.93,27.34) 52.855,27.265 52.855,25.451 53.891,24.415 54.115,24.415 57.03,21.5 v1(57.03,21.39)
NetC90_1: C90.1 U13.L2 X4.2 | length 7.2
  Top Layer w0.09: 49.33,24.975 49.33,25.44 U13.L2@49.58,25.69
  Top Layer w0.1: C90.1@46.925,20.575 48.075,20.575 48.665,20.575 48.83,20.74 48.83,21.215 48.85,21.215 49.075,21.44 49.075,23.067 49.33,23.322 49.33,24.975
NetC91_1: C91.1 R71.2 X4.1 | length 2.4
  Top Layer w0.1: R71.2@49.575,21.85 49.575,20.575 C91.1@50.725,20.575
NetC92_2: C92.2 TP22.1 U13.M4 | length 18.1
  Top Layer w0.1: v1(43.03,21.29) 43.03,21.365 43.205,21.19 TP22.1@43.205,20.315 ; U13.M4@50.08,26.69 50.255,26.865 v2(50.255,27.123)
  Top Layer w0.3: TP22.1@43.205,20.315 44.36,20.315 C92.2@45.075,19.6
  Signal Layer 1 w0.1: v1(50.23,22.44) 50.25,22.44 50.63,22.82 50.63,23.418 50.3,23.748 50.3,25.275 50.255,25.32 50.255,26.194 50.304,26.243 50.304,27.074 v2(50.255,27.123)
  Signal Layer 2 w0.1: v1(43.03,21.29) 45.835,21.29 46.724,20.401 49.199,20.401 49.855,21.058 49.855,22.285 50.01,22.44 v1(50.23,22.44)
NetC96_1: C96.1 SB5.2 U20.26 | length 4.1
  Top Layer w0.2: U20.26@45.575,15.25 45.575,15.6 45.875,15.9 46.6,15.9 C96.1@47.8,17.1
  Top Layer w0.3: C96.1@47.8,17.1 48.65,17.1 48.7,17.05
NetC100_2: C100.2 U20.22 | length 1.7
  Top Layer w0.3: U20.22@46.75,13.575 47.325,13.575 47.8,14.05 C100.2@48.25,14.05
NetC101_2: C101.2 U20.21 | length 1.7
  Top Layer w0.3: U20.21@46.75,13.075 47.275,13.075 47.65,12.7 C101.2@48.25,12.7
NetC103_2: C103.2 R95.2 U20.18 | length 2.4
  Top Layer w0.3: U20.18@46.75,11.575 C103.2@48.175,11.575 R95.2@48.175,10.6
NetC104_1: C104.1 U20.8 | length 2.9
  Top Layer w0.1: C104.1@40.15,9.15 40.275,9.15 40.825,9.7 40.825,10.225 41.675,11.075 U20.8@41.9,11.075
NetC104_2: C104.2 U20.6 | length 2.7
  Top Layer w0.1: C104.2@40.15,10.55 40.15,11.075 41.15,12.075 U20.6@41.9,12.075
NetC105_1: C105.1 CN10.1 R95.1 R96.2 U22.3 | length 52.1
  Top Layer w0.1: v1(24.15,10.675) 24.175,10.65 U22.3@25.25,10.65 25.575,10.65 25.975,11.05 25.975,11.51 26.38,11.915 27.855,11.915 28.155,11.615 28.155,9.44 29.155,8.44 33.33,8.44 33.565,8.675 33.565,12.535 CN10.1@33.5,12.6 ; R96.2@50,9.575 50.01,9.565 50.679,9.565 v1(50.78,9.666)
  Top Layer w0.3: R95.1@49.075,10.6 C105.1@49.075,9.625 49.125,9.575 R96.2@50,9.575
  Bottom Layer w0.1: v1(24.15,10.675) 24.6,10.675 25.88,9.395 25.88,7.915 27.42,6.375 38.594,6.375 39.219,7 39.595,7 40.505,6.09 48.94,6.09 49.781,6.931 49.781,8.631 50.78,9.63 v1(50.78,9.666)
NetC105_2: C105.2 U20.17 | length 2.1
  Top Layer w0.3: U20.17@46.75,11.075 46.75,10.925 48.05,9.625 C105.2@48.175,9.625
NetC106_1: C106.1 R92.2 | length 0.8
  Top Layer w0.3: C106.1@27.45,9.65 R92.2@27.45,10.45
NetC106_2: C106.2 CN10.3 U20.10 U22.1 | length 23.2
  Top Layer w0.1: U22.1@25.25,8.75 C106.2@27.45,8.75 27.465,8.765 28.505,8.765 29.03,8.24 35.665,8.24 37,9.575 ; CN10.3@37,12.6 37,9.575 ; U20.10@43.075,10.4 43.075,9.704 41.971,8.6 37.975,8.6 37,9.575
NetC108_2: C108.2 U20.14 | length 1.2
  Top Layer w0.3: U20.14@45.075,10.4 45.075,10 45.4,9.675 C108.2@45.4,9.325
NetC109_2: C109.2 U20.15 | length 1.4
  Top Layer w0.3: U20.15@45.575,10.4 45.575,10.066 46.3,9.341 C109.2@46.3,9.325
NetC110_2: C110.2 U20.9 | length 2
  Top Layer w0.1: C110.2@41.55,9.225 41.55,10 41.95,10.4 U20.9@42.575,10.4
NetC111_2: C111.2 U20.16 | length 3.2
  Top Layer w0.3: U20.16@46.075,10.4 46.625,10.4 47.575,9.45 47.575,9.25 C111.2@48.325,8.5
NetC112_2: C112.2 CN9.18 F1.2 | length 4.5
  Top Layer w0.3: F1.2@89.225,6.4 C112.2@90.4,6.4 91.125,6.4 91.775,5.75 CN9.18@93.5,5.75
NetC113_1: C113.1 R103.2 | length 0.8
  Top Layer w0.3: C113.1@27.45,6.25 R103.2@27.45,7.05
NetC113_2: C113.2 CN10.4 U20.11 U22.6 | length 30
  Top Layer w0.2: CN10.4@37.5,3.1 38.525,3.1 38.575,3.15 38.575,7.875 39.05,8.35 42.075,8.35 43.575,9.85 U20.11@43.575,10.4
  Top Layer w0.3: U22.6@22.95,8.75 23.225,8.75 24.125,7.85 25.65,7.85 26.675,6.825 26.675,5.625 26.95,5.35 C113.2@27.45,5.35 27.95,4.85 27.95,4.425 29.275,3.1 CN10.4@29.5,3.1 CN10.4@37.5,3.1
NetC117_2: C117.2 C118.2 CN1.B1 U3.6 U24.1 | length 25.2
  Top Layer w0.5: U3.6@83.675,55.465 82.285,55.465 81.6,56.15 81.6,58.125 82.25,58.775 84.475,58.775 85.45,59.75 88.55,59.75 89.8,58.5 CN1.B1@89.99,58.5
  Bottom Layer w0.5: C118.2@83.95,58.025 84.4,58.475 C117.2@84.4,59.575 84.575,59.75 88.74,59.75 CN1.B1@89.99,58.5 90.025,58.5 91.575,60.05 U24.1@92.725,60.05
NetC123_2: C123.2 C124.2 CN1.T1 U3.7 U25.1 | length 16.8
  Top Layer w0.5: U3.7@83.675,56.735 84.435,56.735 86.2,58.5 CN1.T1@87.37,58.5
  Bottom Layer w0.5: C124.2@83.95,54.925 84.4,55.375 C123.2@84.4,56.475 84.575,56.475 84.795,56.695 85.525,57.425 85.525,57.95 86.075,58.5 CN1.T1@87.37,58.5 87.4,58.5 88.825,57.075 90.625,57.075 92,58.45 U25.1@92.725,58.45
NetC133_2: C133.2 C136.2 CN5.B1 U11.6 U27.1 | length 19.7
  Top Layer w0.5: U11.6@83.11,43.09 U11.6@83.675,43.09 84.985,43.09 86.325,41.75 88.74,41.75 CN5.B1@89.99,40.5
  Bottom Layer w0.5: C133.2@83.95,44.65 84.4,44.2 C136.2@84.4,43.125 ; C136.2@84.375,43.125 C136.2@84.4,43.125 ; CN5.B1@89.99,40.5 88.74,41.75 86.575,41.75 85.2,43.125 C136.2@84.4,43.125 ; CN5.B1@90.025,40.55 91.575,42.1 U27.1@92.725,42.1
NetC137_2: C137.2 C138.2 CN5.T1 U11.7 U28.1 | length 23.1
  Top Layer w0.5: U11.7@83.675,44.36 82.01,44.36 81.35,43.7 81.35,41.6 82.45,40.5 CN5.T1@87.37,40.5
  Bottom Layer w0.5: C138.2@83.95,40.65 84.4,41.1 C137.2@84.4,42.2 84.8,42.2 86.5,40.5 CN5.T1@87.37,40.5 ; CN5.T1@87.4,40.55 88.85,39.1 90.6,39.1 92,40.5 U28.1@92.725,40.5
NetC166_2: C166.2 C167.2 CN7.A4 CN7.A9 CN7.B4 CN7.B9 R150.1 U30.1 | length 29.7
  Top Layer w0.3: CN7.A4@91.42,26.525 92.62,26.525 CN7.B9@92.67,26.575 ; CN7.A9@91.42,29.025 92.62,29.025 CN7.B4@92.67,28.975
  Signal Layer 2 w0.6: CN7.B9@92.649,26.575 91.9,26.575 91.55,26.925 91.55,28.7 91.825,28.975 CN7.B4@92.67,28.975
  Signal Layer 3 w0.6: CN7.B9@92.649,26.575 92.125,26.575 91.825,26.875 91.825,28.525 92.275,28.975 CN7.B4@92.67,28.975
  Signal Layer 4 w0.6: CN7.B9@92.649,26.575 92.225,26.575 91.825,26.975 91.825,28.675 92.125,28.975 CN7.B4@92.67,28.975
  Bottom Layer w0.6: CN7.B9@92.67,26.575 92.125,26.575 91.25,25.7 91.25,22.725 91.65,22.325 94.675,22.325 95.25,22.9 95.25,24.8 U30.1@95.025,25.025
  Bottom Layer w1: U30.1@95.025,25.025 C167.2@96.27,25.025 ; C167.2@96.275,25.025 C167.2@96.27,25.025 ; R150.1@99.225,25.025 C166.2@97.625,25.025 C167.2@96.27,25.025
NetC183_2: C183.2 CN8.5 CN8.6 | length 4.4
  Bottom Layer w0.3: C183.2@12.4,13.875 12.41,13.865 CN8.6@13.75,13.865 14.385,14.5 15.655,14.5 CN8.5@16.29,15.135
NetC185_1: C185.1 C187.2 SB21.2 U34.1 U34.3 | length 9.7
  Bottom Layer w0.4: C187.2@79.425,10.675 80,10.675 80.45,10.225 U34.1@80.8,10.225 80.8,11.5 80.425,11.875 SB21.2@80.35,11.875 ; SB21.2@80.275,11.875 SB21.2@80.35,11.875 ; U34.3@82.7,10.225 82.7,11.5 C185.1@83.05,11.85 83.05,12.6 82.75,12.9 80.625,12.9 80.35,12.625 SB21.2@80.35,11.875
NetC189_2: C189.2 U34.4 | length 1.6
  Bottom Layer w0.4: C189.2@82.225,6.625 82.225,7.15 82.7,7.625 U34.4@82.7,8.025
NetC300_2: C300.2 R304.2 X6.4 | length 8.8
  Top Layer w0.1: C300.2@51.975,18.475 52.725,19.225 53.1,19.225 X6.4@53.2,19.325 ; C300.2@52.05,18.325 52.5,17.875 53.649,17.875 54.074,17.45 54.925,17.45 55.28,17.095 56.455,17.095 56.761,17.4 57.85,17.4 58.3,17.85 R304.2@58.3,18
NetCN8_11: CN8.11 R157.1 | length 1.5
  Bottom Layer w0.3: R157.1@1.8,21.125 1.805,21.13 CN8.11@3.34,21.13
NetCN8_12: CN8.12 R156.2 U18.32 | length 35.3
  Top Layer w0.1: CN8.12@3.34,18.59 4.34,19.59 4.34,23.098 7.657,26.415 13.032,26.415 14.542,27.925 23.35,27.925 24.1,27.175 24.1,25.275 24.625,24.75 25.225,24.75 25.825,24.15 U18.32@26.85,24.15
  Bottom Layer w0.3: CN8.12@3.34,18.59 4.95,20.2 R156.2@4.95,21.125
NetCN8_13: CN8.13 R163.2 U18.33 | length 41.7
  Top Layer w0.1: CN8.13@3.34,10.41 3.34,17.09 4.54,18.29 4.54,23.015 7.74,26.215 13.115,26.215 14.625,27.725 23.267,27.725 23.9,27.092 23.9,25.192 24.542,24.55 25.142,24.55 25.742,23.95 26.375,23.95 26.575,23.75 U18.33@26.85,23.75
  Bottom Layer w0.3: R163.2@1.8,10.425 3.325,10.425 CN8.13@3.34,10.41
NetCN8_14: CN8.14 R162.2 | length 3.2
  Bottom Layer w0.3: CN8.14@3.34,7.87 4.95,9.48 R162.2@4.95,10.425
NetCN13_8: CN13.8 R4.1 | length 2.3
  Top Layer w0.3: R4.1@65.784,59.286 66.839,59.286 v1(66.853,59.3)
  Bottom Layer w0.3: CN13.8@65.784,59.736 66.22,59.3 v1(66.853,59.3)
NetCN15_10: CN15.10 R13.2 | length 10.4
  Top Layer w0.1: v1(13.25,51.575) 13.9,52.225 R13.2@15.15,52.225
  Bottom Layer w0.1: CN15.10@5.4,52.225 9.689,52.225 10.364,51.55 13.275,51.55 v1(13.25,51.575)
NetCN17_5: CN17.5 SB23.2 SB24.2 | length 10
  Bottom Layer w0.3: CN17.5@28.7,11.475 32.275,11.475 32.775,10.975 32.775,9.525 34.35,7.95 SB24.2@35.025,7.95 SB23.2@36.425,7.95
NetCN17_6: CN17.6 SB25.2 SB26.2 | length 10.7
  Bottom Layer w0.3: CN17.6@26.16,14.904 26.16,12.635 27.475,11.32 27.475,9.25 28.775,7.95 SB26.2@30.025,7.95 SB25.2@31.425,7.95
NetD1_2: D1.2 D2.2 SB21.1 | length 9.6
  Bottom Layer w0.4: D2.2@77.495,11.875 78.875,11.875 ; SB21.1@79.175,11.875 78.875,11.875 ; D1.2@84.575,12.145 84.575,12.85 83.925,13.5 79.45,13.5 78.875,12.925 78.875,11.875
NetL2_1: L2.1 U4.11 | length 10.2
  Top Layer w0.3: L2.1@29.325,60.375 30.45,59.25 ; 30.488,59.213 30.45,59.25 ; L2.1@30.9,60.075 31.05,59.925 ; U4.11@31.05,57.925 31.05,58.65 ; 30.15,59.85 30.45,59.85 ; 30.15,59.85 30.15,59.8 30.45,59.5 ; 30.15,59.85 L2.1@30.15,60.35 30.65,59.85 ; 30.45,59.25 30.713,58.988 ; 30.45,59.25 30.45,59.5 ; 30.45,59.5 30.45,59.85 ; 30.45,59.85 30.65,59.85 ; 30.65,59.85 30.975,59.85 ; 30.65,59.85 30.813,59.687 ; 30.713,58.988 30.725,59 30.9,59 ; 30.713,58.988 31.05,58.65 ; 30.713,58.988 30.713,59.587 30.813,59.687 ; 30.813,59.687 30.975,59.85 ; 30.813,59.687 30.875,59.625 30.875,59.025 30.9,59 ; 30.9,59 31.05,59 ; 30.975,59.85 31.05,59.925 ; 31.05,58.65 31.05,59 ; 31.05,59 31.05,59.925
NetL3_1: L3.1 U4.7 | length 6.3
  Top Layer w0.3: U4.7@32.65,57.925 32.65,58.672 32.928,58.95 33.05,58.95 ; 33.475,59.15 33.675,59.35 L3.1@33.675,59.575 ; L3.1@33.575,59.597 L3.1@33.575,60.375 ; 33.05,58.95 33.65,58.95 33.925,59.225 33.925,60.05 L3.1@33.675,60.3 L3.1@33.675,59.575 ; 33.05,58.95 L3.1@33.675,59.575
NetL4_1: L4.1 U8.34 | length 2.8
  Top Layer w0.25: U8.34@6.125,49.825 6.125,50.175 6.575,50.625 L4.1@8.375,50.625
NetL5_1: L5.1 U4.25 | length 15.7
  Top Layer w0.3: U4.25@31.45,53.025 31.45,52.45 ; L5.1@32.225,49.5 31.612,50.113 ; L5.1@32.255,49.5 32.15,49.605 32.15,50 ; L5.1@32.875,49.7 32.875,50 ; 31.45,51.4 31.45,51.475 ; 31.45,51.4 31.45,50.275 31.612,50.113 ; 31.45,51.4 31.475,51.4 31.725,51.15 ; 31.45,51.475 31.45,52.45 ; 31.45,51.475 31.75,51.175 ; 31.45,52.45 31.45,52.284 31.75,51.984 31.75,51.675 ; 31.612,50.113 31.75,50.25 31.75,51.125 ; 31.612,50.113 31.612,51.037 31.725,51.15 ; 31.725,51.15 31.75,51.125 ; 31.725,51.15 31.75,51.175 ; 31.75,51.125 31.925,50.95 ; 31.75,51.125 31.75,51.175 ; 31.75,51.175 31.75,51.675 ; 31.75,51.675 31.925,51.5 31.925,50.95 ; 31.75,51.675 31.85,51.675 32.15,51.375 32.15,50.725 ; 31.925,50.95 32.15,50.725 ; 31.925,50.95 31.925,50.1 32.025,50 32.15,50 ; 32.15,50 32.4,50 ; 32.15,50 32.15,50.725 ; 32.15,50.725 32.437,50.438 ; 32.4,50 32.875,50 ; 32.4,50 32.4,50.4 32.437,50.438 ; 32.437,50.438 32.875,50
NetL6_1: L6.1 U4.29 | length 12
  Top Layer w0.3: U4.29@33.05,53.025 33.05,52.225 ; L6.1@36.337,50.488 35.16,50.488 34.974,50.674 34.14,51.507 33.912,51.507 ; 33.05,52.225 33.763,51.631 ; 33.05,52.225 33.17,52.225 33.763,51.631 ; 33.05,52.225 34.787,50.488 ; 33.763,51.631 33.887,51.507 33.912,51.507 ; 33.763,51.631 33.912,51.507 ; 34.787,50.488 35.025,50.25 36.375,50.25 35.867,50.758 35.058,50.758 34.787,50.488
NetL8_2: L8.2 U3.2 U11.2 | length 27.7
  Top Layer w0.6: v3@77.065,56.735 v3(77.075,56.725) ; L8.2@77.1,44.35 L8.2@77.11,44.36
  Top Layer w1: v3(76.325,56.725) v3(77.075,56.725) ; v3@76.336,45.339 77.089,45.339 77.1,45.35 L8.2@77.1,44.35 ; v3@77.065,56.735 U3.2@78.925,56.735 ; L8.2@77.11,44.36 U11.2@78.925,44.36
  Signal Layer 1 w0.6: v3(76.325,45.35) 77.102,45.35 v3(77.114,45.361) ; v3(76.325,56.725) v3(77.075,56.725)
  Signal Layer 2 w0.6: v3(76.325,45.35) 76.336,45.361 v3(77.114,45.361) ; v3(76.325,56.725) v3(77.075,56.725)
  Signal Layer 3 w1: 76.325,55.975 76.325,52.75 77.114,51.961 77.114,46.116 ; 76.325,55.975 v3(76.325,56.725) v3(77.075,56.725) 76.325,55.975 ; 77.114,46.116 v3(77.114,45.361) 76.359,45.361 77.114,46.116
  Signal Layer 4 w0.6: v3(76.325,45.35) 77.102,45.35 v3(77.114,45.361) ; v3(76.325,56.725) v3(77.075,56.725)
  Bottom Layer w0.6: v3(76.325,45.35) 77.102,45.35 v3(77.114,45.361) ; v3(76.325,56.725) v3(77.075,56.725)
NetL9_1: L9.1 R79.2 | length 1.2
  Top Layer w0.3: L9.1@59.45,21.85 59.575,21.725 R79.2@59.575,20.7
NetLD1_1: LD1.1 R21.1 | length 1.1
  Top Layer w0.2: LD1.1@61.125,45.8 61.425,46.1 R21.1@62.125,46.1
NetLD2_1: LD2.1 R41.1 | length 1.1
  Top Layer w0.6: LD2.1@8.95,37.225 R41.1@10.05,37.225
NetLD3_1: LD3.1 R67.2 U18.34 | length 18.8
  Top Layer w0.1: R67.2@13.5,25.3 13.6,25.3 14.25,25.95 14.25,26.725 15.05,27.525 23.184,27.525 23.7,27.009 23.7,25.109 24.459,24.35 25.059,24.35 25.659,23.75 26.15,23.75 26.55,23.35 U18.34@26.85,23.35
  Top Layer w0.3: LD3.1@12.275,25.3 R67.2@13.5,25.3
NetLD3_2: LD3.2 R66.2 | length 1.3
  Top Layer w0.3: R66.2@9.525,25.3 LD3.2@10.775,25.3
NetLD4_2: LD4.2 R89.1 | length 1.5
  Top Layer w0.1: LD4.2@80.875,10.15 R89.1@80.875,11.6
NetLD4_3: LD4.3 R90.1 | length 1.5
  Top Layer w0.1: LD4.3@82.375,10.15 R90.1@82.375,11.6
NetLD5_1: LD5.1 R105.1 | length 1
  Top Layer w0.3: LD5.1@47.3,5.775 R105.1@47.3,6.775
NetLD6_1: LD6.1 R106.1 | length 1
  Top Layer w0.3: LD6.1@55.35,5.775 R106.1@55.35,6.775
NetLD7_1: LD7.1 R107.2 | length 1
  Top Layer w0.3: LD7.1@63.825,5.775 R107.2@63.825,6.775
NetLD8_1: LD8.1 R108.2 | length 1.3
  Top Layer w0.3: LD8.1@68,5.5 R108.2@68,6.775
NetLD9_1: LD9.1 R114.1 | length 1.1
  Bottom Layer w0.3: LD9.1@70.225,56.475 R114.1@71.35,56.475
NetLD9_2: LD9.2 T4.3 | length 1.5
  Bottom Layer w0.3: T4.3@67.225,56.475 LD9.2@68.725,56.475
NetLE1_1: LE1.1 U18.30 | length 5.7
  Top Layer w0.2: v1(26.525,25.7) 26.7,25.7 27.2,25.2 U18.30@27.5,25.2
  Bottom Layer w0.2: LE1.1@23.075,27 23.075,26.2 LE1.1@23.675,25.6
  Bottom Layer w0.3: LE1.1@23.675,25.6 23.775,25.7 v1(26.525,25.7)
NetLNK1_1: LNK1.1 U4.9 | length 58.6
  Top Layer w0.2: v1(31.646,59.516) 31.85,59.312 U4.9@31.85,57.925
  Signal Layer 4 w0.2: v1@31.65,59.5 30.8,60.35 30.8,62.5 30.485,62.815 28.36,62.815 27.45,61.905 27.45,58.559 28.409,57.6 33.25,57.6 34.875,59.225 41.2,59.225 41.89,59.915 42.51,59.915 42.85,59.575 42.85,58.775 42.3,58.225 40.575,58.225 40.575,57.959 39.841,57.225 39.841,54.941 39.8,54.9 40.15,54.55 40.15,53.393 39.575,52.818 39.575,52.736 38.855,52.016 38.855,38.57 39.275,38.15 39.275,37.775 38.575,37.075 LNK1.1@38.575,33.525
NetLNK2_1: LNK2.1 U4.5 | length 42.9
  Top Layer w0.1: U4.5@33.45,57.925 33.45,58.237 34.338,59.125 36.95,59.125 37.1,59.275 v1(37.1,60.125)
  Signal Layer 3 w0.2: v1(37.1,60.125) 37.1,59.725 37.427,59.398 37.427,57.667 37.425,57.666 37.425,57.334 37.45,57.309 37.45,55.929 35.95,54.429 35.95,53.594 35.55,53.194 35.55,50.15 36.25,49.45 36.25,46.6 36.553,46.297 37.473,46.297 37.875,45.895 37.875,37.7 40.7,34.875 42.295,34.875 42.725,34.445 42.725,32.862 LNK2.1@46.287,29.3
NetQ1_2: Q1.2 Q1.5 Q1.6 R45.2 | length 3.9
  Top Layer w0.3: R45.2@11.875,34.675 11.875,34.825 12.15,35.1 Q1.6@12.15,35.925 Q1.5@12.15,36.575 Q1.2@14.05,36.575
NetR6_2: R6.2 U4.1 | length 6.8
  Top Layer w0.1: U4.1@35.05,57.925 35.05,57.875 35.82,57.875 35.87,57.925 38.055,57.925 38.405,57.575 38.836,57.575 39.036,57.775 40.8,57.775 40.925,57.9 40.925,58.35 R6.2@41,58.425
NetR9_2: R9.2 U4.37 | length 1.1
  Top Layer w0.2: R9.2@36.825,54.475 R9.2@36.9,54.475
  Top Layer w0.3: U4.37@35.8,54.475 R9.2@36.825,54.475
NetR12_1: R12.1 U4.33 | length 5.7
  Top Layer w0.3: U4.33@34.65,53.025 34.65,52.561 35.036,52.175 36.65,52.175 36.975,51.85 R12.1@39.625,51.85
NetR15_2: R15.2 U5.L8 | length 3.3
  Top Layer w0.12: U5.L8@52.43,47.94 52.81,48.32 53.934,48.32 54.18,48.566 54.18,48.651 54.694,49.165 55.03,49.165 R15.2@55.155,49.29
NetR18_1: R18.1 U7.27 | length 1.2
  Top Layer w0.3: R18.1@63.025,47.15 U7.27@64.25,47.15
NetR21_2: R21.2 R23.2 U7.28 | length 3.1
  Top Layer w0.2: R23.2@63.025,45.05 R21.2@63.025,46.1 63.325,46.4 U7.28@65,46.4
NetR24_2: R24.2 U7.35 | length 2.1
  Top Layer w0.1: U7.35@68.5,46.4 68.5,45.675 68.75,45.425 69.05,45.425 69.5,44.975 R24.2@69.625,44.975
NetR31_2: R31.2 R32.1 U12.3 | length 3.6
  Top Layer w0.3: R31.2@75.525,41.725 R32.1@76.575,41.725 76.7,41.6 U12.3@76.7,39.2
NetR34_1: R34.1 U12.1 | length 3
  Top Layer w0.2: U12.1@77.7,39.2 77.7,39.425 78.1,39.825 79.55,39.825 79.95,40.225 R34.1@79.95,40.375
NetR35_1: R35.1 U12.5 | length 1.5
  Top Layer w0.2: R35.1@74.85,40.325 74.85,40.3 75.7,39.45 U12.5@75.7,39.2
NetR36_2: R36.2 U12.6 | length 1.8
  Top Layer w0.3: R36.2@73.425,39.2 U12.6@75.2,39.2
NetR38_1: R38.1 U13.K23 | length 3.6
  Top Layer w0.09: R38.1@47.95,39.17 47.95,38.66 48.575,38.035 48.873,38.035 49.08,37.828 U13.K23@49.08,36.19
NetR43_2: R43.2 U12.20 | length 1.6
  Top Layer w0.2: U12.20@78.35,36.55 78.521,36.55 78.85,36.221 78.85,36.05 79.35,35.55 R43.2@79.35,35.425
NetR44_2: R44.2 U13.AB18 | length 4.2
  Top Layer w0.1: U13.AB18@55.08,33.69 56.23,33.69 56.79,34.25 R44.2@59.025,34.25
NetR46_2: R46.2 U12.13 | length 1.2
  Top Layer w0.1: R46.2@75.075,34.275 75.2,34.4 U12.13@75.2,35.4
NetR58_2: R58.2 U18.27 | length 2.7
  Top Layer w0.1: U18.27@28.7,25.2 28.7,27.625 R58.2@28.875,27.8
NetR59_2: R59.2 U18.26 | length 3.7
  Top Layer w0.1: U18.26@29.1,25.2 29.1,27.2 29.7,27.8 R59.2@30.575,27.8
NetR60_2: R60.2 U18.25 | length 4.8
  Top Layer w0.1: U18.25@29.5,25.2 29.5,26.85 30.045,27.395 31.02,27.395 31.425,27.8 R60.2@32.275,27.8
NetR61_2: R61.2 U18.24 | length 6
  Top Layer w0.1: U18.24@29.9,25.2 29.9,26.725 30.37,27.195 32.495,27.195 33.075,27.775 R61.2@33.975,27.775
NetR62_2: R62.2 U18.23 | length 7.3
  Top Layer w0.1: U18.23@30.3,25.2 30.3,26.625 30.67,26.995 32.595,26.995 32.95,27.35 34.375,27.35 34.8,27.775 R62.2@35.675,27.775
NetR63_2: R63.2 U18.22 | length 8.5
  Top Layer w0.1: U18.22@30.7,25.2 30.7,26.4 31.095,26.795 32.678,26.795 33.033,27.15 34.458,27.15 34.633,27.325 36.05,27.325 36.5,27.775 R63.2@37.4,27.775
NetR64_2: R64.2 R69.1 U18.36 | length 8.2
  Top Layer w0.13: R64.2@21.575,25.875 21.575,25.75 22.175,25.15 22.175,24.425 R69.1@22.925,23.675 22.925,23.62 22.605,23.3 22.605,22.795 22.945,22.455 25.95,22.455 26.045,22.55 U18.36@26.85,22.55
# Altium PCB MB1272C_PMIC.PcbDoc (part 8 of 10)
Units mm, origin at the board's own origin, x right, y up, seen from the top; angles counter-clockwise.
Board outline 101 x 71 mm, 6 copper layers (Top Layer, Signal Layer 1, Signal Layer 2, Signal Layer 3, Signal Layer 4, Bottom Layer), stack 1.552 mm thick; 518 components, 478 nets, 2152 pads, 1871 vias.
Unrouted connection lines stored in the file: 3.

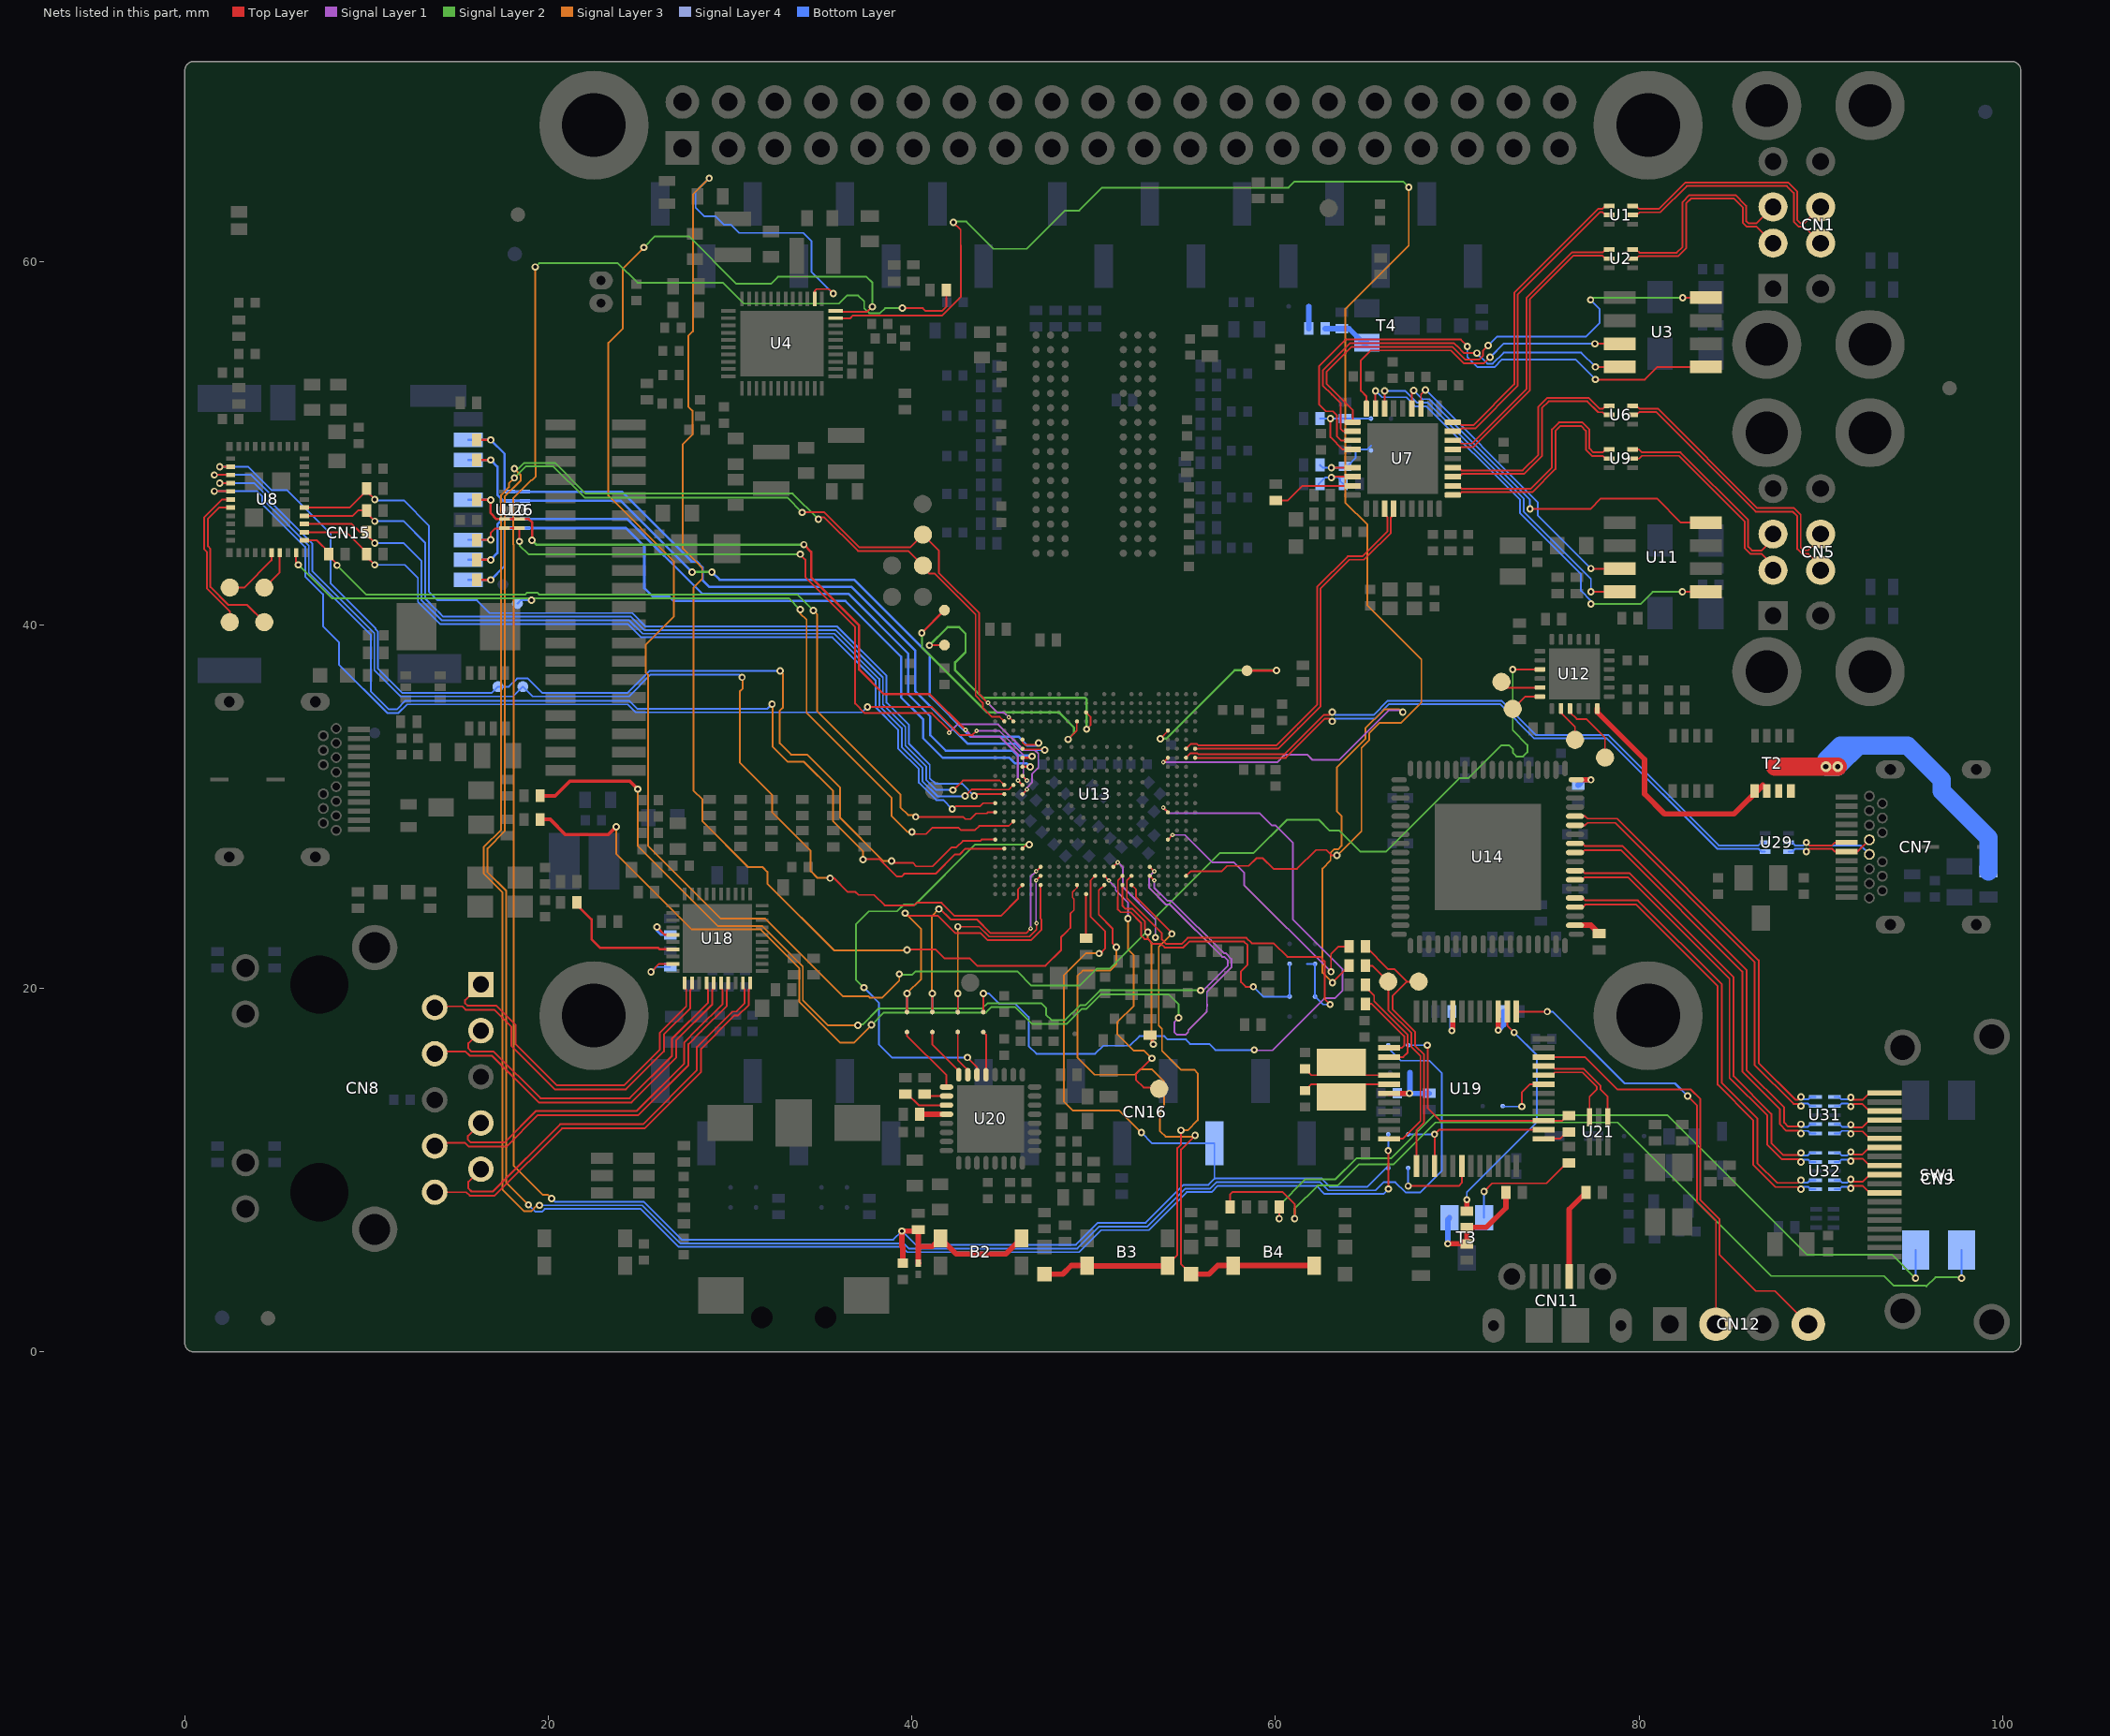
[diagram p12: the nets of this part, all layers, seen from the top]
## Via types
v1: diameter 0.4, hole 0.2, Top Layer to Bottom Layer, tented both sides, 884 vias
v2: diameter 0.25, hole 0.1, Top Layer to Signal Layer 1, tented top, 470 vias
v3: diameter 0.6, hole 0.3, Top Layer to Bottom Layer, tented both sides, 469 vias
v4: diameter 0.25, hole 0.1, Top Layer to Signal Layer 1, tented both sides, 46 vias
v5: diameter 0.25, hole 0.1, Top Layer to Bottom Layer, tented top, 2 vias

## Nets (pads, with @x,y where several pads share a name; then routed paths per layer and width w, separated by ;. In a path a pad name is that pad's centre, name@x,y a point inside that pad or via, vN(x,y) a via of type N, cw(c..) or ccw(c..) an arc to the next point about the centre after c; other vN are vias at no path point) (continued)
NetR68_2: R68.2 U18.37 | length 7.1
  Top Layer w0.13: R68.2@21.575,24.725 21.575,24.6 22.375,23.8 22.375,22.7 22.85,22.225 26.05,22.225 26.125,22.15 U18.37@26.85,22.15
NetR70_1: R70.1 U14.56 | length 1.5
  Top Layer w0.3: U14.56@76.475,23.475 77.35,23.475 R70.1@77.8,23.025
NetR71_1: R71.1 U13.L1 | length 2.4
  Top Layer w0.1: R71.1@49.575,22.75 49.58,22.755 U13.L1@49.58,25.19
NetR80_2: R80.2 U19.3 | length 5.8
  Top Layer w0.1: R80.2@64.95,20.2 64.95,20.075 65.425,19.6 65.425,19.3 67.275,17.45 67.275,16.475 67.025,16.225 U19.3@66.25,16.225
NetR81_1: R81.1 U19.2 | length 4.3
  Top Layer w0.1: R81.1@64.95,19.15 65.292,19.15 67.075,17.367 67.075,16.85 66.95,16.725 U19.2@66.25,16.725
NetR85_1: R85.1 U20.3 | length 2.5
  Top Layer w0.1: R85.1@39.65,14.175 39.775,14.175 40.375,13.575 U20.3@41.9,13.575
NetR86_1: R86.1 U20.2 | length 1.2
  Top Layer w0.1: R86.1@40.7,14.175 40.8,14.075 U20.2@41.9,14.075
NetR87_1: R87.1 U20.4 | length 1.5
  Top Layer w0.3: R87.1@40.425,13.075 U20.4@41.9,13.075
NetR93_2: R93.2 T3.2 | length 6.8
  Top Layer w0.1: v1(71.475,8.825) 71.925,9.275 74.9,9.275 76.025,10.4 R93.2@76.15,10.4
  Bottom Layer w0.1: T3.2@71.475,7.375 v1(71.475,8.825)
NetR99_2: R99.2 R104.1 R112.2 T3.1 | length 6.9
  Top Layer w0.3: v1(69.475,5.95) R112.2@70.525,5.95 R104.1@70.525,6.85 71.6,6.85 72.675,7.925 R99.2@72.675,8.775
  Bottom Layer w0.3: v1(69.475,5.95) 69.475,7.275 T3.1@69.575,7.375
NetR101_1: R101.1 SW1.3 | length 50.1
  Top Layer w0.1: R101.1@57.5,7.975 57.5,8.65 57.65,8.8 60.385,8.8 61.05,8.135 v1(61.05,7.325)
  Signal Layer 2 w0.1: v1(61.05,7.325) 61.05,7.875 62.325,9.15 63.425,9.15 64.6,10.325 66.5,10.325 68.8,12.625 78.825,12.625 87.275,4.175 93.475,4.175 94,3.65 95.75,3.65 95.8,3.6 96.3,4.1 97.7,4.1 v1(97.745,4.055)
  Bottom Layer w0.1: v1(97.745,4.055) SW1.3@97.745,5.6
NetR102_1: R102.1 SW1.4 | length 43.7
  Top Layer w0.1: v1(60.2,7.325) R102.1@60.2,7.975
  Signal Layer 2 w0.1: v1(60.2,7.325) 60.2,8.05 61.65,9.5 63.3,9.5 64.45,10.65 66.35,10.65 68.725,13.025 81.55,13.025 89.225,5.35 93.91,5.35 v1(95.205,4.055)
  Bottom Layer w0.1: v1(95.205,4.055) SW1.4@95.205,5.6
NetR119_2: R119.2 R120.2 T4.1 | length 2.6
  Bottom Layer w0.3: R120.2@62.725,56.3 R119.2@63.65,56.3 64.05,56.3 64.825,55.525 T4.1@65.025,55.525
NetR120_1: R120.1 SB6.2 | length 1.2
  Bottom Layer w0.3: R120.1@61.825,56.3 SB6.2@61.825,57.525
NetR127_1: R127.1 R129.2 SB7.2 U7.22 | length 5.3
  Top Layer w0.1: v1(63.025,51.35) 63.025,50.325 63.7,49.65 U7.22@64.25,49.65
  Bottom Layer w0.1: R129.2@62.45,51.35 v1(63.025,51.35) R127.1@63.825,51.35 SB7.2@65.25,51.35
NetR134_1: R134.1 R137.2 SB8.2 U7.24 | length 4.7
  Top Layer w0.1: v1(63.075,48.65) U7.24@64.25,48.65
  Bottom Layer w0.1: R137.2@62.45,48.8 62.6,48.65 v1(63.075,48.65) 63.75,48.65 R134.1@63.825,48.725 63.95,48.725 64.4,49.175 64.4,49.525 64.525,49.65 65.05,49.65 65.25,49.85
NetR139_2: R139.2 R140.1 U7.25 | length 3
  Top Layer w0.1: v1(63.075,48.1) 63.075,48.075 63.15,48.15 U7.25@64.25,48.15
  Bottom Layer w0.1: R140.1@62.375,47.675 62.375,47.75 62.725,48.1 v1(63.075,48.1) ; v1@63.05,48.125 63.45,48.125 63.55,48.025 63.55,47.925 R139.2@63.725,47.75
NetR149_2: R149.2 U14.72 | length 1.6
  Top Layer w0.3: U14.72@76.55,31.475 v1(77.35,31.475)
  Bottom Layer w0.3: R149.2@76.65,31.175 76.95,31.475 v1(77.35,31.475)
NetR150_2: R150.2 T2.5 T2.6 T2.7 T2.8 U12.18 | length 35.7
  Top Layer w0.3: U12.18@77.7,35.4 77.7,35.2 80.3,32.6 80.3,30.7 81.4,29.6 85.225,29.6 86.8,31.175
  Top Layer w1: 87.475,32.2 v3(90.275,32.2) v3(90.925,32.2)
  Signal Layer 1 w0.6: v3(90.275,32.2) v3(90.925,32.2)
  Signal Layer 2 w0.6: v3(90.275,32.2) v3(90.925,32.2)
  Signal Layer 3 w0.6: v3(90.275,32.2) v3(90.925,32.2)
  Signal Layer 4 w0.6: v3(90.275,32.2) v3(90.925,32.2)
  Bottom Layer w1: R150.2@99.225,26.425 99.225,28.275 96.65,30.85 96.65,31.475 94.775,33.35 92.075,33.35 ; 92.075,33.35 v3(90.925,32.2) v3(90.275,32.2) 90.275,32.55 91.075,33.35 92.075,33.35
NetR153_2: R153.2 U18.35 | length 2.1
  Top Layer w0.13: v1(25.975,23.375) 26.4,22.95 U18.35@26.85,22.95
  Bottom Layer w0.13: v1(25.975,23.375) 25.975,23.175 26.2,22.95 R153.2@26.7,22.95
NetR155_1: R155.1 U18.39 | length 2.6
  Top Layer w0.1: v1(25.65,20.9) 26.1,21.35 U18.39@26.85,21.35
  Bottom Layer w0.1: v1(25.65,20.9) 25.925,21.175 R155.1@26.7,21.175
NetR159_2: R159.2 U19.44 | length 2.1
  Top Layer w0.3: v1(69.7,17.675) 69.75,17.725 U19.44@69.75,18.725
  Bottom Layer w0.3: v1(69.7,17.675) R159.2@69.7,18.725
NetR600_2: R600.2 U7.26 | length 4.6
  Top Layer w0.1: R600.2@60.006,46.85 60.675,46.85 61.475,47.65 U7.26@64.25,47.65
NetSB9_1: SB9.1 SB12.2 U13.T3 | length 19.9
  Top Layer w0.09: 51.83,24.94 51.83,25.94 U13.T3@52.08,26.19
  Top Layer w0.1: 51.83,24.94 51.841,24.94 53.747,23.034 53.747,22.684 53.981,22.45 54.846,22.45 55.171,22.775 58.395,22.775 58.691,22.479 59.866,22.479 59.87,22.475 59.912,22.475 60.647,21.74 62.455,21.74 62.705,21.49 62.705,19.416 v1(63.006,19.115)
  Bottom Layer w0.1: 61.725,21.35 SB9.1@62.175,21.35 SB12.2@62.175,19.55 62.61,19.115 v1(63.006,19.115)
NetSB10_1: SB10.1 SB11.2 U13.R3 | length 17.6
  Top Layer w0.09: 51.33,25.04 51.33,25.94 U13.R3@51.58,26.19
  Top Layer w0.1: 51.33,25.04 51.33,24.34 51.48,24.19 52.025,24.19 52.605,23.61 52.605,22.902 52.793,22.715 52.975,22.715 53.24,22.45 53.699,22.45 53.899,22.25 54.929,22.25 55.254,22.575 58.27,22.575 58.46,22.385 58.46,21.295 58.105,20.94 58.105,20.34 58.355,20.09 v1(58.78,20.09)
  Bottom Layer w0.1: v1(58.78,20.09) 59.32,19.55 SB11.2@60.775,19.55 SB10.1@60.775,21.35
NetTP6_1: TP6.1 U8.17 | length 3.3
  Top Layer w0.1: TP6.1@2.475,42.05 3.275,42.05 4.775,43.55 U8.17@4.775,43.975
NetTP7_1: TP7.1 U8.18 | length 2.3
  Top Layer w0.1: TP7.1@4.375,42.05 5.225,42.9 U8.18@5.225,43.975
NetTP10_1: TP10.1 U13.K20 | length 14.8
  Top Layer w0.09: v1(48.59,33.7) 49.07,34.18 49.07,34.69 U13.K20@49.08,34.69
  Top Layer w0.12: v1(40.54,39.56) TP10.1@41.79,40.81 ; U13.K20@49.08,34.596 U13.K20@49.08,34.69
  Signal Layer 2 w0.12: v1@40.553,39.565 40.553,38.752 44.11,35.195 48.069,35.195 48.91,34.354 48.91,34.056 v1@48.6,33.746
NetTP11_1: TP11.1 U8.6 | length 8.2
  Top Layer w0.1: TP11.1@2.475,40.15 2.475,40.742 1.213,42.004 1.213,44.025 1.074,44.164 1.074,45.927 2.047,46.9 U8.6@2.525,46.9
NetTP12_1: TP12.1 U8.7 | length 9.1
  Top Layer w0.1: 1.274,44.795 1.274,44.326 1.413,44.187 1.413,42.087 2.4,41.1 3.425,41.1 TP12.1@4.375,40.15 ; 1.274,45.405 1.274,45.844 1.88,46.45 U8.7@2.525,46.45 ; 1.275,44.796 1.275,45.404
NetTP13_1: TP13.1 U13.L21 | length 16.3
  Top Layer w0.09: v1(40.96,38.87) 40.98,38.89 TP13.1@41.79,38.89 ; U13.L21@49.58,35.19 49.83,34.94 49.83,34.48 v1(49.61,34.26)
  Signal Layer 2 w0.12: 42.915,36.96 43.88,35.995 47.77,35.995
  Signal Layer 2 w0.127: v1@40.97,38.875 41.96,39.865 42.6,39.865 42.95,39.515 42.95,38.505 42.38,37.935 42.38,37.495 42.915,36.96 ; 47.77,35.995 49.52,35.995 49.62,35.895 v1@49.62,34.265
NetTP14_1: TP14.1 U13.Y19 | length 10.2
  Top Layer w0.09: v1(53.66,33.73) 54.08,34.15 U13.Y19@54.08,34.19
  Top Layer w0.127: TP14.1@58.43,37.48 60.05,37.48 v1(60.06,37.49)
  Signal Layer 2 w0.127: v1@53.67,33.735 53.99,33.735 57.75,37.495 v1@60.07,37.495
NetTP15_1: TP15.1 U12.11 | length 2.3
  Top Layer w0.1: TP15.1@72.43,36.865 72.745,36.55 U12.11@74.55,36.55
NetTP16_1: TP16.1 U12.12 | length 1.8
  Top Layer w0.1: TP16.1@73.05,35.375 73.725,36.05 U12.12@74.55,36.05
NetTP17_1: TP17.1 U12.14 | length 2
  Top Layer w0.1: U12.14@75.7,35.4 75.7,35.175 76.475,34.4 TP17.1@76.475,33.675
NetTP18_1: TP18.1 U12.15 | length 3.8
  Top Layer w0.1: U12.15@76.2,35.4 76.2,35.2 76.575,34.825 77.1,34.825 78.125,33.8 TP18.1@78.125,32.7
NetTP23_1: TP23.1 U13.N3 | length 15.3
  Top Layer w0.1: U13.N3@50.58,26.19 v2(50.83,25.94) ; v1(53.2,16.15) 52.325,15.275 52.325,14.97 52.747,14.547 53.528,14.547 TP23.1@53.6,14.475
  Signal Layer 1 w0.1: v2(50.83,25.94) 51.205,25.565 51.205,25.404 51.88,24.728 v1(51.88,23.84)
  Signal Layer 3 w0.1: v1(51.88,23.84) 51.88,22.145 52.2,21.825 52.2,19.05 51.3,18.15 51.3,17.475 52.2,16.575 52.775,16.575 v1(53.2,16.15) 53.2,16.165 v1@53.165,16.2
NOTOC1: U7.13 U11.8 | length 20.9
  Top Layer w0.1: U7.13@67.5,51.9 67.5,52.8 v1(67.6,52.9) ; v1(74,46.375) 77.325,46.375 77.9,46.95 80.975,46.95 82.295,45.63 U11.8@83.675,45.63
  Bottom Layer w0.1: v1(67.6,52.9) 68.079,52.421 68.471,52.421 74,46.892 v1(74,46.375)
NOTOC2: U7.17 U11.5 | length 25.4
  Top Layer w0.1: U7.17@65.5,51.9 v1(65.5,52.875) ; v1(82.38,41.82) U11.5@83.675,41.82
  Signal Layer 2 w0.1: v1(77.35,41.15) 80.075,41.15 80.745,41.82 v1(82.38,41.82)
  Bottom Layer w0.1: v1(65.5,52.875) 65.505,52.875 65.855,52.525 67,52.525 67.001,52.524 67.199,52.524 67.701,52.021 68.305,52.021 73.45,46.876 73.45,46.147 76.8,42.797 76.8,41.88 77.35,41.33 v1(77.35,41.15)
NOTOC3: U3.8 U7.19 | length 28.1
  Top Layer w0.1: U7.19@64.25,51.15 64.25,51.819 62.8,53.269 62.8,53.917 64.183,55.3 69.733,55.3 70.433,54.6 71.22,54.6 71.425,54.805 71.425,55.1 v1(71.7,55.375) ; v1(82.4,58) 82.405,58.005 U3.8@83.675,58.005
  Signal Layer 2 w0.1: v1(77.33,57.881) 77.449,58 v1(82.4,58)
  Bottom Layer w0.1: v1(71.7,55.375) 72.175,55.85 77.075,55.85 77.825,56.6 77.825,57.386 v1(77.33,57.881)
NOTOC4: U3.5 U7.21 | length 29.3
  Top Layer w0.1: U7.21@64.25,50.15 63.6,50.15 63.375,50.375 63.375,51.534 63.159,51.75 62.764,51.75 62.4,52.114 62.4,54.25 63.85,55.7 70.2,55.7 70.575,55.325 v1(70.55,55.325) ; v1(77.6,53.5) 80.325,53.5 81.02,54.195 U3.5@83.675,54.195
  Bottom Layer w0.1: v1(70.55,55.325) 70.55,54.75 71.125,54.175 72.033,54.175 72.458,54.6 76.5,54.6 v1(77.6,53.5)
NRST: B2.1 B2.2 C115.2 CN16.3 R6.1 R109.1 SB22.2 U13.M3 U35.1 | length 164.8
  Top Layer w0.09: 49.83,24.875 49.83,25.94 U13.M3@50.08,26.19
  Top Layer w0.1: v1(39.475,57.425) 40.6,57.425 40.75,57.275 41.642,57.275 41.9,57.533 R6.1@41.9,58.425 ; 49.83,24.875 49.83,23.934 50.074,23.69 50.075,23.69 50.63,23.135 50.63,22.2 50.475,22.045 50.475,22.035 50.305,21.865 50.3,21.87 v1(50.3,21.925)
  Top Layer w0.3: C115.2@39.5,4.875 39.5,5.75 39.45,5.8 v1(39.45,6.65) 40.275,6.65 R109.1@40.35,6.725 40.35,5.8 ; U35.1@40.375,4.887 40.35,4.912 40.35,5.8 ; B2.2@46.025,6.25 45.165,5.39 42.435,5.39 B2.1@41.575,6.25 41.125,5.8 40.35,5.8
  Signal Layer 2 w0.1: v1(19.28,59.69) 19.493,59.903 23.822,59.903 24.9,58.825 29.6,58.825 30.75,57.675 35.975,57.675 36.425,58.125 37.05,58.125 37.375,57.8 37.375,57.425 37.65,57.15 38.25,57.15 38.525,57.425 v1(39.475,57.425)
  Signal Layer 3 w0.1: v1(19.28,59.69) 19.28,48.69 19.305,48.665 19.305,48.17 19.1,47.965 19.066,47.965 18.06,46.959 18.06,44.445 18.084,44.421 18.084,10.264 19.708,8.64 19.98,8.64 v1(20.18,8.44) ; v1(50.3,21.925) 49.56,21.925 48.35,20.715 48.35,13.775 48.85,13.275 51.4,13.275 v1@52.625,12.05
  Bottom Layer w0.1: v1(20.18,8.44) 20.355,8.265 25.247,8.265 27.337,6.175 38.975,6.175 v1(39.45,6.65) 40.21,5.89 49.023,5.89 50.233,7.1 52.863,7.1 54.953,9.19 56.315,9.19 56.65,9.525 56.64,9.535 ; v1(52.625,12.075) 53.225,11.475 CN16.3@56.64,11.475 56.64,9.535 ; SB22.2@66.2,10.125 66.1,10.125 65.065,9.09 62.988,9.09 62.543,9.535 56.64,9.535
OSC_IN: C98.1 U19.5 X5.2 | length 5.3
  Top Layer w0.1: C98.1@61.625,15.575 61.975,15.225 62.925,15.225 X5.2@63.625,15.925 64.325,15.225 U19.5@66.25,15.225
OSC_OUT: C99.1 U19.6 X5.1 | length 5.3
  Top Layer w0.1: C99.1@61.625,14.375 61.975,14.725 62.925,14.725 X5.1@63.625,14.025 64.325,14.725 U19.6@66.25,14.725
PA0_WKUP: U4.43 U13.AB3 | length 91.1
  Top Layer w0.09: U13.AB3@55.08,26.19 55.33,26.44 56.08,26.44
  Top Layer w0.1: U4.43@35.8,56.875 36.614,56.875 36.764,57.025 41.675,57.025 42.7,58.05 42.7,60.86 42.68,60.88 42.68,61.742 v1(42.28,62.142) ; 56.08,26.44 57.036,26.44 57.336,26.74 58.53,26.74 58.955,27.165 59.305,27.165 59.891,26.579 61.186,26.579 62.222,27.615 62.8,27.615 63.1,27.315 v1(63.38,27.315)
  Signal Layer 2 w0.1: v1(42.28,62.142) 42.28,62.19 42.992,62.19 44.492,60.69 46.318,60.69 48.418,62.79 49.205,62.79 50.47,64.055 60.722,64.055 61.057,64.39 67.015,64.39 v1(67.33,64.075)
  Signal Layer 3 w0.1: v1(63.38,27.315) 63.388,27.315 64.73,28.657 64.73,33.232 65.145,33.647 65.145,34.025 65.735,34.615 66.91,34.615 68.025,35.73 68.025,38.094 65.055,41.064 65.055,45.515 63.83,46.74 63.83,57.365 67.33,60.865 v1(67.33,64.075)
PA13: B4.1 B4.2 LD6.2 U13.N2 | length 37.4
  Top Layer w0.1: U13.N2@50.58,25.69 50.28,25.39 50.28,24.051 51.03,23.301 51.03,22.495 v1(51.25,22.275) ; LD6.2@55.35,4.275 54.8,4.825 54.8,11.135 v1(55.58,11.915)
  Top Layer w0.3: LD6.2@55.35,4.275 56.35,4.275 56.825,4.75 B4.2@57.675,4.75 B4.1@62.125,4.75
  Signal Layer 3 w0.1: v1(51.25,22.275) 51.25,21.335 50.89,20.975 49.4,20.975 49.1,20.675 49.1,16.2 50.05,15.25 52.275,15.25 52.575,15.55 53.195,15.55 53.875,14.87 53.875,13.536 53.65,13.311 53.65,12.14 53.68,12.11 53.95,11.84 55.505,11.84 v1(55.58,11.915)
PA14: B3.1 B3.2 LD5.2 U13.T2 | length 31.6
  Top Layer w0.09: U13.T2@52.08,25.69 52.33,25.44 52.33,25.065
  Top Layer w0.1: 52.33,25.065 52.33,25.017 54.297,23.05 v1(54.297,23) ; B3.1@54.075,4.75 54.075,4.815 54.6,5.34 54.6,11.218 54.805,11.423 v1(54.805,12.19)
  Top Layer w0.3: LD5.2@47.3,4.275 48.3,4.275 48.775,4.75 B3.2@49.625,4.75 49.65,4.725 53.935,4.725 54.075,4.585 B3.1@54.075,4.75
  Signal Layer 3 w0.1: v1(54.297,23) 53.575,22.278 53.575,17.949 53.755,17.769 53.755,16.567 54.797,15.525 55.525,15.525 55.725,15.325 55.725,12.75 55.165,12.19 v1(54.805,12.19)
PMIC_WAKEUP: U4.2 U13.K2 | length 78.9
  Top Layer w0.09: 48.455,23.065 48.715,23.325 48.715,24.106 48.915,24.306 48.915,24.916 48.83,25.001 48.83,25.294 49.08,25.544 U13.K2@49.08,25.69
  Top Layer w0.1: U4.2@34.65,57.925 34.65,58.375 34.75,58.475 35.45,58.475 v1@35.675,58.25 ; v1(39.73,22.115) 39.78,22.065 39.855,22.14 41.305,22.14 41.8,21.645 43.194,21.645 43.589,21.25 47.345,21.25 48.205,22.11 48.205,22.815 48.455,23.065
  Signal Layer 3 w0.1: v1(28.85,64.575) 27.95,63.675 27.95,56.153 27.7,55.903 27.7,52.011 27.925,51.786 27.925,50.47 27.401,49.947 27.401,44.197 28.462,43.136 28.462,42.529 27.98,42.047 27.98,30.89 28.475,30.395 28.475,29.195 30.995,26.675 31.786,26.675 32.05,26.411 32.05,25.756 35.716,22.09 39.705,22.09 v1(39.73,22.115)
  Bottom Layer w0.1: v1(28.85,64.575) 28.1,63.825 28.1,62.955 28.579,62.476 29.201,62.476 29.652,62.025 30.045,62.025 30.506,61.564 34.031,61.564 34.475,61.12 34.475,59.425 v1(35.675,58.225)
PRTPWR1: U7.12 U11.3 | length 16.3
  Top Layer w0.1: U7.12@68,51.9 68,52.675 v1(68.25,52.925) ; v1(77.35,43.1) 77.36,43.09 U11.3@78.925,43.09
  Bottom Layer w0.1: v1(68.25,52.925) 74.425,46.75 74.425,46.025 v1(77.35,43.1)
PRTPWR2: U7.16 U11.4 | length 19.3
  Top Layer w0.1: U7.16@66,51.9 v1(66,52.875) ; v1(77.35,41.825) 78.92,41.825 U11.4@78.925,41.82
  Bottom Layer w0.1: v1(66,52.875) 67.13,52.875 67.784,52.221 68.388,52.221 73.65,46.959 73.65,46.23 77.35,42.53 v1(77.35,41.825)
PRTPWR3: U3.3 U7.18 | length 18
  Top Layer w0.1: U7.18@65,51.9 65,52.575 64.7,52.875 64.7,54.559 65.241,55.1 69.65,55.1 70.35,54.4 71.475,54.4 v1(71.8,54.725) ; v1(77.575,55.465) U3.3@78.925,55.465
  Bottom Layer w0.1: v1(71.8,54.725) 72.54,55.465 v1(77.575,55.465)
PRTPWR4: U3.4 U7.20 | length 22.3
  Top Layer w0.1: U7.20@64.25,50.65 63.725,50.65 63.575,50.8 63.575,52.211 63.111,52.675 63.1,52.675 62.6,53.175 62.6,54 64.1,55.5 69.816,55.5 69.966,55.35 69.975,55.35 70.375,54.95 v1(71.075,54.95) ; v1(77.6,54.195) U3.4@78.925,54.195
  Bottom Layer w0.1: v1(71.075,54.95) 71.65,54.375 71.95,54.375 72.55,54.975 76.82,54.975 v1(77.6,54.195)
PWR_EXT: R158.1 U19.39 | length 2.2
  Top Layer w0.3: v1(72.25,17.7) U19.39@72.25,18.725
  Bottom Layer w0.3: v1(72.25,17.7) 72.55,18 R158.1@72.55,18.725
PWR_ON: R302.2 U4.44 U13.R2 | length 97.2
  Top Layer w0.1: U4.44@35.8,57.275 35.85,57.225 37.525,57.225 37.8,57.5 v1(37.825,57.5) ; U13.R2@51.58,25.69 51.58,24.54 51.73,24.39 52.108,24.39 52.805,23.693 52.805,23.265 v1(52.98,23.09) ; R302.2@53.245,17.45 53.245,16.895 v1(53.275,16.925)
  Signal Layer 2 w0.1: v1(25.255,60.765) 25.865,61.375 27.739,61.375 30.349,58.766 32.241,58.766 32.625,59.15 37.5,59.15 37.825,58.825 v1(37.825,57.5) ; v1(39.305,20.79) 39.355,20.74 40,20.74 40.2,20.94 45.785,20.94 46.575,20.15 49.23,20.15 50.155,21.075 50.877,21.075 52.892,23.09 v1(52.98,23.09)
  Signal Layer 3 w0.1: v1(25.255,60.765) 24.1,59.61 24.1,56.322 23.3,55.522 23.3,47.108 26.9,43.508 26.9,40.45 25.35,38.9 25.35,37.387 25.475,37.262 25.475,27.845 29.48,23.84 31.934,23.84 36.199,19.575 37.603,19.575 37.678,19.5 38.375,19.5 39.305,20.43 v1(39.305,20.79) ; v1(52.98,23.09) 52.98,22.71 53.18,22.51 53.18,21.655 53.175,21.65 53.175,17.025 v1(53.275,16.925)
RJ45_D1_N: CN8.2 U18.2 | length 20.4
  Top Layer w0.1: CN8.2@13.75,18.945 13.817,19.012 15.262,19.012 15.45,18.825 17.025,18.825 17.97,17.88 17.97,16.83 20.355,14.445 24.27,14.445 26.355,16.53 26.355,17.455 27.815,18.915 27.815,19.915 27.9,20 U18.2@27.9,20.3
RJ45_D1_P: CN8.1 U18.1 | length 20.3
  Top Layer w0.1: CN8.1@16.29,19.61 CN8.1@16.29,20.215 15.425,19.35 15.425,19.175 15.545,19.055 17.12,19.055 18.2,17.975 18.2,16.925 20.45,14.675 24.175,14.675 26.125,16.625 26.125,17.55 27.585,19.01 27.585,19.94 27.5,20.025 U18.1@27.5,20.3
RJ45_D2_N: CN8.4 U18.5 | length 20.5
  Top Layer w0.1: CN8.4@13.75,16.405 13.882,16.537 15.437,16.537 15.68,16.295 16.905,16.295 19.475,13.725 24.575,13.725 27.03,16.18 27.03,17.13 29.015,19.115 29.015,19.915 29.1,20 U18.5@29.1,20.3
RJ45_D2_P: CN8.3 U18.4 | length 19.9
  Top Layer w0.1: CN8.3@16.7,17.675 CN8.3@16.29,17.675 15.6,16.985 15.6,16.7 15.775,16.525 17,16.525 19.57,13.955 24.48,13.955 26.8,16.275 26.8,17.225 28.785,19.21 28.785,19.915 28.7,20 U18.4@28.7,20.3
RJ45_D3_N: CN8.8 U18.7 | length 21.4
  Top Layer w0.1: CN8.8@13.75,11.325 13.937,11.512 15.412,11.512 15.63,11.295 17.684,11.295 19.414,13.025 24.95,13.025 27.705,15.78 27.705,16.93 28.42,17.645 29.815,19.04 29.815,19.915 29.9,20 U18.7@29.9,20.3
RJ45_D3_P: CN8.7 U18.6 | length 20.3
  Top Layer w0.1: CN8.7@16.29,12.595 15.575,11.88 15.575,11.675 15.725,11.525 17.588,11.525 19.318,13.255 24.855,13.255 27.475,15.875 27.475,17.025 28.19,17.74 29.585,19.135 29.585,19.915 29.5,20 U18.6@29.5,20.3
RJ45_D4_N: CN8.10 U18.10 | length 23.7
  Top Layer w0.1: CN8.10@13.75,8.785 15.49,8.785 15.68,8.595 17.045,8.595 20.75,12.3 25.3,12.3 28.405,15.405 28.405,16.68 30.225,18.5 30.425,18.5 31.025,19.1 31.025,19.95 31.1,20.025 U18.10@31.1,20.3
RJ45_D4_P: CN8.9 U18.9 | length 22.8
  Top Layer w0.1: CN8.9@16.29,10.055 15.6,9.365 15.6,9 15.775,8.825 16.95,8.825 20.655,12.53 25.205,12.53 28.175,15.5 28.175,16.775 30.13,18.73 30.33,18.73 30.795,19.195 30.795,19.93 30.7,20.025 U18.9@30.7,20.3
SAI2_FSA: SB1.1 U20.1 | length 3.9
  Top Layer w0.1: SB1.1@39.725,17.6 39.725,17.4 41.9,15.225 U20.1@41.9,14.575
SAI2_FSAM: SB1.2 SB16.2 U13.F2 | length 18
  Top Layer w0.1: v1(39.63,24.14) 39.78,23.99 41.435,23.99 42.38,23.045 43.773,23.045 44.169,22.65 46.548,22.65 47.13,23.233 47.13,23.79 47.08,23.84 U13.F2@47.08,25.69 ; SB1.2@39.725,18.7 v1(39.725,19.725)
  Signal Layer 3 w0.1: v1(39.63,24.14) 40.505,23.265 40.505,20.505 v1(39.725,19.725)
  Bottom Layer w0.1: SB16.2@39.725,18.7 v1(39.725,19.725)
SAI2_MCLKA: U13.D6 U20.30 | length 25.3
  Top Layer w0.1: v1(43.05,16.2) 43.575,15.675 U20.30@43.575,15.25 ; U13.D6@46.08,27.69 46.28,27.89 46.43,27.89 46.476,27.936 v1(46.455,27.915)
  Signal Layer 2 w0.1: v1(37.355,20.04) 36.93,20.464 36.93,23.535 37.635,24.24 39.18,24.24 39.555,24.615 40.173,24.615 43.474,27.915 v1(46.455,27.915)
  Bottom Layer w0.1: v1(37.355,20.04) 37.644,19.75 38.18,19.214 38.18,16.915 38.895,16.2 v1(43.05,16.2)
SAI2_SCKA: SB3.1 U20.31 | length 2.6
  Top Layer w0.09: SB3.1@42.525,17.6 42.525,16.05 43.075,15.5 U20.31@43.075,15.25
SAI2_SCKAM: SB3.2 SB14.2 U13.F3 | length 13.5
  Top Layer w0.09: v1(42.525,23.395) 43.699,23.395 44.249,22.845 46.467,22.845 46.855,23.233 v4(46.855,23.59)
  Top Layer w0.1: SB3.2@42.525,18.7 v1(42.525,19.725) ; v2(46.83,25.94) U13.F3@47.08,26.19
  Signal Layer 1 w0.09: v2(46.83,25.94) 46.83,23.615 v4(46.855,23.59)
  Signal Layer 3 w0.09: v1(42.525,19.725) v1(42.525,23.395)
  Bottom Layer w0.1: SB14.2@42.525,18.7 v1(42.525,19.725)
SAI2_SDA: SB2.1 U20.32 | length 3
  Top Layer w0.1: SB2.1@41.125,17.6 41.125,16.9 42.575,15.45 U20.32@42.575,15.25
SAI2_SDAM: SB2.2 SB15.2 U13.F4 | length 16.3
  Top Layer w0.1: SB2.2@41.125,18.7 v1(41.125,19.725) ; v1(41.48,24.365) 41.505,24.39 41.53,24.39 42.13,23.79 43.58,23.79 44.33,23.04 46.28,23.04 v4(46.53,23.29) ; v2(46.83,26.44) U13.F4@47.08,26.69
  Signal Layer 1 w0.1: v4(46.53,23.29) 46.53,26.14 v2(46.83,26.44)
  Signal Layer 2 w0.1: v1(41.48,24.365) v1@41.48,24.49
  Signal Layer 3 w0.1: v1(41.125,19.725) 41.105,19.745 41.105,23.99 v1(41.48,24.365)
  Bottom Layer w0.1: SB15.2@41.125,18.7 v1(41.125,19.725)
SAI2_SDB: SB4.1 U20.29 | length 2.4
  Top Layer w0.1: SB4.1@43.925,17.6 44.075,17.45 U20.29@44.075,15.25
SAI2_SDBM: SB4.2 SB13.2 U13.Y10 | length 43.8
  Top Layer w0.1: SB4.2@43.925,18.7 v1(43.925,19.725) ; v2(53.83,29.94) U13.Y10@54.08,29.69
  Signal Layer 1 w0.1: v2(53.83,29.94) 54.13,29.64 59.125,29.64 59.788,28.977 59.991,28.977 60.95,28.018 60.95,23.798 63.68,21.068 63.68,19.869 63.276,19.465 62.715,19.465 59.84,16.59 58.855,16.59 v1(58.83,16.615)
  Bottom Layer w0.1: SB13.2@43.925,18.7 v1(43.925,19.725) 44.235,19.725 44.81,19.15 45.7,19.15 46.425,18.425 46.425,16.825 46.85,16.4 50.075,16.4 50.525,16.85 51.985,16.85 52.51,17.375 53.888,17.375 54.073,17.19 54.775,17.19 55.075,17.19 55.075,17.175 55.3,16.95 56.35,16.95 56.685,16.615 v1(58.83,16.615)
SDMMC1_CK: CN15.5 R19.1 U10.2 U10.9 U13.D13 | length 41.8
  Top Layer w0.13: R19.1@16.05,46.875 v1(16.825,46.875) 16.825,46.15 17.15,45.825 U10.9@17.59,45.825 U10.2@18.41,45.825 18.925,45.825 19.1,45.65 v1(19.1,44.65) ; v1(34.055,44.415) 34.455,44.015 34.455,42.615 37.101,39.969 37.101,37.544 38.455,36.19 40.98,36.19 v4(42.955,34.215) ; v2(45.83,31.44) U13.D13@46.08,31.19
  Signal Layer 1 w0.13: v4(42.955,34.215) 43.32,33.85 44.83,33.85 45.83,32.85 v2(45.83,31.44)
  Signal Layer 2 w0.13: v1(19.1,44.65) 19.335,44.415 v1(34.055,44.415)
  Bottom Layer w0.13: CN15.5@15.6,46.875 v1(16.825,46.875)
SDMMC1_CMD: CN15.3 R25.1 U10.1 U10.10 U13.D12 | length 44.4
  Top Layer w0.1: R25.1@16.05,44.675 v1(16.825,44.675) 16.825,45.05 17.075,45.3 17.565,45.3 U10.10@17.59,45.325 U10.1@18.41,45.325 v1(18.41,44.59) ; v1(33.855,43.89) 33.83,43.89 34.13,43.59 34.13,42.636 36.88,39.886 36.88,35.67 37.41,35.14 41.091,35.14 42.055,34.176 v4(42.055,34.065) ; U13.D12@46.08,30.69 v2(46.33,30.94)
  Signal Layer 1 w0.1: v4@42.05,34.075 42.5,34.525 44.75,34.525 46.16,33.115 46.75,33.115 46.955,32.91 46.955,32.145 46.605,31.795 46.605,31.326 46.33,31.051 v2(46.33,30.94)
  Signal Layer 2 w0.1: v1(18.41,44.59) 18.425,44.575 18.425,44.37 18.905,43.89 v1(33.855,43.89)
  Bottom Layer w0.1: CN15.3@15.6,44.675 v1(16.825,44.675)
SDMMC1_D0: CN15.7 R16.1 U13.D18 U26.4 U26.7 | length 42.3
  Top Layer w0.09: U13.D18@46.08,33.69 46.08,33.544 46.229,33.395 46.872,33.395 v1(46.975,33.498)
  Top Layer w0.13: R16.1@16.05,49.075 v1(16.825,49.075)
  Signal Layer 2 w0.13: v1(27.912,42.908) v1(28.998,42.908)
  Bottom Layer w0.09: v1(46.975,33.498) v1@47.052,33.575
  Bottom Layer w0.13: CN15.7@15.6,49.075 v1(16.825,49.075) 17.2,48.7 17.2,47.15 17.525,46.825 U26.4@17.89,46.825 U26.7@18.71,46.825 23.988,46.825 27.905,42.908 v1(27.912,42.908) ; v1(28.998,42.908) 29.416,42.49 36.824,42.49 40.985,38.329 40.985,36.089 43.219,33.855 45.851,33.855 46.351,33.355 46.829,33.355 47.049,33.575 v1@47.052,33.575
SDMMC1_D1: CN15.8 R14.1 U13.D17 U26.5 U26.6 | length 43.8
  Top Layer w0.09: U13.D17@46.08,33.19 46.08,33.153 47.293,33.153 47.318,33.178 47.318,33.134 v1(47.305,33.121)
  Top Layer w0.13: R14.1@16.05,50.175 v1(16.825,50.175)
  Bottom Layer w0.1: 45.689,33.465 46.033,33.121 v1(47.305,33.121)
  Bottom Layer w0.13: CN15.8@15.6,50.175 v1(16.825,50.175) 17.59,49.41 17.59,47.45 17.715,47.325 U26.5@17.89,47.325 U26.6@18.71,47.325 24.04,47.325 27.875,43.49 28.155,43.49 28.48,43.165 28.48,42.465 28.845,42.1 36.662,42.1 40.185,38.577 40.185,36.337 43.057,33.465 45.689,33.465
SDMMC1_D2: CN15.1 R33.1 U13.D15 U26.1 U26.10 | length 43.2
  Top Layer w0.13: R33.1@16.05,42.475 v1(16.825,42.475) ; U13.D15@46.08,32.19 v1(46.505,32.19)
  Bottom Layer w0.13: CN15.1@15.6,42.475 v1(16.825,42.475) 17.59,43.24 17.59,45.225 17.69,45.325 U26.1@17.89,45.325 U26.10@18.71,45.325 24.275,45.325 25.28,44.32 25.28,42.025 25.765,41.54 26.66,41.54 26.88,41.32 36.339,41.32 39.405,38.254 39.405,36.014 40.615,34.804 40.615,33.771 41.701,32.685 45.362,32.685 45.657,32.39 46.305,32.39 v1(46.505,32.19)
SDMMC1_D3: CN15.2 R28.1 U13.D16 U26.2 U26.9 | length 41.5
  Top Layer w0.13: R28.1@16.05,43.575 v1(16.825,43.575) ; U13.D16@46.08,32.69 46.455,32.69 46.53,32.765 v1(46.605,32.765)
  Bottom Layer w0.13: CN15.2@15.6,43.575 v1(16.825,43.575) 17.2,43.95 17.2,45.525 17.5,45.825 U26.2@17.89,45.825 U26.9@18.71,45.825 24.345,45.825 28.46,41.71 36.501,41.71 39.795,38.416 39.795,36.176 41.005,34.966 41.005,33.932 41.862,33.075 45.527,33.075 45.784,32.819 ; 45.784,32.815 46.605,32.815 v1(46.605,32.765)
SDMMC2_CK: TP25.1 U8.20 U13.C9 | length 51.2
  Top Layer w0.09: 44.355,28.94 45.33,28.94 U13.C9@45.58,29.19
  Top Layer w0.1: U8.20@6.125,43.975 6.125,43.425 v1(6.25,43.3) ; v1(40.001,28.604) 39.994,28.604 39.98,28.59 40.08,28.49 40.783,28.49 41.133,28.84 42.561,28.84 42.687,28.715 43.473,28.715 43.698,28.94 44.355,28.94
  Signal Layer 2 w0.1: v1(6.25,43.3) 8.085,41.465 v1@19.065,41.465 ; v1(19.076,41.352) 19.189,41.465 33.23,41.465 v1(33.855,40.84)
  Signal Layer 3 w0.1: v1(33.855,40.84) 33.855,40.632 34.205,40.282 34.205,35.165 38.88,30.49 38.88,29.495 39.771,28.604 v1(40.001,28.604)
  Bottom Layer w0.1: TP25.1@18.3,41.175 18.477,41.352 v1(19.076,41.352)
SDMMC2_CMD: R26.2 U8.22 U13.A10 | length 48.3
  Top Layer w0.1: U8.22@6.575,44.65 7.275,44.65 7.925,44 R26.2@7.925,43.9 7.925,43.8 8.375,43.35 v1(8.375,43.275) ; v1(40.205,29.44) 40.23,29.44 42.81,29.44 42.935,29.315 43.225,29.315 43.535,29.625 44.115,29.625 44.18,29.69 U13.A10@44.58,29.69
  Signal Layer 2 w0.1: v1(8.375,43.275) 9.985,41.665 18.715,41.665 18.825,41.775 19.4,41.775 19.51,41.665 33.705,41.665 v1(34.58,40.79)
  Signal Layer 3 w0.1: v1(34.58,40.79) 34.78,40.59 34.78,35.259 39.364,30.675 39.364,29.961 39.785,29.54 40.105,29.54 v1(40.205,29.44)
SDMMC2_D0: R22.2 U8.24 U13.C13 | length 48.7
  Top Layer w0.09: 44.355,30.94 45.33,30.94 U13.C13@45.58,31.19
  Top Layer w0.1: U8.24@6.575,45.55 9.195,45.55 9.645,45.1 R22.2@10,45.1 10,44.953 v1(10.451,44.502) v1(10.451,44.502) ; v1(42.93,30.59) 43.28,30.94 44.355,30.94
  Bottom Layer w0.1: v1(10.451,44.502) 12.023,44.502 13.025,43.5 13.025,41.356 14.131,40.25 24.454,40.25 25.189,39.515 35.714,39.515 38.205,37.024 38.205,35.552 39.44,34.317 39.44,33.284 40.58,32.144 40.58,31.399 41.414,30.565 42.905,30.565 v1(42.93,30.59)
SDMMC2_D1: R17.2 U8.26 U13.B12 | length 50.3
  Top Layer w0.1: U8.26@6.575,46.45 9.075,46.45 R17.2@10,47.375 ; R17.2@10,47.595 R17.2@10,47.5 ; v1@10.451,46.901 v1(10.451,46.902) R17.2@10,47.353 ; v1(43.43,30.59) 43.53,30.69 U13.B12@45.08,30.69 ; R17.2@10,47.353 R17.2@10,47.5 ; R17.2@10,47.353 R17.2@10,47.375 ; R17.2@10,47.375 R17.2@10,47.5
  Bottom Layer w0.1: v1(10.451,46.902) 10.503,46.85 12.042,46.85 13.425,45.467 13.425,41.825 13.9,41.35 16.075,41.35 16.775,40.65 24.62,40.65 25.355,39.915 35.88,39.915 38.605,37.19 38.605,35.718 39.84,34.483 39.84,33.45 40.98,32.31 40.98,31.565 41.28,31.265 42.755,31.265 v1(43.43,30.59)
SDMMC2_D2: R27.2 U8.23 U13.A11 | length 47.3
  Top Layer w0.1: U8.23@6.575,45.1 8.895,45.1 10,43.995 R27.2@10,43.9 10,43.753 v1(10.451,43.302) v1@10.451,43.301 ; v1(42.216,29.865) 42.255,29.865 42.405,30.015 43.738,30.015 43.913,30.19 U13.A11@44.58,30.19
  Bottom Layer w0.1: v1(10.451,43.302) 12.098,43.302 12.825,42.575 12.825,41.273 14.048,40.05 24.371,40.05 25.106,39.315 35.631,39.315 38.005,36.941 38.005,35.469 39.24,34.234 39.24,33.201 40.38,32.061 40.38,31.316 41.331,30.365 41.716,30.365 v1(42.216,29.865)
SDMMC2_D3: R20.2 U8.25 U13.B13 | length 49.2
  Top Layer w0.09: 44.28,31.44 44.83,31.44 U13.B13@45.08,31.19
  Top Layer w0.1: U8.25@6.575,46 9.24,46 9.54,46.3 R20.2@10,46.3 10,46.153 v1(10.451,45.702) v1@10.451,45.701 ; v1(42.255,30.915) 42.255,30.89 42.805,31.44 44.28,31.44
  Bottom Layer w0.1: v1(10.451,45.702) 12.048,45.702 13.225,44.525 13.225,41.439 13.825,40.839 13.833,40.839 13.95,40.721 13.95,40.714 14.214,40.45 24.537,40.45 25.272,39.715 35.797,39.715 38.405,37.107 38.405,35.635 39.64,34.4 39.64,33.367 40.78,32.227 40.78,31.482 41.347,30.915 v1(42.255,30.915)
STLINK_RX: R72.2 TP21.1 U19.13 | length 15.1
  Top Layer w0.1: R72.2@64.95,22.3 66.2,21.05 66.55,21.05 67.225,20.375 ; U19.13@67.75,10.225 67.75,12.192 68.175,12.617 68.175,16.358 67.675,16.858 67.675,17.616 66.45,18.841 66.45,19.6 67.225,20.375 ; TP21.1@67.875,20.375 67.225,20.375
STLINK_SWCLK: SB20.2 TP5.1 U13.B20 | length 131.5
  Top Layer w0.09: 44.405,34.94 44.83,34.94 U13.B20@45.08,34.69
  Top Layer w0.1: v1(34.855,45.815) 34.951,45.911 35.181,45.911 37.027,44.065 39.805,44.065 TP5.1@40.605,43.265 40.605,43.157 40.947,42.815 41.258,42.815 43.505,40.568 43.505,36.107 43.901,35.711 43.901,35.444 44.405,34.94 ; v1(66.2,11.075) 66.2,8.97 v1(66.206,8.964)
  Signal Layer 2 w0.1: v1(18.13,48.59) 18.347,48.59 18.672,48.915 20.363,48.915 22.053,47.225 33.445,47.225 v1(34.855,45.815)
  Signal Layer 3 w0.1: v1(18.13,48.59) 18.13,48.585 18.48,48.235 18.48,47.945 17.602,47.067 17.602,28.652 16.655,27.705 16.655,26.39 17.684,25.361 17.684,9.311 v1(18.905,8.09)
  Bottom Layer w0.1: v1(18.905,8.09) 19.28,7.715 19.65,7.715 19.8,7.865 25.081,7.865 27.171,5.775 39.461,5.775 39.746,5.49 49.189,5.49 50.399,6.7 53.029,6.7 55.119,8.79 56.481,8.79 56.826,9.135 62.26,9.135 62.705,8.69 65.932,8.69 v1(66.206,8.964) ; v1(66.2,11.075) SB20.2@66.2,11.975
STLINK_SWDIO: SB17.2 TP3.1 U13.C20 | length 142.7
  Top Layer w0.09: v4(45.331,34.92) 45.33,34.94 U13.C20@45.58,34.69
  Top Layer w0.1: v1(33.955,46.19) 35.185,46.19 37.11,44.265 39.905,44.265 TP3.1@40.605,44.965 41.48,44.09 41.48,42.876 43.705,40.651 43.705,36.19 v4(44.18,35.715)
  Signal Layer 1 w0.09: v4(44.18,35.715) 44.18,35.708 44.718,35.17 45.079,35.17 ; 45.08,35.171 v4(45.331,34.92)
  Signal Layer 2 w0.1: v1(18.13,48.09) 18.755,48.715 20.28,48.715 21.995,47 33.145,47 v1(33.955,46.19)
  Signal Layer 3 w0.1: v1(18.13,48.09) 18.13,48.08 17.825,47.775 17.825,47.573 17.402,47.15 17.402,28.735 16.455,27.788 16.455,26.307 17.484,25.279 17.484,8.919 18.663,7.74 19.05,7.74 19.375,8.065 v1(19.505,8.065)
  Bottom Layer w0.1: v1(19.505,8.065) 25.164,8.065 27.254,5.975 39.544,5.975 39.829,5.69 49.106,5.69 50.316,6.9 52.946,6.9 55.036,8.99 56.398,8.99 56.743,9.335 62.46,9.335 62.905,8.89 65.505,8.89 65.95,9.335 66.595,9.335 67.155,8.775 67.965,8.775 69.155,9.965 69.155,15.34 68.47,16.025 66.895,16.025 66.2,16.72 SB17.2@66.2,16.875
STLINK_TX: R77.1 TP20.1 U19.12 | length 12.2
  Top Layer w0.1: R77.1@64.95,21.25 65.325,21.25 TP20.1@66.2,20.375 66.2,18.808 67.475,17.533 67.475,16.775 67.975,16.275 67.975,12.7 67,11.725 U19.12@66.25,11.725
STM_JTCK: CN12.2 U19.37 | length 24.5
  Top Layer w0.1: U19.37@73.25,18.725 v1(74.95,18.725) ; v1(82.675,14.075) 83.175,13.575 83.175,8.267 84.23,7.212 CN12.2@84.23,1.525
  Bottom Layer w0.1: v1(74.95,18.725) 75.25,18.725 79.2,14.775 81.975,14.775 v1(82.675,14.075)
STM_JTMS: CN12.4 U19.34 | length 25
  Top Layer w0.1: U19.34@74.75,16.225 77.017,16.225 78.792,14.45 82.825,14.45 83.375,13.9 83.375,8.35 84.43,7.295 84.43,5.345 86.425,3.35 87.485,3.35 CN12.4@89.31,1.525
STM_RST: C182.2 R161.1 SB18.2 U19.7 | length 4
  Top Layer w0.3: U19.7@66.25,14.225 v1(67.375,14.225)
  Bottom Layer w0.3: C182.2@66.7,14.225 v1@67.35,14.225 ; SB18.2@67.4,15.375 67.4,14.25 v1(67.375,14.225) R161.1@68.45,14.225
STUSB1600_IRQOUTN: U12.9 U13.P4 | length 39.2
  Top Layer w0.1: U13.P4@51.08,26.69 v2(51.33,26.94) ; v1(73.05,37.55) U12.9@74.55,37.55
  Signal Layer 1 w0.1: v2(51.33,26.94) 51.605,26.665 51.605,25.569 53.397,23.777 v1(53.397,22.8)
  Signal Layer 2 w0.1: v1(53.397,22.8) 53.397,23.907 56.93,27.44 58.785,27.44 60.622,29.277 62.382,29.277 62.98,28.679 63.516,28.679 64.68,27.515 66.059,27.515 70.109,31.565 70.608,31.565 72.424,33.381 72.847,33.381 73.052,33.176 73.052,32.963 73.25,32.765 73.626,32.765 73.856,32.995 73.856,33.397 73.05,34.203 v1(73.05,37.55)
T_JTCK: SB20.1 U19.15 U19.26 | length 9.3
  Top Layer w0.1: U19.15@68.75,10.225 v1(68.75,11.975) 69,12.225 U19.26@74.75,12.225
  Bottom Layer w0.1: SB20.1@67.3,11.975 v1(68.75,11.975)
T_JTMS: R88.1 SB17.1 U19.27 | length 12.7
  Top Layer w0.1: v1(68.35,16.875) 68.375,16.85 68.375,13.4 69.05,12.725 U19.27@74.75,12.725 75.775,12.725 76.05,13 R88.1@76.15,13
  Bottom Layer w0.1: SB17.1@67.3,16.875 v1(68.35,16.875)
T_NRST: SB22.1 U19.18 | length 4.9
  Top Layer w0.1: v1(67.3,9.125) 70.075,9.125 70.25,9.3 U19.18@70.25,10.225
  Bottom Layer w0.1: v1(67.3,9.125) SB22.1@67.3,10.125
T_SWDIO_IN: R88.2 U19.25 | length 1.6
  Top Layer w0.1: U19.25@74.75,11.725 75.65,11.725 76.025,12.1 R88.2@76.15,12.1
T_SWO: SB19.1 U19.31 | length 3.2
  Top Layer w0.1: v1(73.55,13.5) 73.55,14.275 74,14.725 U19.31@74.75,14.725
  Bottom Layer w0.1: SB19.1@72.5,13.525 72.525,13.5 v1(73.55,13.5)
TX0_N: U14.61 U32.9 | length 24
  Top Layer w0.1: U14.61@76.475,25.975 76.875,25.975 77.01,26.11 79.39,26.11 84.975,20.525 84.975,15.075 87.05,13 87.05,11.4 87.855,10.595 88.865,10.595 v1@88.9,10.56
  Bottom Layer w0.1: v1(88.9,10.45) 88.9,10.56 88.925,10.585 89.29,10.585 89.425,10.45 U32.9@89.7,10.45
TX0_P: U14.62 U32.10 | length 24.1
  Top Layer w0.1: U14.62@76.475,26.475 76.875,26.475 77.01,26.34 79.485,26.34 85.205,20.62 85.205,15.17 87.28,13.095 87.28,11.495 87.95,10.825 88.775,10.825 v1(88.9,10.95)
  Bottom Layer w0.1: v1(88.9,10.95) 88.9,10.84 88.925,10.815 89.29,10.815 89.425,10.95 U32.10@89.7,10.95
TX0C_N: CN9.9 U32.2 | length 3.1
  Top Layer w0.1: v1(91.65,10.5) 91.785,10.635 92.29,10.635 92.675,10.25 CN9.9@93.5,10.25
  Bottom Layer w0.1: U32.2@90.75,10.45 91,10.45 91.135,10.585 91.565,10.585 v1(91.65,10.5)
TX0C_P: CN9.7 U32.1 | length 3.1
  Top Layer w0.1: v1(91.65,11) 91.785,10.865 92.29,10.865 92.675,11.25 CN9.7@93.5,11.25
  Bottom Layer w0.1: U32.1@90.75,10.95 91,10.95 91.135,10.815 91.465,10.815 v1(91.65,11)
TX1_N: U14.64 U31.6 | length 23.6
  Top Layer w0.1: U14.64@76.475,27.475 76.875,27.475 77.01,27.61 78.99,27.61 85.675,20.925 85.675,15.425 87.75,13.35 87.75,12.525 88.105,12.17 88.755,12.17 v1(88.9,12.025)
  Bottom Layer w0.1: v1(88.9,12.025) 88.9,12.135 88.925,12.16 89.29,12.16 89.425,12.025 U31.6@89.7,12.025
TX1_P: U14.65 U31.7 | length 23.6
  Top Layer w0.1: U14.65@76.475,27.975 76.875,27.975 77.01,27.84 79.085,27.84 85.905,21.02 85.905,15.52 87.98,13.445 87.98,12.62 88.2,12.4 88.775,12.4 v1(88.9,12.525)
  Bottom Layer w0.1: v1(88.9,12.525) 88.9,12.415 88.925,12.39 89.29,12.39 89.425,12.525 U31.7@89.7,12.525
TX1C_N: CN9.6 U31.5 | length 3.1
  Top Layer w0.1: v1(91.65,12) 91.785,12.135 92.29,12.135 92.675,11.75 CN9.6@93.5,11.75
  Bottom Layer w0.1: U31.5@90.75,12.025 91.025,12.025 91.16,12.16 91.49,12.16 v1(91.65,12)
TX1C_P: CN9.4 U31.4 | length 3.1
  Top Layer w0.1: v1(91.65,12.5) 91.785,12.365 92.29,12.365 92.675,12.75 CN9.4@93.5,12.75
  Bottom Layer w0.1: U31.4@90.75,12.525 91.025,12.525 91.16,12.39 91.54,12.39 v1(91.65,12.5)
TX2_N: U14.67 U31.9 | length 23.2
  Top Layer w0.1: U14.67@76.475,28.975 77.025,28.975 77.16,29.11 78.69,29.11 86.35,21.45 86.35,15.8 88.5,13.65 88.775,13.65 v1(88.9,13.525)
  Bottom Layer w0.1: v1(88.9,13.525) 88.9,13.635 88.925,13.66 89.29,13.66 89.425,13.525 U31.9@89.7,13.525
TX2_P: U14.68 U31.10 | length 23.2
  Top Layer w0.1: U14.68@76.475,29.475 77.025,29.475 77.16,29.34 78.785,29.34 86.58,21.545 86.58,15.895 88.595,13.88 88.755,13.88 v1(88.9,14.025)
  Bottom Layer w0.1: v1(88.9,14.025) 88.9,13.915 88.925,13.89 89.29,13.89 89.425,14.025 U31.10@89.7,14.025
TX2C_N: CN9.3 U31.2 | length 3.1
  Top Layer w0.1: v1(91.65,13.5) 91.785,13.635 92.29,13.635 92.675,13.25 CN9.3@93.5,13.25
  Bottom Layer w0.1: U31.2@90.75,13.525 91,13.525 91.135,13.66 91.49,13.66 v1(91.65,13.5)
TX2C_P: CN9.1 U31.1 | length 3.1
  Top Layer w0.1: v1(91.65,14) 91.785,13.865 92.29,13.865 92.675,14.25 CN9.1@93.5,14.25
  Bottom Layer w0.1: U31.1@90.75,14.025 91,14.025 91.135,13.89 91.54,13.89 v1(91.65,14)
TXC_N: U14.58 U32.6 | length 24.6
  Top Layer w0.1: U14.58@76.475,24.475 76.9,24.475 77.035,24.61 79.84,24.61 84.325,20.125 84.325,14.7 86.275,12.75 86.275,10.3 87.505,9.07 88.78,9.07 v1(88.9,8.95)
  Bottom Layer w0.1: v1(88.9,8.95) 88.9,9.06 88.925,9.085 89.29,9.085 89.425,8.95 U32.6@89.7,8.95
TXC_P: U14.59 U32.7 | length 24.6
  Top Layer w0.1: U14.59@76.475,24.975 76.9,24.975 77.035,24.84 79.935,24.84 84.555,20.22 84.555,14.795 86.505,12.845 86.505,10.395 87.6,9.3 88.75,9.3 v1(88.9,9.45)
  Bottom Layer w0.1: v1(88.9,9.45) 88.9,9.34 88.925,9.315 89.29,9.315 89.425,9.45 U32.7@89.7,9.45
TXCC_N: CN9.12 U32.5 | length 3.1
  Top Layer w0.1: v1(91.65,9) 91.785,9.135 92.29,9.135 92.675,8.75 CN9.12@93.5,8.75
  Bottom Layer w0.1: U32.5@90.75,8.95 91.025,8.95 91.16,9.085 91.565,9.085 v1(91.65,9)
TXCC_P: CN9.10 U32.4 | length 3.1
  Top Layer w0.1: v1(91.65,9.5) 91.785,9.365 92.29,9.365 92.675,9.75 CN9.10@93.5,9.75
  Bottom Layer w0.1: U32.4@90.75,9.45 91.025,9.45 91.16,9.315 91.465,9.315 v1(91.65,9.5)
UART4_RX: R77.2 U13.Y16 | length 34.6
  Top Layer w0.1: v2(53.83,32.44) U13.Y16@54.08,32.69 ; v1(63.13,20.315) 63.13,20.33 R77.2@64.05,21.25
  Signal Layer 1 w0.1: v2(53.83,32.44) 60.093,32.44 60.518,32.865 61.738,32.865 62.038,32.565 63.497,32.565 66.247,35.315 66.78,35.315 66.981,35.114 67,35.133 v1(67,35.2)
  Signal Layer 3 w0.1: v1(63.13,20.315) 62.58,20.865 62.58,26.59 63.03,27.04 63.03,27.46 63.235,27.665 63.455,27.665 63.631,27.841 63.631,29.489 63.38,29.74 63.38,32.165 64.945,33.73 64.945,34.311 65.984,35.35 66.8,35.35 v1@66.975,35.175 ; v1@66.925,35.125 v1@66.975,35.075
UART4_TX: R72.1 U13.Y7 | length 14.7
  Top Layer w0.1: U13.Y7@54.08,28.19 v2(54.33,28.44) ; v1(63.055,20.915) 63.055,21.885 63.47,22.3 R72.1@64.05,22.3
  Signal Layer 1 w0.1: v2(54.33,28.44) 55.013,28.44 56.513,26.94 57.708,26.94 58.275,26.374 58.275,25.695 v1(63.055,20.915)
USART2_CTS: U8.5 U13.D14 | length 57
  Top Layer w0.1: v1(1.624,47.35) U8.5@2.525,47.35 ; v1(37.555,35.49) 41.08,35.49 42.63,33.94 43.33,33.94 v4(43.555,34.165) ; U13.D14@46.08,31.69 v2(46.33,31.44)
  Signal Layer 1 w0.09: v4@43.55,34.175 44.802,34.175 46.13,32.847 46.13,31.64 v2(46.33,31.44)
  Bottom Layer w0.1: v1(1.624,47.35) 3.986,47.35 4.25,47.086 4.25,46.659 6.625,44.284 6.625,42.658 7.6,41.683 7.6,39.927 8.475,39.052 8.475,37.817 11.142,35.15 11.75,35.15 12.225,35.625 24.362,35.625 24.797,35.19 37.255,35.19 v1(37.555,35.49)
USART2_RTS: U8.4 U13.B6 | length 59.5
  Top Layer w0.1: v1(1.925,47.8) U8.4@2.525,47.8 ; v1(37.305,27.09) 37.33,27.115 38.21,27.115 39.16,26.165 39.45,26.165 39.6,26.315 41.308,26.315 42.356,27.363 42.615,27.363 42.942,27.69 U13.B6@45.08,27.69
  Signal Layer 3 w0.1: v1(32.305,35.64) 32.33,35.615 32.33,33.315 33.179,32.466 34.064,32.466 35.65,30.879 35.65,29.214 37.305,27.559 v1(37.305,27.09)
  Bottom Layer w0.1: v1(1.925,47.8) 3.819,47.8 4.45,47.169 4.45,46.742 6.825,44.367 6.825,42.868 10.23,39.463 10.23,36.345 11.225,35.35 11.667,35.35 12.142,35.825 24.445,35.825 24.88,35.39 32.055,35.39 v1(32.305,35.64)
USART2_RX: TP27.1 U8.3 U13.D2 | length 64.3
  Top Layer w0.09: 45.83,24.965 45.83,25.44 U13.D2@46.08,25.69
  Top Layer w0.1: v1(1.624,48.25) U8.3@2.525,48.25 ; v1@35.686,26.09 36.471,25.306 36.897,25.306 37.062,25.141 37.921,25.141 38.497,24.565 40.113,24.565 40.263,24.715 41.63,24.715 42.355,23.99 44.896,23.99 45.83,24.924 45.83,24.965
  Signal Layer 3 w0.1: v1(30.654,37.116) 30.679,37.116 30.679,36.489 30.525,36.335 30.525,32.426 32.305,30.646 32.305,29.69 34.43,27.565 34.43,26.445 34.785,26.09 35.474,26.09 v1(35.499,26.065)
  Bottom Layer w0.1: v1(1.624,48.25) 3.652,48.25 4.65,47.252 4.65,46.825 7.025,44.45 7.025,42.951 10.43,39.546 10.43,37.512 11.877,36.065 18.065,36.065 TP27.1@18.6,36.6 19.135,36.065 24.438,36.065 25.638,37.265 30.505,37.265 v1(30.654,37.116)
USART2_TX: TP28.1 U8.2 U13.A7 | length 60.7
  Top Layer w0.1: v1(1.925,48.7) U8.2@2.525,48.7 ; v1(38.88,27.015) 38.98,26.915 40.044,26.915 40.244,26.715 41.142,26.715 42.19,27.763 42.45,27.763 42.802,28.115 43.755,28.115 43.83,28.19 U13.A7@44.58,28.19
  Signal Layer 3 w0.1: 32.905,37.314 32.905,35.456 32.73,35.281 32.73,33.481 33.345,32.866 34.229,32.866 36.05,31.045 36.05,29.38 38.415,27.015 v1(38.88,27.015)
  Bottom Layer w0.1: v1(1.925,48.7) 3.485,48.7 4.767,47.418 5.614,47.418 8.025,45.007 8.025,42.275 10.5,39.8 10.5,39.759 10.63,39.629 10.63,37.595 11.96,36.265 16.89,36.265 TP28.1@17.225,36.6 17.825,36.6 18.275,37.05 18.875,37.05 19.66,36.265 24.355,36.265 25.555,37.465 28.58,37.465 ; 28.581,37.466 v1(32.754,37.466)
USB1_N: U7.30 U13.AB17 | length 21.2
  Top Layer w0.1: U13.AB17@55.08,33.19 55.335,33.445 55.686,33.445 55.751,33.38 60.061,33.38 62.29,35.609 62.29,42.09 63.975,43.775 64.781,43.775 66.15,45.144 66.15,45.925 66,46.075 U7.30@66,46.4
USB1_P: U7.31 U13.AC17 | length 20.9
  Top Layer w0.1: U13.AC17@55.58,33.19 60.14,33.19 61.24,34.29 62.48,35.53 62.48,42.011 64.054,43.585 64.86,43.585 65.065,43.79 66.34,45.065 66.34,45.915 66.5,46.075 U7.31@66.5,46.4
USB1CN25_N: CN5.T2 U9.5 | length 11.4
  Top Layer w0.1: U9.5@79.65,49.15 80,49.15 80.155,49.305 82.195,49.305 85.81,45.69 85.81,44.221 86.126,43.905 86.75,43.905 87.37,43.285 CN5.T2@87.37,43
USB1CN25_P: CN5.T3 U9.6 | length 11.4
  Top Layer w0.1: U9.6@79.65,49.65 80,49.65 80.155,49.495 82.274,49.495 86,45.769 86,44.3 86.205,44.095 86.75,44.095 87.37,44.715 CN5.T3@87.37,45
USB2_N: U13.AB16 U29.2 | length 36.7
  Top Layer w0.09: 55.33,32.94 55.7,32.94
  Top Layer w0.1: U13.AB16@55.08,32.69 55.33,32.94 ; 55.7,32.94 55.765,32.875 60.481,32.875 61.896,34.29 62.581,34.975 62.646,35.04 62.97,35.04 v1(63.125,35.195)
  Bottom Layer w0.1: v1(63.125,35.195) 63.28,35.04 65.391,35.04 66.181,35.83 72.434,35.83 74.324,33.94 78.304,33.94 84.374,27.87 86.57,27.87 86.725,28.025 U29.2@86.925,28.025
USB2_P: U13.AC16 U29.1 | length 36.1
  Top Layer w0.1: U13.AC16@55.58,32.685 U13.AC16@55.58,32.69 55.585,32.685 60.56,32.685 62.725,34.85 62.97,34.85 v1(63.125,34.695)
  Bottom Layer w0.1: v1(63.125,34.695) 63.28,34.85 65.47,34.85 66.26,35.64 72.355,35.64 74.245,33.75 78.225,33.75 84.295,27.68 86.57,27.68 86.725,27.525 U29.1@86.925,27.525
USB2CN25_N: CN5.B2 U6.5 | length 15.2
  Top Layer w0.1: U6.5@79.65,51.55 79.85,51.55 80.005,51.705 80.945,51.705 86.415,46.235 88.44,46.235 88.7,45.975 88.7,44.175 88.965,43.91 89.3,43.91 89.99,43.22 CN5.B2@89.99,43
USB2CN25_P: CN5.B3 U6.6 | length 15.2
  Top Layer w0.1: U6.6@79.65,52.05 79.85,52.05 80.005,51.895 81.024,51.895 86.494,46.425 88.519,46.425 88.659,46.284 88.89,46.054 88.89,44.254 89.044,44.1 89.3,44.1 89.99,44.79 CN5.B3@89.99,45
USB3CN26_N: CN1.T2 U2.5 | length 12
  Top Layer w0.1: U2.5@79.65,60.15 79.85,60.15 79.985,60.285 82.154,60.285 82.586,60.717 82.586,63.186 82.85,63.45 85.225,63.45 85.7,62.975 85.7,62.131 85.926,61.905 86.465,61.905 CN1.T2@87.37,61
USB3CN26_P: CN1.T3 U2.6 | length 12.1
  Top Layer w0.1: U2.6@79.65,60.65 79.85,60.65 80.025,60.475 82.075,60.475 82.396,60.796 82.396,63.264 82.771,63.64 85.304,63.64 85.834,63.109 85.89,63.054 85.89,62.21 86.005,62.095 86.465,62.095 CN1.T3@87.37,63
USB4CN26_N: CN1.B2 U1.5 | length 13.2
  Top Layer w0.1: U1.5@79.65,62.55 79.875,62.55 80.025,62.7 81.175,62.7 82.625,64.15 88.125,64.15 88.51,63.765 88.51,62.191 88.796,61.905 89.085,61.905 CN1.B2@89.99,61
USB4CN26_P: CN1.B3 U1.6 | length 13.2
  Top Layer w0.1: U1.6@79.65,63.05 79.85,63.05 80.01,62.89 81.096,62.89 82.546,64.34 88.204,64.34 88.7,63.844 88.7,62.27 88.875,62.095 89.085,62.095 CN1.B3@89.99,63
USB_DCONN_N: CN7.A7 CN7.B7 U29.5 | length 7.2
  Top Layer w0.1: v1(89.2,28.025) 89.355,27.87 90.615,27.87 90.77,28.025 CN7.A7@91.42,28.025
  Bottom Layer w0.1: U29.5@88.225,28.025 88.425,28.025 88.58,27.87 89.045,27.87 v1(89.2,28.025) 89.355,27.87 92.175,27.87 CN7.B7@92.67,27.375
USB_DCONN_P: CN7.A6 CN7.B6 U29.6 | length 5
  Top Layer w0.1: v1(89.2,27.525) 89.355,27.68 90.615,27.68 90.77,27.525 CN7.A6@91.42,27.525 92.02,27.525 CN7.B6@92.67,28.175
  Bottom Layer w0.1: U29.6@88.225,27.525 88.425,27.525 88.58,27.68 89.045,27.68 v1(89.2,27.525)
USB_PWR_CC1: R49.2 U13.V4 | length 56.6
  Top Layer w0.1: U13.V4@53.08,26.69 v2(53.33,26.44)
  Top Layer w0.2: R49.2@19.55,30.6 20.375,30.6 21.175,31.4 24.49,31.4 v1(24.925,30.965)
  Signal Layer 1 w0.1: v2(53.33,26.44) 53.055,26.165 53.055,25.534 53.974,24.615 54.198,24.615 57.073,21.74 57.175,21.74 57.38,21.535 57.38,21.245 56.025,19.89 v1(55.881,19.89)
  Signal Layer 2 w0.1: v1(37.03,17.965) 37.08,18.015 37.3,18.015 38.185,18.9 43.875,18.9 44.15,19.175 47.125,19.175 47.375,18.925 47.375,18.55 47.671,18.254 48.429,18.254 49.25,19.075 49.525,19.075 50.35,19.9 55.87,19.9 v1(55.881,19.89)
  Signal Layer 3 w0.1: v1(24.925,30.965) 24.925,27.829 29.314,23.44 31.769,23.44 34,21.209 34,19.353 35.388,17.965 v1(37.03,17.965)
USB_PWR_CC2: R56.2 U13.V3 | length 58.8
  Top Layer w0.1: U13.V3@53.08,26.19 v2(53.33,25.94)
  Top Layer w0.2: R56.2@19.55,29.3 20.095,29.3 20.93,28.465 23.305,28.465 v1(23.73,28.89)
  Signal Layer 1 w0.1: v2(53.33,25.94) 53.33,25.542 54.057,24.815 54.281,24.815 57.156,21.94 57.258,21.94 57.58,21.618 57.58,21.162 56.231,19.813 56.231,19.139 56.232,19.137 56.232,19.013 56.231,19.011 56.231,18.826 56.205,18.801 56.205,18.705 55.2,17.7 55.2,17.6 55.05,17.45 54.575,17.45 54.433,17.592 54.433,18.14 v1(54.675,18.382)
  Signal Layer 2 w0.1: v1(37.78,17.99) 38.458,18.667 44.082,18.667 44.39,18.975 45.675,18.975 46.6,18.05 48.525,18.05 49.35,18.875 49.608,18.875 50.404,19.671 54.121,19.671 54.125,19.675 54.675,19.125 v1(54.675,18.382)
  Signal Layer 3 w0.1: v1(23.73,28.89) 23.73,27.4 27.89,23.24 31.686,23.24 33.8,21.126 33.8,19.27 36.055,17.015 36.805,17.015 v1(37.78,17.99)
USB_RENUMN: R104.2 U19.38 | length 13.2
  Top Layer w0.1: U19.38@72.75,18.725 72.75,17.95 v1(73.125,17.575)
  Top Layer w0.3: R104.2@70.525,7.75 v1(70.525,8.375)
  Bottom Layer w0.1: v1(70.525,8.375) 70.525,8.785 74.38,12.64 74.38,16.32 v1(73.125,17.575)
USB_STLK_ID: CN11.4 R100.2 | length 5
  Top Layer w0.3: CN11.4@76.15,4.15 76.15,7.85 R100.2@77.075,8.775
USB_STLK_N: U19.32 U21.6 | length 5.2
  Top Layer w0.1: U19.32@74.75,15.225 75.225,15.225 75.38,15.38 76.876,15.38 77.68,14.576 77.68,14.441 77.275,14.036 U21.6@77.275,12.905
USB_STLK_P: U19.33 U21.4 | length 5.5
  Top Layer w0.1: U19.33@74.75,15.725 75.225,15.725 75.38,15.57 76.955,15.57 77.87,14.655 77.87,14.441 78.275,14.036 U21.4@78.275,12.905
USBDN1_N: U7.1 U9.2 | length 12.8
  Top Layer w0.1: U7.1@69.75,47.15 70.075,47.15 70.23,47.305 74.13,47.305 75.4,48.575 75.4,50.675 75.675,50.95 76.8,50.95 77.075,50.675 77.075,49.631 77.406,49.3 78,49.3 78.15,49.15 U9.2@78.35,49.15
USBDN1_P: U7.2 U9.1 | length 12.8
  Top Layer w0.1: U7.2@69.75,47.65 70.075,47.65 70.23,47.495 74.051,47.495 75.21,48.654 75.21,50.754 75.596,51.14 76.879,51.14 77.265,50.754 77.265,49.71 77.485,49.49 77.99,49.49 78.15,49.65 U9.1@78.35,49.65
USBDN2_N: U6.2 U7.3 | length 12.2
  Top Layer w0.1: U7.3@69.75,48.15 70.1,48.15 70.255,48.305 73.674,48.305 74.65,49.281 74.65,51.925 75.025,52.3 77.15,52.3 77.75,51.7 78,51.7 78.15,51.55 U6.2@78.35,51.55
USBDN2_P: U6.1 U7.4 | length 12.2
  Top Layer w0.1: U7.4@69.75,48.65 70.075,48.65 70.23,48.495 73.595,48.495 74.46,49.36 74.46,52.004 74.946,52.49 77.229,52.49 77.829,51.89 77.99,51.89 78.15,52.05 U6.1@78.35,52.05
USBDN3_N: U2.2 U7.6 | length 16
  Top Layer w0.1: U7.6@69.75,49.65 70.075,49.65 70.21,49.785 70.879,49.785 70.904,49.81 74,52.906 74,57.925 76.38,60.305 77.995,60.305 78.15,60.15 U2.2@78.35,60.15
USBDN3_P: U2.1 U7.7 | length 16
  Top Layer w0.1: U7.7@69.75,50.15 70.05,50.15 70.225,49.975 70.8,49.975 73.81,52.985 73.81,58.004 76.301,60.495 77.995,60.495 78.15,60.65 U2.1@78.35,60.65
USBDN4_N: U1.2 U7.8 | length 16.6
  Top Layer w0.1: U7.8@69.75,50.65 70.075,50.65 70.235,50.81 70.979,50.81 73.325,53.156 73.325,58.181 77.849,62.705 77.995,62.705 78.15,62.55 U1.2@78.35,62.55
USBDN4_P: U1.1 U7.9 | length 16.6
  Top Layer w0.1: U7.9@69.75,51.15 70.075,51.15 70.225,51 70.9,51 73.135,53.235 73.135,58.26 77.77,62.895 77.995,62.895 78.15,63.05 U1.1@78.35,63.05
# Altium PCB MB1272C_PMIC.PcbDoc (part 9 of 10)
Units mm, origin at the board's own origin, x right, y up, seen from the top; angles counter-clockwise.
Board outline 101 x 71 mm, 6 copper layers (Top Layer, Signal Layer 1, Signal Layer 2, Signal Layer 3, Signal Layer 4, Bottom Layer), stack 1.552 mm thick; 518 components, 478 nets, 2152 pads, 1871 vias.
Unrouted connection lines stored in the file: 3.

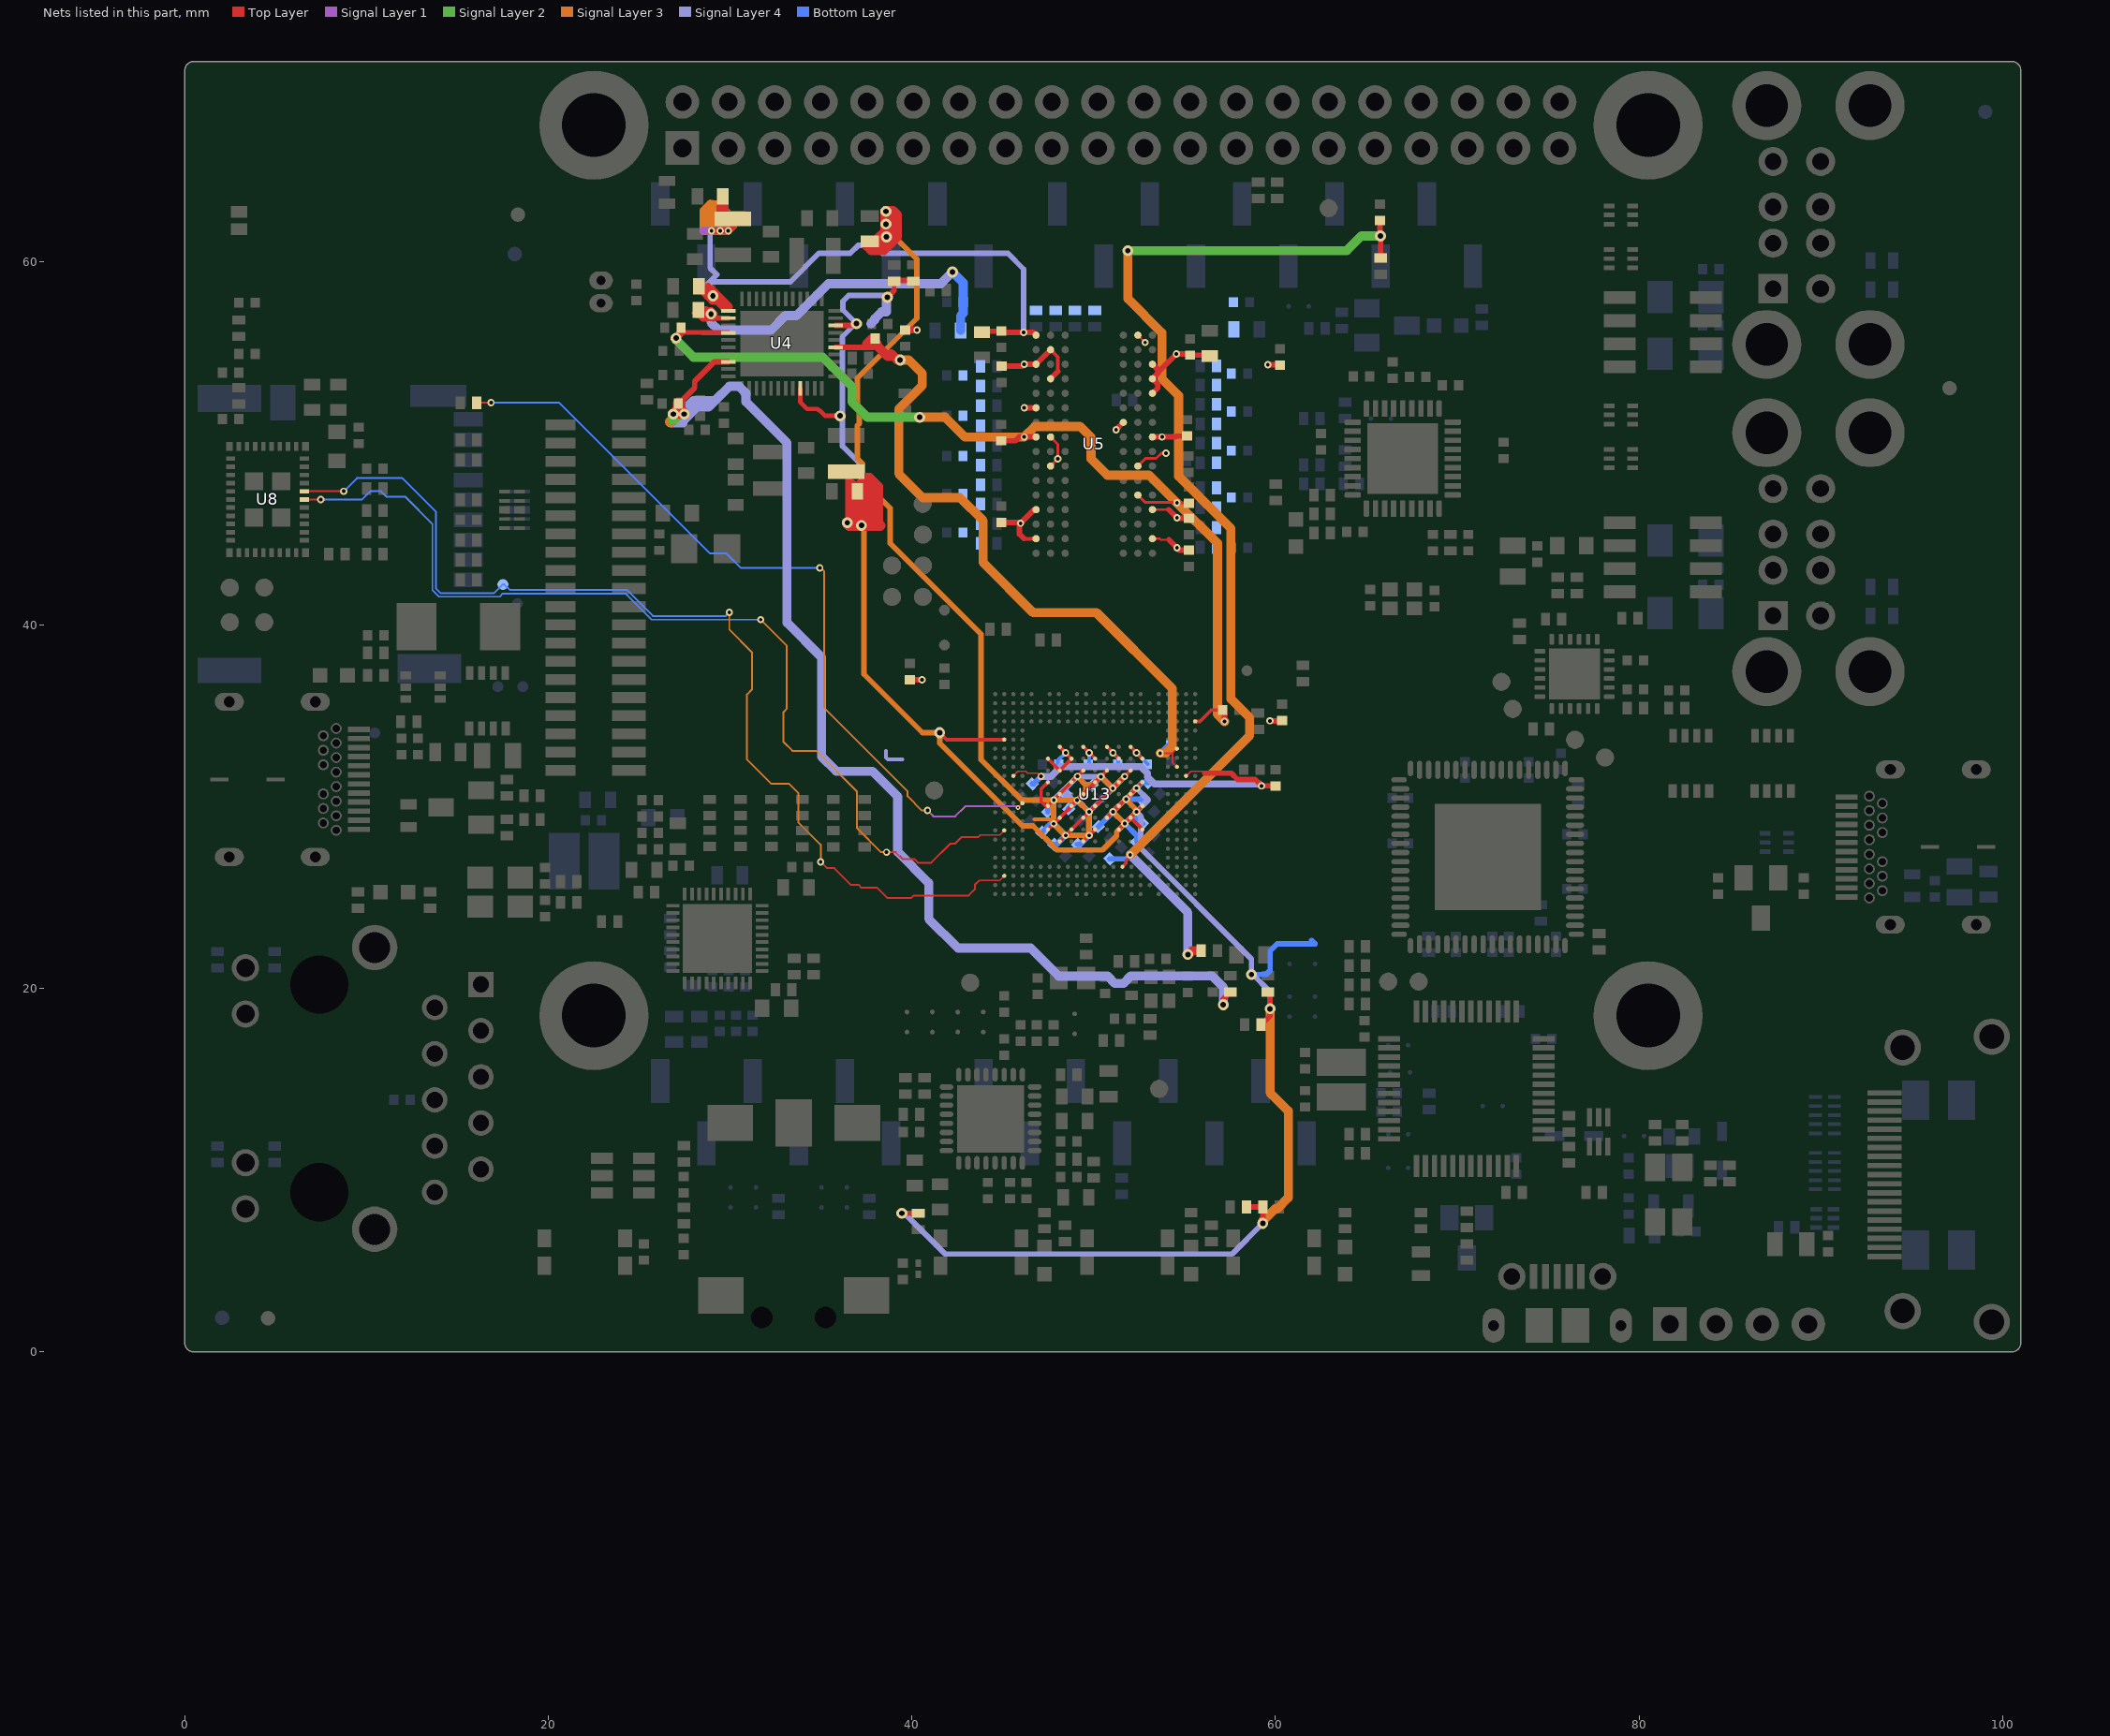
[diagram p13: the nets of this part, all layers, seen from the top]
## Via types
v1: diameter 0.4, hole 0.2, Top Layer to Bottom Layer, tented both sides, 884 vias
v2: diameter 0.25, hole 0.1, Top Layer to Signal Layer 1, tented top, 470 vias
v3: diameter 0.6, hole 0.3, Top Layer to Bottom Layer, tented both sides, 469 vias
v4: diameter 0.25, hole 0.1, Top Layer to Signal Layer 1, tented both sides, 46 vias
v5: diameter 0.25, hole 0.1, Top Layer to Bottom Layer, tented top, 2 vias

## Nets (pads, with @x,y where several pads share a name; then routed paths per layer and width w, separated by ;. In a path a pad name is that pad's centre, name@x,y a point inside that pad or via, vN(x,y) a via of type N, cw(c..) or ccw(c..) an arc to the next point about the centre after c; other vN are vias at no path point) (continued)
USD_DETECT: R13.1 U13.D11 | length 44.4
  Top Layer w0.1: R13.1@16.05,52.225 v1(16.85,52.225) ; v2(45.83,29.94) U13.D11@46.08,30.19
  Signal Layer 1 w0.1: v1(40.855,29.79) 41.18,29.465 42.38,29.465 42.93,30.015 45.755,30.015 v2(45.83,29.94)
  Signal Layer 3 w0.1: v1(34.93,43.14) 34.98,43.14 35.18,42.94 35.18,35.424 39.764,30.841 39.764,30.574 40.547,29.79 v1(40.855,29.79)
  Bottom Layer w0.1: v1(16.85,52.225) 20.6,52.225 28.885,43.94 29.785,43.94 30.585,43.14 v1(34.93,43.14)
VDD: C44.2 C147.2 C152.2 C158.2 C159.2 C161.2 L6.2 R5.1 R7.1 R79.1 R101.2 R102.2 R109.2 R304.1 SB9.2 SB10.2 U4.31 U4.42 U13.1F3 U13.1G2 U13.1G4 U13.1H3 U13.1H5 U13.1J2 U13.1J4 U13.1J6 U13.B18 | length 167.7
  Top Layer w0.2: v3@36.85,56.475 36.952,56.577 36.95,56.579 v3(36.95,56.575) ; v3(41.53,34.065) 41.905,33.69 U13.B18@45.08,33.69 ; U13.1F3@50.73,29.4 U13.1G4@51.38,30.05 ; U13.1G2@51.38,28.74 v1(51.705,29.065) U13.1H3@52.03,29.39 ; U13.1G4@51.38,30.04 v1@51.755,30.415 ; v1(51.78,30.415) v1@51.755,30.415 ; U13.1H5@52.04,30.69 U13.1H5@52.03,30.69 ; U13.1J2@52.68,28.74 U13.1H3@52.03,29.39 ; U13.1J4@52.68,30.06 U13.1J4@52.68,30.04 v1(52.355,29.715) U13.1H3@52.03,29.39 ; U13.1J6@52.68,31.36 U13.1J6@52.68,31.34 v1(52.355,31.015) U13.1H5@52.03,30.69 ; v1@51.755,30.415 U13.1H5@52.03,30.69
  Top Layer w0.25: U4.31@33.85,53.025 33.85,52.265 34.232,51.882 34.798,51.882 34.88,51.8 34.925,51.8 35.225,51.5 v3(36.05,51.5) ; v3(36.45,45.625) L6.2@36.45,48.175 ; v3@36.6,45.475 36.65,45.525 36.65,47.975 ; C44.2@37,47.025 37,47.625 36.825,47.8 ; 37.8,46.125 37.65,46.275 ; 38.25,45.475 38.3,45.525 38.3,47.65 37.7,48.25 36.375,48.25 L6.2@36.45,48.175 ; 39,58.375 39.025,58.4 39.025,58.419 R5.1@39.025,58.9 ; L6.2@36.45,48.175 36.65,47.975 ; 36.65,47.975 36.825,47.8 ; 36.825,47.8 36.825,45.825 37.075,45.825 37.1,45.85 38.1,45.85 38.1,47.525 37.55,48.075 37.487,48.012 ; 37.075,46.05 37.075,47.875 37.275,47.875 ; 37.075,46.05 37.1,46.025 ; 37.075,46.05 37.175,46.05 37.15,46.025 ; 37.075,46.05 37,46.05 37.025,46.025 37.1,46.025 ; 37.1,46.025 37.125,46 37.15,46.025 ; 37.1,46.025 37.15,46.025 ; 37.15,46.025 37.9,46.025 37.9,47.6 37.487,48.012 ; 37.275,47.875 37.275,47.975 37.4,48.1 37.487,48.012 ; 37.275,47.875 37.275,46.225 37.3,46.2 37.375,46.275 37.65,46.275 ; 37.275,47.875 37.35,47.875 37.487,48.012 ; 37.65,46.275 37.475,46.45 37.475,47.715 37.505,47.745 37.7,47.55 37.7,46.275 37.65,46.275
  Top Layer w0.3: U4.42@35.8,56.475 36.85,56.475 v3(36.95,56.575) ; v3@38.65,58.15 v3(38.65,58.025) 39,58.375 39.025,58.419 ; R5.1@39.325,58.95 R7.1@40.175,58.95 ; v3(39.45,7.625) R109.2@40.35,7.625 ; R101.2@58.4,7.975 R102.2@59.3,7.975 v3(59.3,7.075) ; R304.1@59.2,18 59.7,18.5 v3(59.7,18.875) 59.7,19.675 R79.1@59.575,19.8
  Top Layer w0.6: v3(36.45,45.625) 36.6,45.475 v3(37.225,45.475) 38.25,45.475
  Signal Layer 1 w0.6: v3(36.45,45.625) 36.6,45.475 v3(37.225,45.475)
  Signal Layer 2 w0.6: v3(36.45,45.625) 36.6,45.475 v3(37.225,45.475)
  Signal Layer 3 w0.2: v3(36.95,56.575) 36.95,56.626 v3@36.974,56.65
  Signal Layer 3 w0.3: v3(37.225,45.475) 37.355,45.345 37.355,37.29 40.58,34.065 v3(41.53,34.065) 41.53,33.49 46.08,28.94 46.655,28.94 47.98,27.615 50.48,27.615 51.255,28.39 51.255,28.601 51.705,29.051 v1(51.705,29.065) ; v1(51.78,30.415) v1@51.755,30.415 ; v1(52.355,31.015) v1@51.755,30.415 ; v1(51.705,29.065) v1(52.355,29.715) 52.355,29.815 v1@51.755,30.415 ; v1(51.705,29.065) v1(51.055,29.715) v1@51.755,30.415
  Signal Layer 3 w0.5: v3(59.3,7.075) 59.3,7.203 59.972,7.875 60.1,7.875 60.705,8.48 60.705,13.265 59.7,14.27 v3(59.7,18.875)
  Signal Layer 4 w0.3: v3(37.225,45.475) 37.225,48.755 37.08,48.9 37.1,48.92 36.18,49.84 36.18,55.856 36.899,56.575 v3(36.95,56.575) 36.95,56.579 36.205,57.324 36.205,57.805 36.525,58.125 38.55,58.125 v3(38.65,58.025) ; v3@39.375,7.55 v3(39.45,7.625) 39.595,7.625 41.83,5.39 57.615,5.39 v3(59.3,7.075) ; v1(51.78,30.415) v1@51.755,30.415 ; v3(58.68,20.765) 58.68,21.615 52.58,27.715 52.58,29.49 v1(52.355,29.715) ; v3@58.712,20.798 59.7,19.81 v3(59.7,18.875) ; v1@51.755,30.415 v1(52.355,31.015) 53.005,30.365 v1(52.355,29.715) ; v1@51.755,30.415 v1(51.055,29.715) v1(51.705,29.065) v1(52.355,29.715)
  Signal Layer 4 w0.5: 37.75,56.575 37.95,56.775 37.95,56.844 38.331,57.225 38.6,57.225 38.6,57.975 v3(38.65,58.025)
  Bottom Layer w0.3: C159.2@50.249,28.896 51.055,29.701 v1(51.055,29.715) ; v1(51.705,29.065) 52.362,28.408 C161.2@52.362,28.083 ; v1@51.769,30.415 v1(51.78,30.415) 52.63,30.415 C152.2@52.687,30.358 ; v1(52.355,29.715) 52.355,29.39 C158.2@52.687,29.058 ; v1(52.355,31.015) 52.673,31.333 C147.2@53.012,31.333 ; v3(58.68,20.765) 59.48,20.765 59.705,20.99 59.705,22.065 60.09,22.45 SB10.2@60.775,22.45 SB9.2@62.175,22.45 61.98,22.645
  Bottom Layer w0.6: v3(36.45,45.625) 36.6,45.475 v3(37.225,45.475)
VDD_CORE: C148.2 C150.2 C153.2 C155.2 C156.2 C162.2 C163.2 LNK2.2 R3.2 U13.1A2 U13.1A4 U13.1A6 U13.1B1 U13.1B3 U13.1B5 U13.1C2 U13.1C4 U13.1C6 U13.1D1 U13.1D3 U13.1D5 U13.1D7 U13.1E2 U13.1E4 U13.1E6 U13.1F5 U13.1F7 U13.1G6 U13.1H7 | length 103.9
  Top Layer w0.2: R3.2@37.323,60.998 37.323,61.008 37.415,61.1 R3.2@37.675,61.1 ; U13.1A2@47.48,28.74 v1(47.8,29.06) 48.12,29.38 U13.1B3@48.13,29.38 ; U13.1A4@47.48,30.04 v1(47.805,30.365) 48.12,30.68 U13.1B5@48.14,30.68 ; U13.1A6@47.48,31.34 47.11,30.97 47.11,30.29 47.37,30.03 U13.1A4@47.49,30.03 ; U13.1B1@48.13,28.09 48.75,28.71 U13.1C2@48.76,28.71 ; U13.1B3@48.13,29.39 U13.1C4@48.77,30.03 ; U13.1B5@48.13,30.69 U13.1C6@48.78,31.34 49.42,31.98 U13.1D7@49.42,32 ; U13.1C2@48.78,28.74 49.44,29.4 U13.1D3@49.45,29.4 ; U13.1C4@48.78,30.04 v1(49.09,30.35) 49.4,30.66 U13.1D5@49.4,30.68 ; U13.1D1@49.43,28.09 v1(49.755,28.415) U13.1E2@50.08,28.74 U13.1E2@50.08,28.75 ; U13.1D3@49.43,29.39 v1(49.755,29.715) U13.1E4@50.08,30.04 U13.1F5@50.73,30.69 v1(51.05,31.01) 51.37,31.33 U13.1G6@51.37,31.35 ; U13.1D5@49.43,30.69 U13.1E6@50.08,31.34 v1(50.395,31.655) 50.71,31.97 U13.1F7@50.72,31.97 ; U13.1G6@51.38,31.34 v1(51.7,31.66) 52.02,31.98 U13.1H7@52.02,32
  Top Layer w0.3: R3.2@37.675,61.1 R3.2@37.875,61.1 ; v3(38.575,62.05) 38.675,62.05 v3@38.7,62.075
  Top Layer w0.6: R3.2@37.5,61.025 37.5,60.925 37.775,60.65 38.456,60.65 39.15,61.344 39.15,62.55 38.95,62.75 v3(38.575,62.75) v3(38.575,62.05) 38.575,61.65 ; R3.2@37.675,61.075 38.325,61.075 v3(38.6,61.35) 38.575,61.375 38.575,61.65 ; R3.2@37.875,61.1 38.025,61.1 38.575,61.65 ; 38.925,62 38.575,61.65
  Signal Layer 1 w0.6: v3(38.575,62.75) v3(38.575,62.05) 38.575,61.375 v3(38.6,61.35)
  Signal Layer 2 w0.6: v3(38.575,62.75) v3(38.575,62.05) 38.575,61.375 v3(38.6,61.35)
  Signal Layer 3 w0.2: LNK2.2@46.737,29.3 47.56,29.3 v1(47.8,29.06)
  Signal Layer 3 w0.3: v3(38.575,62.05) 38.575,61.825 40.275,60.125 40.275,56.86 37,53.585 37,52.035 37.1,51.935 37.1,51.065 37,50.965 37,49.145 37.284,48.861 37.284,47.936 38.805,46.415 38.805,44.49 43.805,39.49 43.805,32.59 46.03,30.365 v1(47.805,30.365) ; v1(49.105,31.665) 49.105,31.651 49.555,31.201 ; v1(51.7,31.66) v1(51.05,31.01) 51.04,31.01 v1(50.395,31.655) 49.941,31.201 49.555,31.201 ; v1(47.805,30.365) 47.8,30.36 v1(47.8,29.06) 48.445,28.415 v1(48.455,28.415) v1(49.755,28.415) 49.725,28.445 49.725,29.715 v1(49.09,30.35) ; v1(47.805,30.365) 49.075,30.365 v1(49.09,30.35) ; v1(49.09,30.35) 49.09,30.364 49.555,30.829 49.555,31.201
  Signal Layer 4 w0.3: 48.405,30.815 48.87,30.35 v1(49.09,30.35) 49.12,30.35 v1(49.755,29.715) ; v1(51.7,31.66) v1(51.05,31.01) ; v1(49.755,29.715) v1(51.05,31.01) ; v1(49.755,29.715) v1(49.755,28.415) v1(48.455,28.415) 48.445,28.415 v1(47.8,29.06) 47.805,29.065 v1(47.805,30.365) v1(49.105,31.665) 49.115,31.655 v1(50.395,31.655) 51.04,31.01 v1(51.05,31.01)
  Signal Layer 4 w0.6: v3(38.575,62.75) v3(38.575,62.05) 38.575,61.375 v3(38.6,61.35)
  Bottom Layer w0.3: C156.2@47.148,28.584 47.624,29.06 v1(47.8,29.06) ; C153.2@47.473,29.722 47.473,30.033 v1(47.805,30.365) ; C163.2@47.812,27.921 47.961,27.921 v1(48.455,28.415) ; C148.2@48.448,30.697 48.448,31.008 v1(49.105,31.665) ; C155.2@48.624,29.871 48.624,29.884 v1(49.09,30.35) 49.725,29.715 v1(49.755,29.715) ; C162.2@49.112,27.921 49.261,27.921 v1(49.755,28.415) ; C150.2@49.924,31.171 49.924,31.184 v1(50.395,31.655) 50.405,31.655 v1(51.05,31.01) v1(51.7,31.66)
  Bottom Layer w0.6: v3(38.575,62.75) v3(38.575,62.05) 38.575,61.375 v3(38.6,61.35)
VDD_DDR: C2.2 C6.2 C11.2 C12.2 C13.2 C14.1 C17.1 C18.2 C22.1 C35.1 C47.1 C48.1 C57.1 C63.2 C67.2 C143.2 C144.2 C145.2 C146.2 L2.2 LNK1.2 U4.13 U5.A1 U5.A8 U5.B2 U5.C1 U5.C9 U5.D2 U5.D9 U5.E9 U5.F1 U5.G7 U5.H2 U5.H9 U5.K2 U5.K8 U5.N1 U5.N9 U5.R1 U5.R9 U13.1A8 U13.1B7 U13.1B9 U13.1C8 U13.1D9 U13.1E8 U13.1F9 U13.1G8 U13.1H9 U13.1J8 | length 99.2
  Top Layer w0.12: U5.D2@47.587,53.52 47.616,53.548 U5.D2@47.616,53.52 ; U5.A8@52.43,55.94 v1(52.83,55.54) ; U5.E9@53.137,52.74 U5.E9@53.18,52.74 ; U5.R9@53.18,44.74 U5.R9@53.23,44.74 53.621,44.74 53.681,44.68 54.14,44.68 ; U5.H9@53.18,50.34 U5.H9@53.18,50.37 ; U5.N9@53.23,46.34 54.13,46.34
  Top Layer w0.15: U5.K2@47.63,48.74 v1(48.03,49.14) 48.03,49.94 U5.H2@47.63,50.34 ; U5.K8@52.43,48.74 52.85,49.16 53.44,49.16 53.73,49.45 v1(53.97,49.45)
  Top Layer w0.2: L2.2@30.9,62.5 L2.2@31.05,62.5 ; v1@40.25,56.23 40.27,56.23 v1(40.28,56.22) ; 46.162,44.74 U5.R1@46.83,44.74 ; U13.1A8@47.48,32.64 U13.1B7@48.13,31.99 ; U5.B2@47.63,55.14 48.03,54.74 48.03,53.94 ; U13.1B9@48.13,33.29 48.43,32.99 v1@48.43,32.95 ; U13.1B7@48.14,31.99 U13.1B7@48.13,31.99 ; v1@48.47,32.98 48.47,32.95 U13.1C8@48.78,32.64 ; U13.1C8@48.77,32.63 U13.1B7@48.13,31.99 ; U13.1D9@49.43,33.29 v1@49.75,32.97 ; v1@49.73,32.97 v1@49.75,32.97 ; v1@49.75,32.96 v1@49.75,32.97 ; U13.1E8@50.08,32.64 v1@49.75,32.97 ; U13.1F9@50.72,33.31 51.055,32.975 v1(51.055,32.965) 51.065,32.965 U13.1G8@51.36,32.67 ; U13.1H9@52.03,33.29 52.38,32.94 v1@52.38,32.93 ; v1@52.35,32.96 v1@52.38,32.93 ; v1@52.38,32.92 v1@52.38,32.93 ; U13.1J8@52.68,32.64 52.67,32.64 v1@52.38,32.93 ; C18.2@60.22,54.32 C18.2@60.25,54.29 C18.2@60.26,54.28
  Top Layer w0.3: 29.4,62.775 29.4,63.05 29.425,63.075 ; v1(29.9,61.675) 30.689,62.464 L2.2@30.725,62.5 ; L2.2@30.15,62.35 L2.2@29.763,62.737 ; L2.2@30.175,62.375 29.763,62.787 ; C63.2@39.88,36.98 40.48,36.98 v1@40.49,36.99 ; C13.2@43.88,56.12 43.92,56.16 C14.1@44.92,56.16 44.96,56.16 45.03,56.09 v1(46.15,56.09) 46.68,56.09 U5.A1@46.83,55.94 ; C47.1@44.92,45.63 45.94,45.63 v1(45.98,45.59) ; C22.1@44.94,54.24 44.95,54.23 46.07,54.23 v1(46.18,54.34) U5.C1@46.83,54.34 U5.B2@47.63,55.14 ; 46.162,44.752 45.92,44.994 45.92,45.53 v1(45.98,45.59) ; v1(46.18,51.94) U5.F1@46.83,51.94 ; U5.N1@46.83,46.34 46.73,46.34 v1(45.98,45.59) ; U5.D2@47.63,53.54 48.03,53.94 ; v1(51.23,50.74) U5.G7@51.63,51.14 ; U5.H9@53.23,50.34 v1(53.76,50.34) 54.48,50.34 54.53,50.39 C35.1@55.14,50.39 ; U5.E9@53.23,52.74 53.52,53.03 53.52,53.25 U5.D9@53.23,53.54 53.53,53.84 53.53,53.89 ; U5.C9@53.23,54.34 53.53,54.04 53.53,53.89 ; 54.13,46.34 v1(54.58,45.89) 54.61,45.86 C48.1@55.23,45.86 ; 54.14,44.68 v1(54.58,44.24) 54.7,44.12 C57.1@55.23,44.12 ; C11.2@56.39,54.78 56.33,54.84 C17.1@55.3,54.84 55.23,54.91 v1(54.55,54.91) 53.53,53.89 ; v1(59.58,54.32) C18.2@60.22,54.32 ; v1(59.7,34.72) 60.22,34.72 C67.2@60.27,34.77 ; 29.425,63.075 L2.2@29.763,62.737 ; 29.425,63.075 29.425,63.4 C2.2@29.6,63.575 ; C2.2@29.6,63.575 29.763,63.413 29.763,62.787 ; C2.2@29.6,63.575 29.6,62.95 29.763,62.787 ; L2.2@29.763,62.737 29.763,62.787
  Top Layer w0.4: 28.775,58.625 28.95,58.45 ; v1(28.975,61.675) v1(29.45,61.675) v1(29.9,61.675) ; L2.2@30.175,62.375 30.689,62.464 30.9,62.5 L2.2@30.725,62.5 ; C12.2@39.62,56.23 v1@40.25,56.23
  Top Layer w0.5: C6.2@28.475,58.475 C6.2@28.45,58.45 ; C6.2@28.45,58.45 v3@28.8,58.1 ; C6.2@28.45,58.45 28.95,58.45 29.537,57.863 ; v3@28.8,58.1 29.038,57.863 29.288,57.863 ; v3@28.8,58.1 v3(29.05,58.1) 29.288,57.863 ; 29.288,57.863 29.537,57.863 ; 29.288,57.863 29.65,57.5 29.9,57.5 29.537,57.863
  Top Layer w0.6: L2.2@30.101,62.5 L2.2@30.725,62.5
  Signal Layer 1 w0.4: 28.525,61.675 v1(28.975,61.675) v1(29.45,61.675) v1(29.9,61.675)
  Signal Layer 2 w0.4: 28.525,61.675 v1(28.975,61.675) v1(29.45,61.675) v1(29.9,61.675)
  Signal Layer 3 w0.4: 29.75,62.375 30.175,62.375 ; 28.9,63.15 29.4,63.15 ; 28.9,63.15 28.9,63.175 28.525,62.8 28.525,61.675 v1(28.975,61.675) v1@29,61.675 ; 28.9,63.15 28.9,61.775 v1@29,61.675 ; v1@29,61.675 29.3,61.975 29.3,63.05 29.4,63.15 ; v1@29,61.675 v1(29.45,61.675) v1(29.9,61.675) 30.175,61.95 30.175,62.325 ; 29.4,63.15 29.675,62.875 ; 29.675,62.875 30.175,62.375 ; 29.675,62.875 29.675,61.9 29.75,61.9 30.175,62.325 ; 30.175,62.325 30.175,62.375
  Signal Layer 4 w0.2: LNK1.2@38.575,33.075 38.575,32.7 38.675,32.6 39.475,32.6
  Signal Layer 4 w0.3: 28.9,62.15 28.9,59.639 29.269,59.269 28.875,58.875 ; v3(29.05,58.1) 29.05,58.45 28.75,58.75 28.875,58.875 ; 36.079,60.44 34.88,60.44 ; v1(46.15,56.09) 46.15,59.57 45.28,60.44 38.375,60.44 37.94,60.875 37.036,60.875 36.601,60.44 34.88,60.44 ; 28.875,58.875 33.315,58.875 34.88,60.44
  Bottom Layer w0.12: v1(54.55,54.91) v1@54.57,54.89
  Bottom Layer w0.2: C146.2@48.03,32.31 48.03,32.54 v1(48.455,32.965) ; C145.2@49.72,32.31 49.755,32.345 v1(49.755,32.965) ; v1(51.055,32.965) 51.35,32.67 C144.2@51.35,32.37 ; v1(52.355,32.965) 52.97,32.35 C143.2@52.97,32.33
  Bottom Layer w0.4: 28.525,61.675 v1(28.975,61.675) v1(29.45,61.675) v1(29.9,61.675) ; 28.9,63.175 29.03,63.175 29.83,62.375 30.175,62.375
  other v1: 40.55,36.98
VDD_USB: C16.2 C139.2 U4.39 U13.AA15 U13.AA17 | length 40.7
  Top Layer w0.09: v1(53.655,32.94) 54.33,32.94 ; U13.AA15@54.58,32.19 54.33,32.44 54.33,32.586 54.33,32.94 ; U13.AA17@54.58,33.19 54.33,32.94
  Top Layer w0.3: U4.39@35.8,55.275 36.85,55.275 37.85,55.275 ; 38.475,55.1 38.65,54.925
  Top Layer w0.5: 37.6,55.45 37.5,55.45 37.8,55.75 38.095,55.455 38.095,55.34 38.66,54.775 39,54.775 ; 38.85,54.925 39,54.775 ; v3(39.35,54.575) 39.2,54.575 39,54.775
  Signal Layer 3 w0.5: v3(39.35,54.575) 39.824,54.575 40.575,53.824 40.575,53.175 39.275,51.875 39.275,48.32 40.592,47.002 42.643,47.002 43.917,45.728 43.917,43.428 46.67,40.675 50.15,40.675 54.33,36.495 54.33,33.315 53.955,32.94 v1(53.655,32.94)
  Bottom Layer w0.3: v1(53.655,32.94) 54.105,33.39 C139.2@54.255,33.39
VDDA: C32.2 R78.1 U4.20 | length 72.5
  Top Layer w0.2: v3@27.4,51.875 C32.2@27.4,51.925
  Top Layer w0.3: v3@27.375,51.85 27.4,51.875 v3@27.4,51.8 ; C32.2@27.4,51.925 27.4,52.4 28.045,53.045 28.045,53.395 29.125,54.475 U4.20@29.9,54.475 ; v3(57.125,19.1) 57.125,19.4 R78.1@57.525,19.8
  Top Layer w0.5: v3@27.2,51.6 v3(27.475,51.6)
  Top Layer w0.6: v3(26.875,51.6) 27.15,51.875 C32.2@27.15,51.925 ; C32.2@27.15,52.2 C32.2@27.15,51.925 ; v3(27.475,51.6) C32.2@27.15,51.925
  Signal Layer 1 w0.6: v3(26.875,51.6) v3(27.475,51.6)
  Signal Layer 2 w0.3: 26.753,51.175 26.875,51.297 v3(26.875,51.6)
  Signal Layer 2 w0.6: 26.875,51.297 27.178,51.6 v3(27.475,51.6)
  Signal Layer 3 w0.6: 26.725,51.175 27.15,51.6 v3(27.475,51.6)
  Signal Layer 4 w0.5: 26.799,51.175 26.875,51.251 ; v3(26.875,51.6) 26.875,51.251 ; 27.375,51.175 28.176,51.976 28.807,51.976 29.956,53.125 ; v3(57.125,19.1) 57.125,20.07 56.505,20.69 52.048,20.69 51.628,20.27 51.172,20.27 50.752,20.69 50.743,20.69 50.728,20.675 48.07,20.675 46.53,22.215 42.535,22.215 40.925,23.825 40.925,25.807 39.218,27.515 39.218,30.552 37.824,31.946 35.839,31.946 35.03,32.755 35.03,38.215 33.13,40.115 33.13,50.015 30.875,52.27 30.875,52.744 30.494,53.125 29.956,53.125 ; 26.875,51.251 27.974,52.351 29.181,52.351 29.956,53.125
  Signal Layer 4 w0.6: 26.799,51.175 27.375,51.175
  Bottom Layer w0.6: v3(26.875,51.6) v3(27.475,51.6)
VDDA_1V8: C73.2 C149.2 U13.AB14 U13.C14 | length 20.8
  Top Layer w0.09: 45.83,31.94 46.267,31.94 46.367,31.84 ; U13.AB14@55.08,31.69 55.105,31.69 55.36,31.945 56,31.945 56.105,31.84
  Top Layer w0.1: U13.C14@45.58,31.69 45.83,31.94 ; 46.264,31.936 46.36,31.84 46.367,31.84 46.93,31.84 v1(47.105,31.665)
  Top Layer w0.3: 56.105,31.84 57.566,31.84 57.916,31.49 58.88,31.49 v1(59.23,31.14) C73.2@60.005,31.14
  Signal Layer 4 w0.4: v1(47.105,31.665) 47.655,31.665 48.192,32.203 52.595,32.203 52.955,31.843 52.955,31.637 53.34,31.253 59.118,31.253 v1(59.23,31.14)
  Bottom Layer w0.3: C149.2@46.623,31.258 46.698,31.258 v1(47.105,31.665)
VREF+: C1.2 C165.2 R4.2 R74.2 U13.R4 | length 64.7
  Top Layer w0.2: U13.R4@51.58,26.69 51.775,26.885 51.775,27.01 52.005,27.24 v1(52.005,27.34)
  Top Layer w0.3: v3@65.75,61.4 C1.2@65.75,62.25 ; v3(65.775,61.4) 65.784,61.391 R4.2@65.784,60.186
  Top Layer w0.5: v3@55.18,21.84 55.415,22.075 R74.2@55.9,22.075 ; v3@65.75,61.4 v3(65.775,61.4)
  Signal Layer 2 w0.5: v3(51.88,60.59) 63.915,60.59 64.725,61.4 v3@65.75,61.4
  Signal Layer 3 w0.5: v3(51.88,60.59) 51.88,57.94 53.755,56.065 53.755,53.536 54.675,52.616 54.675,48.173 57.55,45.298 57.55,35.921 58.58,34.891 58.58,33.915 v1(52.005,27.34)
  Signal Layer 4 w0.5: v1(52.005,27.34) 55.18,24.165 v3(55.18,21.865)
  Bottom Layer w0.3: C165.2@50.887,27.122 51.787,27.122 v1(52.005,27.34)
VREF_DDR: C15.2 C36.1 C46.1 C68.2 U4.16 U5.H1 U5.M8 U13.AC20 | length 57.3
  Top Layer w0.12: U5.M8@52.38,47.127 U5.M8@52.38,47.14 ; v1@54.56,46.74 v1(54.58,46.72) ; C46.1@55.21,46.72 C46.1@55.23,46.7
  Top Layer w0.16: U5.M8@52.43,47.14 52.83,46.74 v1@54.56,46.74 ; v1(54.58,46.72) C46.1@55.21,46.72
  Top Layer w0.2: U13.AC20@55.58,34.69 55.842,34.69 56.472,35.32 C68.2@57.1,35.32
  Top Layer w0.25: C15.2@27.125,56.1 27.275,56.1 28.392,56.1
  Top Layer w0.3: v3@27.025,55.625 v3(27.025,55.775) ; 28.486,56.075 U4.16@29.9,56.075 ; C36.1@44.91,50.13 45.69,50.13 45.9,50.34 v1(46.18,50.34) U5.H1@46.83,50.34 ; C68.2@57.1,35.32 57.2,35.22 v1(57.2,34.69)
  Top Layer w0.4: v3(27.025,55.775) 27.275,56.025 27.275,56.1 C15.2@27.275,56.375
  Signal Layer 2 w0.3: v3@27.025,55.647 v3(27.025,55.775) v3@27.025,55.675
  Signal Layer 2 w0.5: v3@27.025,55.675 27.975,54.725 35.094,54.725 36.7,53.119 36.7,52.275 37.55,51.425 v3(40.425,51.425)
  Signal Layer 3 w0.5: v3(40.425,51.425) 41.825,51.425 42.91,50.34 v1(46.18,50.34) 46.755,50.915 49.255,50.915 49.855,50.315 49.855,49.135 50.75,48.24 53.04,48.24 v1@54.6,46.68 ; v1(54.58,46.72) 56.805,44.495 56.805,35.085 v1(57.2,34.69) v1@57.2,34.68
VTT_DDR: C9.2 C119.1 C120.1 C121.2 C122.2 C125.1 C126.1 C127.1 C128.1 C129.1 C130.1 C131.1 C132.1 C134.1 C135.1 R115.2 R116.2 R117.2 R118.2 R121.2 R122.2 R123.2 R124.2 R126.2 R128.2 R130.2 R131.2 R132.2 R133.2 R135.2 R138.2 R141.2 R142.2 R143.2 R144.2 R145.2 R146.2 R147.2 R148.2 U4.14 | length 24.9
  Top Layer w0.3: C9.2@28.25,57.375 28.675,57.375 28.725,57.325 ; v3@28.725,57.175 28.725,57.325 ; U4.14@29.9,56.875 29.175,56.875 v3@29.147,56.903 ; C9.2@28.162,57.163 28.713,57.163 v3@28.775,57.1 ; C9.2@28.162,57.163 28.038,57.163 28.175,57.025 C9.2@28.238,57.087 ; C9.2@28.162,57.163 C9.2@28.238,57.087 ; C9.2@28.238,57.087 28.25,57.1 v3@28.775,57.1 ; C9.2@28.238,57.087 28.5,56.825 28.675,56.825 ; 28.675,56.825 v3(28.95,57.1) ; 28.675,56.825 28.695,56.825 28.727,56.857 29.037,56.857 29.062,56.832 29.077,56.832 v3@29.147,56.903 ; 28.725,57.325 28.975,57.325 29.175,57.125 29.175,56.93 v3@29.147,56.903 ; 28.725,57.325 v3(28.95,57.1) ; v3@28.775,57.1 v3(28.95,57.1) ; v3(28.95,57.1) v3@29.147,56.903
  Top Layer w0.5: v3@28.713,57.163 v3@28.725,57.175
  Signal Layer 4 w0.5: v3(28.95,57.1) 28.95,56.64 29.365,56.225 32.25,56.225 33.04,57.015 33.64,57.015 35.4,58.775 41.59,58.775 v3(42.23,59.415)
  Bottom Layer w0.5: v3(42.23,59.415) 42.825,58.82 C120.1@42.825,57.75 42.825,57.15 42.675,57 C122.2@42.675,56.2
WL_HOST_WAKE: U8.27 U13.B8 | length 54.7
  Top Layer w0.09: 44.205,28.44 44.83,28.44 U13.B8@45.08,28.69
  Top Layer w0.1: U8.27@6.575,46.9 v1(7.475,46.9) ; v1(38.605,27.49) 39.112,27.49 39.486,27.115 40.127,27.115 40.327,26.915 41.059,26.915 42.107,27.963 42.367,27.963 42.719,28.315 43.639,28.315 43.764,28.44 44.205,28.44
  Signal Layer 3 w0.1: v1(31.68,40.29) 33.105,38.865 33.105,35.373 32.93,35.198 32.93,33.564 33.428,33.066 34.754,33.066 36.975,30.845 36.975,28.825 38.31,27.49 v1(38.605,27.49)
  Bottom Layer w0.1: v1(7.475,46.9) 9.75,46.9 10.2,47.35 10.8,47.35 11.1,47.05 12.125,47.05 13.625,45.55 13.625,41.908 13.983,41.55 17.325,41.55 17.5,41.725 24.237,41.725 25.672,40.29 v1(31.68,40.29)
WL_REG_ON: TP24.1 U8.28 U13.B3 | length 57.9
  Top Layer w0.09: 44.28,25.94 44.83,25.94 U13.B3@45.08,26.19
  Top Layer w0.1: U8.28@6.575,47.35 v1(8.75,47.35) ; v1(34.98,26.965) 35.33,26.615 35.727,26.615 36.636,25.706 37.063,25.706 37.227,25.541 38.087,25.541 38.663,24.965 39.947,24.965 40.097,25.115 43.125,25.115 43.455,25.445 43.455,25.697 43.698,25.94 44.28,25.94
  Signal Layer 3 w0.1: v1(29.955,40.69) 29.955,39.743 31.204,38.494 31.204,36.449 30.925,36.169 30.925,32.592 32.251,31.266 33.231,31.266 33.75,30.746 33.75,29.131 34.98,27.902 v1(34.98,26.965)
  Bottom Layer w0.1: v1(8.75,47.35) 9.475,48.075 11.975,48.075 13.825,46.225 13.825,41.991 14.066,41.75 17.025,41.75 17.2,41.925 TP24.1@17.5,42.225 ; TP24.1@17.575,42.225 17.875,41.925 24.32,41.925 25.755,40.49 29.755,40.49 v1(29.955,40.69)
pads on no net: CN6.0 CN6.A2 CN6.A3 CN6.A6 CN6.A7 CN6.A8 CN6.A10 CN6.A11 CN6.B2 CN6.B3 CN6.B6 CN6.B7 CN6.B8 CN6.B10 CN6.B11 CN7.0 CN7.A2 CN7.A3 CN7.A8 CN7.A10 CN7.A11 CN7.B2 CN7.B3 CN7.B8 CN7.B10 CN7.B11 CN8.17 CN8.18 CN9.14 CN10.NPTH1 CN10.NPTH2 CN15.11 CN15.12 CN15.13 CN15.14 CN16.1 CN16.8 L1.2 MIRE-PLACE-1.1 MIRE-PLACE-2.1 MIRE-PLACE-3.1 MIRE-PLACE-4.1 MIRE-PLACE-5.1 MIRE-PLACE-6.1 U1.4 U2.4 U4.34 U4.35 U4.38 U5.J1 U5.J9 U5.L1 U5.L9 U5.M7 U6.4 U8.13 U8.15 U8.16 U9.4 U10.4 U10.5 U10.6 U10.7 U12.16 U12.17 U12.19 U13.A21 U13.A22 U13.AA20 U13.AA22 U13.AA23 U13.AB20 U13.AB21 U13.AB22 U13.AB23 U13.AC19 U13.AC21 U13.AC22 U13.B21 U13.B22 U13.B23 U13.C22 U13.C23 U13.D21 U13.D22 U13.D23 U13.E23 U13.P20 U13.Y22 U13.Y23 U14.36 U14.37 U14.38 U14.39 U14.40 U19.4 U19.11 U19.14 U19.16 U19.17 U19.19 U19.21 U19.22 U19.28 U19.29 U19.40 U19.41 U19.42 U19.43 U19.45 U19.46 U20.19 U20.20 U20.23 U20.24 U29.4 U33.5 X2.2 X2.4

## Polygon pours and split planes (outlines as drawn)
GND on Bottom Layer "GND_L06_P124" (solid, remove dead copper, pour order 124): 40.75,71 40.75,58.75 59.438,58.75 59.438,71
GND on Bottom Layer "GND_L06_P123" (solid, remove dead copper, pour order 123): 0,71 42.25,71 42.25,44.93 39.83,42.51 39.83,40.5 39.795,40.465 39.795,34.591 47.996,26.39 53.53,26.39 54.586,27.446 54.586,31.776 56.19,33.38 59.145,33.38 60.26,34.495 60.26,43.1 59.61,43.75 58.25,43.75 58.25,71 101,71 101,0 0,0
VTT_DDR on Bottom Layer "Bottom Layer-No Net" (solid, pour order 98): 44.185,44.15 42.43,44.15 42.43,58.15 58.014,58.15 58.015,43.475 57.155,43.475 56.335,43.475 56.275,56.875 44.185,56.875
NetC69_2 on Bottom Layer "NETC69_2_L06_P093" (solid, remove dead copper, pour order 93): 8.125,33.025 7.92,32.82 7.92,30.13 8.182,29.868 13.693,29.868 14.125,30.3 14.125,32.725 13.825,33.025
GND on Signal Layer 4 "GND_L05_P115" (solid, remove dead copper, pour order 115): 68.83,35.19 65.83,32.19 65.83,25.295 66.58,24.545 66.58,17.69 66.58,14.94 68.08,13.44 68.08,11.69 69.33,10.44 74.08,10.44 74.58,10.94 75.853,10.94 76.08,11.167 76.08,19.92 79.33,23.17 79.33,31.44 75.58,35.19
5V_VIN on Signal Layer 4 "5V_VIN_L05_P114" (solid, remove dead copper, pour order 114): 76.455,11.065 76.455,19.565 79.83,22.94 79.83,31.44 75.58,35.69 71.58,35.69 71.08,36.19 71.08,37.363 74.83,41.113 74.83,66.44 75.33,66.94 76.58,66.94 77.12,66.4 77.12,65.65 79.33,63.44 83.33,63.44 84.58,62.19 84.58,36.021 89.33,31.271 89.33,25.32 91.83,22.82 91.83,0.63 91.2,0 65.175,0 64.58,0.595 64.58,7.69 63.33,8.94 58.53,8.94 56.655,7.065 52.815,7.065 52.33,7.55 52.33,7.94 52.83,8.44 54.33,8.44 55.08,7.69 55.575,7.69 56.08,8.19 56.08,8.365 58.155,10.44 75.83,10.44
GND on Signal Layer 4 "GND_L05_P112" (solid, remove dead copper, pour order 112): 34.08,41.69 33.58,41.19 33.58,29.975 34.115,29.44 37.83,29.44 40.83,26.44 40.83,18.94 41.33,18.44 46.83,18.44 47.08,18.69 47.08,20.195 47.575,20.69 55.22,20.69 55.58,21.05 55.58,23.065 51.205,27.44 47.33,27.44 46.33,28.44 46.33,31.19 45.58,31.94 38.82,31.94 38.33,32.43 38.33,41.19 37.83,41.69
3V3 on Signal Layer 4 "3V3_L05_P111" (solid, remove dead copper, pour order 111): 73.191,61.19 74.58,59.801 74.58,41.69 65.08,32.19 65.08,25.19 66.08,24.19 66.08,17.94 66.08,12.69 64.08,10.69 57.905,10.69 55.905,8.69 55.905,8.415 55.905,8.275 55.57,7.94 55.08,7.94 54.33,8.69 54.155,8.69 52.83,8.69 52.08,7.94 52.08,7.3 52.44,6.94 56.83,6.94 58.58,8.69 63.08,8.69 63.33,8.44 62.58,7.69 60.595,7.69 60.337,7.432 60.088,7.432 59.83,7.69 59.08,7.69 57.58,6.19 49.15,6.19 48.9,6.44 46.33,6.44 46.08,6.69 46.08,7.825 46.445,8.19 49.83,8.19 50.08,7.94 51.08,7.94 51.33,8.19 51.33,15.44 48.08,18.69 47.58,18.69 47.33,18.94 47.33,19.94 47.58,20.19 56.085,20.19 56.58,19.695 56.58,18.69 57.08,18.19 60.08,18.19 60.58,18.69 60.58,21.94 60.58,23.94 60.33,24.19 58.33,26.19 58.33,28.94 61.58,32.19 61.58,60.19 62.58,61.19
3V3 on Signal Layer 4 "3V3_L05_P108" (solid, remove dead copper, pour order 108): 49.584,66.94 49.125,66.481 49.125,65.3 48.675,64.85 46.725,64.85 46.175,65.4 46.175,66.655 45.89,66.94 28.925,66.94 28.925,64.75 26.935,64.75 22.05,59.865 22.05,55.97 24.83,53.19 24.83,52.69 24.58,52.44 24.33,52.44 22.83,50.94 22.83,49.95 14.83,41.95 14.83,38.94 13.33,37.44 10.58,37.44 10.08,36.94 10.08,35.94 12.33,33.69 16.58,33.69 18.58,35.69 21,35.69 27.08,41.77 27.08,44.94 28.58,46.44 28.58,47.44 29.08,47.94 29.08,48.94 28.83,49.19 27.83,49.19 27.58,49.44 27.58,49.94 27.83,50.19 30.58,50.19 32.255,48.515 32.255,33.515 40.08,25.69 40.08,16.19 39.08,15.19 28.33,15.19 25.33,12.19 25.33,7.19 26.08,6.44 37.58,6.44 39.08,4.94 47.08,4.94 47.58,4.44 59.33,4.44 60.08,5.19 60.08,8.19 60.33,8.44 63.33,8.44 64.08,7.69 64.08,0.68 63.4,0 0.08,0 0.08,43.325 9.695,52.94 15.33,52.94 16.08,53.69 16.08,69.69 17.33,70.94 77.08,70.94 77.08,68.44 76.33,67.69 72.33,67.69 71.58,66.94
5V_VIN on Signal Layer 4 "5V_VIN_L05_P107" (solid, remove dead copper, pour order 107): 73.11,61.69 75.15,59.65 75.925,59.65 76.825,60.55 76.825,66.695 76.338,67.182 73.5,67.19 72.58,67.19 71.83,66.44 49.6,66.44 49.278,66.102 49.278,65.202 48.75,64.675 46.6,64.675 45.99,65.285 45.99,66 45.55,66.44 32.575,66.44 32.025,67 31.33,67 31.33,69.17 31.075,69.425 26.6,69.425 26.6,67.182 28.958,67.182 28.957,64.675 26.315,64.675 22.33,60.69 22.33,55.94 25.08,53.19 25.08,52.69 23.33,50.94 23.33,49.69 15.33,41.69 15.33,38.875 13.395,36.94 10.83,36.94 10.58,36.69 10.58,36.19 12.58,34.19 16.33,34.19 18.33,36.19 20.83,36.19 26.6,41.96 26.6,44.96 28.33,46.69 28.33,47.69 28.58,47.94 28.58,48.69 28.33,48.94 27.58,48.94 27.08,49.44 27.08,50.125 27.645,50.69 31.33,50.69 33.58,48.44 33.58,42.44 34.08,41.94 38.33,41.94 39.025,42.635 39.025,55.415 37.555,55.415 36.83,55.05 36.83,50.19 37.83,49.19 37.83,44.94 37.58,44.69 36.33,44.69 35.83,45.19 35.83,48.945 34.975,49.8 34.975,52.545 31.83,55.69 28.84,55.69 27.33,57.2 27.33,58.44 27.83,58.94 27.83,62.975 30.658,62.975 31.08,62.553 31.08,60.44 31.58,59.94 32.83,59.94 34.58,61.69
VDD on Signal Layer 4 "VDD_L05_P106" (solid, remove dead copper, pour order 106): 38.58,58.94 39.1,58.42 39.1,56.38 36.58,55.11 36.58,50.07 37.58,49.07 37.58,45.19 37.33,44.94 36.33,44.94 36.08,45.19 36.08,48.82 33.775,51.125 33.775,57.135 35.58,58.94
VDD_DDR on Signal Layer 4 "VDD_DDR_L05_P105" (solid, remove dead copper, pour order 105): 43.08,59.44 35.145,59.44 31.78,56.075 28.945,56.075 27.58,57.44 27.58,58.19 27.83,58.44 27.83,62.655 30.58,62.655 30.58,60.195 31.335,59.44 32.83,59.44 34.58,61.19 43.08,61.19
VDD_DDR on Signal Layer 4 "VDD_DDR" (solid, pour order 99): 39.075,61.19 61.25,61.19 61.25,32.47 39.075,32.47
VDD on Signal Layer 4 "VDD_L05_P110" (solid, remove dead copper, pour order 110): 52.33,31.44 50.58,29.69 50.58,28.665 57.58,21.665 57.58,18.69 57.83,18.44 59.83,18.44 60.125,18.735 60.125,21.985 60.13,23.89 60.08,23.94 52.58,31.44
NetC69_2 on Signal Layer 4 "NETC69_2_L05_P091" (solid, remove dead copper, pour order 91): 9.125,33 9,32.875 9,30.175 9.25,29.925 11.475,29.925 12.878,31.328 13.828,31.328 14.1,31.6 14.1,32.1 13.95,32.25 11.3,32.25 10.55,33 10.03,33
VDD_CORE on Signal Layer 4 "VDD_CORE_L05_P109" (solid, remove dead copper, pour order 109): 52.08,31.94 52.08,31.69 50.08,29.69 50.08,28.19 49.824,27.934 47.33,27.934 46.83,28.44 46.83,31.41 47.36,31.94 47.43,31.94
GND on Signal Layer 4 "GND_L05_P117" (solid, remove dead copper, pour order 117): 77.33,70.69 77.33,66.19 79.58,63.94 83.58,63.94 85.08,62.44 85.08,36.19 89.83,31.44 89.83,25.44 92.33,22.94 92.33,0.52 92.85,0 100.83,0 100.83,70.69
GND on Signal Layer 4 "GND_L05_P104" (solid, remove dead copper, pour order 104): 0.08,44.44 0.824,44.44 9.734,53.35 14.99,53.35 15.58,53.94 15.58,70.94 0.08,70.94
GND on Signal Layer 4 "GND_L05_P113" (solid, remove dead copper, pour order 113): 53.29,32.19 53.29,32.178 52.955,31.843 52.955,31.633 55.148,29.44 58.33,29.44 59.83,30.94 59.83,31.94 59.58,32.19
VDD on Signal Layer 4 "VDD_L05_P102" (solid, remove dead copper, pour order 102): 38.165,8.44 37.95,8.225 37.95,6.82 38.08,6.69 39.58,5.19 47.33,5.19 47.83,4.69 59.08,4.69 59.83,5.44 59.83,7.275 59.665,7.44 59.08,7.44 57.48,5.84 49.25,5.84 48.9,6.19 46.08,6.19 45.58,6.69 40.83,6.69 39.08,8.44
AGND on Signal Layer 4 "AGND_L05_P103" (solid, remove dead copper, pour order 103): 28.83,14.69 25.83,11.69 25.83,7.395 26.285,6.94 36.315,6.94 38.215,8.84 39.18,8.84 41.02,7 45.28,7 45.83,7.55 45.83,8.175 46.095,8.44 49.9,8.44 50.15,8.19 50.83,8.19 51.08,8.44 51.08,15.32 48.05,18.35 40.99,18.35 40.83,18.19 40.83,16.44 39.08,14.69
GND on Signal Layer 3 "GND_L04_P122" (solid, remove dead copper, pour order 122): 61.823,5.048 56.75,5.05 56.75,0 101,0 101,71 78.5,71 77.75,70.25 77.75,54.25 76.25,52.75 64.282,52.75 63.75,53.282 63.75,55 64.75,56 66.75,56 72.75,62 72.75,63.75 73,64 73,71 35.725,71 35.725,48.3 53.75,30.275 53.75,28.54 50.437,25.227 44.788,25.227 35.725,34.29 35.725,71 0,71 0,3 56.75,3 56.75,14.25 58,15.5 58,19.523 58.728,20.25 62.55,20.25 63.3,19.5 63.3,6.525
VDD_CORE on Signal Layer 3 "VDD_CORE_L04_P119" (solid, remove dead copper, pour order 119): 52.08,31.44 50.33,29.69 50.33,28.19 50.08,27.94 48.46,27.94 42.58,33.82 42.58,34.44 42.33,34.69 40.83,34.69 38.08,37.44 38.08,45.69 37.58,46.19 36.33,46.19 35.65,46.87 35.65,64.125 41.08,64.125 41.08,46.44 41.08,42.69 52.08,31.69
VDD on Signal Layer 3 "VDD_L04_P118" (solid, remove dead copper, pour order 118): 52.33,31.44 50.58,29.69 50.58,28.19 50.08,27.69 47.33,27.69 42.33,32.69 42.33,34.19 42.08,34.44 40.58,34.44 37.58,37.44 37.58,45.69 37.33,45.94 35.83,45.94 35.58,45.69 35.58,35.44 45.33,25.69 51.24,25.69 53.975,28.425 53.975,30.545 53.08,31.44
VDD on Signal Layer 3 "VDD_L04_P126" (solid, remove dead copper, pour order 126): 59.33,19.8 58.625,19.095 58.625,15.2 57.525,14.1 57.525,6.145 58.07,5.6 61.699,5.6 62.575,6.476 62.575,19.34 62.1,19.815
NetC69_2 on Signal Layer 3 "NETC69_2_L04_P090" (solid, remove dead copper, pour order 90): 8.475,33.05 8.33,32.905 8.33,30.095 8.45,29.975 13.45,29.975 13.922,30.447 13.922,32.628 13.5,33.05
GND on Signal Layer 2 "GND_L03_P120" (solid, remove dead copper, pour order 120): 0,71 101,71 101,0 0,0
NetC69_2 on Signal Layer 2 "NETC69_2_L03_P095" (solid, remove dead copper, pour order 95): 9.712,33.077 8.527,33.077 8.205,32.755 8.205,30.295 8.525,29.975 13.325,29.975 13.922,30.572 13.922,32.603 13.45,33.075
1V8_AUDIO on Top Layer "Top Layer-No Net 4" (solid, pour order 138): 30.65,53.375 30.325,53.375 30.25,53.3 30.25,53.098 29.4,52.248 29.4,51.75 29.975,51.75 30.425,52.2 30.475,52.2 30.475,52.475 30.6,52.6 30.65,52.6 30.65,53.375 30.527,53.375
VDD_DDR on Top Layer "Top Layer-No Net 3" (solid, pour order 136): 30.275,57.475 28.925,58.825 28,58.825 28,58.2 28.575,58.2 29.5,57.275 29.525,57.25 30.275,57.25
5V_VIN on Top Layer "Top Layer-No Net 2" (solid, pour order 134): 30.75,57.525 30.55,57.525 28.75,59.325 26.575,59.325 26.575,60.459 28.525,60.35 28.85,60.35 28.85,60.073 29.123,59.8 29.4,59.8 30.75,58.45
NetL3_1 on Top Layer "Top Layer-No Net 1" (solid, pour order 132): 32.654,58.649 32.705,58.7 33.349,58.727 33.696,58.791 34.034,59.129 33.903,60.345 32.523,58.625
5V_VIN on Top Layer "Top Layer-No Net" (solid, pour order 128): 30.725,57.525 30.75,57.55 30.75,58.525
GND on Top Layer "GND_L01_P100" (solid, remove dead copper, pour order 100): 0.328,0 101.328,0 101.328,71 0.328,71
NetC69_2 on Top Layer "NETC69_2_L01_P092" (solid, remove dead copper, pour order 92): 11.8,33.55 11.2,32.95 11.2,29.95 11.475,29.675 12.775,29.675 12.85,29.75 12.85,30.517 14.125,31.792 14.125,33.55
5V_VIN on Top Layer "5V_VIN_L01_P096" (solid, remove dead copper, pour order 96): 10.7,37.65 10.548,37.498 10.548,35.677 10.777,35.448 11.804,35.448 12.375,36.019 12.375,36.5 12.775,36.9 12.775,37.5 12.625,37.65
NetC66_2 on Top Layer "NETC66_2_L01_P094" (solid, remove dead copper, pour order 94): 82.125,36.95 81.98,36.805 81.98,33.72 82.275,33.425 88.625,33.425 88.825,33.625 88.825,36.65 88.525,36.95
NetC71_2 on Top Layer "NETC71_2_L01_P089" (solid, remove dead copper, pour order 89): 13.735,36.375 13.55,36.19 13.55,35.3 13.625,35.225 14,35.225 14.525,34.7 14.525,32.175 14.75,31.95 17.1,31.95 17.45,32.3 17.45,33.475 17.65,33.675 18.025,33.675 18.575,34.225 18.575,36.175 18.375,36.375
5V_VIN on Top Layer "5V_VIN_L01_P097" (solid, remove dead copper, pour order 97): 16.5,41.3 16.492,41.308 15.383,41.308 15.2,41.125 15.2,37.575 15.9,36.875 17.925,36.875 18.55,37.5 18.55,41.3
GND on Signal Layer 1 "GND_L02_P101" (solid, remove dead copper, pour order 101): 0,71 100.975,71 100.975,0 0,0

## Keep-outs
Keep-Out Layer:
  rectangle: 7.175,0.9 15.675,2.65

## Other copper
Top Layer:
  region: 2.625,70.275 2.625,62.575 3.175,62.575 3.175,70.275
  rectangle: 2.625,69.725 13.675,70.275
  pour cut-out: 66.442,43.742 64.85,42.15 64.85,41.6 64.15,40.9 64.15,39.8 69.75,39.8 69.75,41 69.35,41.4 69.35,41.925 67.533,43.742
  pour cut-out: 19.345,26.812 15.45,26.812 15.45,23.8 15.5,23.75 21.5,23.75 22,24.25 22,26.1 21.6,26.5 19.657,26.5
  pour cut-out: 60.025,19.445 60.025,22.098 60.042,22.115 59.908,22.25 58.876,22.25 58.75,22.124 58.75,19.697 59,19.447
  pour cut-out: 48.5,14.915 48.75,14.665 50.538,14.665 50.738,14.465 50.738,8.338 50.082,7.682 48.093,7.682 47,8.775 47,14.904 46.42,14.904 45.875,15.45 45.875,16.375 46.5,17 48.5,17
  pour cut-out: 65.37,23.038 65.37,21.205 66.45,20.125 66.45,19.175 65.85,18.575 64.675,18.575 64.5,18.75 64.5,20.359 64.25,20.609 64.066,20.609 63.969,20.512 63.458,20.512 63.055,20.915 63.055,22.175 64.12,23.24 65.37,23.24
  pour cut-out: 46.25,20.275 46.575,19.95 50.51,19.95 50.952,20.392 50.952,21.548 50.299,22.201 46.811,22.201 46.25,21.64
  pour cut-out: 61.25,14.25 61.5,14 65.8,14 65.8,15.7 65.5,16 61.25,16
  pour cut-out: 46.14,57.35 43.4,57.35 43.24,57.35 42.5,56.61 42.5,27 44.26,25.24 57.27,25.24 59.06,27.03 59.06,42.251 58,43.311 58,56.75 57.4,57.35
  text "1" at 7.425,1.15 h2
  text ".Layer_Name" at 14.068,-11.217 h3
  text ".GTL" at 55.763,-11.217 h3
Signal Layer 1:
  text "2" at 8.675,1.15 h2
  text ".Layer_Name" at 14.068,-11.217 h3
  text ".G1" at 55.763,-11.217 h3
Signal Layer 2:
  pour cut-out: 44.66,57.66 43,56 43,45.25 39.25,41.5 39.25,37.272 43.272,33.25 55.244,33.25 57.75,35.756 57.75,56.53 56.62,57.66
  text "3" at 10.175,1.15 h2
  text ".Layer_Name" at 14.068,-11.217 h3
  text ".G2" at 55.763,-11.217 h3
Signal Layer 3:
  text "4" at 12.425,1.15 h2
  text ".Layer_Name" at 14.1,-11.2 h3
  text ".G3" at 55.795,-11.2 h3
Signal Layer 4:
  text "5" at 13.925,1.15 h2
  text ".Layer_Name" at 14.1,-11.2 h3
  text ".G4" at 55.795,-11.2 h3
Bottom Layer:
  text "6" at 15.425,1.15 h2
  text ".GBL" at 44.56,-11.249 h3
  text ".Layer_Name" at 85.874,-11.249 h3
Multi-Layer:
  pour cut-out: 0,71 0,60.875 14.275,60.875 14.275,71

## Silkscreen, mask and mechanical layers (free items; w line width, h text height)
Top Overlay:
  drawing of 1520 lines, arcs and shapes, not listed
  text "GPIO" at 69.925,63.5 h1.7
  text "USB" at 95.15,53.925 h1.7
  text "GND" at 41.5,45.925 h1.2
  text "DSI" at 25.75,38.825 h1.7
  text "MB1272C" at 29.675,37.75 h2
  text "PWR_IN" at 0.65,36.7 h1.7
  text "USB" at 95.075,35.875 h1.7
  text "USB" at 95.075,21.975 h1.7
  text "HDMI" at 95.075,18.25 h1.7
  text "AUDIO" at 30.475,15.825 h1.7
  text "ST-LINK" at 72.4,6.575 h1.7
  text "ETHERNET" at 1.125,3.825 h1.7
  text "USER2" at 57.325,1.35 h1.7
  text "RESET" at 41.575,1.3 h1.7
  text "USER1" at 49.6,1.3 h1.7
  text "WAKE UP" at 18.85,1.275 h1.7
  text ".Layer_Name" at 14.068,-11.217 h3
  text ".GTO" at 55.763,-11.217 h3
Bottom Overlay:
  drawing of 246 lines, arcs and shapes, not listed
  text "D10" at 51.225,62.9 h1.7 r270
  text "D0" at 24.3,62.875 h1.7 r270
  text "D2" at 29.375,62.875 h1.7 r270
  text "D4" at 34.4,62.875 h1.7 r270
  text "D6" at 39.525,62.875 h1.7 r270
  text "D8" at 46.2,62.875 h1.7 r270
  text "GND" at 61.35,62.875 h1.5 r270
  text "D14" at 66.45,62.875 h1.7 r270
  text "D12" at 56.3,62.85 h1.7 r270
  text "AVDD" at 65.225,59.025 h1.5
  text "D11" at 54.925,58.95 h1.7
  text "D13" at 60.025,58.925 h1.7
  text "D7" at 42.725,58.9 h1.7
  text "D9" at 49.75,58.9 h1.7
  text "D15" at 70.2,58.9 h1.7
  text "D3" at 33.05,58.825 h1.7
  text "D1" at 27.875,58.775 h1.7
  text "D5" at 37.025,58.225 h1.7 r270
  text "MICRO SD CARD" at 14.35,53.725 h1.7
  text "RoHS" at 32.795,47.04 h1.6
  text "COMPLIANT" at 33.195,45.64 h0.8
  text "2002/95/EC" at 33.695,44.34 h0.8
  text "STM32" at 32,33.95 h1.5
  text "BOOT0" at 95.525,15.475 h1.7 r270
  text "BOOT2" at 97.15,15.45 h1.7 r270
  text "3V3" at 54.8,14.65 h1.7 r270
  text "IOREF" at 57.45,14.65 h1.7 r270
  text "GND" at 49.725,14.625 h1.7 r270
  text "A5" at 26.85,14.6 h1.7 r270
  text "A3" at 31.95,14.6 h1.7 r270
  text "VIN" at 44.675,14.6 h1.7 r270
  text "A1" at 37.025,14.575 h1.7 r270
  text "A2" at 34.5,10.025 h1.7 r270
  text "A4" at 29.425,9.975 h1.7 r270
  text "A0" at 39.525,9.975 h1.7 r270
  text "5V" at 52.35,9.975 h1.7 r270
  text "GND" at 47.25,8.575 h1.7 r270
  text "NRST" at 57.375,7.7 h1.7 r270
  text "IO" at 88.7,3.3 h1.7 r270
  text "GND" at 86.275,3.025 h1.7 r270
  text "3V3" at 81.175,2.895 h1.7 r270
  text "TCK" at 83.725,2.895 h1.7 r270
  text ".GBO" at 44.56,-11.249 h3
  text ".Layer_Name" at 85.874,-11.249 h3
Top Paste:
  text ".Layer_Name" at 14.068,-11.217 h3
  text ".GTP" at 55.763,-11.217 h3
Bottom Paste:
  text ".GBP" at 44.56,-11.249 h3
  text ".Layer_Name" at 85.874,-11.249 h3
Top Solder:
  rectangle: 7.175,0.9 15.675,2.65
  text ".Layer_Name" at 14.068,-11.217 h3
  text ".GTS" at 55.763,-11.217 h3
Bottom Solder:
  rectangle: 7.175,0.9 15.675,2.65
  text ".GBS" at 44.56,-11.249 h3
  text ".Layer_Name" at 85.874,-11.249 h3
M1-Board Shape:
  the board outline again, w0.1
M2-Board Dimensions:
  text ".Layer_Name" at 14.068,-11.217 h3
  text ".GM2" at 55.763,-11.217 h3
M14-Top Assembly:
  text ".Layer_Name" at 14.068,-11.217 h3
  text ".GM14" at 55.763,-11.217 h3
M15-Bottom Assembly:
  text ".GM15" at 44.56,-11.249 h3
  text ".Layer_Name" at 85.874,-11.249 h3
